VERSION 5.8 ;
BUSBITCHARS "[]" ;
DIVIDERCHAR "/" ;
UNITS
    DATABASE MICRONS 1000 ;
END UNITS

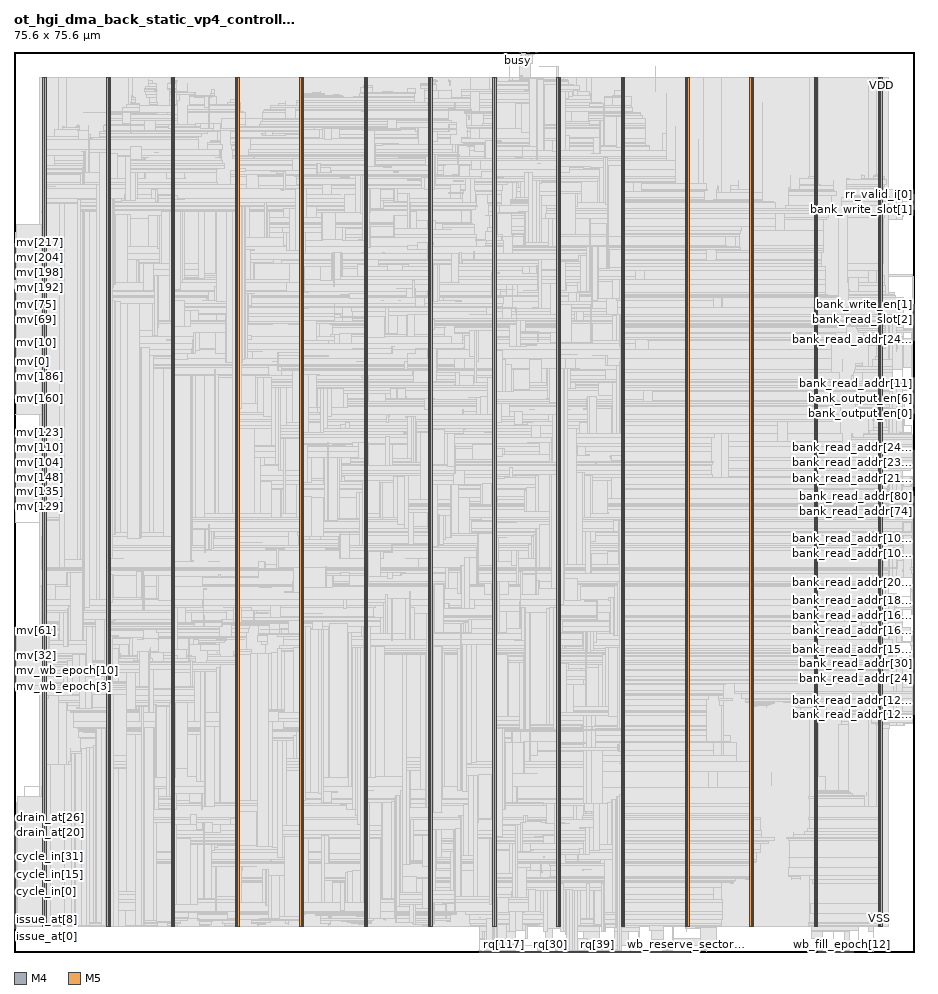
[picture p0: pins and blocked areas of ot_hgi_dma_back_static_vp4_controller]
MACRO ot_hgi_dma_back_static_vp4_controller
  FOREIGN ot_hgi_dma_back_static_vp4_controller 0 0 ;
  CLASS BLOCK ;
  SIZE 75.6 BY 75.6 ;
  PIN bank_output_en[0]
    DIRECTION OUTPUT ;
    USE SIGNAL ;
    PORT
      LAYER M4 ;
        RECT  75.516 45.264 75.6 45.288 ;
    END
  END bank_output_en[0]
  PIN bank_output_en[1]
    DIRECTION OUTPUT ;
    USE SIGNAL ;
    PORT
      LAYER M4 ;
        RECT  75.516 45.36 75.6 45.384 ;
    END
  END bank_output_en[1]
  PIN bank_output_en[2]
    DIRECTION OUTPUT ;
    USE SIGNAL ;
    PORT
      LAYER M4 ;
        RECT  75.516 45.456 75.6 45.48 ;
    END
  END bank_output_en[2]
  PIN bank_output_en[3]
    DIRECTION OUTPUT ;
    USE SIGNAL ;
    PORT
      LAYER M4 ;
        RECT  75.516 45.552 75.6 45.576 ;
    END
  END bank_output_en[3]
  PIN bank_output_en[4]
    DIRECTION OUTPUT ;
    USE SIGNAL ;
    PORT
      LAYER M4 ;
        RECT  75.516 45.648 75.6 45.672 ;
    END
  END bank_output_en[4]
  PIN bank_output_en[5]
    DIRECTION OUTPUT ;
    USE SIGNAL ;
    PORT
      LAYER M4 ;
        RECT  75.516 45.744 75.6 45.768 ;
    END
  END bank_output_en[5]
  PIN bank_output_en[6]
    DIRECTION OUTPUT ;
    USE SIGNAL ;
    PORT
      LAYER M4 ;
        RECT  75.516 45.84 75.6 45.864 ;
    END
  END bank_output_en[6]
  PIN bank_output_en[7]
    DIRECTION OUTPUT ;
    USE SIGNAL ;
    PORT
      LAYER M4 ;
        RECT  75.516 45.936 75.6 45.96 ;
    END
  END bank_output_en[7]
  PIN bank_read_addr[0]
    DIRECTION OUTPUT ;
    USE SIGNAL ;
    PORT
      LAYER M4 ;
        RECT  75.516 46.032 75.6 46.056 ;
    END
  END bank_read_addr[0]
  PIN bank_read_addr[100]
    DIRECTION OUTPUT ;
    USE SIGNAL ;
    PORT
      LAYER M4 ;
        RECT  75.516 33.36 75.6 33.384 ;
    END
  END bank_read_addr[100]
  PIN bank_read_addr[101]
    DIRECTION OUTPUT ;
    USE SIGNAL ;
    PORT
      LAYER M4 ;
        RECT  75.516 33.456 75.6 33.48 ;
    END
  END bank_read_addr[101]
  PIN bank_read_addr[102]
    DIRECTION OUTPUT ;
    USE SIGNAL ;
    PORT
      LAYER M4 ;
        RECT  75.516 33.552 75.6 33.576 ;
    END
  END bank_read_addr[102]
  PIN bank_read_addr[103]
    DIRECTION OUTPUT ;
    USE SIGNAL ;
    PORT
      LAYER M4 ;
        RECT  75.516 33.648 75.6 33.672 ;
    END
  END bank_read_addr[103]
  PIN bank_read_addr[104]
    DIRECTION OUTPUT ;
    USE SIGNAL ;
    PORT
      LAYER M4 ;
        RECT  75.516 33.744 75.6 33.768 ;
    END
  END bank_read_addr[104]
  PIN bank_read_addr[105]
    DIRECTION OUTPUT ;
    USE SIGNAL ;
    PORT
      LAYER M4 ;
        RECT  75.516 33.84 75.6 33.864 ;
    END
  END bank_read_addr[105]
  PIN bank_read_addr[106]
    DIRECTION OUTPUT ;
    USE SIGNAL ;
    PORT
      LAYER M4 ;
        RECT  75.516 33.936 75.6 33.96 ;
    END
  END bank_read_addr[106]
  PIN bank_read_addr[107]
    DIRECTION OUTPUT ;
    USE SIGNAL ;
    PORT
      LAYER M4 ;
        RECT  75.516 34.032 75.6 34.056 ;
    END
  END bank_read_addr[107]
  PIN bank_read_addr[108]
    DIRECTION OUTPUT ;
    USE SIGNAL ;
    PORT
      LAYER M4 ;
        RECT  75.516 34.128 75.6 34.152 ;
    END
  END bank_read_addr[108]
  PIN bank_read_addr[109]
    DIRECTION OUTPUT ;
    USE SIGNAL ;
    PORT
      LAYER M4 ;
        RECT  75.516 34.224 75.6 34.248 ;
    END
  END bank_read_addr[109]
  PIN bank_read_addr[10]
    DIRECTION OUTPUT ;
    USE SIGNAL ;
    PORT
      LAYER M4 ;
        RECT  75.516 46.992 75.6 47.016 ;
    END
  END bank_read_addr[10]
  PIN bank_read_addr[110]
    DIRECTION OUTPUT ;
    USE SIGNAL ;
    PORT
      LAYER M4 ;
        RECT  75.516 34.32 75.6 34.344 ;
    END
  END bank_read_addr[110]
  PIN bank_read_addr[111]
    DIRECTION OUTPUT ;
    USE SIGNAL ;
    PORT
      LAYER M4 ;
        RECT  75.516 34.416 75.6 34.44 ;
    END
  END bank_read_addr[111]
  PIN bank_read_addr[112]
    DIRECTION OUTPUT ;
    USE SIGNAL ;
    PORT
      LAYER M4 ;
        RECT  75.516 34.512 75.6 34.536 ;
    END
  END bank_read_addr[112]
  PIN bank_read_addr[113]
    DIRECTION OUTPUT ;
    USE SIGNAL ;
    PORT
      LAYER M4 ;
        RECT  75.516 34.608 75.6 34.632 ;
    END
  END bank_read_addr[113]
  PIN bank_read_addr[114]
    DIRECTION OUTPUT ;
    USE SIGNAL ;
    PORT
      LAYER M4 ;
        RECT  75.516 34.704 75.6 34.728 ;
    END
  END bank_read_addr[114]
  PIN bank_read_addr[115]
    DIRECTION OUTPUT ;
    USE SIGNAL ;
    PORT
      LAYER M4 ;
        RECT  75.516 34.8 75.6 34.824 ;
    END
  END bank_read_addr[115]
  PIN bank_read_addr[116]
    DIRECTION OUTPUT ;
    USE SIGNAL ;
    PORT
      LAYER M4 ;
        RECT  75.516 34.896 75.6 34.92 ;
    END
  END bank_read_addr[116]
  PIN bank_read_addr[117]
    DIRECTION OUTPUT ;
    USE SIGNAL ;
    PORT
      LAYER M4 ;
        RECT  75.516 34.992 75.6 35.016 ;
    END
  END bank_read_addr[117]
  PIN bank_read_addr[118]
    DIRECTION OUTPUT ;
    USE SIGNAL ;
    PORT
      LAYER M4 ;
        RECT  75.516 35.088 75.6 35.112 ;
    END
  END bank_read_addr[118]
  PIN bank_read_addr[119]
    DIRECTION OUTPUT ;
    USE SIGNAL ;
    PORT
      LAYER M4 ;
        RECT  75.516 35.184 75.6 35.208 ;
    END
  END bank_read_addr[119]
  PIN bank_read_addr[11]
    DIRECTION OUTPUT ;
    USE SIGNAL ;
    PORT
      LAYER M4 ;
        RECT  75.516 47.088 75.6 47.112 ;
    END
  END bank_read_addr[11]
  PIN bank_read_addr[120]
    DIRECTION OUTPUT ;
    USE SIGNAL ;
    PORT
      LAYER M4 ;
        RECT  75.516 19.92 75.6 19.944 ;
    END
  END bank_read_addr[120]
  PIN bank_read_addr[121]
    DIRECTION OUTPUT ;
    USE SIGNAL ;
    PORT
      LAYER M4 ;
        RECT  75.516 20.016 75.6 20.04 ;
    END
  END bank_read_addr[121]
  PIN bank_read_addr[122]
    DIRECTION OUTPUT ;
    USE SIGNAL ;
    PORT
      LAYER M4 ;
        RECT  75.516 20.112 75.6 20.136 ;
    END
  END bank_read_addr[122]
  PIN bank_read_addr[123]
    DIRECTION OUTPUT ;
    USE SIGNAL ;
    PORT
      LAYER M4 ;
        RECT  75.516 20.208 75.6 20.232 ;
    END
  END bank_read_addr[123]
  PIN bank_read_addr[124]
    DIRECTION OUTPUT ;
    USE SIGNAL ;
    PORT
      LAYER M4 ;
        RECT  75.516 20.304 75.6 20.328 ;
    END
  END bank_read_addr[124]
  PIN bank_read_addr[125]
    DIRECTION OUTPUT ;
    USE SIGNAL ;
    PORT
      LAYER M4 ;
        RECT  75.516 20.4 75.6 20.424 ;
    END
  END bank_read_addr[125]
  PIN bank_read_addr[126]
    DIRECTION OUTPUT ;
    USE SIGNAL ;
    PORT
      LAYER M4 ;
        RECT  75.516 20.496 75.6 20.52 ;
    END
  END bank_read_addr[126]
  PIN bank_read_addr[127]
    DIRECTION OUTPUT ;
    USE SIGNAL ;
    PORT
      LAYER M4 ;
        RECT  75.516 20.592 75.6 20.616 ;
    END
  END bank_read_addr[127]
  PIN bank_read_addr[128]
    DIRECTION OUTPUT ;
    USE SIGNAL ;
    PORT
      LAYER M4 ;
        RECT  75.516 20.688 75.6 20.712 ;
    END
  END bank_read_addr[128]
  PIN bank_read_addr[129]
    DIRECTION OUTPUT ;
    USE SIGNAL ;
    PORT
      LAYER M4 ;
        RECT  75.516 20.784 75.6 20.808 ;
    END
  END bank_read_addr[129]
  PIN bank_read_addr[12]
    DIRECTION OUTPUT ;
    USE SIGNAL ;
    PORT
      LAYER M4 ;
        RECT  75.516 47.184 75.6 47.208 ;
    END
  END bank_read_addr[12]
  PIN bank_read_addr[130]
    DIRECTION OUTPUT ;
    USE SIGNAL ;
    PORT
      LAYER M4 ;
        RECT  75.516 20.88 75.6 20.904 ;
    END
  END bank_read_addr[130]
  PIN bank_read_addr[131]
    DIRECTION OUTPUT ;
    USE SIGNAL ;
    PORT
      LAYER M4 ;
        RECT  75.516 20.976 75.6 21 ;
    END
  END bank_read_addr[131]
  PIN bank_read_addr[132]
    DIRECTION OUTPUT ;
    USE SIGNAL ;
    PORT
      LAYER M4 ;
        RECT  75.516 21.072 75.6 21.096 ;
    END
  END bank_read_addr[132]
  PIN bank_read_addr[133]
    DIRECTION OUTPUT ;
    USE SIGNAL ;
    PORT
      LAYER M4 ;
        RECT  75.516 21.168 75.6 21.192 ;
    END
  END bank_read_addr[133]
  PIN bank_read_addr[134]
    DIRECTION OUTPUT ;
    USE SIGNAL ;
    PORT
      LAYER M4 ;
        RECT  75.516 21.264 75.6 21.288 ;
    END
  END bank_read_addr[134]
  PIN bank_read_addr[135]
    DIRECTION OUTPUT ;
    USE SIGNAL ;
    PORT
      LAYER M4 ;
        RECT  75.516 21.36 75.6 21.384 ;
    END
  END bank_read_addr[135]
  PIN bank_read_addr[136]
    DIRECTION OUTPUT ;
    USE SIGNAL ;
    PORT
      LAYER M4 ;
        RECT  75.516 21.456 75.6 21.48 ;
    END
  END bank_read_addr[136]
  PIN bank_read_addr[137]
    DIRECTION OUTPUT ;
    USE SIGNAL ;
    PORT
      LAYER M4 ;
        RECT  75.516 21.552 75.6 21.576 ;
    END
  END bank_read_addr[137]
  PIN bank_read_addr[138]
    DIRECTION OUTPUT ;
    USE SIGNAL ;
    PORT
      LAYER M4 ;
        RECT  75.516 21.648 75.6 21.672 ;
    END
  END bank_read_addr[138]
  PIN bank_read_addr[139]
    DIRECTION OUTPUT ;
    USE SIGNAL ;
    PORT
      LAYER M4 ;
        RECT  75.516 21.744 75.6 21.768 ;
    END
  END bank_read_addr[139]
  PIN bank_read_addr[13]
    DIRECTION OUTPUT ;
    USE SIGNAL ;
    PORT
      LAYER M4 ;
        RECT  75.516 47.28 75.6 47.304 ;
    END
  END bank_read_addr[13]
  PIN bank_read_addr[140]
    DIRECTION OUTPUT ;
    USE SIGNAL ;
    PORT
      LAYER M4 ;
        RECT  75.516 21.84 75.6 21.864 ;
    END
  END bank_read_addr[140]
  PIN bank_read_addr[141]
    DIRECTION OUTPUT ;
    USE SIGNAL ;
    PORT
      LAYER M4 ;
        RECT  75.516 21.936 75.6 21.96 ;
    END
  END bank_read_addr[141]
  PIN bank_read_addr[142]
    DIRECTION OUTPUT ;
    USE SIGNAL ;
    PORT
      LAYER M4 ;
        RECT  75.516 22.032 75.6 22.056 ;
    END
  END bank_read_addr[142]
  PIN bank_read_addr[143]
    DIRECTION OUTPUT ;
    USE SIGNAL ;
    PORT
      LAYER M4 ;
        RECT  75.516 22.128 75.6 22.152 ;
    END
  END bank_read_addr[143]
  PIN bank_read_addr[144]
    DIRECTION OUTPUT ;
    USE SIGNAL ;
    PORT
      LAYER M4 ;
        RECT  75.516 22.224 75.6 22.248 ;
    END
  END bank_read_addr[144]
  PIN bank_read_addr[145]
    DIRECTION OUTPUT ;
    USE SIGNAL ;
    PORT
      LAYER M4 ;
        RECT  75.516 22.32 75.6 22.344 ;
    END
  END bank_read_addr[145]
  PIN bank_read_addr[146]
    DIRECTION OUTPUT ;
    USE SIGNAL ;
    PORT
      LAYER M4 ;
        RECT  75.516 22.416 75.6 22.44 ;
    END
  END bank_read_addr[146]
  PIN bank_read_addr[147]
    DIRECTION OUTPUT ;
    USE SIGNAL ;
    PORT
      LAYER M4 ;
        RECT  75.516 22.512 75.6 22.536 ;
    END
  END bank_read_addr[147]
  PIN bank_read_addr[148]
    DIRECTION OUTPUT ;
    USE SIGNAL ;
    PORT
      LAYER M4 ;
        RECT  75.516 22.608 75.6 22.632 ;
    END
  END bank_read_addr[148]
  PIN bank_read_addr[149]
    DIRECTION OUTPUT ;
    USE SIGNAL ;
    PORT
      LAYER M4 ;
        RECT  75.516 22.704 75.6 22.728 ;
    END
  END bank_read_addr[149]
  PIN bank_read_addr[14]
    DIRECTION OUTPUT ;
    USE SIGNAL ;
    PORT
      LAYER M4 ;
        RECT  75.516 47.376 75.6 47.4 ;
    END
  END bank_read_addr[14]
  PIN bank_read_addr[150]
    DIRECTION OUTPUT ;
    USE SIGNAL ;
    PORT
      LAYER M4 ;
        RECT  75.516 22.8 75.6 22.824 ;
    END
  END bank_read_addr[150]
  PIN bank_read_addr[151]
    DIRECTION OUTPUT ;
    USE SIGNAL ;
    PORT
      LAYER M4 ;
        RECT  75.516 22.896 75.6 22.92 ;
    END
  END bank_read_addr[151]
  PIN bank_read_addr[152]
    DIRECTION OUTPUT ;
    USE SIGNAL ;
    PORT
      LAYER M4 ;
        RECT  75.516 26.064 75.6 26.088 ;
    END
  END bank_read_addr[152]
  PIN bank_read_addr[153]
    DIRECTION OUTPUT ;
    USE SIGNAL ;
    PORT
      LAYER M4 ;
        RECT  75.516 26.16 75.6 26.184 ;
    END
  END bank_read_addr[153]
  PIN bank_read_addr[154]
    DIRECTION OUTPUT ;
    USE SIGNAL ;
    PORT
      LAYER M4 ;
        RECT  75.516 26.256 75.6 26.28 ;
    END
  END bank_read_addr[154]
  PIN bank_read_addr[155]
    DIRECTION OUTPUT ;
    USE SIGNAL ;
    PORT
      LAYER M4 ;
        RECT  75.516 26.352 75.6 26.376 ;
    END
  END bank_read_addr[155]
  PIN bank_read_addr[156]
    DIRECTION OUTPUT ;
    USE SIGNAL ;
    PORT
      LAYER M4 ;
        RECT  75.516 26.448 75.6 26.472 ;
    END
  END bank_read_addr[156]
  PIN bank_read_addr[157]
    DIRECTION OUTPUT ;
    USE SIGNAL ;
    PORT
      LAYER M4 ;
        RECT  75.516 26.544 75.6 26.568 ;
    END
  END bank_read_addr[157]
  PIN bank_read_addr[158]
    DIRECTION OUTPUT ;
    USE SIGNAL ;
    PORT
      LAYER M4 ;
        RECT  75.516 26.64 75.6 26.664 ;
    END
  END bank_read_addr[158]
  PIN bank_read_addr[159]
    DIRECTION OUTPUT ;
    USE SIGNAL ;
    PORT
      LAYER M4 ;
        RECT  75.516 26.736 75.6 26.76 ;
    END
  END bank_read_addr[159]
  PIN bank_read_addr[15]
    DIRECTION OUTPUT ;
    USE SIGNAL ;
    PORT
      LAYER M4 ;
        RECT  75.516 47.472 75.6 47.496 ;
    END
  END bank_read_addr[15]
  PIN bank_read_addr[160]
    DIRECTION OUTPUT ;
    USE SIGNAL ;
    PORT
      LAYER M4 ;
        RECT  75.516 26.832 75.6 26.856 ;
    END
  END bank_read_addr[160]
  PIN bank_read_addr[161]
    DIRECTION OUTPUT ;
    USE SIGNAL ;
    PORT
      LAYER M4 ;
        RECT  75.516 26.928 75.6 26.952 ;
    END
  END bank_read_addr[161]
  PIN bank_read_addr[162]
    DIRECTION OUTPUT ;
    USE SIGNAL ;
    PORT
      LAYER M4 ;
        RECT  75.516 27.024 75.6 27.048 ;
    END
  END bank_read_addr[162]
  PIN bank_read_addr[163]
    DIRECTION OUTPUT ;
    USE SIGNAL ;
    PORT
      LAYER M4 ;
        RECT  75.516 27.12 75.6 27.144 ;
    END
  END bank_read_addr[163]
  PIN bank_read_addr[164]
    DIRECTION OUTPUT ;
    USE SIGNAL ;
    PORT
      LAYER M4 ;
        RECT  75.516 27.216 75.6 27.24 ;
    END
  END bank_read_addr[164]
  PIN bank_read_addr[165]
    DIRECTION OUTPUT ;
    USE SIGNAL ;
    PORT
      LAYER M4 ;
        RECT  75.516 27.312 75.6 27.336 ;
    END
  END bank_read_addr[165]
  PIN bank_read_addr[166]
    DIRECTION OUTPUT ;
    USE SIGNAL ;
    PORT
      LAYER M4 ;
        RECT  75.516 27.408 75.6 27.432 ;
    END
  END bank_read_addr[166]
  PIN bank_read_addr[167]
    DIRECTION OUTPUT ;
    USE SIGNAL ;
    PORT
      LAYER M4 ;
        RECT  75.516 27.504 75.6 27.528 ;
    END
  END bank_read_addr[167]
  PIN bank_read_addr[168]
    DIRECTION OUTPUT ;
    USE SIGNAL ;
    PORT
      LAYER M4 ;
        RECT  75.516 27.6 75.6 27.624 ;
    END
  END bank_read_addr[168]
  PIN bank_read_addr[169]
    DIRECTION OUTPUT ;
    USE SIGNAL ;
    PORT
      LAYER M4 ;
        RECT  75.516 27.696 75.6 27.72 ;
    END
  END bank_read_addr[169]
  PIN bank_read_addr[16]
    DIRECTION OUTPUT ;
    USE SIGNAL ;
    PORT
      LAYER M4 ;
        RECT  75.516 47.568 75.6 47.592 ;
    END
  END bank_read_addr[16]
  PIN bank_read_addr[170]
    DIRECTION OUTPUT ;
    USE SIGNAL ;
    PORT
      LAYER M4 ;
        RECT  75.516 27.792 75.6 27.816 ;
    END
  END bank_read_addr[170]
  PIN bank_read_addr[171]
    DIRECTION OUTPUT ;
    USE SIGNAL ;
    PORT
      LAYER M4 ;
        RECT  75.516 27.888 75.6 27.912 ;
    END
  END bank_read_addr[171]
  PIN bank_read_addr[172]
    DIRECTION OUTPUT ;
    USE SIGNAL ;
    PORT
      LAYER M4 ;
        RECT  75.516 27.984 75.6 28.008 ;
    END
  END bank_read_addr[172]
  PIN bank_read_addr[173]
    DIRECTION OUTPUT ;
    USE SIGNAL ;
    PORT
      LAYER M4 ;
        RECT  75.516 28.08 75.6 28.104 ;
    END
  END bank_read_addr[173]
  PIN bank_read_addr[174]
    DIRECTION OUTPUT ;
    USE SIGNAL ;
    PORT
      LAYER M4 ;
        RECT  75.516 28.176 75.6 28.2 ;
    END
  END bank_read_addr[174]
  PIN bank_read_addr[175]
    DIRECTION OUTPUT ;
    USE SIGNAL ;
    PORT
      LAYER M4 ;
        RECT  75.516 28.272 75.6 28.296 ;
    END
  END bank_read_addr[175]
  PIN bank_read_addr[176]
    DIRECTION OUTPUT ;
    USE SIGNAL ;
    PORT
      LAYER M4 ;
        RECT  75.516 28.368 75.6 28.392 ;
    END
  END bank_read_addr[176]
  PIN bank_read_addr[177]
    DIRECTION OUTPUT ;
    USE SIGNAL ;
    PORT
      LAYER M4 ;
        RECT  75.516 28.464 75.6 28.488 ;
    END
  END bank_read_addr[177]
  PIN bank_read_addr[178]
    DIRECTION OUTPUT ;
    USE SIGNAL ;
    PORT
      LAYER M4 ;
        RECT  75.516 28.56 75.6 28.584 ;
    END
  END bank_read_addr[178]
  PIN bank_read_addr[179]
    DIRECTION OUTPUT ;
    USE SIGNAL ;
    PORT
      LAYER M4 ;
        RECT  75.516 28.656 75.6 28.68 ;
    END
  END bank_read_addr[179]
  PIN bank_read_addr[17]
    DIRECTION OUTPUT ;
    USE SIGNAL ;
    PORT
      LAYER M4 ;
        RECT  75.516 47.664 75.6 47.688 ;
    END
  END bank_read_addr[17]
  PIN bank_read_addr[180]
    DIRECTION OUTPUT ;
    USE SIGNAL ;
    PORT
      LAYER M4 ;
        RECT  75.516 28.752 75.6 28.776 ;
    END
  END bank_read_addr[180]
  PIN bank_read_addr[181]
    DIRECTION OUTPUT ;
    USE SIGNAL ;
    PORT
      LAYER M4 ;
        RECT  75.516 28.848 75.6 28.872 ;
    END
  END bank_read_addr[181]
  PIN bank_read_addr[182]
    DIRECTION OUTPUT ;
    USE SIGNAL ;
    PORT
      LAYER M4 ;
        RECT  75.516 28.944 75.6 28.968 ;
    END
  END bank_read_addr[182]
  PIN bank_read_addr[183]
    DIRECTION OUTPUT ;
    USE SIGNAL ;
    PORT
      LAYER M4 ;
        RECT  75.516 29.04 75.6 29.064 ;
    END
  END bank_read_addr[183]
  PIN bank_read_addr[184]
    DIRECTION OUTPUT ;
    USE SIGNAL ;
    PORT
      LAYER M4 ;
        RECT  75.516 29.136 75.6 29.16 ;
    END
  END bank_read_addr[184]
  PIN bank_read_addr[185]
    DIRECTION OUTPUT ;
    USE SIGNAL ;
    PORT
      LAYER M4 ;
        RECT  75.516 29.232 75.6 29.256 ;
    END
  END bank_read_addr[185]
  PIN bank_read_addr[186]
    DIRECTION OUTPUT ;
    USE SIGNAL ;
    PORT
      LAYER M4 ;
        RECT  75.516 29.328 75.6 29.352 ;
    END
  END bank_read_addr[186]
  PIN bank_read_addr[187]
    DIRECTION OUTPUT ;
    USE SIGNAL ;
    PORT
      LAYER M4 ;
        RECT  75.516 29.424 75.6 29.448 ;
    END
  END bank_read_addr[187]
  PIN bank_read_addr[188]
    DIRECTION OUTPUT ;
    USE SIGNAL ;
    PORT
      LAYER M4 ;
        RECT  75.516 29.52 75.6 29.544 ;
    END
  END bank_read_addr[188]
  PIN bank_read_addr[189]
    DIRECTION OUTPUT ;
    USE SIGNAL ;
    PORT
      LAYER M4 ;
        RECT  75.516 29.616 75.6 29.64 ;
    END
  END bank_read_addr[189]
  PIN bank_read_addr[18]
    DIRECTION OUTPUT ;
    USE SIGNAL ;
    PORT
      LAYER M4 ;
        RECT  75.516 47.76 75.6 47.784 ;
    END
  END bank_read_addr[18]
  PIN bank_read_addr[190]
    DIRECTION OUTPUT ;
    USE SIGNAL ;
    PORT
      LAYER M4 ;
        RECT  75.516 29.712 75.6 29.736 ;
    END
  END bank_read_addr[190]
  PIN bank_read_addr[191]
    DIRECTION OUTPUT ;
    USE SIGNAL ;
    PORT
      LAYER M4 ;
        RECT  75.516 29.808 75.6 29.832 ;
    END
  END bank_read_addr[191]
  PIN bank_read_addr[192]
    DIRECTION OUTPUT ;
    USE SIGNAL ;
    PORT
      LAYER M4 ;
        RECT  75.516 29.904 75.6 29.928 ;
    END
  END bank_read_addr[192]
  PIN bank_read_addr[193]
    DIRECTION OUTPUT ;
    USE SIGNAL ;
    PORT
      LAYER M4 ;
        RECT  75.516 30 75.6 30.024 ;
    END
  END bank_read_addr[193]
  PIN bank_read_addr[194]
    DIRECTION OUTPUT ;
    USE SIGNAL ;
    PORT
      LAYER M4 ;
        RECT  75.516 30.096 75.6 30.12 ;
    END
  END bank_read_addr[194]
  PIN bank_read_addr[195]
    DIRECTION OUTPUT ;
    USE SIGNAL ;
    PORT
      LAYER M4 ;
        RECT  75.516 30.192 75.6 30.216 ;
    END
  END bank_read_addr[195]
  PIN bank_read_addr[196]
    DIRECTION OUTPUT ;
    USE SIGNAL ;
    PORT
      LAYER M4 ;
        RECT  75.516 30.288 75.6 30.312 ;
    END
  END bank_read_addr[196]
  PIN bank_read_addr[197]
    DIRECTION OUTPUT ;
    USE SIGNAL ;
    PORT
      LAYER M4 ;
        RECT  75.516 30.384 75.6 30.408 ;
    END
  END bank_read_addr[197]
  PIN bank_read_addr[198]
    DIRECTION OUTPUT ;
    USE SIGNAL ;
    PORT
      LAYER M4 ;
        RECT  75.516 30.48 75.6 30.504 ;
    END
  END bank_read_addr[198]
  PIN bank_read_addr[199]
    DIRECTION OUTPUT ;
    USE SIGNAL ;
    PORT
      LAYER M4 ;
        RECT  75.516 30.576 75.6 30.6 ;
    END
  END bank_read_addr[199]
  PIN bank_read_addr[19]
    DIRECTION OUTPUT ;
    USE SIGNAL ;
    PORT
      LAYER M4 ;
        RECT  75.516 47.856 75.6 47.88 ;
    END
  END bank_read_addr[19]
  PIN bank_read_addr[1]
    DIRECTION OUTPUT ;
    USE SIGNAL ;
    PORT
      LAYER M4 ;
        RECT  75.516 46.128 75.6 46.152 ;
    END
  END bank_read_addr[1]
  PIN bank_read_addr[200]
    DIRECTION OUTPUT ;
    USE SIGNAL ;
    PORT
      LAYER M4 ;
        RECT  75.516 30.672 75.6 30.696 ;
    END
  END bank_read_addr[200]
  PIN bank_read_addr[201]
    DIRECTION OUTPUT ;
    USE SIGNAL ;
    PORT
      LAYER M4 ;
        RECT  75.516 30.768 75.6 30.792 ;
    END
  END bank_read_addr[201]
  PIN bank_read_addr[202]
    DIRECTION OUTPUT ;
    USE SIGNAL ;
    PORT
      LAYER M4 ;
        RECT  75.516 30.864 75.6 30.888 ;
    END
  END bank_read_addr[202]
  PIN bank_read_addr[203]
    DIRECTION OUTPUT ;
    USE SIGNAL ;
    PORT
      LAYER M4 ;
        RECT  75.516 30.96 75.6 30.984 ;
    END
  END bank_read_addr[203]
  PIN bank_read_addr[204]
    DIRECTION OUTPUT ;
    USE SIGNAL ;
    PORT
      LAYER M4 ;
        RECT  75.516 31.056 75.6 31.08 ;
    END
  END bank_read_addr[204]
  PIN bank_read_addr[205]
    DIRECTION OUTPUT ;
    USE SIGNAL ;
    PORT
      LAYER M4 ;
        RECT  75.516 31.152 75.6 31.176 ;
    END
  END bank_read_addr[205]
  PIN bank_read_addr[206]
    DIRECTION OUTPUT ;
    USE SIGNAL ;
    PORT
      LAYER M4 ;
        RECT  75.516 31.248 75.6 31.272 ;
    END
  END bank_read_addr[206]
  PIN bank_read_addr[207]
    DIRECTION OUTPUT ;
    USE SIGNAL ;
    PORT
      LAYER M4 ;
        RECT  75.516 31.344 75.6 31.368 ;
    END
  END bank_read_addr[207]
  PIN bank_read_addr[208]
    DIRECTION OUTPUT ;
    USE SIGNAL ;
    PORT
      LAYER M4 ;
        RECT  75.516 31.44 75.6 31.464 ;
    END
  END bank_read_addr[208]
  PIN bank_read_addr[209]
    DIRECTION OUTPUT ;
    USE SIGNAL ;
    PORT
      LAYER M4 ;
        RECT  75.516 31.536 75.6 31.56 ;
    END
  END bank_read_addr[209]
  PIN bank_read_addr[20]
    DIRECTION OUTPUT ;
    USE SIGNAL ;
    PORT
      LAYER M4 ;
        RECT  75.516 47.952 75.6 47.976 ;
    END
  END bank_read_addr[20]
  PIN bank_read_addr[210]
    DIRECTION OUTPUT ;
    USE SIGNAL ;
    PORT
      LAYER M4 ;
        RECT  75.516 31.632 75.6 31.656 ;
    END
  END bank_read_addr[210]
  PIN bank_read_addr[211]
    DIRECTION OUTPUT ;
    USE SIGNAL ;
    PORT
      LAYER M4 ;
        RECT  75.516 31.728 75.6 31.752 ;
    END
  END bank_read_addr[211]
  PIN bank_read_addr[212]
    DIRECTION OUTPUT ;
    USE SIGNAL ;
    PORT
      LAYER M4 ;
        RECT  75.516 31.824 75.6 31.848 ;
    END
  END bank_read_addr[212]
  PIN bank_read_addr[213]
    DIRECTION OUTPUT ;
    USE SIGNAL ;
    PORT
      LAYER M4 ;
        RECT  75.516 31.92 75.6 31.944 ;
    END
  END bank_read_addr[213]
  PIN bank_read_addr[214]
    DIRECTION OUTPUT ;
    USE SIGNAL ;
    PORT
      LAYER M4 ;
        RECT  75.516 32.016 75.6 32.04 ;
    END
  END bank_read_addr[214]
  PIN bank_read_addr[215]
    DIRECTION OUTPUT ;
    USE SIGNAL ;
    PORT
      LAYER M4 ;
        RECT  75.516 32.112 75.6 32.136 ;
    END
  END bank_read_addr[215]
  PIN bank_read_addr[216]
    DIRECTION OUTPUT ;
    USE SIGNAL ;
    PORT
      LAYER M4 ;
        RECT  75.516 39.12 75.6 39.144 ;
    END
  END bank_read_addr[216]
  PIN bank_read_addr[217]
    DIRECTION OUTPUT ;
    USE SIGNAL ;
    PORT
      LAYER M4 ;
        RECT  75.516 39.216 75.6 39.24 ;
    END
  END bank_read_addr[217]
  PIN bank_read_addr[218]
    DIRECTION OUTPUT ;
    USE SIGNAL ;
    PORT
      LAYER M4 ;
        RECT  75.516 39.312 75.6 39.336 ;
    END
  END bank_read_addr[218]
  PIN bank_read_addr[219]
    DIRECTION OUTPUT ;
    USE SIGNAL ;
    PORT
      LAYER M4 ;
        RECT  75.516 39.408 75.6 39.432 ;
    END
  END bank_read_addr[219]
  PIN bank_read_addr[21]
    DIRECTION OUTPUT ;
    USE SIGNAL ;
    PORT
      LAYER M4 ;
        RECT  75.516 48.048 75.6 48.072 ;
    END
  END bank_read_addr[21]
  PIN bank_read_addr[220]
    DIRECTION OUTPUT ;
    USE SIGNAL ;
    PORT
      LAYER M4 ;
        RECT  75.516 39.504 75.6 39.528 ;
    END
  END bank_read_addr[220]
  PIN bank_read_addr[221]
    DIRECTION OUTPUT ;
    USE SIGNAL ;
    PORT
      LAYER M4 ;
        RECT  75.516 39.6 75.6 39.624 ;
    END
  END bank_read_addr[221]
  PIN bank_read_addr[222]
    DIRECTION OUTPUT ;
    USE SIGNAL ;
    PORT
      LAYER M4 ;
        RECT  75.516 39.696 75.6 39.72 ;
    END
  END bank_read_addr[222]
  PIN bank_read_addr[223]
    DIRECTION OUTPUT ;
    USE SIGNAL ;
    PORT
      LAYER M4 ;
        RECT  75.516 39.792 75.6 39.816 ;
    END
  END bank_read_addr[223]
  PIN bank_read_addr[224]
    DIRECTION OUTPUT ;
    USE SIGNAL ;
    PORT
      LAYER M4 ;
        RECT  75.516 39.888 75.6 39.912 ;
    END
  END bank_read_addr[224]
  PIN bank_read_addr[225]
    DIRECTION OUTPUT ;
    USE SIGNAL ;
    PORT
      LAYER M4 ;
        RECT  75.516 39.984 75.6 40.008 ;
    END
  END bank_read_addr[225]
  PIN bank_read_addr[226]
    DIRECTION OUTPUT ;
    USE SIGNAL ;
    PORT
      LAYER M4 ;
        RECT  75.516 40.08 75.6 40.104 ;
    END
  END bank_read_addr[226]
  PIN bank_read_addr[227]
    DIRECTION OUTPUT ;
    USE SIGNAL ;
    PORT
      LAYER M4 ;
        RECT  75.516 40.176 75.6 40.2 ;
    END
  END bank_read_addr[227]
  PIN bank_read_addr[228]
    DIRECTION OUTPUT ;
    USE SIGNAL ;
    PORT
      LAYER M4 ;
        RECT  75.516 40.272 75.6 40.296 ;
    END
  END bank_read_addr[228]
  PIN bank_read_addr[229]
    DIRECTION OUTPUT ;
    USE SIGNAL ;
    PORT
      LAYER M4 ;
        RECT  75.516 40.368 75.6 40.392 ;
    END
  END bank_read_addr[229]
  PIN bank_read_addr[22]
    DIRECTION OUTPUT ;
    USE SIGNAL ;
    PORT
      LAYER M4 ;
        RECT  75.516 48.144 75.6 48.168 ;
    END
  END bank_read_addr[22]
  PIN bank_read_addr[230]
    DIRECTION OUTPUT ;
    USE SIGNAL ;
    PORT
      LAYER M4 ;
        RECT  75.516 40.464 75.6 40.488 ;
    END
  END bank_read_addr[230]
  PIN bank_read_addr[231]
    DIRECTION OUTPUT ;
    USE SIGNAL ;
    PORT
      LAYER M4 ;
        RECT  75.516 40.56 75.6 40.584 ;
    END
  END bank_read_addr[231]
  PIN bank_read_addr[232]
    DIRECTION OUTPUT ;
    USE SIGNAL ;
    PORT
      LAYER M4 ;
        RECT  75.516 40.656 75.6 40.68 ;
    END
  END bank_read_addr[232]
  PIN bank_read_addr[233]
    DIRECTION OUTPUT ;
    USE SIGNAL ;
    PORT
      LAYER M4 ;
        RECT  75.516 40.752 75.6 40.776 ;
    END
  END bank_read_addr[233]
  PIN bank_read_addr[234]
    DIRECTION OUTPUT ;
    USE SIGNAL ;
    PORT
      LAYER M4 ;
        RECT  75.516 40.848 75.6 40.872 ;
    END
  END bank_read_addr[234]
  PIN bank_read_addr[235]
    DIRECTION OUTPUT ;
    USE SIGNAL ;
    PORT
      LAYER M4 ;
        RECT  75.516 40.944 75.6 40.968 ;
    END
  END bank_read_addr[235]
  PIN bank_read_addr[236]
    DIRECTION OUTPUT ;
    USE SIGNAL ;
    PORT
      LAYER M4 ;
        RECT  75.516 41.04 75.6 41.064 ;
    END
  END bank_read_addr[236]
  PIN bank_read_addr[237]
    DIRECTION OUTPUT ;
    USE SIGNAL ;
    PORT
      LAYER M4 ;
        RECT  75.516 41.136 75.6 41.16 ;
    END
  END bank_read_addr[237]
  PIN bank_read_addr[238]
    DIRECTION OUTPUT ;
    USE SIGNAL ;
    PORT
      LAYER M4 ;
        RECT  75.516 41.232 75.6 41.256 ;
    END
  END bank_read_addr[238]
  PIN bank_read_addr[239]
    DIRECTION OUTPUT ;
    USE SIGNAL ;
    PORT
      LAYER M4 ;
        RECT  75.516 41.328 75.6 41.352 ;
    END
  END bank_read_addr[239]
  PIN bank_read_addr[23]
    DIRECTION OUTPUT ;
    USE SIGNAL ;
    PORT
      LAYER M4 ;
        RECT  75.516 48.24 75.6 48.264 ;
    END
  END bank_read_addr[23]
  PIN bank_read_addr[240]
    DIRECTION OUTPUT ;
    USE SIGNAL ;
    PORT
      LAYER M4 ;
        RECT  75.516 41.424 75.6 41.448 ;
    END
  END bank_read_addr[240]
  PIN bank_read_addr[241]
    DIRECTION OUTPUT ;
    USE SIGNAL ;
    PORT
      LAYER M4 ;
        RECT  75.516 41.52 75.6 41.544 ;
    END
  END bank_read_addr[241]
  PIN bank_read_addr[242]
    DIRECTION OUTPUT ;
    USE SIGNAL ;
    PORT
      LAYER M4 ;
        RECT  75.516 41.616 75.6 41.64 ;
    END
  END bank_read_addr[242]
  PIN bank_read_addr[243]
    DIRECTION OUTPUT ;
    USE SIGNAL ;
    PORT
      LAYER M4 ;
        RECT  75.516 41.712 75.6 41.736 ;
    END
  END bank_read_addr[243]
  PIN bank_read_addr[244]
    DIRECTION OUTPUT ;
    USE SIGNAL ;
    PORT
      LAYER M4 ;
        RECT  75.516 41.808 75.6 41.832 ;
    END
  END bank_read_addr[244]
  PIN bank_read_addr[245]
    DIRECTION OUTPUT ;
    USE SIGNAL ;
    PORT
      LAYER M4 ;
        RECT  75.516 41.904 75.6 41.928 ;
    END
  END bank_read_addr[245]
  PIN bank_read_addr[246]
    DIRECTION OUTPUT ;
    USE SIGNAL ;
    PORT
      LAYER M4 ;
        RECT  75.516 42 75.6 42.024 ;
    END
  END bank_read_addr[246]
  PIN bank_read_addr[247]
    DIRECTION OUTPUT ;
    USE SIGNAL ;
    PORT
      LAYER M4 ;
        RECT  75.516 42.096 75.6 42.12 ;
    END
  END bank_read_addr[247]
  PIN bank_read_addr[248]
    DIRECTION OUTPUT ;
    USE SIGNAL ;
    PORT
      LAYER M4 ;
        RECT  75.516 51.408 75.6 51.432 ;
    END
  END bank_read_addr[248]
  PIN bank_read_addr[249]
    DIRECTION OUTPUT ;
    USE SIGNAL ;
    PORT
      LAYER M4 ;
        RECT  75.516 51.504 75.6 51.528 ;
    END
  END bank_read_addr[249]
  PIN bank_read_addr[24]
    DIRECTION OUTPUT ;
    USE SIGNAL ;
    PORT
      LAYER M4 ;
        RECT  75.516 22.992 75.6 23.016 ;
    END
  END bank_read_addr[24]
  PIN bank_read_addr[250]
    DIRECTION OUTPUT ;
    USE SIGNAL ;
    PORT
      LAYER M4 ;
        RECT  75.516 51.6 75.6 51.624 ;
    END
  END bank_read_addr[250]
  PIN bank_read_addr[251]
    DIRECTION OUTPUT ;
    USE SIGNAL ;
    PORT
      LAYER M4 ;
        RECT  75.516 51.696 75.6 51.72 ;
    END
  END bank_read_addr[251]
  PIN bank_read_addr[252]
    DIRECTION OUTPUT ;
    USE SIGNAL ;
    PORT
      LAYER M4 ;
        RECT  75.516 51.792 75.6 51.816 ;
    END
  END bank_read_addr[252]
  PIN bank_read_addr[253]
    DIRECTION OUTPUT ;
    USE SIGNAL ;
    PORT
      LAYER M4 ;
        RECT  75.516 51.888 75.6 51.912 ;
    END
  END bank_read_addr[253]
  PIN bank_read_addr[254]
    DIRECTION OUTPUT ;
    USE SIGNAL ;
    PORT
      LAYER M4 ;
        RECT  75.516 51.984 75.6 52.008 ;
    END
  END bank_read_addr[254]
  PIN bank_read_addr[255]
    DIRECTION OUTPUT ;
    USE SIGNAL ;
    PORT
      LAYER M4 ;
        RECT  75.516 52.08 75.6 52.104 ;
    END
  END bank_read_addr[255]
  PIN bank_read_addr[25]
    DIRECTION OUTPUT ;
    USE SIGNAL ;
    PORT
      LAYER M4 ;
        RECT  75.516 23.088 75.6 23.112 ;
    END
  END bank_read_addr[25]
  PIN bank_read_addr[26]
    DIRECTION OUTPUT ;
    USE SIGNAL ;
    PORT
      LAYER M4 ;
        RECT  75.516 23.184 75.6 23.208 ;
    END
  END bank_read_addr[26]
  PIN bank_read_addr[27]
    DIRECTION OUTPUT ;
    USE SIGNAL ;
    PORT
      LAYER M4 ;
        RECT  75.516 23.28 75.6 23.304 ;
    END
  END bank_read_addr[27]
  PIN bank_read_addr[28]
    DIRECTION OUTPUT ;
    USE SIGNAL ;
    PORT
      LAYER M4 ;
        RECT  75.516 23.376 75.6 23.4 ;
    END
  END bank_read_addr[28]
  PIN bank_read_addr[29]
    DIRECTION OUTPUT ;
    USE SIGNAL ;
    PORT
      LAYER M4 ;
        RECT  75.516 23.472 75.6 23.496 ;
    END
  END bank_read_addr[29]
  PIN bank_read_addr[2]
    DIRECTION OUTPUT ;
    USE SIGNAL ;
    PORT
      LAYER M4 ;
        RECT  75.516 46.224 75.6 46.248 ;
    END
  END bank_read_addr[2]
  PIN bank_read_addr[30]
    DIRECTION OUTPUT ;
    USE SIGNAL ;
    PORT
      LAYER M4 ;
        RECT  75.516 23.568 75.6 23.592 ;
    END
  END bank_read_addr[30]
  PIN bank_read_addr[31]
    DIRECTION OUTPUT ;
    USE SIGNAL ;
    PORT
      LAYER M4 ;
        RECT  75.516 23.664 75.6 23.688 ;
    END
  END bank_read_addr[31]
  PIN bank_read_addr[32]
    DIRECTION OUTPUT ;
    USE SIGNAL ;
    PORT
      LAYER M4 ;
        RECT  75.516 23.76 75.6 23.784 ;
    END
  END bank_read_addr[32]
  PIN bank_read_addr[33]
    DIRECTION OUTPUT ;
    USE SIGNAL ;
    PORT
      LAYER M4 ;
        RECT  75.516 23.856 75.6 23.88 ;
    END
  END bank_read_addr[33]
  PIN bank_read_addr[34]
    DIRECTION OUTPUT ;
    USE SIGNAL ;
    PORT
      LAYER M4 ;
        RECT  75.516 23.952 75.6 23.976 ;
    END
  END bank_read_addr[34]
  PIN bank_read_addr[35]
    DIRECTION OUTPUT ;
    USE SIGNAL ;
    PORT
      LAYER M4 ;
        RECT  75.516 24.048 75.6 24.072 ;
    END
  END bank_read_addr[35]
  PIN bank_read_addr[36]
    DIRECTION OUTPUT ;
    USE SIGNAL ;
    PORT
      LAYER M4 ;
        RECT  75.516 24.144 75.6 24.168 ;
    END
  END bank_read_addr[36]
  PIN bank_read_addr[37]
    DIRECTION OUTPUT ;
    USE SIGNAL ;
    PORT
      LAYER M4 ;
        RECT  75.516 24.24 75.6 24.264 ;
    END
  END bank_read_addr[37]
  PIN bank_read_addr[38]
    DIRECTION OUTPUT ;
    USE SIGNAL ;
    PORT
      LAYER M4 ;
        RECT  75.516 24.336 75.6 24.36 ;
    END
  END bank_read_addr[38]
  PIN bank_read_addr[39]
    DIRECTION OUTPUT ;
    USE SIGNAL ;
    PORT
      LAYER M4 ;
        RECT  75.516 24.432 75.6 24.456 ;
    END
  END bank_read_addr[39]
  PIN bank_read_addr[3]
    DIRECTION OUTPUT ;
    USE SIGNAL ;
    PORT
      LAYER M4 ;
        RECT  75.516 46.32 75.6 46.344 ;
    END
  END bank_read_addr[3]
  PIN bank_read_addr[40]
    DIRECTION OUTPUT ;
    USE SIGNAL ;
    PORT
      LAYER M4 ;
        RECT  75.516 24.528 75.6 24.552 ;
    END
  END bank_read_addr[40]
  PIN bank_read_addr[41]
    DIRECTION OUTPUT ;
    USE SIGNAL ;
    PORT
      LAYER M4 ;
        RECT  75.516 24.624 75.6 24.648 ;
    END
  END bank_read_addr[41]
  PIN bank_read_addr[42]
    DIRECTION OUTPUT ;
    USE SIGNAL ;
    PORT
      LAYER M4 ;
        RECT  75.516 24.72 75.6 24.744 ;
    END
  END bank_read_addr[42]
  PIN bank_read_addr[43]
    DIRECTION OUTPUT ;
    USE SIGNAL ;
    PORT
      LAYER M4 ;
        RECT  75.516 24.816 75.6 24.84 ;
    END
  END bank_read_addr[43]
  PIN bank_read_addr[44]
    DIRECTION OUTPUT ;
    USE SIGNAL ;
    PORT
      LAYER M4 ;
        RECT  75.516 24.912 75.6 24.936 ;
    END
  END bank_read_addr[44]
  PIN bank_read_addr[45]
    DIRECTION OUTPUT ;
    USE SIGNAL ;
    PORT
      LAYER M4 ;
        RECT  75.516 25.008 75.6 25.032 ;
    END
  END bank_read_addr[45]
  PIN bank_read_addr[46]
    DIRECTION OUTPUT ;
    USE SIGNAL ;
    PORT
      LAYER M4 ;
        RECT  75.516 25.104 75.6 25.128 ;
    END
  END bank_read_addr[46]
  PIN bank_read_addr[47]
    DIRECTION OUTPUT ;
    USE SIGNAL ;
    PORT
      LAYER M4 ;
        RECT  75.516 25.2 75.6 25.224 ;
    END
  END bank_read_addr[47]
  PIN bank_read_addr[48]
    DIRECTION OUTPUT ;
    USE SIGNAL ;
    PORT
      LAYER M4 ;
        RECT  75.516 25.296 75.6 25.32 ;
    END
  END bank_read_addr[48]
  PIN bank_read_addr[49]
    DIRECTION OUTPUT ;
    USE SIGNAL ;
    PORT
      LAYER M4 ;
        RECT  75.516 25.392 75.6 25.416 ;
    END
  END bank_read_addr[49]
  PIN bank_read_addr[4]
    DIRECTION OUTPUT ;
    USE SIGNAL ;
    PORT
      LAYER M4 ;
        RECT  75.516 46.416 75.6 46.44 ;
    END
  END bank_read_addr[4]
  PIN bank_read_addr[50]
    DIRECTION OUTPUT ;
    USE SIGNAL ;
    PORT
      LAYER M4 ;
        RECT  75.516 25.488 75.6 25.512 ;
    END
  END bank_read_addr[50]
  PIN bank_read_addr[51]
    DIRECTION OUTPUT ;
    USE SIGNAL ;
    PORT
      LAYER M4 ;
        RECT  75.516 25.584 75.6 25.608 ;
    END
  END bank_read_addr[51]
  PIN bank_read_addr[52]
    DIRECTION OUTPUT ;
    USE SIGNAL ;
    PORT
      LAYER M4 ;
        RECT  75.516 25.68 75.6 25.704 ;
    END
  END bank_read_addr[52]
  PIN bank_read_addr[53]
    DIRECTION OUTPUT ;
    USE SIGNAL ;
    PORT
      LAYER M4 ;
        RECT  75.516 25.776 75.6 25.8 ;
    END
  END bank_read_addr[53]
  PIN bank_read_addr[54]
    DIRECTION OUTPUT ;
    USE SIGNAL ;
    PORT
      LAYER M4 ;
        RECT  75.516 25.872 75.6 25.896 ;
    END
  END bank_read_addr[54]
  PIN bank_read_addr[55]
    DIRECTION OUTPUT ;
    USE SIGNAL ;
    PORT
      LAYER M4 ;
        RECT  75.516 25.968 75.6 25.992 ;
    END
  END bank_read_addr[55]
  PIN bank_read_addr[56]
    DIRECTION OUTPUT ;
    USE SIGNAL ;
    PORT
      LAYER M4 ;
        RECT  75.516 35.28 75.6 35.304 ;
    END
  END bank_read_addr[56]
  PIN bank_read_addr[57]
    DIRECTION OUTPUT ;
    USE SIGNAL ;
    PORT
      LAYER M4 ;
        RECT  75.516 35.376 75.6 35.4 ;
    END
  END bank_read_addr[57]
  PIN bank_read_addr[58]
    DIRECTION OUTPUT ;
    USE SIGNAL ;
    PORT
      LAYER M4 ;
        RECT  75.516 35.472 75.6 35.496 ;
    END
  END bank_read_addr[58]
  PIN bank_read_addr[59]
    DIRECTION OUTPUT ;
    USE SIGNAL ;
    PORT
      LAYER M4 ;
        RECT  75.516 35.568 75.6 35.592 ;
    END
  END bank_read_addr[59]
  PIN bank_read_addr[5]
    DIRECTION OUTPUT ;
    USE SIGNAL ;
    PORT
      LAYER M4 ;
        RECT  75.516 46.512 75.6 46.536 ;
    END
  END bank_read_addr[5]
  PIN bank_read_addr[60]
    DIRECTION OUTPUT ;
    USE SIGNAL ;
    PORT
      LAYER M4 ;
        RECT  75.516 35.664 75.6 35.688 ;
    END
  END bank_read_addr[60]
  PIN bank_read_addr[61]
    DIRECTION OUTPUT ;
    USE SIGNAL ;
    PORT
      LAYER M4 ;
        RECT  75.516 35.76 75.6 35.784 ;
    END
  END bank_read_addr[61]
  PIN bank_read_addr[62]
    DIRECTION OUTPUT ;
    USE SIGNAL ;
    PORT
      LAYER M4 ;
        RECT  75.516 35.856 75.6 35.88 ;
    END
  END bank_read_addr[62]
  PIN bank_read_addr[63]
    DIRECTION OUTPUT ;
    USE SIGNAL ;
    PORT
      LAYER M4 ;
        RECT  75.516 35.952 75.6 35.976 ;
    END
  END bank_read_addr[63]
  PIN bank_read_addr[64]
    DIRECTION OUTPUT ;
    USE SIGNAL ;
    PORT
      LAYER M4 ;
        RECT  75.516 36.048 75.6 36.072 ;
    END
  END bank_read_addr[64]
  PIN bank_read_addr[65]
    DIRECTION OUTPUT ;
    USE SIGNAL ;
    PORT
      LAYER M4 ;
        RECT  75.516 36.144 75.6 36.168 ;
    END
  END bank_read_addr[65]
  PIN bank_read_addr[66]
    DIRECTION OUTPUT ;
    USE SIGNAL ;
    PORT
      LAYER M4 ;
        RECT  75.516 36.24 75.6 36.264 ;
    END
  END bank_read_addr[66]
  PIN bank_read_addr[67]
    DIRECTION OUTPUT ;
    USE SIGNAL ;
    PORT
      LAYER M4 ;
        RECT  75.516 36.336 75.6 36.36 ;
    END
  END bank_read_addr[67]
  PIN bank_read_addr[68]
    DIRECTION OUTPUT ;
    USE SIGNAL ;
    PORT
      LAYER M4 ;
        RECT  75.516 36.432 75.6 36.456 ;
    END
  END bank_read_addr[68]
  PIN bank_read_addr[69]
    DIRECTION OUTPUT ;
    USE SIGNAL ;
    PORT
      LAYER M4 ;
        RECT  75.516 36.528 75.6 36.552 ;
    END
  END bank_read_addr[69]
  PIN bank_read_addr[6]
    DIRECTION OUTPUT ;
    USE SIGNAL ;
    PORT
      LAYER M4 ;
        RECT  75.516 46.608 75.6 46.632 ;
    END
  END bank_read_addr[6]
  PIN bank_read_addr[70]
    DIRECTION OUTPUT ;
    USE SIGNAL ;
    PORT
      LAYER M4 ;
        RECT  75.516 36.624 75.6 36.648 ;
    END
  END bank_read_addr[70]
  PIN bank_read_addr[71]
    DIRECTION OUTPUT ;
    USE SIGNAL ;
    PORT
      LAYER M4 ;
        RECT  75.516 36.72 75.6 36.744 ;
    END
  END bank_read_addr[71]
  PIN bank_read_addr[72]
    DIRECTION OUTPUT ;
    USE SIGNAL ;
    PORT
      LAYER M4 ;
        RECT  75.516 36.816 75.6 36.84 ;
    END
  END bank_read_addr[72]
  PIN bank_read_addr[73]
    DIRECTION OUTPUT ;
    USE SIGNAL ;
    PORT
      LAYER M4 ;
        RECT  75.516 36.912 75.6 36.936 ;
    END
  END bank_read_addr[73]
  PIN bank_read_addr[74]
    DIRECTION OUTPUT ;
    USE SIGNAL ;
    PORT
      LAYER M4 ;
        RECT  75.516 37.008 75.6 37.032 ;
    END
  END bank_read_addr[74]
  PIN bank_read_addr[75]
    DIRECTION OUTPUT ;
    USE SIGNAL ;
    PORT
      LAYER M4 ;
        RECT  75.516 37.104 75.6 37.128 ;
    END
  END bank_read_addr[75]
  PIN bank_read_addr[76]
    DIRECTION OUTPUT ;
    USE SIGNAL ;
    PORT
      LAYER M4 ;
        RECT  75.516 37.2 75.6 37.224 ;
    END
  END bank_read_addr[76]
  PIN bank_read_addr[77]
    DIRECTION OUTPUT ;
    USE SIGNAL ;
    PORT
      LAYER M4 ;
        RECT  75.516 37.296 75.6 37.32 ;
    END
  END bank_read_addr[77]
  PIN bank_read_addr[78]
    DIRECTION OUTPUT ;
    USE SIGNAL ;
    PORT
      LAYER M4 ;
        RECT  75.516 37.392 75.6 37.416 ;
    END
  END bank_read_addr[78]
  PIN bank_read_addr[79]
    DIRECTION OUTPUT ;
    USE SIGNAL ;
    PORT
      LAYER M4 ;
        RECT  75.516 37.488 75.6 37.512 ;
    END
  END bank_read_addr[79]
  PIN bank_read_addr[7]
    DIRECTION OUTPUT ;
    USE SIGNAL ;
    PORT
      LAYER M4 ;
        RECT  75.516 46.704 75.6 46.728 ;
    END
  END bank_read_addr[7]
  PIN bank_read_addr[80]
    DIRECTION OUTPUT ;
    USE SIGNAL ;
    PORT
      LAYER M4 ;
        RECT  75.516 37.584 75.6 37.608 ;
    END
  END bank_read_addr[80]
  PIN bank_read_addr[81]
    DIRECTION OUTPUT ;
    USE SIGNAL ;
    PORT
      LAYER M4 ;
        RECT  75.516 37.68 75.6 37.704 ;
    END
  END bank_read_addr[81]
  PIN bank_read_addr[82]
    DIRECTION OUTPUT ;
    USE SIGNAL ;
    PORT
      LAYER M4 ;
        RECT  75.516 37.776 75.6 37.8 ;
    END
  END bank_read_addr[82]
  PIN bank_read_addr[83]
    DIRECTION OUTPUT ;
    USE SIGNAL ;
    PORT
      LAYER M4 ;
        RECT  75.516 37.872 75.6 37.896 ;
    END
  END bank_read_addr[83]
  PIN bank_read_addr[84]
    DIRECTION OUTPUT ;
    USE SIGNAL ;
    PORT
      LAYER M4 ;
        RECT  75.516 37.968 75.6 37.992 ;
    END
  END bank_read_addr[84]
  PIN bank_read_addr[85]
    DIRECTION OUTPUT ;
    USE SIGNAL ;
    PORT
      LAYER M4 ;
        RECT  75.516 38.064 75.6 38.088 ;
    END
  END bank_read_addr[85]
  PIN bank_read_addr[86]
    DIRECTION OUTPUT ;
    USE SIGNAL ;
    PORT
      LAYER M4 ;
        RECT  75.516 38.16 75.6 38.184 ;
    END
  END bank_read_addr[86]
  PIN bank_read_addr[87]
    DIRECTION OUTPUT ;
    USE SIGNAL ;
    PORT
      LAYER M4 ;
        RECT  75.516 38.256 75.6 38.28 ;
    END
  END bank_read_addr[87]
  PIN bank_read_addr[88]
    DIRECTION OUTPUT ;
    USE SIGNAL ;
    PORT
      LAYER M4 ;
        RECT  75.516 32.208 75.6 32.232 ;
    END
  END bank_read_addr[88]
  PIN bank_read_addr[89]
    DIRECTION OUTPUT ;
    USE SIGNAL ;
    PORT
      LAYER M4 ;
        RECT  75.516 32.304 75.6 32.328 ;
    END
  END bank_read_addr[89]
  PIN bank_read_addr[8]
    DIRECTION OUTPUT ;
    USE SIGNAL ;
    PORT
      LAYER M4 ;
        RECT  75.516 46.8 75.6 46.824 ;
    END
  END bank_read_addr[8]
  PIN bank_read_addr[90]
    DIRECTION OUTPUT ;
    USE SIGNAL ;
    PORT
      LAYER M4 ;
        RECT  75.516 32.4 75.6 32.424 ;
    END
  END bank_read_addr[90]
  PIN bank_read_addr[91]
    DIRECTION OUTPUT ;
    USE SIGNAL ;
    PORT
      LAYER M4 ;
        RECT  75.516 32.496 75.6 32.52 ;
    END
  END bank_read_addr[91]
  PIN bank_read_addr[92]
    DIRECTION OUTPUT ;
    USE SIGNAL ;
    PORT
      LAYER M4 ;
        RECT  75.516 32.592 75.6 32.616 ;
    END
  END bank_read_addr[92]
  PIN bank_read_addr[93]
    DIRECTION OUTPUT ;
    USE SIGNAL ;
    PORT
      LAYER M4 ;
        RECT  75.516 32.688 75.6 32.712 ;
    END
  END bank_read_addr[93]
  PIN bank_read_addr[94]
    DIRECTION OUTPUT ;
    USE SIGNAL ;
    PORT
      LAYER M4 ;
        RECT  75.516 32.784 75.6 32.808 ;
    END
  END bank_read_addr[94]
  PIN bank_read_addr[95]
    DIRECTION OUTPUT ;
    USE SIGNAL ;
    PORT
      LAYER M4 ;
        RECT  75.516 32.88 75.6 32.904 ;
    END
  END bank_read_addr[95]
  PIN bank_read_addr[96]
    DIRECTION OUTPUT ;
    USE SIGNAL ;
    PORT
      LAYER M4 ;
        RECT  75.516 32.976 75.6 33 ;
    END
  END bank_read_addr[96]
  PIN bank_read_addr[97]
    DIRECTION OUTPUT ;
    USE SIGNAL ;
    PORT
      LAYER M4 ;
        RECT  75.516 33.072 75.6 33.096 ;
    END
  END bank_read_addr[97]
  PIN bank_read_addr[98]
    DIRECTION OUTPUT ;
    USE SIGNAL ;
    PORT
      LAYER M4 ;
        RECT  75.516 33.168 75.6 33.192 ;
    END
  END bank_read_addr[98]
  PIN bank_read_addr[99]
    DIRECTION OUTPUT ;
    USE SIGNAL ;
    PORT
      LAYER M4 ;
        RECT  75.516 33.264 75.6 33.288 ;
    END
  END bank_read_addr[99]
  PIN bank_read_addr[9]
    DIRECTION OUTPUT ;
    USE SIGNAL ;
    PORT
      LAYER M4 ;
        RECT  75.516 46.896 75.6 46.92 ;
    END
  END bank_read_addr[9]
  PIN bank_read_en[0]
    DIRECTION OUTPUT ;
    USE SIGNAL ;
    PORT
      LAYER M4 ;
        RECT  75.516 52.176 75.6 52.2 ;
    END
  END bank_read_en[0]
  PIN bank_read_en[1]
    DIRECTION OUTPUT ;
    USE SIGNAL ;
    PORT
      LAYER M4 ;
        RECT  75.516 52.272 75.6 52.296 ;
    END
  END bank_read_en[1]
  PIN bank_read_en[2]
    DIRECTION OUTPUT ;
    USE SIGNAL ;
    PORT
      LAYER M4 ;
        RECT  75.516 52.368 75.6 52.392 ;
    END
  END bank_read_en[2]
  PIN bank_read_en[3]
    DIRECTION OUTPUT ;
    USE SIGNAL ;
    PORT
      LAYER M4 ;
        RECT  75.516 52.464 75.6 52.488 ;
    END
  END bank_read_en[3]
  PIN bank_read_en[4]
    DIRECTION OUTPUT ;
    USE SIGNAL ;
    PORT
      LAYER M4 ;
        RECT  75.516 52.56 75.6 52.584 ;
    END
  END bank_read_en[4]
  PIN bank_read_en[5]
    DIRECTION OUTPUT ;
    USE SIGNAL ;
    PORT
      LAYER M4 ;
        RECT  75.516 52.656 75.6 52.68 ;
    END
  END bank_read_en[5]
  PIN bank_read_en[6]
    DIRECTION OUTPUT ;
    USE SIGNAL ;
    PORT
      LAYER M4 ;
        RECT  75.516 52.752 75.6 52.776 ;
    END
  END bank_read_en[6]
  PIN bank_read_en[7]
    DIRECTION OUTPUT ;
    USE SIGNAL ;
    PORT
      LAYER M4 ;
        RECT  75.516 52.848 75.6 52.872 ;
    END
  END bank_read_en[7]
  PIN bank_read_slot[0]
    DIRECTION OUTPUT ;
    USE SIGNAL ;
    PORT
      LAYER M4 ;
        RECT  75.516 52.944 75.6 52.968 ;
    END
  END bank_read_slot[0]
  PIN bank_read_slot[1]
    DIRECTION OUTPUT ;
    USE SIGNAL ;
    PORT
      LAYER M4 ;
        RECT  75.516 53.04 75.6 53.064 ;
    END
  END bank_read_slot[1]
  PIN bank_read_slot[2]
    DIRECTION OUTPUT ;
    USE SIGNAL ;
    PORT
      LAYER M4 ;
        RECT  75.516 53.136 75.6 53.16 ;
    END
  END bank_read_slot[2]
  PIN bank_read_slot[3]
    DIRECTION OUTPUT ;
    USE SIGNAL ;
    PORT
      LAYER M4 ;
        RECT  75.516 53.232 75.6 53.256 ;
    END
  END bank_read_slot[3]
  PIN bank_read_slot[4]
    DIRECTION OUTPUT ;
    USE SIGNAL ;
    PORT
      LAYER M4 ;
        RECT  75.516 53.328 75.6 53.352 ;
    END
  END bank_read_slot[4]
  PIN bank_read_slot[5]
    DIRECTION OUTPUT ;
    USE SIGNAL ;
    PORT
      LAYER M4 ;
        RECT  75.516 53.424 75.6 53.448 ;
    END
  END bank_read_slot[5]
  PIN bank_read_slot[6]
    DIRECTION OUTPUT ;
    USE SIGNAL ;
    PORT
      LAYER M4 ;
        RECT  75.516 53.52 75.6 53.544 ;
    END
  END bank_read_slot[6]
  PIN bank_write_en[0]
    DIRECTION OUTPUT ;
    USE SIGNAL ;
    PORT
      LAYER M4 ;
        RECT  75.516 53.616 75.6 53.64 ;
    END
  END bank_write_en[0]
  PIN bank_write_en[1]
    DIRECTION OUTPUT ;
    USE SIGNAL ;
    PORT
      LAYER M4 ;
        RECT  75.516 53.712 75.6 53.736 ;
    END
  END bank_write_en[1]
  PIN bank_write_en[2]
    DIRECTION OUTPUT ;
    USE SIGNAL ;
    PORT
      LAYER M4 ;
        RECT  75.516 53.808 75.6 53.832 ;
    END
  END bank_write_en[2]
  PIN bank_write_en[3]
    DIRECTION OUTPUT ;
    USE SIGNAL ;
    PORT
      LAYER M4 ;
        RECT  75.516 53.904 75.6 53.928 ;
    END
  END bank_write_en[3]
  PIN bank_write_en[4]
    DIRECTION OUTPUT ;
    USE SIGNAL ;
    PORT
      LAYER M4 ;
        RECT  75.516 54 75.6 54.024 ;
    END
  END bank_write_en[4]
  PIN bank_write_en[5]
    DIRECTION OUTPUT ;
    USE SIGNAL ;
    PORT
      LAYER M4 ;
        RECT  75.516 54.096 75.6 54.12 ;
    END
  END bank_write_en[5]
  PIN bank_write_en[6]
    DIRECTION OUTPUT ;
    USE SIGNAL ;
    PORT
      LAYER M4 ;
        RECT  75.516 54.192 75.6 54.216 ;
    END
  END bank_write_en[6]
  PIN bank_write_en[7]
    DIRECTION OUTPUT ;
    USE SIGNAL ;
    PORT
      LAYER M4 ;
        RECT  75.516 54.288 75.6 54.312 ;
    END
  END bank_write_en[7]
  PIN bank_write_slot[0]
    DIRECTION OUTPUT ;
    USE SIGNAL ;
    PORT
      LAYER M4 ;
        RECT  75.516 54.384 75.6 54.408 ;
    END
  END bank_write_slot[0]
  PIN bank_write_slot[1]
    DIRECTION OUTPUT ;
    USE SIGNAL ;
    PORT
      LAYER M4 ;
        RECT  75.516 62.352 75.6 62.376 ;
    END
  END bank_write_slot[1]
  PIN bank_write_slot[2]
    DIRECTION OUTPUT ;
    USE SIGNAL ;
    PORT
      LAYER M4 ;
        RECT  75.516 62.448 75.6 62.472 ;
    END
  END bank_write_slot[2]
  PIN bank_write_slot[3]
    DIRECTION OUTPUT ;
    USE SIGNAL ;
    PORT
      LAYER M4 ;
        RECT  75.516 62.544 75.6 62.568 ;
    END
  END bank_write_slot[3]
  PIN bank_write_slot[4]
    DIRECTION OUTPUT ;
    USE SIGNAL ;
    PORT
      LAYER M4 ;
        RECT  75.516 62.64 75.6 62.664 ;
    END
  END bank_write_slot[4]
  PIN bank_write_slot[5]
    DIRECTION OUTPUT ;
    USE SIGNAL ;
    PORT
      LAYER M4 ;
        RECT  75.516 62.736 75.6 62.76 ;
    END
  END bank_write_slot[5]
  PIN bank_write_slot[6]
    DIRECTION OUTPUT ;
    USE SIGNAL ;
    PORT
      LAYER M4 ;
        RECT  75.516 62.832 75.6 62.856 ;
    END
  END bank_write_slot[6]
  PIN busy
    DIRECTION OUTPUT ;
    USE SIGNAL ;
    PORT
      LAYER M5 ;
        RECT  42.288 75.516 42.312 75.6 ;
    END
  END busy
  PIN clk
    DIRECTION INPUT ;
    USE SIGNAL ;
    PORT
      LAYER M5 ;
        RECT  42.384 75.516 42.408 75.6 ;
    END
  END clk
  PIN cycle_in[0]
    DIRECTION INPUT ;
    USE SIGNAL ;
    PORT
      LAYER M4 ;
        RECT  0 5.04 0.084 5.064 ;
    END
  END cycle_in[0]
  PIN cycle_in[10]
    DIRECTION INPUT ;
    USE SIGNAL ;
    PORT
      LAYER M4 ;
        RECT  0 6 0.084 6.024 ;
    END
  END cycle_in[10]
  PIN cycle_in[11]
    DIRECTION INPUT ;
    USE SIGNAL ;
    PORT
      LAYER M4 ;
        RECT  0 6.096 0.084 6.12 ;
    END
  END cycle_in[11]
  PIN cycle_in[12]
    DIRECTION INPUT ;
    USE SIGNAL ;
    PORT
      LAYER M4 ;
        RECT  0 6.192 0.084 6.216 ;
    END
  END cycle_in[12]
  PIN cycle_in[13]
    DIRECTION INPUT ;
    USE SIGNAL ;
    PORT
      LAYER M4 ;
        RECT  0 6.288 0.084 6.312 ;
    END
  END cycle_in[13]
  PIN cycle_in[14]
    DIRECTION INPUT ;
    USE SIGNAL ;
    PORT
      LAYER M4 ;
        RECT  0 6.384 0.084 6.408 ;
    END
  END cycle_in[14]
  PIN cycle_in[15]
    DIRECTION INPUT ;
    USE SIGNAL ;
    PORT
      LAYER M4 ;
        RECT  0 6.48 0.084 6.504 ;
    END
  END cycle_in[15]
  PIN cycle_in[16]
    DIRECTION INPUT ;
    USE SIGNAL ;
    PORT
      LAYER M4 ;
        RECT  0 6.576 0.084 6.6 ;
    END
  END cycle_in[16]
  PIN cycle_in[17]
    DIRECTION INPUT ;
    USE SIGNAL ;
    PORT
      LAYER M4 ;
        RECT  0 6.672 0.084 6.696 ;
    END
  END cycle_in[17]
  PIN cycle_in[18]
    DIRECTION INPUT ;
    USE SIGNAL ;
    PORT
      LAYER M4 ;
        RECT  0 6.768 0.084 6.792 ;
    END
  END cycle_in[18]
  PIN cycle_in[19]
    DIRECTION INPUT ;
    USE SIGNAL ;
    PORT
      LAYER M4 ;
        RECT  0 6.864 0.084 6.888 ;
    END
  END cycle_in[19]
  PIN cycle_in[1]
    DIRECTION INPUT ;
    USE SIGNAL ;
    PORT
      LAYER M4 ;
        RECT  0 5.136 0.084 5.16 ;
    END
  END cycle_in[1]
  PIN cycle_in[20]
    DIRECTION INPUT ;
    USE SIGNAL ;
    PORT
      LAYER M4 ;
        RECT  0 6.96 0.084 6.984 ;
    END
  END cycle_in[20]
  PIN cycle_in[21]
    DIRECTION INPUT ;
    USE SIGNAL ;
    PORT
      LAYER M4 ;
        RECT  0 7.056 0.084 7.08 ;
    END
  END cycle_in[21]
  PIN cycle_in[22]
    DIRECTION INPUT ;
    USE SIGNAL ;
    PORT
      LAYER M4 ;
        RECT  0 7.152 0.084 7.176 ;
    END
  END cycle_in[22]
  PIN cycle_in[23]
    DIRECTION INPUT ;
    USE SIGNAL ;
    PORT
      LAYER M4 ;
        RECT  0 7.248 0.084 7.272 ;
    END
  END cycle_in[23]
  PIN cycle_in[24]
    DIRECTION INPUT ;
    USE SIGNAL ;
    PORT
      LAYER M4 ;
        RECT  0 7.344 0.084 7.368 ;
    END
  END cycle_in[24]
  PIN cycle_in[25]
    DIRECTION INPUT ;
    USE SIGNAL ;
    PORT
      LAYER M4 ;
        RECT  0 7.44 0.084 7.464 ;
    END
  END cycle_in[25]
  PIN cycle_in[26]
    DIRECTION INPUT ;
    USE SIGNAL ;
    PORT
      LAYER M4 ;
        RECT  0 7.536 0.084 7.56 ;
    END
  END cycle_in[26]
  PIN cycle_in[27]
    DIRECTION INPUT ;
    USE SIGNAL ;
    PORT
      LAYER M4 ;
        RECT  0 7.632 0.084 7.656 ;
    END
  END cycle_in[27]
  PIN cycle_in[28]
    DIRECTION INPUT ;
    USE SIGNAL ;
    PORT
      LAYER M4 ;
        RECT  0 7.728 0.084 7.752 ;
    END
  END cycle_in[28]
  PIN cycle_in[29]
    DIRECTION INPUT ;
    USE SIGNAL ;
    PORT
      LAYER M4 ;
        RECT  0 7.824 0.084 7.848 ;
    END
  END cycle_in[29]
  PIN cycle_in[2]
    DIRECTION INPUT ;
    USE SIGNAL ;
    PORT
      LAYER M4 ;
        RECT  0 5.232 0.084 5.256 ;
    END
  END cycle_in[2]
  PIN cycle_in[30]
    DIRECTION INPUT ;
    USE SIGNAL ;
    PORT
      LAYER M4 ;
        RECT  0 7.92 0.084 7.944 ;
    END
  END cycle_in[30]
  PIN cycle_in[31]
    DIRECTION INPUT ;
    USE SIGNAL ;
    PORT
      LAYER M4 ;
        RECT  0 8.016 0.084 8.04 ;
    END
  END cycle_in[31]
  PIN cycle_in[3]
    DIRECTION INPUT ;
    USE SIGNAL ;
    PORT
      LAYER M4 ;
        RECT  0 5.328 0.084 5.352 ;
    END
  END cycle_in[3]
  PIN cycle_in[4]
    DIRECTION INPUT ;
    USE SIGNAL ;
    PORT
      LAYER M4 ;
        RECT  0 5.424 0.084 5.448 ;
    END
  END cycle_in[4]
  PIN cycle_in[5]
    DIRECTION INPUT ;
    USE SIGNAL ;
    PORT
      LAYER M4 ;
        RECT  0 5.52 0.084 5.544 ;
    END
  END cycle_in[5]
  PIN cycle_in[6]
    DIRECTION INPUT ;
    USE SIGNAL ;
    PORT
      LAYER M4 ;
        RECT  0 5.616 0.084 5.64 ;
    END
  END cycle_in[6]
  PIN cycle_in[7]
    DIRECTION INPUT ;
    USE SIGNAL ;
    PORT
      LAYER M4 ;
        RECT  0 5.712 0.084 5.736 ;
    END
  END cycle_in[7]
  PIN cycle_in[8]
    DIRECTION INPUT ;
    USE SIGNAL ;
    PORT
      LAYER M4 ;
        RECT  0 5.808 0.084 5.832 ;
    END
  END cycle_in[8]
  PIN cycle_in[9]
    DIRECTION INPUT ;
    USE SIGNAL ;
    PORT
      LAYER M4 ;
        RECT  0 5.904 0.084 5.928 ;
    END
  END cycle_in[9]
  PIN drain_at[0]
    DIRECTION INPUT ;
    USE SIGNAL ;
    PORT
      LAYER M4 ;
        RECT  0 8.112 0.084 8.136 ;
    END
  END drain_at[0]
  PIN drain_at[10]
    DIRECTION INPUT ;
    USE SIGNAL ;
    PORT
      LAYER M4 ;
        RECT  0 9.072 0.084 9.096 ;
    END
  END drain_at[10]
  PIN drain_at[11]
    DIRECTION INPUT ;
    USE SIGNAL ;
    PORT
      LAYER M4 ;
        RECT  0 9.168 0.084 9.192 ;
    END
  END drain_at[11]
  PIN drain_at[12]
    DIRECTION INPUT ;
    USE SIGNAL ;
    PORT
      LAYER M4 ;
        RECT  0 9.264 0.084 9.288 ;
    END
  END drain_at[12]
  PIN drain_at[13]
    DIRECTION INPUT ;
    USE SIGNAL ;
    PORT
      LAYER M4 ;
        RECT  0 9.36 0.084 9.384 ;
    END
  END drain_at[13]
  PIN drain_at[14]
    DIRECTION INPUT ;
    USE SIGNAL ;
    PORT
      LAYER M4 ;
        RECT  0 9.456 0.084 9.48 ;
    END
  END drain_at[14]
  PIN drain_at[15]
    DIRECTION INPUT ;
    USE SIGNAL ;
    PORT
      LAYER M4 ;
        RECT  0 9.552 0.084 9.576 ;
    END
  END drain_at[15]
  PIN drain_at[16]
    DIRECTION INPUT ;
    USE SIGNAL ;
    PORT
      LAYER M4 ;
        RECT  0 9.648 0.084 9.672 ;
    END
  END drain_at[16]
  PIN drain_at[17]
    DIRECTION INPUT ;
    USE SIGNAL ;
    PORT
      LAYER M4 ;
        RECT  0 9.744 0.084 9.768 ;
    END
  END drain_at[17]
  PIN drain_at[18]
    DIRECTION INPUT ;
    USE SIGNAL ;
    PORT
      LAYER M4 ;
        RECT  0 9.84 0.084 9.864 ;
    END
  END drain_at[18]
  PIN drain_at[19]
    DIRECTION INPUT ;
    USE SIGNAL ;
    PORT
      LAYER M4 ;
        RECT  0 9.936 0.084 9.96 ;
    END
  END drain_at[19]
  PIN drain_at[1]
    DIRECTION INPUT ;
    USE SIGNAL ;
    PORT
      LAYER M4 ;
        RECT  0 8.208 0.084 8.232 ;
    END
  END drain_at[1]
  PIN drain_at[20]
    DIRECTION INPUT ;
    USE SIGNAL ;
    PORT
      LAYER M4 ;
        RECT  0 10.032 0.084 10.056 ;
    END
  END drain_at[20]
  PIN drain_at[21]
    DIRECTION INPUT ;
    USE SIGNAL ;
    PORT
      LAYER M4 ;
        RECT  0 10.128 0.084 10.152 ;
    END
  END drain_at[21]
  PIN drain_at[22]
    DIRECTION INPUT ;
    USE SIGNAL ;
    PORT
      LAYER M4 ;
        RECT  0 10.224 0.084 10.248 ;
    END
  END drain_at[22]
  PIN drain_at[23]
    DIRECTION INPUT ;
    USE SIGNAL ;
    PORT
      LAYER M4 ;
        RECT  0 10.32 0.084 10.344 ;
    END
  END drain_at[23]
  PIN drain_at[24]
    DIRECTION INPUT ;
    USE SIGNAL ;
    PORT
      LAYER M4 ;
        RECT  0 10.416 0.084 10.44 ;
    END
  END drain_at[24]
  PIN drain_at[25]
    DIRECTION INPUT ;
    USE SIGNAL ;
    PORT
      LAYER M4 ;
        RECT  0 10.512 0.084 10.536 ;
    END
  END drain_at[25]
  PIN drain_at[26]
    DIRECTION INPUT ;
    USE SIGNAL ;
    PORT
      LAYER M4 ;
        RECT  0 10.608 0.084 10.632 ;
    END
  END drain_at[26]
  PIN drain_at[27]
    DIRECTION INPUT ;
    USE SIGNAL ;
    PORT
      LAYER M4 ;
        RECT  0 10.704 0.084 10.728 ;
    END
  END drain_at[27]
  PIN drain_at[28]
    DIRECTION INPUT ;
    USE SIGNAL ;
    PORT
      LAYER M4 ;
        RECT  0 10.8 0.084 10.824 ;
    END
  END drain_at[28]
  PIN drain_at[29]
    DIRECTION INPUT ;
    USE SIGNAL ;
    PORT
      LAYER M4 ;
        RECT  0 10.896 0.084 10.92 ;
    END
  END drain_at[29]
  PIN drain_at[2]
    DIRECTION INPUT ;
    USE SIGNAL ;
    PORT
      LAYER M4 ;
        RECT  0 8.304 0.084 8.328 ;
    END
  END drain_at[2]
  PIN drain_at[30]
    DIRECTION INPUT ;
    USE SIGNAL ;
    PORT
      LAYER M4 ;
        RECT  0 10.992 0.084 11.016 ;
    END
  END drain_at[30]
  PIN drain_at[31]
    DIRECTION INPUT ;
    USE SIGNAL ;
    PORT
      LAYER M4 ;
        RECT  0 11.088 0.084 11.112 ;
    END
  END drain_at[31]
  PIN drain_at[3]
    DIRECTION INPUT ;
    USE SIGNAL ;
    PORT
      LAYER M4 ;
        RECT  0 8.4 0.084 8.424 ;
    END
  END drain_at[3]
  PIN drain_at[4]
    DIRECTION INPUT ;
    USE SIGNAL ;
    PORT
      LAYER M4 ;
        RECT  0 8.496 0.084 8.52 ;
    END
  END drain_at[4]
  PIN drain_at[5]
    DIRECTION INPUT ;
    USE SIGNAL ;
    PORT
      LAYER M4 ;
        RECT  0 8.592 0.084 8.616 ;
    END
  END drain_at[5]
  PIN drain_at[6]
    DIRECTION INPUT ;
    USE SIGNAL ;
    PORT
      LAYER M4 ;
        RECT  0 8.688 0.084 8.712 ;
    END
  END drain_at[6]
  PIN drain_at[7]
    DIRECTION INPUT ;
    USE SIGNAL ;
    PORT
      LAYER M4 ;
        RECT  0 8.784 0.084 8.808 ;
    END
  END drain_at[7]
  PIN drain_at[8]
    DIRECTION INPUT ;
    USE SIGNAL ;
    PORT
      LAYER M4 ;
        RECT  0 8.88 0.084 8.904 ;
    END
  END drain_at[8]
  PIN drain_at[9]
    DIRECTION INPUT ;
    USE SIGNAL ;
    PORT
      LAYER M4 ;
        RECT  0 8.976 0.084 9 ;
    END
  END drain_at[9]
  PIN issue_at[0]
    DIRECTION INPUT ;
    USE SIGNAL ;
    PORT
      LAYER M4 ;
        RECT  0 1.968 0.084 1.992 ;
    END
  END issue_at[0]
  PIN issue_at[10]
    DIRECTION INPUT ;
    USE SIGNAL ;
    PORT
      LAYER M4 ;
        RECT  0 2.928 0.084 2.952 ;
    END
  END issue_at[10]
  PIN issue_at[11]
    DIRECTION INPUT ;
    USE SIGNAL ;
    PORT
      LAYER M4 ;
        RECT  0 3.024 0.084 3.048 ;
    END
  END issue_at[11]
  PIN issue_at[12]
    DIRECTION INPUT ;
    USE SIGNAL ;
    PORT
      LAYER M4 ;
        RECT  0 3.12 0.084 3.144 ;
    END
  END issue_at[12]
  PIN issue_at[13]
    DIRECTION INPUT ;
    USE SIGNAL ;
    PORT
      LAYER M4 ;
        RECT  0 3.216 0.084 3.24 ;
    END
  END issue_at[13]
  PIN issue_at[14]
    DIRECTION INPUT ;
    USE SIGNAL ;
    PORT
      LAYER M4 ;
        RECT  0 3.312 0.084 3.336 ;
    END
  END issue_at[14]
  PIN issue_at[15]
    DIRECTION INPUT ;
    USE SIGNAL ;
    PORT
      LAYER M4 ;
        RECT  0 3.408 0.084 3.432 ;
    END
  END issue_at[15]
  PIN issue_at[16]
    DIRECTION INPUT ;
    USE SIGNAL ;
    PORT
      LAYER M4 ;
        RECT  0 3.504 0.084 3.528 ;
    END
  END issue_at[16]
  PIN issue_at[17]
    DIRECTION INPUT ;
    USE SIGNAL ;
    PORT
      LAYER M4 ;
        RECT  0 3.6 0.084 3.624 ;
    END
  END issue_at[17]
  PIN issue_at[18]
    DIRECTION INPUT ;
    USE SIGNAL ;
    PORT
      LAYER M4 ;
        RECT  0 3.696 0.084 3.72 ;
    END
  END issue_at[18]
  PIN issue_at[19]
    DIRECTION INPUT ;
    USE SIGNAL ;
    PORT
      LAYER M4 ;
        RECT  0 3.792 0.084 3.816 ;
    END
  END issue_at[19]
  PIN issue_at[1]
    DIRECTION INPUT ;
    USE SIGNAL ;
    PORT
      LAYER M4 ;
        RECT  0 2.064 0.084 2.088 ;
    END
  END issue_at[1]
  PIN issue_at[20]
    DIRECTION INPUT ;
    USE SIGNAL ;
    PORT
      LAYER M4 ;
        RECT  0 3.888 0.084 3.912 ;
    END
  END issue_at[20]
  PIN issue_at[21]
    DIRECTION INPUT ;
    USE SIGNAL ;
    PORT
      LAYER M4 ;
        RECT  0 3.984 0.084 4.008 ;
    END
  END issue_at[21]
  PIN issue_at[22]
    DIRECTION INPUT ;
    USE SIGNAL ;
    PORT
      LAYER M4 ;
        RECT  0 4.08 0.084 4.104 ;
    END
  END issue_at[22]
  PIN issue_at[23]
    DIRECTION INPUT ;
    USE SIGNAL ;
    PORT
      LAYER M4 ;
        RECT  0 4.176 0.084 4.2 ;
    END
  END issue_at[23]
  PIN issue_at[24]
    DIRECTION INPUT ;
    USE SIGNAL ;
    PORT
      LAYER M4 ;
        RECT  0 4.272 0.084 4.296 ;
    END
  END issue_at[24]
  PIN issue_at[25]
    DIRECTION INPUT ;
    USE SIGNAL ;
    PORT
      LAYER M4 ;
        RECT  0 4.368 0.084 4.392 ;
    END
  END issue_at[25]
  PIN issue_at[26]
    DIRECTION INPUT ;
    USE SIGNAL ;
    PORT
      LAYER M4 ;
        RECT  0 4.464 0.084 4.488 ;
    END
  END issue_at[26]
  PIN issue_at[27]
    DIRECTION INPUT ;
    USE SIGNAL ;
    PORT
      LAYER M4 ;
        RECT  0 4.56 0.084 4.584 ;
    END
  END issue_at[27]
  PIN issue_at[28]
    DIRECTION INPUT ;
    USE SIGNAL ;
    PORT
      LAYER M4 ;
        RECT  0 4.656 0.084 4.68 ;
    END
  END issue_at[28]
  PIN issue_at[29]
    DIRECTION INPUT ;
    USE SIGNAL ;
    PORT
      LAYER M4 ;
        RECT  0 4.752 0.084 4.776 ;
    END
  END issue_at[29]
  PIN issue_at[2]
    DIRECTION INPUT ;
    USE SIGNAL ;
    PORT
      LAYER M4 ;
        RECT  0 2.16 0.084 2.184 ;
    END
  END issue_at[2]
  PIN issue_at[30]
    DIRECTION INPUT ;
    USE SIGNAL ;
    PORT
      LAYER M4 ;
        RECT  0 4.848 0.084 4.872 ;
    END
  END issue_at[30]
  PIN issue_at[31]
    DIRECTION INPUT ;
    USE SIGNAL ;
    PORT
      LAYER M4 ;
        RECT  0 4.944 0.084 4.968 ;
    END
  END issue_at[31]
  PIN issue_at[3]
    DIRECTION INPUT ;
    USE SIGNAL ;
    PORT
      LAYER M4 ;
        RECT  0 2.256 0.084 2.28 ;
    END
  END issue_at[3]
  PIN issue_at[4]
    DIRECTION INPUT ;
    USE SIGNAL ;
    PORT
      LAYER M4 ;
        RECT  0 2.352 0.084 2.376 ;
    END
  END issue_at[4]
  PIN issue_at[5]
    DIRECTION INPUT ;
    USE SIGNAL ;
    PORT
      LAYER M4 ;
        RECT  0 2.448 0.084 2.472 ;
    END
  END issue_at[5]
  PIN issue_at[6]
    DIRECTION INPUT ;
    USE SIGNAL ;
    PORT
      LAYER M4 ;
        RECT  0 2.544 0.084 2.568 ;
    END
  END issue_at[6]
  PIN issue_at[7]
    DIRECTION INPUT ;
    USE SIGNAL ;
    PORT
      LAYER M4 ;
        RECT  0 2.64 0.084 2.664 ;
    END
  END issue_at[7]
  PIN issue_at[8]
    DIRECTION INPUT ;
    USE SIGNAL ;
    PORT
      LAYER M4 ;
        RECT  0 2.736 0.084 2.76 ;
    END
  END issue_at[8]
  PIN issue_at[9]
    DIRECTION INPUT ;
    USE SIGNAL ;
    PORT
      LAYER M4 ;
        RECT  0 2.832 0.084 2.856 ;
    END
  END issue_at[9]
  PIN mv[0]
    DIRECTION INPUT ;
    USE SIGNAL ;
    PORT
      LAYER M4 ;
        RECT  0 49.584 0.084 49.608 ;
    END
  END mv[0]
  PIN mv[100]
    DIRECTION INPUT ;
    USE SIGNAL ;
    PORT
      LAYER M4 ;
        RECT  0 40.752 0.084 40.776 ;
    END
  END mv[100]
  PIN mv[101]
    DIRECTION INPUT ;
    USE SIGNAL ;
    PORT
      LAYER M4 ;
        RECT  0 40.848 0.084 40.872 ;
    END
  END mv[101]
  PIN mv[102]
    DIRECTION INPUT ;
    USE SIGNAL ;
    PORT
      LAYER M4 ;
        RECT  0 40.944 0.084 40.968 ;
    END
  END mv[102]
  PIN mv[103]
    DIRECTION INPUT ;
    USE SIGNAL ;
    PORT
      LAYER M4 ;
        RECT  0 41.04 0.084 41.064 ;
    END
  END mv[103]
  PIN mv[104]
    DIRECTION INPUT ;
    USE SIGNAL ;
    PORT
      LAYER M4 ;
        RECT  0 41.136 0.084 41.16 ;
    END
  END mv[104]
  PIN mv[105]
    DIRECTION INPUT ;
    USE SIGNAL ;
    PORT
      LAYER M4 ;
        RECT  0 41.232 0.084 41.256 ;
    END
  END mv[105]
  PIN mv[106]
    DIRECTION INPUT ;
    USE SIGNAL ;
    PORT
      LAYER M4 ;
        RECT  0 41.328 0.084 41.352 ;
    END
  END mv[106]
  PIN mv[107]
    DIRECTION INPUT ;
    USE SIGNAL ;
    PORT
      LAYER M4 ;
        RECT  0 41.424 0.084 41.448 ;
    END
  END mv[107]
  PIN mv[108]
    DIRECTION INPUT ;
    USE SIGNAL ;
    PORT
      LAYER M4 ;
        RECT  0 41.52 0.084 41.544 ;
    END
  END mv[108]
  PIN mv[109]
    DIRECTION INPUT ;
    USE SIGNAL ;
    PORT
      LAYER M4 ;
        RECT  0 41.616 0.084 41.64 ;
    END
  END mv[109]
  PIN mv[10]
    DIRECTION INPUT ;
    USE SIGNAL ;
    PORT
      LAYER M4 ;
        RECT  0 50.544 0.084 50.568 ;
    END
  END mv[10]
  PIN mv[110]
    DIRECTION INPUT ;
    USE SIGNAL ;
    PORT
      LAYER M4 ;
        RECT  0 41.712 0.084 41.736 ;
    END
  END mv[110]
  PIN mv[111]
    DIRECTION INPUT ;
    USE SIGNAL ;
    PORT
      LAYER M4 ;
        RECT  0 41.808 0.084 41.832 ;
    END
  END mv[111]
  PIN mv[112]
    DIRECTION INPUT ;
    USE SIGNAL ;
    PORT
      LAYER M4 ;
        RECT  0 41.904 0.084 41.928 ;
    END
  END mv[112]
  PIN mv[113]
    DIRECTION INPUT ;
    USE SIGNAL ;
    PORT
      LAYER M4 ;
        RECT  0 42 0.084 42.024 ;
    END
  END mv[113]
  PIN mv[114]
    DIRECTION INPUT ;
    USE SIGNAL ;
    PORT
      LAYER M4 ;
        RECT  0 42.096 0.084 42.12 ;
    END
  END mv[114]
  PIN mv[115]
    DIRECTION INPUT ;
    USE SIGNAL ;
    PORT
      LAYER M4 ;
        RECT  0 42.192 0.084 42.216 ;
    END
  END mv[115]
  PIN mv[116]
    DIRECTION INPUT ;
    USE SIGNAL ;
    PORT
      LAYER M4 ;
        RECT  0 42.288 0.084 42.312 ;
    END
  END mv[116]
  PIN mv[117]
    DIRECTION INPUT ;
    USE SIGNAL ;
    PORT
      LAYER M4 ;
        RECT  0 42.384 0.084 42.408 ;
    END
  END mv[117]
  PIN mv[118]
    DIRECTION INPUT ;
    USE SIGNAL ;
    PORT
      LAYER M4 ;
        RECT  0 42.48 0.084 42.504 ;
    END
  END mv[118]
  PIN mv[119]
    DIRECTION INPUT ;
    USE SIGNAL ;
    PORT
      LAYER M4 ;
        RECT  0 42.576 0.084 42.6 ;
    END
  END mv[119]
  PIN mv[11]
    DIRECTION INPUT ;
    USE SIGNAL ;
    PORT
      LAYER M4 ;
        RECT  0 50.64 0.084 50.664 ;
    END
  END mv[11]
  PIN mv[120]
    DIRECTION INPUT ;
    USE SIGNAL ;
    PORT
      LAYER M4 ;
        RECT  0 42.672 0.084 42.696 ;
    END
  END mv[120]
  PIN mv[121]
    DIRECTION INPUT ;
    USE SIGNAL ;
    PORT
      LAYER M4 ;
        RECT  0 42.768 0.084 42.792 ;
    END
  END mv[121]
  PIN mv[122]
    DIRECTION INPUT ;
    USE SIGNAL ;
    PORT
      LAYER M4 ;
        RECT  0 42.864 0.084 42.888 ;
    END
  END mv[122]
  PIN mv[123]
    DIRECTION INPUT ;
    USE SIGNAL ;
    PORT
      LAYER M4 ;
        RECT  0 42.96 0.084 42.984 ;
    END
  END mv[123]
  PIN mv[124]
    DIRECTION INPUT ;
    USE SIGNAL ;
    PORT
      LAYER M4 ;
        RECT  0 43.056 0.084 43.08 ;
    END
  END mv[124]
  PIN mv[125]
    DIRECTION INPUT ;
    USE SIGNAL ;
    PORT
      LAYER M4 ;
        RECT  0 43.152 0.084 43.176 ;
    END
  END mv[125]
  PIN mv[126]
    DIRECTION INPUT ;
    USE SIGNAL ;
    PORT
      LAYER M4 ;
        RECT  0 43.248 0.084 43.272 ;
    END
  END mv[126]
  PIN mv[127]
    DIRECTION INPUT ;
    USE SIGNAL ;
    PORT
      LAYER M4 ;
        RECT  0 43.344 0.084 43.368 ;
    END
  END mv[127]
  PIN mv[128]
    DIRECTION INPUT ;
    USE SIGNAL ;
    PORT
      LAYER M4 ;
        RECT  0 37.296 0.084 37.32 ;
    END
  END mv[128]
  PIN mv[129]
    DIRECTION INPUT ;
    USE SIGNAL ;
    PORT
      LAYER M4 ;
        RECT  0 37.392 0.084 37.416 ;
    END
  END mv[129]
  PIN mv[12]
    DIRECTION INPUT ;
    USE SIGNAL ;
    PORT
      LAYER M4 ;
        RECT  0 50.736 0.084 50.76 ;
    END
  END mv[12]
  PIN mv[130]
    DIRECTION INPUT ;
    USE SIGNAL ;
    PORT
      LAYER M4 ;
        RECT  0 37.488 0.084 37.512 ;
    END
  END mv[130]
  PIN mv[131]
    DIRECTION INPUT ;
    USE SIGNAL ;
    PORT
      LAYER M4 ;
        RECT  0 37.584 0.084 37.608 ;
    END
  END mv[131]
  PIN mv[132]
    DIRECTION INPUT ;
    USE SIGNAL ;
    PORT
      LAYER M4 ;
        RECT  0 37.68 0.084 37.704 ;
    END
  END mv[132]
  PIN mv[133]
    DIRECTION INPUT ;
    USE SIGNAL ;
    PORT
      LAYER M4 ;
        RECT  0 37.776 0.084 37.8 ;
    END
  END mv[133]
  PIN mv[134]
    DIRECTION INPUT ;
    USE SIGNAL ;
    PORT
      LAYER M4 ;
        RECT  0 37.872 0.084 37.896 ;
    END
  END mv[134]
  PIN mv[135]
    DIRECTION INPUT ;
    USE SIGNAL ;
    PORT
      LAYER M4 ;
        RECT  0 37.968 0.084 37.992 ;
    END
  END mv[135]
  PIN mv[136]
    DIRECTION INPUT ;
    USE SIGNAL ;
    PORT
      LAYER M4 ;
        RECT  0 38.064 0.084 38.088 ;
    END
  END mv[136]
  PIN mv[137]
    DIRECTION INPUT ;
    USE SIGNAL ;
    PORT
      LAYER M4 ;
        RECT  0 38.16 0.084 38.184 ;
    END
  END mv[137]
  PIN mv[138]
    DIRECTION INPUT ;
    USE SIGNAL ;
    PORT
      LAYER M4 ;
        RECT  0 38.256 0.084 38.28 ;
    END
  END mv[138]
  PIN mv[139]
    DIRECTION INPUT ;
    USE SIGNAL ;
    PORT
      LAYER M4 ;
        RECT  0 38.352 0.084 38.376 ;
    END
  END mv[139]
  PIN mv[13]
    DIRECTION INPUT ;
    USE SIGNAL ;
    PORT
      LAYER M4 ;
        RECT  0 50.832 0.084 50.856 ;
    END
  END mv[13]
  PIN mv[140]
    DIRECTION INPUT ;
    USE SIGNAL ;
    PORT
      LAYER M4 ;
        RECT  0 38.448 0.084 38.472 ;
    END
  END mv[140]
  PIN mv[141]
    DIRECTION INPUT ;
    USE SIGNAL ;
    PORT
      LAYER M4 ;
        RECT  0 38.544 0.084 38.568 ;
    END
  END mv[141]
  PIN mv[142]
    DIRECTION INPUT ;
    USE SIGNAL ;
    PORT
      LAYER M4 ;
        RECT  0 38.64 0.084 38.664 ;
    END
  END mv[142]
  PIN mv[143]
    DIRECTION INPUT ;
    USE SIGNAL ;
    PORT
      LAYER M4 ;
        RECT  0 38.736 0.084 38.76 ;
    END
  END mv[143]
  PIN mv[144]
    DIRECTION INPUT ;
    USE SIGNAL ;
    PORT
      LAYER M4 ;
        RECT  0 38.832 0.084 38.856 ;
    END
  END mv[144]
  PIN mv[145]
    DIRECTION INPUT ;
    USE SIGNAL ;
    PORT
      LAYER M4 ;
        RECT  0 38.928 0.084 38.952 ;
    END
  END mv[145]
  PIN mv[146]
    DIRECTION INPUT ;
    USE SIGNAL ;
    PORT
      LAYER M4 ;
        RECT  0 39.024 0.084 39.048 ;
    END
  END mv[146]
  PIN mv[147]
    DIRECTION INPUT ;
    USE SIGNAL ;
    PORT
      LAYER M4 ;
        RECT  0 39.12 0.084 39.144 ;
    END
  END mv[147]
  PIN mv[148]
    DIRECTION INPUT ;
    USE SIGNAL ;
    PORT
      LAYER M4 ;
        RECT  0 39.216 0.084 39.24 ;
    END
  END mv[148]
  PIN mv[149]
    DIRECTION INPUT ;
    USE SIGNAL ;
    PORT
      LAYER M4 ;
        RECT  0 39.312 0.084 39.336 ;
    END
  END mv[149]
  PIN mv[14]
    DIRECTION INPUT ;
    USE SIGNAL ;
    PORT
      LAYER M4 ;
        RECT  0 50.928 0.084 50.952 ;
    END
  END mv[14]
  PIN mv[150]
    DIRECTION INPUT ;
    USE SIGNAL ;
    PORT
      LAYER M4 ;
        RECT  0 39.408 0.084 39.432 ;
    END
  END mv[150]
  PIN mv[151]
    DIRECTION INPUT ;
    USE SIGNAL ;
    PORT
      LAYER M4 ;
        RECT  0 39.504 0.084 39.528 ;
    END
  END mv[151]
  PIN mv[152]
    DIRECTION INPUT ;
    USE SIGNAL ;
    PORT
      LAYER M4 ;
        RECT  0 39.6 0.084 39.624 ;
    END
  END mv[152]
  PIN mv[153]
    DIRECTION INPUT ;
    USE SIGNAL ;
    PORT
      LAYER M4 ;
        RECT  0 39.696 0.084 39.72 ;
    END
  END mv[153]
  PIN mv[154]
    DIRECTION INPUT ;
    USE SIGNAL ;
    PORT
      LAYER M4 ;
        RECT  0 39.792 0.084 39.816 ;
    END
  END mv[154]
  PIN mv[155]
    DIRECTION INPUT ;
    USE SIGNAL ;
    PORT
      LAYER M4 ;
        RECT  0 39.888 0.084 39.912 ;
    END
  END mv[155]
  PIN mv[156]
    DIRECTION INPUT ;
    USE SIGNAL ;
    PORT
      LAYER M4 ;
        RECT  0 39.984 0.084 40.008 ;
    END
  END mv[156]
  PIN mv[157]
    DIRECTION INPUT ;
    USE SIGNAL ;
    PORT
      LAYER M4 ;
        RECT  0 40.08 0.084 40.104 ;
    END
  END mv[157]
  PIN mv[158]
    DIRECTION INPUT ;
    USE SIGNAL ;
    PORT
      LAYER M4 ;
        RECT  0 40.176 0.084 40.2 ;
    END
  END mv[158]
  PIN mv[159]
    DIRECTION INPUT ;
    USE SIGNAL ;
    PORT
      LAYER M4 ;
        RECT  0 40.272 0.084 40.296 ;
    END
  END mv[159]
  PIN mv[15]
    DIRECTION INPUT ;
    USE SIGNAL ;
    PORT
      LAYER M4 ;
        RECT  0 51.024 0.084 51.048 ;
    END
  END mv[15]
  PIN mv[160]
    DIRECTION INPUT ;
    USE SIGNAL ;
    PORT
      LAYER M4 ;
        RECT  0 46.512 0.084 46.536 ;
    END
  END mv[160]
  PIN mv[161]
    DIRECTION INPUT ;
    USE SIGNAL ;
    PORT
      LAYER M4 ;
        RECT  0 46.608 0.084 46.632 ;
    END
  END mv[161]
  PIN mv[162]
    DIRECTION INPUT ;
    USE SIGNAL ;
    PORT
      LAYER M4 ;
        RECT  0 46.704 0.084 46.728 ;
    END
  END mv[162]
  PIN mv[163]
    DIRECTION INPUT ;
    USE SIGNAL ;
    PORT
      LAYER M4 ;
        RECT  0 46.8 0.084 46.824 ;
    END
  END mv[163]
  PIN mv[164]
    DIRECTION INPUT ;
    USE SIGNAL ;
    PORT
      LAYER M4 ;
        RECT  0 46.896 0.084 46.92 ;
    END
  END mv[164]
  PIN mv[165]
    DIRECTION INPUT ;
    USE SIGNAL ;
    PORT
      LAYER M4 ;
        RECT  0 46.992 0.084 47.016 ;
    END
  END mv[165]
  PIN mv[166]
    DIRECTION INPUT ;
    USE SIGNAL ;
    PORT
      LAYER M4 ;
        RECT  0 47.088 0.084 47.112 ;
    END
  END mv[166]
  PIN mv[167]
    DIRECTION INPUT ;
    USE SIGNAL ;
    PORT
      LAYER M4 ;
        RECT  0 47.184 0.084 47.208 ;
    END
  END mv[167]
  PIN mv[168]
    DIRECTION INPUT ;
    USE SIGNAL ;
    PORT
      LAYER M4 ;
        RECT  0 47.28 0.084 47.304 ;
    END
  END mv[168]
  PIN mv[169]
    DIRECTION INPUT ;
    USE SIGNAL ;
    PORT
      LAYER M4 ;
        RECT  0 47.376 0.084 47.4 ;
    END
  END mv[169]
  PIN mv[16]
    DIRECTION INPUT ;
    USE SIGNAL ;
    PORT
      LAYER M4 ;
        RECT  0 51.12 0.084 51.144 ;
    END
  END mv[16]
  PIN mv[170]
    DIRECTION INPUT ;
    USE SIGNAL ;
    PORT
      LAYER M4 ;
        RECT  0 47.472 0.084 47.496 ;
    END
  END mv[170]
  PIN mv[171]
    DIRECTION INPUT ;
    USE SIGNAL ;
    PORT
      LAYER M4 ;
        RECT  0 47.568 0.084 47.592 ;
    END
  END mv[171]
  PIN mv[172]
    DIRECTION INPUT ;
    USE SIGNAL ;
    PORT
      LAYER M4 ;
        RECT  0 47.664 0.084 47.688 ;
    END
  END mv[172]
  PIN mv[173]
    DIRECTION INPUT ;
    USE SIGNAL ;
    PORT
      LAYER M4 ;
        RECT  0 47.76 0.084 47.784 ;
    END
  END mv[173]
  PIN mv[174]
    DIRECTION INPUT ;
    USE SIGNAL ;
    PORT
      LAYER M4 ;
        RECT  0 47.856 0.084 47.88 ;
    END
  END mv[174]
  PIN mv[175]
    DIRECTION INPUT ;
    USE SIGNAL ;
    PORT
      LAYER M4 ;
        RECT  0 47.952 0.084 47.976 ;
    END
  END mv[175]
  PIN mv[176]
    DIRECTION INPUT ;
    USE SIGNAL ;
    PORT
      LAYER M4 ;
        RECT  0 48.048 0.084 48.072 ;
    END
  END mv[176]
  PIN mv[177]
    DIRECTION INPUT ;
    USE SIGNAL ;
    PORT
      LAYER M4 ;
        RECT  0 48.144 0.084 48.168 ;
    END
  END mv[177]
  PIN mv[178]
    DIRECTION INPUT ;
    USE SIGNAL ;
    PORT
      LAYER M4 ;
        RECT  0 48.24 0.084 48.264 ;
    END
  END mv[178]
  PIN mv[179]
    DIRECTION INPUT ;
    USE SIGNAL ;
    PORT
      LAYER M4 ;
        RECT  0 48.336 0.084 48.36 ;
    END
  END mv[179]
  PIN mv[17]
    DIRECTION INPUT ;
    USE SIGNAL ;
    PORT
      LAYER M4 ;
        RECT  0 51.216 0.084 51.24 ;
    END
  END mv[17]
  PIN mv[180]
    DIRECTION INPUT ;
    USE SIGNAL ;
    PORT
      LAYER M4 ;
        RECT  0 48.432 0.084 48.456 ;
    END
  END mv[180]
  PIN mv[181]
    DIRECTION INPUT ;
    USE SIGNAL ;
    PORT
      LAYER M4 ;
        RECT  0 48.528 0.084 48.552 ;
    END
  END mv[181]
  PIN mv[182]
    DIRECTION INPUT ;
    USE SIGNAL ;
    PORT
      LAYER M4 ;
        RECT  0 48.624 0.084 48.648 ;
    END
  END mv[182]
  PIN mv[183]
    DIRECTION INPUT ;
    USE SIGNAL ;
    PORT
      LAYER M4 ;
        RECT  0 48.72 0.084 48.744 ;
    END
  END mv[183]
  PIN mv[184]
    DIRECTION INPUT ;
    USE SIGNAL ;
    PORT
      LAYER M4 ;
        RECT  0 48.816 0.084 48.84 ;
    END
  END mv[184]
  PIN mv[185]
    DIRECTION INPUT ;
    USE SIGNAL ;
    PORT
      LAYER M4 ;
        RECT  0 48.912 0.084 48.936 ;
    END
  END mv[185]
  PIN mv[186]
    DIRECTION INPUT ;
    USE SIGNAL ;
    PORT
      LAYER M4 ;
        RECT  0 49.008 0.084 49.032 ;
    END
  END mv[186]
  PIN mv[187]
    DIRECTION INPUT ;
    USE SIGNAL ;
    PORT
      LAYER M4 ;
        RECT  0 49.104 0.084 49.128 ;
    END
  END mv[187]
  PIN mv[188]
    DIRECTION INPUT ;
    USE SIGNAL ;
    PORT
      LAYER M4 ;
        RECT  0 49.2 0.084 49.224 ;
    END
  END mv[188]
  PIN mv[189]
    DIRECTION INPUT ;
    USE SIGNAL ;
    PORT
      LAYER M4 ;
        RECT  0 49.296 0.084 49.32 ;
    END
  END mv[189]
  PIN mv[18]
    DIRECTION INPUT ;
    USE SIGNAL ;
    PORT
      LAYER M4 ;
        RECT  0 51.312 0.084 51.336 ;
    END
  END mv[18]
  PIN mv[190]
    DIRECTION INPUT ;
    USE SIGNAL ;
    PORT
      LAYER M4 ;
        RECT  0 49.392 0.084 49.416 ;
    END
  END mv[190]
  PIN mv[191]
    DIRECTION INPUT ;
    USE SIGNAL ;
    PORT
      LAYER M4 ;
        RECT  0 49.488 0.084 49.512 ;
    END
  END mv[191]
  PIN mv[192]
    DIRECTION INPUT ;
    USE SIGNAL ;
    PORT
      LAYER M4 ;
        RECT  0 56.496 0.084 56.52 ;
    END
  END mv[192]
  PIN mv[193]
    DIRECTION INPUT ;
    USE SIGNAL ;
    PORT
      LAYER M4 ;
        RECT  0 56.592 0.084 56.616 ;
    END
  END mv[193]
  PIN mv[194]
    DIRECTION INPUT ;
    USE SIGNAL ;
    PORT
      LAYER M4 ;
        RECT  0 56.688 0.084 56.712 ;
    END
  END mv[194]
  PIN mv[195]
    DIRECTION INPUT ;
    USE SIGNAL ;
    PORT
      LAYER M4 ;
        RECT  0 56.784 0.084 56.808 ;
    END
  END mv[195]
  PIN mv[196]
    DIRECTION INPUT ;
    USE SIGNAL ;
    PORT
      LAYER M4 ;
        RECT  0 56.88 0.084 56.904 ;
    END
  END mv[196]
  PIN mv[197]
    DIRECTION INPUT ;
    USE SIGNAL ;
    PORT
      LAYER M4 ;
        RECT  0 56.976 0.084 57 ;
    END
  END mv[197]
  PIN mv[198]
    DIRECTION INPUT ;
    USE SIGNAL ;
    PORT
      LAYER M4 ;
        RECT  0 57.072 0.084 57.096 ;
    END
  END mv[198]
  PIN mv[199]
    DIRECTION INPUT ;
    USE SIGNAL ;
    PORT
      LAYER M4 ;
        RECT  0 57.168 0.084 57.192 ;
    END
  END mv[199]
  PIN mv[19]
    DIRECTION INPUT ;
    USE SIGNAL ;
    PORT
      LAYER M4 ;
        RECT  0 51.408 0.084 51.432 ;
    END
  END mv[19]
  PIN mv[1]
    DIRECTION INPUT ;
    USE SIGNAL ;
    PORT
      LAYER M4 ;
        RECT  0 49.68 0.084 49.704 ;
    END
  END mv[1]
  PIN mv[200]
    DIRECTION INPUT ;
    USE SIGNAL ;
    PORT
      LAYER M4 ;
        RECT  0 57.264 0.084 57.288 ;
    END
  END mv[200]
  PIN mv[201]
    DIRECTION INPUT ;
    USE SIGNAL ;
    PORT
      LAYER M4 ;
        RECT  0 57.36 0.084 57.384 ;
    END
  END mv[201]
  PIN mv[202]
    DIRECTION INPUT ;
    USE SIGNAL ;
    PORT
      LAYER M4 ;
        RECT  0 57.456 0.084 57.48 ;
    END
  END mv[202]
  PIN mv[203]
    DIRECTION INPUT ;
    USE SIGNAL ;
    PORT
      LAYER M4 ;
        RECT  0 57.552 0.084 57.576 ;
    END
  END mv[203]
  PIN mv[204]
    DIRECTION INPUT ;
    USE SIGNAL ;
    PORT
      LAYER M4 ;
        RECT  0 57.648 0.084 57.672 ;
    END
  END mv[204]
  PIN mv[205]
    DIRECTION INPUT ;
    USE SIGNAL ;
    PORT
      LAYER M4 ;
        RECT  0 57.744 0.084 57.768 ;
    END
  END mv[205]
  PIN mv[206]
    DIRECTION INPUT ;
    USE SIGNAL ;
    PORT
      LAYER M4 ;
        RECT  0 57.84 0.084 57.864 ;
    END
  END mv[206]
  PIN mv[207]
    DIRECTION INPUT ;
    USE SIGNAL ;
    PORT
      LAYER M4 ;
        RECT  0 57.936 0.084 57.96 ;
    END
  END mv[207]
  PIN mv[208]
    DIRECTION INPUT ;
    USE SIGNAL ;
    PORT
      LAYER M4 ;
        RECT  0 58.032 0.084 58.056 ;
    END
  END mv[208]
  PIN mv[209]
    DIRECTION INPUT ;
    USE SIGNAL ;
    PORT
      LAYER M4 ;
        RECT  0 58.128 0.084 58.152 ;
    END
  END mv[209]
  PIN mv[20]
    DIRECTION INPUT ;
    USE SIGNAL ;
    PORT
      LAYER M4 ;
        RECT  0 51.504 0.084 51.528 ;
    END
  END mv[20]
  PIN mv[210]
    DIRECTION INPUT ;
    USE SIGNAL ;
    PORT
      LAYER M4 ;
        RECT  0 58.224 0.084 58.248 ;
    END
  END mv[210]
  PIN mv[211]
    DIRECTION INPUT ;
    USE SIGNAL ;
    PORT
      LAYER M4 ;
        RECT  0 58.32 0.084 58.344 ;
    END
  END mv[211]
  PIN mv[212]
    DIRECTION INPUT ;
    USE SIGNAL ;
    PORT
      LAYER M4 ;
        RECT  0 58.416 0.084 58.44 ;
    END
  END mv[212]
  PIN mv[213]
    DIRECTION INPUT ;
    USE SIGNAL ;
    PORT
      LAYER M4 ;
        RECT  0 58.512 0.084 58.536 ;
    END
  END mv[213]
  PIN mv[214]
    DIRECTION INPUT ;
    USE SIGNAL ;
    PORT
      LAYER M4 ;
        RECT  0 58.608 0.084 58.632 ;
    END
  END mv[214]
  PIN mv[215]
    DIRECTION INPUT ;
    USE SIGNAL ;
    PORT
      LAYER M4 ;
        RECT  0 58.704 0.084 58.728 ;
    END
  END mv[215]
  PIN mv[216]
    DIRECTION INPUT ;
    USE SIGNAL ;
    PORT
      LAYER M4 ;
        RECT  0 58.8 0.084 58.824 ;
    END
  END mv[216]
  PIN mv[217]
    DIRECTION INPUT ;
    USE SIGNAL ;
    PORT
      LAYER M4 ;
        RECT  0 58.896 0.084 58.92 ;
    END
  END mv[217]
  PIN mv[218]
    DIRECTION INPUT ;
    USE SIGNAL ;
    PORT
      LAYER M4 ;
        RECT  0 58.992 0.084 59.016 ;
    END
  END mv[218]
  PIN mv[219]
    DIRECTION INPUT ;
    USE SIGNAL ;
    PORT
      LAYER M4 ;
        RECT  0 59.088 0.084 59.112 ;
    END
  END mv[219]
  PIN mv[21]
    DIRECTION INPUT ;
    USE SIGNAL ;
    PORT
      LAYER M4 ;
        RECT  0 51.6 0.084 51.624 ;
    END
  END mv[21]
  PIN mv[220]
    DIRECTION INPUT ;
    USE SIGNAL ;
    PORT
      LAYER M4 ;
        RECT  0 59.184 0.084 59.208 ;
    END
  END mv[220]
  PIN mv[221]
    DIRECTION INPUT ;
    USE SIGNAL ;
    PORT
      LAYER M4 ;
        RECT  0 59.28 0.084 59.304 ;
    END
  END mv[221]
  PIN mv[222]
    DIRECTION INPUT ;
    USE SIGNAL ;
    PORT
      LAYER M4 ;
        RECT  0 59.376 0.084 59.4 ;
    END
  END mv[222]
  PIN mv[223]
    DIRECTION INPUT ;
    USE SIGNAL ;
    PORT
      LAYER M4 ;
        RECT  0 59.472 0.084 59.496 ;
    END
  END mv[223]
  PIN mv[224]
    DIRECTION INPUT ;
    USE SIGNAL ;
    PORT
      LAYER M4 ;
        RECT  0 22.224 0.084 22.248 ;
    END
  END mv[224]
  PIN mv[225]
    DIRECTION INPUT ;
    USE SIGNAL ;
    PORT
      LAYER M4 ;
        RECT  0 22.32 0.084 22.344 ;
    END
  END mv[225]
  PIN mv[226]
    DIRECTION INPUT ;
    USE SIGNAL ;
    PORT
      LAYER M4 ;
        RECT  0 22.416 0.084 22.44 ;
    END
  END mv[226]
  PIN mv[22]
    DIRECTION INPUT ;
    USE SIGNAL ;
    PORT
      LAYER M4 ;
        RECT  0 51.696 0.084 51.72 ;
    END
  END mv[22]
  PIN mv[23]
    DIRECTION INPUT ;
    USE SIGNAL ;
    PORT
      LAYER M4 ;
        RECT  0 51.792 0.084 51.816 ;
    END
  END mv[23]
  PIN mv[24]
    DIRECTION INPUT ;
    USE SIGNAL ;
    PORT
      LAYER M4 ;
        RECT  0 51.888 0.084 51.912 ;
    END
  END mv[24]
  PIN mv[25]
    DIRECTION INPUT ;
    USE SIGNAL ;
    PORT
      LAYER M4 ;
        RECT  0 51.984 0.084 52.008 ;
    END
  END mv[25]
  PIN mv[26]
    DIRECTION INPUT ;
    USE SIGNAL ;
    PORT
      LAYER M4 ;
        RECT  0 52.08 0.084 52.104 ;
    END
  END mv[26]
  PIN mv[27]
    DIRECTION INPUT ;
    USE SIGNAL ;
    PORT
      LAYER M4 ;
        RECT  0 52.176 0.084 52.2 ;
    END
  END mv[27]
  PIN mv[28]
    DIRECTION INPUT ;
    USE SIGNAL ;
    PORT
      LAYER M4 ;
        RECT  0 52.272 0.084 52.296 ;
    END
  END mv[28]
  PIN mv[29]
    DIRECTION INPUT ;
    USE SIGNAL ;
    PORT
      LAYER M4 ;
        RECT  0 52.368 0.084 52.392 ;
    END
  END mv[29]
  PIN mv[2]
    DIRECTION INPUT ;
    USE SIGNAL ;
    PORT
      LAYER M4 ;
        RECT  0 49.776 0.084 49.8 ;
    END
  END mv[2]
  PIN mv[30]
    DIRECTION INPUT ;
    USE SIGNAL ;
    PORT
      LAYER M4 ;
        RECT  0 52.464 0.084 52.488 ;
    END
  END mv[30]
  PIN mv[31]
    DIRECTION INPUT ;
    USE SIGNAL ;
    PORT
      LAYER M4 ;
        RECT  0 52.56 0.084 52.584 ;
    END
  END mv[31]
  PIN mv[32]
    DIRECTION INPUT ;
    USE SIGNAL ;
    PORT
      LAYER M4 ;
        RECT  0 24.24 0.084 24.264 ;
    END
  END mv[32]
  PIN mv[33]
    DIRECTION INPUT ;
    USE SIGNAL ;
    PORT
      LAYER M4 ;
        RECT  0 24.336 0.084 24.36 ;
    END
  END mv[33]
  PIN mv[34]
    DIRECTION INPUT ;
    USE SIGNAL ;
    PORT
      LAYER M4 ;
        RECT  0 24.432 0.084 24.456 ;
    END
  END mv[34]
  PIN mv[35]
    DIRECTION INPUT ;
    USE SIGNAL ;
    PORT
      LAYER M4 ;
        RECT  0 24.528 0.084 24.552 ;
    END
  END mv[35]
  PIN mv[36]
    DIRECTION INPUT ;
    USE SIGNAL ;
    PORT
      LAYER M4 ;
        RECT  0 24.624 0.084 24.648 ;
    END
  END mv[36]
  PIN mv[37]
    DIRECTION INPUT ;
    USE SIGNAL ;
    PORT
      LAYER M4 ;
        RECT  0 24.72 0.084 24.744 ;
    END
  END mv[37]
  PIN mv[38]
    DIRECTION INPUT ;
    USE SIGNAL ;
    PORT
      LAYER M4 ;
        RECT  0 24.816 0.084 24.84 ;
    END
  END mv[38]
  PIN mv[39]
    DIRECTION INPUT ;
    USE SIGNAL ;
    PORT
      LAYER M4 ;
        RECT  0 24.912 0.084 24.936 ;
    END
  END mv[39]
  PIN mv[3]
    DIRECTION INPUT ;
    USE SIGNAL ;
    PORT
      LAYER M4 ;
        RECT  0 49.872 0.084 49.896 ;
    END
  END mv[3]
  PIN mv[40]
    DIRECTION INPUT ;
    USE SIGNAL ;
    PORT
      LAYER M4 ;
        RECT  0 25.008 0.084 25.032 ;
    END
  END mv[40]
  PIN mv[41]
    DIRECTION INPUT ;
    USE SIGNAL ;
    PORT
      LAYER M4 ;
        RECT  0 25.104 0.084 25.128 ;
    END
  END mv[41]
  PIN mv[42]
    DIRECTION INPUT ;
    USE SIGNAL ;
    PORT
      LAYER M4 ;
        RECT  0 25.2 0.084 25.224 ;
    END
  END mv[42]
  PIN mv[43]
    DIRECTION INPUT ;
    USE SIGNAL ;
    PORT
      LAYER M4 ;
        RECT  0 25.296 0.084 25.32 ;
    END
  END mv[43]
  PIN mv[44]
    DIRECTION INPUT ;
    USE SIGNAL ;
    PORT
      LAYER M4 ;
        RECT  0 25.392 0.084 25.416 ;
    END
  END mv[44]
  PIN mv[45]
    DIRECTION INPUT ;
    USE SIGNAL ;
    PORT
      LAYER M4 ;
        RECT  0 25.488 0.084 25.512 ;
    END
  END mv[45]
  PIN mv[46]
    DIRECTION INPUT ;
    USE SIGNAL ;
    PORT
      LAYER M4 ;
        RECT  0 25.584 0.084 25.608 ;
    END
  END mv[46]
  PIN mv[47]
    DIRECTION INPUT ;
    USE SIGNAL ;
    PORT
      LAYER M4 ;
        RECT  0 25.68 0.084 25.704 ;
    END
  END mv[47]
  PIN mv[48]
    DIRECTION INPUT ;
    USE SIGNAL ;
    PORT
      LAYER M4 ;
        RECT  0 25.776 0.084 25.8 ;
    END
  END mv[48]
  PIN mv[49]
    DIRECTION INPUT ;
    USE SIGNAL ;
    PORT
      LAYER M4 ;
        RECT  0 25.872 0.084 25.896 ;
    END
  END mv[49]
  PIN mv[4]
    DIRECTION INPUT ;
    USE SIGNAL ;
    PORT
      LAYER M4 ;
        RECT  0 49.968 0.084 49.992 ;
    END
  END mv[4]
  PIN mv[50]
    DIRECTION INPUT ;
    USE SIGNAL ;
    PORT
      LAYER M4 ;
        RECT  0 25.968 0.084 25.992 ;
    END
  END mv[50]
  PIN mv[51]
    DIRECTION INPUT ;
    USE SIGNAL ;
    PORT
      LAYER M4 ;
        RECT  0 26.064 0.084 26.088 ;
    END
  END mv[51]
  PIN mv[52]
    DIRECTION INPUT ;
    USE SIGNAL ;
    PORT
      LAYER M4 ;
        RECT  0 26.16 0.084 26.184 ;
    END
  END mv[52]
  PIN mv[53]
    DIRECTION INPUT ;
    USE SIGNAL ;
    PORT
      LAYER M4 ;
        RECT  0 26.256 0.084 26.28 ;
    END
  END mv[53]
  PIN mv[54]
    DIRECTION INPUT ;
    USE SIGNAL ;
    PORT
      LAYER M4 ;
        RECT  0 26.352 0.084 26.376 ;
    END
  END mv[54]
  PIN mv[55]
    DIRECTION INPUT ;
    USE SIGNAL ;
    PORT
      LAYER M4 ;
        RECT  0 26.448 0.084 26.472 ;
    END
  END mv[55]
  PIN mv[56]
    DIRECTION INPUT ;
    USE SIGNAL ;
    PORT
      LAYER M4 ;
        RECT  0 26.544 0.084 26.568 ;
    END
  END mv[56]
  PIN mv[57]
    DIRECTION INPUT ;
    USE SIGNAL ;
    PORT
      LAYER M4 ;
        RECT  0 26.64 0.084 26.664 ;
    END
  END mv[57]
  PIN mv[58]
    DIRECTION INPUT ;
    USE SIGNAL ;
    PORT
      LAYER M4 ;
        RECT  0 26.736 0.084 26.76 ;
    END
  END mv[58]
  PIN mv[59]
    DIRECTION INPUT ;
    USE SIGNAL ;
    PORT
      LAYER M4 ;
        RECT  0 26.832 0.084 26.856 ;
    END
  END mv[59]
  PIN mv[5]
    DIRECTION INPUT ;
    USE SIGNAL ;
    PORT
      LAYER M4 ;
        RECT  0 50.064 0.084 50.088 ;
    END
  END mv[5]
  PIN mv[60]
    DIRECTION INPUT ;
    USE SIGNAL ;
    PORT
      LAYER M4 ;
        RECT  0 26.928 0.084 26.952 ;
    END
  END mv[60]
  PIN mv[61]
    DIRECTION INPUT ;
    USE SIGNAL ;
    PORT
      LAYER M4 ;
        RECT  0 27.024 0.084 27.048 ;
    END
  END mv[61]
  PIN mv[62]
    DIRECTION INPUT ;
    USE SIGNAL ;
    PORT
      LAYER M4 ;
        RECT  0 27.12 0.084 27.144 ;
    END
  END mv[62]
  PIN mv[63]
    DIRECTION INPUT ;
    USE SIGNAL ;
    PORT
      LAYER M4 ;
        RECT  0 27.216 0.084 27.24 ;
    END
  END mv[63]
  PIN mv[64]
    DIRECTION INPUT ;
    USE SIGNAL ;
    PORT
      LAYER M4 ;
        RECT  0 52.656 0.084 52.68 ;
    END
  END mv[64]
  PIN mv[65]
    DIRECTION INPUT ;
    USE SIGNAL ;
    PORT
      LAYER M4 ;
        RECT  0 52.752 0.084 52.776 ;
    END
  END mv[65]
  PIN mv[66]
    DIRECTION INPUT ;
    USE SIGNAL ;
    PORT
      LAYER M4 ;
        RECT  0 52.848 0.084 52.872 ;
    END
  END mv[66]
  PIN mv[67]
    DIRECTION INPUT ;
    USE SIGNAL ;
    PORT
      LAYER M4 ;
        RECT  0 52.944 0.084 52.968 ;
    END
  END mv[67]
  PIN mv[68]
    DIRECTION INPUT ;
    USE SIGNAL ;
    PORT
      LAYER M4 ;
        RECT  0 53.04 0.084 53.064 ;
    END
  END mv[68]
  PIN mv[69]
    DIRECTION INPUT ;
    USE SIGNAL ;
    PORT
      LAYER M4 ;
        RECT  0 53.136 0.084 53.16 ;
    END
  END mv[69]
  PIN mv[6]
    DIRECTION INPUT ;
    USE SIGNAL ;
    PORT
      LAYER M4 ;
        RECT  0 50.16 0.084 50.184 ;
    END
  END mv[6]
  PIN mv[70]
    DIRECTION INPUT ;
    USE SIGNAL ;
    PORT
      LAYER M4 ;
        RECT  0 53.232 0.084 53.256 ;
    END
  END mv[70]
  PIN mv[71]
    DIRECTION INPUT ;
    USE SIGNAL ;
    PORT
      LAYER M4 ;
        RECT  0 53.328 0.084 53.352 ;
    END
  END mv[71]
  PIN mv[72]
    DIRECTION INPUT ;
    USE SIGNAL ;
    PORT
      LAYER M4 ;
        RECT  0 53.424 0.084 53.448 ;
    END
  END mv[72]
  PIN mv[73]
    DIRECTION INPUT ;
    USE SIGNAL ;
    PORT
      LAYER M4 ;
        RECT  0 53.52 0.084 53.544 ;
    END
  END mv[73]
  PIN mv[74]
    DIRECTION INPUT ;
    USE SIGNAL ;
    PORT
      LAYER M4 ;
        RECT  0 53.616 0.084 53.64 ;
    END
  END mv[74]
  PIN mv[75]
    DIRECTION INPUT ;
    USE SIGNAL ;
    PORT
      LAYER M4 ;
        RECT  0 53.712 0.084 53.736 ;
    END
  END mv[75]
  PIN mv[76]
    DIRECTION INPUT ;
    USE SIGNAL ;
    PORT
      LAYER M4 ;
        RECT  0 53.808 0.084 53.832 ;
    END
  END mv[76]
  PIN mv[77]
    DIRECTION INPUT ;
    USE SIGNAL ;
    PORT
      LAYER M4 ;
        RECT  0 53.904 0.084 53.928 ;
    END
  END mv[77]
  PIN mv[78]
    DIRECTION INPUT ;
    USE SIGNAL ;
    PORT
      LAYER M4 ;
        RECT  0 54 0.084 54.024 ;
    END
  END mv[78]
  PIN mv[79]
    DIRECTION INPUT ;
    USE SIGNAL ;
    PORT
      LAYER M4 ;
        RECT  0 54.096 0.084 54.12 ;
    END
  END mv[79]
  PIN mv[7]
    DIRECTION INPUT ;
    USE SIGNAL ;
    PORT
      LAYER M4 ;
        RECT  0 50.256 0.084 50.28 ;
    END
  END mv[7]
  PIN mv[80]
    DIRECTION INPUT ;
    USE SIGNAL ;
    PORT
      LAYER M4 ;
        RECT  0 54.192 0.084 54.216 ;
    END
  END mv[80]
  PIN mv[81]
    DIRECTION INPUT ;
    USE SIGNAL ;
    PORT
      LAYER M4 ;
        RECT  0 54.288 0.084 54.312 ;
    END
  END mv[81]
  PIN mv[82]
    DIRECTION INPUT ;
    USE SIGNAL ;
    PORT
      LAYER M4 ;
        RECT  0 54.384 0.084 54.408 ;
    END
  END mv[82]
  PIN mv[83]
    DIRECTION INPUT ;
    USE SIGNAL ;
    PORT
      LAYER M4 ;
        RECT  0 54.48 0.084 54.504 ;
    END
  END mv[83]
  PIN mv[84]
    DIRECTION INPUT ;
    USE SIGNAL ;
    PORT
      LAYER M4 ;
        RECT  0 54.576 0.084 54.6 ;
    END
  END mv[84]
  PIN mv[85]
    DIRECTION INPUT ;
    USE SIGNAL ;
    PORT
      LAYER M4 ;
        RECT  0 54.672 0.084 54.696 ;
    END
  END mv[85]
  PIN mv[86]
    DIRECTION INPUT ;
    USE SIGNAL ;
    PORT
      LAYER M4 ;
        RECT  0 54.768 0.084 54.792 ;
    END
  END mv[86]
  PIN mv[87]
    DIRECTION INPUT ;
    USE SIGNAL ;
    PORT
      LAYER M4 ;
        RECT  0 54.864 0.084 54.888 ;
    END
  END mv[87]
  PIN mv[88]
    DIRECTION INPUT ;
    USE SIGNAL ;
    PORT
      LAYER M4 ;
        RECT  0 54.96 0.084 54.984 ;
    END
  END mv[88]
  PIN mv[89]
    DIRECTION INPUT ;
    USE SIGNAL ;
    PORT
      LAYER M4 ;
        RECT  0 55.056 0.084 55.08 ;
    END
  END mv[89]
  PIN mv[8]
    DIRECTION INPUT ;
    USE SIGNAL ;
    PORT
      LAYER M4 ;
        RECT  0 50.352 0.084 50.376 ;
    END
  END mv[8]
  PIN mv[90]
    DIRECTION INPUT ;
    USE SIGNAL ;
    PORT
      LAYER M4 ;
        RECT  0 55.152 0.084 55.176 ;
    END
  END mv[90]
  PIN mv[91]
    DIRECTION INPUT ;
    USE SIGNAL ;
    PORT
      LAYER M4 ;
        RECT  0 55.248 0.084 55.272 ;
    END
  END mv[91]
  PIN mv[92]
    DIRECTION INPUT ;
    USE SIGNAL ;
    PORT
      LAYER M4 ;
        RECT  0 55.344 0.084 55.368 ;
    END
  END mv[92]
  PIN mv[93]
    DIRECTION INPUT ;
    USE SIGNAL ;
    PORT
      LAYER M4 ;
        RECT  0 55.44 0.084 55.464 ;
    END
  END mv[93]
  PIN mv[94]
    DIRECTION INPUT ;
    USE SIGNAL ;
    PORT
      LAYER M4 ;
        RECT  0 55.536 0.084 55.56 ;
    END
  END mv[94]
  PIN mv[95]
    DIRECTION INPUT ;
    USE SIGNAL ;
    PORT
      LAYER M4 ;
        RECT  0 55.632 0.084 55.656 ;
    END
  END mv[95]
  PIN mv[96]
    DIRECTION INPUT ;
    USE SIGNAL ;
    PORT
      LAYER M4 ;
        RECT  0 40.368 0.084 40.392 ;
    END
  END mv[96]
  PIN mv[97]
    DIRECTION INPUT ;
    USE SIGNAL ;
    PORT
      LAYER M4 ;
        RECT  0 40.464 0.084 40.488 ;
    END
  END mv[97]
  PIN mv[98]
    DIRECTION INPUT ;
    USE SIGNAL ;
    PORT
      LAYER M4 ;
        RECT  0 40.56 0.084 40.584 ;
    END
  END mv[98]
  PIN mv[99]
    DIRECTION INPUT ;
    USE SIGNAL ;
    PORT
      LAYER M4 ;
        RECT  0 40.656 0.084 40.68 ;
    END
  END mv[99]
  PIN mv[9]
    DIRECTION INPUT ;
    USE SIGNAL ;
    PORT
      LAYER M4 ;
        RECT  0 50.448 0.084 50.472 ;
    END
  END mv[9]
  PIN mv_done
    DIRECTION OUTPUT ;
    USE SIGNAL ;
    PORT
      LAYER M5 ;
        RECT  42.48 75.516 42.504 75.6 ;
    END
  END mv_done
  PIN mv_fault
    DIRECTION OUTPUT ;
    USE SIGNAL ;
    PORT
      LAYER M5 ;
        RECT  42.576 75.516 42.6 75.6 ;
    END
  END mv_fault
  PIN mv_src
    DIRECTION OUTPUT ;
    USE SIGNAL ;
    PORT
      LAYER M5 ;
        RECT  42.672 75.516 42.696 75.6 ;
    END
  END mv_src
  PIN mv_v
    DIRECTION INPUT ;
    USE SIGNAL ;
    PORT
      LAYER M4 ;
        RECT  0 22.512 0.084 22.536 ;
    END
  END mv_v
  PIN mv_wb_bank
    DIRECTION INPUT ;
    USE SIGNAL ;
    PORT
      LAYER M4 ;
        RECT  0 22.608 0.084 22.632 ;
    END
  END mv_wb_bank
  PIN mv_wb_epoch[0]
    DIRECTION INPUT ;
    USE SIGNAL ;
    PORT
      LAYER M4 ;
        RECT  0 22.704 0.084 22.728 ;
    END
  END mv_wb_epoch[0]
  PIN mv_wb_epoch[10]
    DIRECTION INPUT ;
    USE SIGNAL ;
    PORT
      LAYER M4 ;
        RECT  0 23.664 0.084 23.688 ;
    END
  END mv_wb_epoch[10]
  PIN mv_wb_epoch[11]
    DIRECTION INPUT ;
    USE SIGNAL ;
    PORT
      LAYER M4 ;
        RECT  0 23.76 0.084 23.784 ;
    END
  END mv_wb_epoch[11]
  PIN mv_wb_epoch[12]
    DIRECTION INPUT ;
    USE SIGNAL ;
    PORT
      LAYER M4 ;
        RECT  0 23.856 0.084 23.88 ;
    END
  END mv_wb_epoch[12]
  PIN mv_wb_epoch[13]
    DIRECTION INPUT ;
    USE SIGNAL ;
    PORT
      LAYER M4 ;
        RECT  0 23.952 0.084 23.976 ;
    END
  END mv_wb_epoch[13]
  PIN mv_wb_epoch[14]
    DIRECTION INPUT ;
    USE SIGNAL ;
    PORT
      LAYER M4 ;
        RECT  0 24.048 0.084 24.072 ;
    END
  END mv_wb_epoch[14]
  PIN mv_wb_epoch[15]
    DIRECTION INPUT ;
    USE SIGNAL ;
    PORT
      LAYER M4 ;
        RECT  0 24.144 0.084 24.168 ;
    END
  END mv_wb_epoch[15]
  PIN mv_wb_epoch[1]
    DIRECTION INPUT ;
    USE SIGNAL ;
    PORT
      LAYER M4 ;
        RECT  0 22.8 0.084 22.824 ;
    END
  END mv_wb_epoch[1]
  PIN mv_wb_epoch[2]
    DIRECTION INPUT ;
    USE SIGNAL ;
    PORT
      LAYER M4 ;
        RECT  0 22.896 0.084 22.92 ;
    END
  END mv_wb_epoch[2]
  PIN mv_wb_epoch[3]
    DIRECTION INPUT ;
    USE SIGNAL ;
    PORT
      LAYER M4 ;
        RECT  0 22.992 0.084 23.016 ;
    END
  END mv_wb_epoch[3]
  PIN mv_wb_epoch[4]
    DIRECTION INPUT ;
    USE SIGNAL ;
    PORT
      LAYER M4 ;
        RECT  0 23.088 0.084 23.112 ;
    END
  END mv_wb_epoch[4]
  PIN mv_wb_epoch[5]
    DIRECTION INPUT ;
    USE SIGNAL ;
    PORT
      LAYER M4 ;
        RECT  0 23.184 0.084 23.208 ;
    END
  END mv_wb_epoch[5]
  PIN mv_wb_epoch[6]
    DIRECTION INPUT ;
    USE SIGNAL ;
    PORT
      LAYER M4 ;
        RECT  0 23.28 0.084 23.304 ;
    END
  END mv_wb_epoch[6]
  PIN mv_wb_epoch[7]
    DIRECTION INPUT ;
    USE SIGNAL ;
    PORT
      LAYER M4 ;
        RECT  0 23.376 0.084 23.4 ;
    END
  END mv_wb_epoch[7]
  PIN mv_wb_epoch[8]
    DIRECTION INPUT ;
    USE SIGNAL ;
    PORT
      LAYER M4 ;
        RECT  0 23.472 0.084 23.496 ;
    END
  END mv_wb_epoch[8]
  PIN mv_wb_epoch[9]
    DIRECTION INPUT ;
    USE SIGNAL ;
    PORT
      LAYER M4 ;
        RECT  0 23.568 0.084 23.592 ;
    END
  END mv_wb_epoch[9]
  PIN quiet
    DIRECTION OUTPUT ;
    USE SIGNAL ;
    PORT
      LAYER M5 ;
        RECT  42.768 75.516 42.792 75.6 ;
    END
  END quiet
  PIN rq[0]
    DIRECTION OUTPUT ;
    USE SIGNAL ;
    PORT
      LAYER M5 ;
        RECT  42.192 0 42.216 0.084 ;
    END
  END rq[0]
  PIN rq[100]
    DIRECTION OUTPUT ;
    USE SIGNAL ;
    PORT
      LAYER M5 ;
        RECT  39.504 0 39.528 0.084 ;
    END
  END rq[100]
  PIN rq[101]
    DIRECTION OUTPUT ;
    USE SIGNAL ;
    PORT
      LAYER M5 ;
        RECT  39.6 0 39.624 0.084 ;
    END
  END rq[101]
  PIN rq[102]
    DIRECTION OUTPUT ;
    USE SIGNAL ;
    PORT
      LAYER M5 ;
        RECT  39.696 0 39.72 0.084 ;
    END
  END rq[102]
  PIN rq[103]
    DIRECTION OUTPUT ;
    USE SIGNAL ;
    PORT
      LAYER M5 ;
        RECT  39.792 0 39.816 0.084 ;
    END
  END rq[103]
  PIN rq[104]
    DIRECTION OUTPUT ;
    USE SIGNAL ;
    PORT
      LAYER M5 ;
        RECT  39.888 0 39.912 0.084 ;
    END
  END rq[104]
  PIN rq[105]
    DIRECTION OUTPUT ;
    USE SIGNAL ;
    PORT
      LAYER M5 ;
        RECT  39.984 0 40.008 0.084 ;
    END
  END rq[105]
  PIN rq[106]
    DIRECTION OUTPUT ;
    USE SIGNAL ;
    PORT
      LAYER M5 ;
        RECT  40.08 0 40.104 0.084 ;
    END
  END rq[106]
  PIN rq[107]
    DIRECTION OUTPUT ;
    USE SIGNAL ;
    PORT
      LAYER M5 ;
        RECT  40.176 0 40.2 0.084 ;
    END
  END rq[107]
  PIN rq[108]
    DIRECTION OUTPUT ;
    USE SIGNAL ;
    PORT
      LAYER M5 ;
        RECT  40.272 0 40.296 0.084 ;
    END
  END rq[108]
  PIN rq[109]
    DIRECTION OUTPUT ;
    USE SIGNAL ;
    PORT
      LAYER M5 ;
        RECT  40.368 0 40.392 0.084 ;
    END
  END rq[109]
  PIN rq[10]
    DIRECTION OUTPUT ;
    USE SIGNAL ;
    PORT
      LAYER M5 ;
        RECT  43.152 0 43.176 0.084 ;
    END
  END rq[10]
  PIN rq[110]
    DIRECTION OUTPUT ;
    USE SIGNAL ;
    PORT
      LAYER M5 ;
        RECT  40.464 0 40.488 0.084 ;
    END
  END rq[110]
  PIN rq[111]
    DIRECTION OUTPUT ;
    USE SIGNAL ;
    PORT
      LAYER M5 ;
        RECT  40.56 0 40.584 0.084 ;
    END
  END rq[111]
  PIN rq[112]
    DIRECTION OUTPUT ;
    USE SIGNAL ;
    PORT
      LAYER M5 ;
        RECT  40.656 0 40.68 0.084 ;
    END
  END rq[112]
  PIN rq[113]
    DIRECTION OUTPUT ;
    USE SIGNAL ;
    PORT
      LAYER M5 ;
        RECT  40.752 0 40.776 0.084 ;
    END
  END rq[113]
  PIN rq[114]
    DIRECTION OUTPUT ;
    USE SIGNAL ;
    PORT
      LAYER M5 ;
        RECT  40.848 0 40.872 0.084 ;
    END
  END rq[114]
  PIN rq[115]
    DIRECTION OUTPUT ;
    USE SIGNAL ;
    PORT
      LAYER M5 ;
        RECT  40.944 0 40.968 0.084 ;
    END
  END rq[115]
  PIN rq[116]
    DIRECTION OUTPUT ;
    USE SIGNAL ;
    PORT
      LAYER M5 ;
        RECT  41.04 0 41.064 0.084 ;
    END
  END rq[116]
  PIN rq[117]
    DIRECTION OUTPUT ;
    USE SIGNAL ;
    PORT
      LAYER M5 ;
        RECT  41.136 0 41.16 0.084 ;
    END
  END rq[117]
  PIN rq[118]
    DIRECTION OUTPUT ;
    USE SIGNAL ;
    PORT
      LAYER M5 ;
        RECT  41.232 0 41.256 0.084 ;
    END
  END rq[118]
  PIN rq[119]
    DIRECTION OUTPUT ;
    USE SIGNAL ;
    PORT
      LAYER M5 ;
        RECT  41.328 0 41.352 0.084 ;
    END
  END rq[119]
  PIN rq[11]
    DIRECTION OUTPUT ;
    USE SIGNAL ;
    PORT
      LAYER M5 ;
        RECT  43.248 0 43.272 0.084 ;
    END
  END rq[11]
  PIN rq[120]
    DIRECTION OUTPUT ;
    USE SIGNAL ;
    PORT
      LAYER M5 ;
        RECT  41.424 0 41.448 0.084 ;
    END
  END rq[120]
  PIN rq[121]
    DIRECTION OUTPUT ;
    USE SIGNAL ;
    PORT
      LAYER M5 ;
        RECT  41.52 0 41.544 0.084 ;
    END
  END rq[121]
  PIN rq[122]
    DIRECTION OUTPUT ;
    USE SIGNAL ;
    PORT
      LAYER M5 ;
        RECT  41.616 0 41.64 0.084 ;
    END
  END rq[122]
  PIN rq[123]
    DIRECTION OUTPUT ;
    USE SIGNAL ;
    PORT
      LAYER M5 ;
        RECT  41.712 0 41.736 0.084 ;
    END
  END rq[123]
  PIN rq[124]
    DIRECTION OUTPUT ;
    USE SIGNAL ;
    PORT
      LAYER M5 ;
        RECT  41.808 0 41.832 0.084 ;
    END
  END rq[124]
  PIN rq[125]
    DIRECTION OUTPUT ;
    USE SIGNAL ;
    PORT
      LAYER M5 ;
        RECT  41.904 0 41.928 0.084 ;
    END
  END rq[125]
  PIN rq[126]
    DIRECTION OUTPUT ;
    USE SIGNAL ;
    PORT
      LAYER M5 ;
        RECT  42 0 42.024 0.084 ;
    END
  END rq[126]
  PIN rq[127]
    DIRECTION OUTPUT ;
    USE SIGNAL ;
    PORT
      LAYER M5 ;
        RECT  42.096 0 42.12 0.084 ;
    END
  END rq[127]
  PIN rq[128]
    DIRECTION OUTPUT ;
    USE SIGNAL ;
    PORT
      LAYER M5 ;
        RECT  67.536 0 67.56 0.084 ;
    END
  END rq[128]
  PIN rq[129]
    DIRECTION OUTPUT ;
    USE SIGNAL ;
    PORT
      LAYER M5 ;
        RECT  67.632 0 67.656 0.084 ;
    END
  END rq[129]
  PIN rq[12]
    DIRECTION OUTPUT ;
    USE SIGNAL ;
    PORT
      LAYER M5 ;
        RECT  43.344 0 43.368 0.084 ;
    END
  END rq[12]
  PIN rq[130]
    DIRECTION OUTPUT ;
    USE SIGNAL ;
    PORT
      LAYER M5 ;
        RECT  67.728 0 67.752 0.084 ;
    END
  END rq[130]
  PIN rq[131]
    DIRECTION OUTPUT ;
    USE SIGNAL ;
    PORT
      LAYER M5 ;
        RECT  67.824 0 67.848 0.084 ;
    END
  END rq[131]
  PIN rq[132]
    DIRECTION OUTPUT ;
    USE SIGNAL ;
    PORT
      LAYER M5 ;
        RECT  67.92 0 67.944 0.084 ;
    END
  END rq[132]
  PIN rq[133]
    DIRECTION OUTPUT ;
    USE SIGNAL ;
    PORT
      LAYER M5 ;
        RECT  68.016 0 68.04 0.084 ;
    END
  END rq[133]
  PIN rq[134]
    DIRECTION OUTPUT ;
    USE SIGNAL ;
    PORT
      LAYER M5 ;
        RECT  68.112 0 68.136 0.084 ;
    END
  END rq[134]
  PIN rq[135]
    DIRECTION OUTPUT ;
    USE SIGNAL ;
    PORT
      LAYER M5 ;
        RECT  68.208 0 68.232 0.084 ;
    END
  END rq[135]
  PIN rq[13]
    DIRECTION OUTPUT ;
    USE SIGNAL ;
    PORT
      LAYER M5 ;
        RECT  43.44 0 43.464 0.084 ;
    END
  END rq[13]
  PIN rq[14]
    DIRECTION OUTPUT ;
    USE SIGNAL ;
    PORT
      LAYER M5 ;
        RECT  43.536 0 43.56 0.084 ;
    END
  END rq[14]
  PIN rq[15]
    DIRECTION OUTPUT ;
    USE SIGNAL ;
    PORT
      LAYER M5 ;
        RECT  43.632 0 43.656 0.084 ;
    END
  END rq[15]
  PIN rq[16]
    DIRECTION OUTPUT ;
    USE SIGNAL ;
    PORT
      LAYER M5 ;
        RECT  43.728 0 43.752 0.084 ;
    END
  END rq[16]
  PIN rq[17]
    DIRECTION OUTPUT ;
    USE SIGNAL ;
    PORT
      LAYER M5 ;
        RECT  43.824 0 43.848 0.084 ;
    END
  END rq[17]
  PIN rq[18]
    DIRECTION OUTPUT ;
    USE SIGNAL ;
    PORT
      LAYER M5 ;
        RECT  43.92 0 43.944 0.084 ;
    END
  END rq[18]
  PIN rq[19]
    DIRECTION OUTPUT ;
    USE SIGNAL ;
    PORT
      LAYER M5 ;
        RECT  44.016 0 44.04 0.084 ;
    END
  END rq[19]
  PIN rq[1]
    DIRECTION OUTPUT ;
    USE SIGNAL ;
    PORT
      LAYER M5 ;
        RECT  42.288 0 42.312 0.084 ;
    END
  END rq[1]
  PIN rq[20]
    DIRECTION OUTPUT ;
    USE SIGNAL ;
    PORT
      LAYER M5 ;
        RECT  44.112 0 44.136 0.084 ;
    END
  END rq[20]
  PIN rq[21]
    DIRECTION OUTPUT ;
    USE SIGNAL ;
    PORT
      LAYER M5 ;
        RECT  44.208 0 44.232 0.084 ;
    END
  END rq[21]
  PIN rq[22]
    DIRECTION OUTPUT ;
    USE SIGNAL ;
    PORT
      LAYER M5 ;
        RECT  44.304 0 44.328 0.084 ;
    END
  END rq[22]
  PIN rq[23]
    DIRECTION OUTPUT ;
    USE SIGNAL ;
    PORT
      LAYER M5 ;
        RECT  44.4 0 44.424 0.084 ;
    END
  END rq[23]
  PIN rq[24]
    DIRECTION OUTPUT ;
    USE SIGNAL ;
    PORT
      LAYER M5 ;
        RECT  44.496 0 44.52 0.084 ;
    END
  END rq[24]
  PIN rq[25]
    DIRECTION OUTPUT ;
    USE SIGNAL ;
    PORT
      LAYER M5 ;
        RECT  44.592 0 44.616 0.084 ;
    END
  END rq[25]
  PIN rq[26]
    DIRECTION OUTPUT ;
    USE SIGNAL ;
    PORT
      LAYER M5 ;
        RECT  44.688 0 44.712 0.084 ;
    END
  END rq[26]
  PIN rq[27]
    DIRECTION OUTPUT ;
    USE SIGNAL ;
    PORT
      LAYER M5 ;
        RECT  44.784 0 44.808 0.084 ;
    END
  END rq[27]
  PIN rq[28]
    DIRECTION OUTPUT ;
    USE SIGNAL ;
    PORT
      LAYER M5 ;
        RECT  44.88 0 44.904 0.084 ;
    END
  END rq[28]
  PIN rq[29]
    DIRECTION OUTPUT ;
    USE SIGNAL ;
    PORT
      LAYER M5 ;
        RECT  44.976 0 45 0.084 ;
    END
  END rq[29]
  PIN rq[2]
    DIRECTION OUTPUT ;
    USE SIGNAL ;
    PORT
      LAYER M5 ;
        RECT  42.384 0 42.408 0.084 ;
    END
  END rq[2]
  PIN rq[30]
    DIRECTION OUTPUT ;
    USE SIGNAL ;
    PORT
      LAYER M5 ;
        RECT  45.072 0 45.096 0.084 ;
    END
  END rq[30]
  PIN rq[31]
    DIRECTION OUTPUT ;
    USE SIGNAL ;
    PORT
      LAYER M5 ;
        RECT  45.168 0 45.192 0.084 ;
    END
  END rq[31]
  PIN rq[32]
    DIRECTION OUTPUT ;
    USE SIGNAL ;
    PORT
      LAYER M5 ;
        RECT  48.336 0 48.36 0.084 ;
    END
  END rq[32]
  PIN rq[33]
    DIRECTION OUTPUT ;
    USE SIGNAL ;
    PORT
      LAYER M5 ;
        RECT  48.432 0 48.456 0.084 ;
    END
  END rq[33]
  PIN rq[34]
    DIRECTION OUTPUT ;
    USE SIGNAL ;
    PORT
      LAYER M5 ;
        RECT  48.528 0 48.552 0.084 ;
    END
  END rq[34]
  PIN rq[35]
    DIRECTION OUTPUT ;
    USE SIGNAL ;
    PORT
      LAYER M5 ;
        RECT  48.624 0 48.648 0.084 ;
    END
  END rq[35]
  PIN rq[36]
    DIRECTION OUTPUT ;
    USE SIGNAL ;
    PORT
      LAYER M5 ;
        RECT  48.72 0 48.744 0.084 ;
    END
  END rq[36]
  PIN rq[37]
    DIRECTION OUTPUT ;
    USE SIGNAL ;
    PORT
      LAYER M5 ;
        RECT  48.816 0 48.84 0.084 ;
    END
  END rq[37]
  PIN rq[38]
    DIRECTION OUTPUT ;
    USE SIGNAL ;
    PORT
      LAYER M5 ;
        RECT  48.912 0 48.936 0.084 ;
    END
  END rq[38]
  PIN rq[39]
    DIRECTION OUTPUT ;
    USE SIGNAL ;
    PORT
      LAYER M5 ;
        RECT  49.008 0 49.032 0.084 ;
    END
  END rq[39]
  PIN rq[3]
    DIRECTION OUTPUT ;
    USE SIGNAL ;
    PORT
      LAYER M5 ;
        RECT  42.48 0 42.504 0.084 ;
    END
  END rq[3]
  PIN rq[40]
    DIRECTION OUTPUT ;
    USE SIGNAL ;
    PORT
      LAYER M5 ;
        RECT  49.104 0 49.128 0.084 ;
    END
  END rq[40]
  PIN rq[41]
    DIRECTION OUTPUT ;
    USE SIGNAL ;
    PORT
      LAYER M5 ;
        RECT  49.2 0 49.224 0.084 ;
    END
  END rq[41]
  PIN rq[42]
    DIRECTION OUTPUT ;
    USE SIGNAL ;
    PORT
      LAYER M5 ;
        RECT  49.296 0 49.32 0.084 ;
    END
  END rq[42]
  PIN rq[43]
    DIRECTION OUTPUT ;
    USE SIGNAL ;
    PORT
      LAYER M5 ;
        RECT  49.392 0 49.416 0.084 ;
    END
  END rq[43]
  PIN rq[44]
    DIRECTION OUTPUT ;
    USE SIGNAL ;
    PORT
      LAYER M5 ;
        RECT  49.488 0 49.512 0.084 ;
    END
  END rq[44]
  PIN rq[45]
    DIRECTION OUTPUT ;
    USE SIGNAL ;
    PORT
      LAYER M5 ;
        RECT  49.584 0 49.608 0.084 ;
    END
  END rq[45]
  PIN rq[46]
    DIRECTION OUTPUT ;
    USE SIGNAL ;
    PORT
      LAYER M5 ;
        RECT  49.68 0 49.704 0.084 ;
    END
  END rq[46]
  PIN rq[47]
    DIRECTION OUTPUT ;
    USE SIGNAL ;
    PORT
      LAYER M5 ;
        RECT  49.776 0 49.8 0.084 ;
    END
  END rq[47]
  PIN rq[48]
    DIRECTION OUTPUT ;
    USE SIGNAL ;
    PORT
      LAYER M5 ;
        RECT  49.872 0 49.896 0.084 ;
    END
  END rq[48]
  PIN rq[49]
    DIRECTION OUTPUT ;
    USE SIGNAL ;
    PORT
      LAYER M5 ;
        RECT  49.968 0 49.992 0.084 ;
    END
  END rq[49]
  PIN rq[4]
    DIRECTION OUTPUT ;
    USE SIGNAL ;
    PORT
      LAYER M5 ;
        RECT  42.576 0 42.6 0.084 ;
    END
  END rq[4]
  PIN rq[50]
    DIRECTION OUTPUT ;
    USE SIGNAL ;
    PORT
      LAYER M5 ;
        RECT  50.064 0 50.088 0.084 ;
    END
  END rq[50]
  PIN rq[51]
    DIRECTION OUTPUT ;
    USE SIGNAL ;
    PORT
      LAYER M5 ;
        RECT  50.16 0 50.184 0.084 ;
    END
  END rq[51]
  PIN rq[52]
    DIRECTION OUTPUT ;
    USE SIGNAL ;
    PORT
      LAYER M5 ;
        RECT  50.256 0 50.28 0.084 ;
    END
  END rq[52]
  PIN rq[53]
    DIRECTION OUTPUT ;
    USE SIGNAL ;
    PORT
      LAYER M5 ;
        RECT  50.352 0 50.376 0.084 ;
    END
  END rq[53]
  PIN rq[54]
    DIRECTION OUTPUT ;
    USE SIGNAL ;
    PORT
      LAYER M5 ;
        RECT  50.448 0 50.472 0.084 ;
    END
  END rq[54]
  PIN rq[55]
    DIRECTION OUTPUT ;
    USE SIGNAL ;
    PORT
      LAYER M5 ;
        RECT  50.544 0 50.568 0.084 ;
    END
  END rq[55]
  PIN rq[56]
    DIRECTION OUTPUT ;
    USE SIGNAL ;
    PORT
      LAYER M5 ;
        RECT  50.64 0 50.664 0.084 ;
    END
  END rq[56]
  PIN rq[57]
    DIRECTION OUTPUT ;
    USE SIGNAL ;
    PORT
      LAYER M5 ;
        RECT  50.736 0 50.76 0.084 ;
    END
  END rq[57]
  PIN rq[58]
    DIRECTION OUTPUT ;
    USE SIGNAL ;
    PORT
      LAYER M5 ;
        RECT  50.832 0 50.856 0.084 ;
    END
  END rq[58]
  PIN rq[59]
    DIRECTION OUTPUT ;
    USE SIGNAL ;
    PORT
      LAYER M5 ;
        RECT  50.928 0 50.952 0.084 ;
    END
  END rq[59]
  PIN rq[5]
    DIRECTION OUTPUT ;
    USE SIGNAL ;
    PORT
      LAYER M5 ;
        RECT  42.672 0 42.696 0.084 ;
    END
  END rq[5]
  PIN rq[60]
    DIRECTION OUTPUT ;
    USE SIGNAL ;
    PORT
      LAYER M5 ;
        RECT  51.024 0 51.048 0.084 ;
    END
  END rq[60]
  PIN rq[61]
    DIRECTION OUTPUT ;
    USE SIGNAL ;
    PORT
      LAYER M5 ;
        RECT  51.12 0 51.144 0.084 ;
    END
  END rq[61]
  PIN rq[62]
    DIRECTION OUTPUT ;
    USE SIGNAL ;
    PORT
      LAYER M5 ;
        RECT  51.216 0 51.24 0.084 ;
    END
  END rq[62]
  PIN rq[63]
    DIRECTION OUTPUT ;
    USE SIGNAL ;
    PORT
      LAYER M5 ;
        RECT  51.312 0 51.336 0.084 ;
    END
  END rq[63]
  PIN rq[64]
    DIRECTION OUTPUT ;
    USE SIGNAL ;
    PORT
      LAYER M5 ;
        RECT  45.264 0 45.288 0.084 ;
    END
  END rq[64]
  PIN rq[65]
    DIRECTION OUTPUT ;
    USE SIGNAL ;
    PORT
      LAYER M5 ;
        RECT  45.36 0 45.384 0.084 ;
    END
  END rq[65]
  PIN rq[66]
    DIRECTION OUTPUT ;
    USE SIGNAL ;
    PORT
      LAYER M5 ;
        RECT  45.456 0 45.48 0.084 ;
    END
  END rq[66]
  PIN rq[67]
    DIRECTION OUTPUT ;
    USE SIGNAL ;
    PORT
      LAYER M5 ;
        RECT  45.552 0 45.576 0.084 ;
    END
  END rq[67]
  PIN rq[68]
    DIRECTION OUTPUT ;
    USE SIGNAL ;
    PORT
      LAYER M5 ;
        RECT  45.648 0 45.672 0.084 ;
    END
  END rq[68]
  PIN rq[69]
    DIRECTION OUTPUT ;
    USE SIGNAL ;
    PORT
      LAYER M5 ;
        RECT  45.744 0 45.768 0.084 ;
    END
  END rq[69]
  PIN rq[6]
    DIRECTION OUTPUT ;
    USE SIGNAL ;
    PORT
      LAYER M5 ;
        RECT  42.768 0 42.792 0.084 ;
    END
  END rq[6]
  PIN rq[70]
    DIRECTION OUTPUT ;
    USE SIGNAL ;
    PORT
      LAYER M5 ;
        RECT  45.84 0 45.864 0.084 ;
    END
  END rq[70]
  PIN rq[71]
    DIRECTION OUTPUT ;
    USE SIGNAL ;
    PORT
      LAYER M5 ;
        RECT  45.936 0 45.96 0.084 ;
    END
  END rq[71]
  PIN rq[72]
    DIRECTION OUTPUT ;
    USE SIGNAL ;
    PORT
      LAYER M5 ;
        RECT  46.032 0 46.056 0.084 ;
    END
  END rq[72]
  PIN rq[73]
    DIRECTION OUTPUT ;
    USE SIGNAL ;
    PORT
      LAYER M5 ;
        RECT  46.128 0 46.152 0.084 ;
    END
  END rq[73]
  PIN rq[74]
    DIRECTION OUTPUT ;
    USE SIGNAL ;
    PORT
      LAYER M5 ;
        RECT  46.224 0 46.248 0.084 ;
    END
  END rq[74]
  PIN rq[75]
    DIRECTION OUTPUT ;
    USE SIGNAL ;
    PORT
      LAYER M5 ;
        RECT  46.32 0 46.344 0.084 ;
    END
  END rq[75]
  PIN rq[76]
    DIRECTION OUTPUT ;
    USE SIGNAL ;
    PORT
      LAYER M5 ;
        RECT  46.416 0 46.44 0.084 ;
    END
  END rq[76]
  PIN rq[77]
    DIRECTION OUTPUT ;
    USE SIGNAL ;
    PORT
      LAYER M5 ;
        RECT  46.512 0 46.536 0.084 ;
    END
  END rq[77]
  PIN rq[78]
    DIRECTION OUTPUT ;
    USE SIGNAL ;
    PORT
      LAYER M5 ;
        RECT  46.608 0 46.632 0.084 ;
    END
  END rq[78]
  PIN rq[79]
    DIRECTION OUTPUT ;
    USE SIGNAL ;
    PORT
      LAYER M5 ;
        RECT  46.704 0 46.728 0.084 ;
    END
  END rq[79]
  PIN rq[7]
    DIRECTION OUTPUT ;
    USE SIGNAL ;
    PORT
      LAYER M5 ;
        RECT  42.864 0 42.888 0.084 ;
    END
  END rq[7]
  PIN rq[80]
    DIRECTION OUTPUT ;
    USE SIGNAL ;
    PORT
      LAYER M5 ;
        RECT  46.8 0 46.824 0.084 ;
    END
  END rq[80]
  PIN rq[81]
    DIRECTION OUTPUT ;
    USE SIGNAL ;
    PORT
      LAYER M5 ;
        RECT  46.896 0 46.92 0.084 ;
    END
  END rq[81]
  PIN rq[82]
    DIRECTION OUTPUT ;
    USE SIGNAL ;
    PORT
      LAYER M5 ;
        RECT  46.992 0 47.016 0.084 ;
    END
  END rq[82]
  PIN rq[83]
    DIRECTION OUTPUT ;
    USE SIGNAL ;
    PORT
      LAYER M5 ;
        RECT  47.088 0 47.112 0.084 ;
    END
  END rq[83]
  PIN rq[84]
    DIRECTION OUTPUT ;
    USE SIGNAL ;
    PORT
      LAYER M5 ;
        RECT  47.184 0 47.208 0.084 ;
    END
  END rq[84]
  PIN rq[85]
    DIRECTION OUTPUT ;
    USE SIGNAL ;
    PORT
      LAYER M5 ;
        RECT  47.28 0 47.304 0.084 ;
    END
  END rq[85]
  PIN rq[86]
    DIRECTION OUTPUT ;
    USE SIGNAL ;
    PORT
      LAYER M5 ;
        RECT  47.376 0 47.4 0.084 ;
    END
  END rq[86]
  PIN rq[87]
    DIRECTION OUTPUT ;
    USE SIGNAL ;
    PORT
      LAYER M5 ;
        RECT  47.472 0 47.496 0.084 ;
    END
  END rq[87]
  PIN rq[88]
    DIRECTION OUTPUT ;
    USE SIGNAL ;
    PORT
      LAYER M5 ;
        RECT  47.568 0 47.592 0.084 ;
    END
  END rq[88]
  PIN rq[89]
    DIRECTION OUTPUT ;
    USE SIGNAL ;
    PORT
      LAYER M5 ;
        RECT  47.664 0 47.688 0.084 ;
    END
  END rq[89]
  PIN rq[8]
    DIRECTION OUTPUT ;
    USE SIGNAL ;
    PORT
      LAYER M5 ;
        RECT  42.96 0 42.984 0.084 ;
    END
  END rq[8]
  PIN rq[90]
    DIRECTION OUTPUT ;
    USE SIGNAL ;
    PORT
      LAYER M5 ;
        RECT  47.76 0 47.784 0.084 ;
    END
  END rq[90]
  PIN rq[91]
    DIRECTION OUTPUT ;
    USE SIGNAL ;
    PORT
      LAYER M5 ;
        RECT  47.856 0 47.88 0.084 ;
    END
  END rq[91]
  PIN rq[92]
    DIRECTION OUTPUT ;
    USE SIGNAL ;
    PORT
      LAYER M5 ;
        RECT  47.952 0 47.976 0.084 ;
    END
  END rq[92]
  PIN rq[93]
    DIRECTION OUTPUT ;
    USE SIGNAL ;
    PORT
      LAYER M5 ;
        RECT  48.048 0 48.072 0.084 ;
    END
  END rq[93]
  PIN rq[94]
    DIRECTION OUTPUT ;
    USE SIGNAL ;
    PORT
      LAYER M5 ;
        RECT  48.144 0 48.168 0.084 ;
    END
  END rq[94]
  PIN rq[95]
    DIRECTION OUTPUT ;
    USE SIGNAL ;
    PORT
      LAYER M5 ;
        RECT  48.24 0 48.264 0.084 ;
    END
  END rq[95]
  PIN rq[96]
    DIRECTION OUTPUT ;
    USE SIGNAL ;
    PORT
      LAYER M5 ;
        RECT  39.12 0 39.144 0.084 ;
    END
  END rq[96]
  PIN rq[97]
    DIRECTION OUTPUT ;
    USE SIGNAL ;
    PORT
      LAYER M5 ;
        RECT  39.216 0 39.24 0.084 ;
    END
  END rq[97]
  PIN rq[98]
    DIRECTION OUTPUT ;
    USE SIGNAL ;
    PORT
      LAYER M5 ;
        RECT  39.312 0 39.336 0.084 ;
    END
  END rq[98]
  PIN rq[99]
    DIRECTION OUTPUT ;
    USE SIGNAL ;
    PORT
      LAYER M5 ;
        RECT  39.408 0 39.432 0.084 ;
    END
  END rq[99]
  PIN rq[9]
    DIRECTION OUTPUT ;
    USE SIGNAL ;
    PORT
      LAYER M5 ;
        RECT  43.056 0 43.08 0.084 ;
    END
  END rq[9]
  PIN rr_valid_i[0]
    DIRECTION INPUT ;
    USE SIGNAL ;
    PORT
      LAYER M4 ;
        RECT  75.516 62.928 75.6 62.952 ;
    END
  END rr_valid_i[0]
  PIN rr_valid_i[1]
    DIRECTION INPUT ;
    USE SIGNAL ;
    PORT
      LAYER M4 ;
        RECT  75.516 63.024 75.6 63.048 ;
    END
  END rr_valid_i[1]
  PIN rr_valid_i[2]
    DIRECTION INPUT ;
    USE SIGNAL ;
    PORT
      LAYER M4 ;
        RECT  75.516 63.12 75.6 63.144 ;
    END
  END rr_valid_i[2]
  PIN rr_valid_i[3]
    DIRECTION INPUT ;
    USE SIGNAL ;
    PORT
      LAYER M4 ;
        RECT  75.516 63.216 75.6 63.24 ;
    END
  END rr_valid_i[3]
  PIN rr_valid_i[4]
    DIRECTION INPUT ;
    USE SIGNAL ;
    PORT
      LAYER M4 ;
        RECT  75.516 63.312 75.6 63.336 ;
    END
  END rr_valid_i[4]
  PIN rr_valid_i[5]
    DIRECTION INPUT ;
    USE SIGNAL ;
    PORT
      LAYER M4 ;
        RECT  75.516 63.408 75.6 63.432 ;
    END
  END rr_valid_i[5]
  PIN rr_valid_i[6]
    DIRECTION INPUT ;
    USE SIGNAL ;
    PORT
      LAYER M4 ;
        RECT  75.516 63.504 75.6 63.528 ;
    END
  END rr_valid_i[6]
  PIN rr_valid_i[7]
    DIRECTION INPUT ;
    USE SIGNAL ;
    PORT
      LAYER M4 ;
        RECT  75.516 63.6 75.6 63.624 ;
    END
  END rr_valid_i[7]
  PIN rst_n
    DIRECTION INPUT ;
    USE SIGNAL ;
    PORT
      LAYER M5 ;
        RECT  42.864 75.516 42.888 75.6 ;
    END
  END rst_n
  PIN wa[0]
    DIRECTION INPUT ;
    USE SIGNAL ;
    PORT
      LAYER M5 ;
        RECT  42.96 75.516 42.984 75.6 ;
    END
  END wa[0]
  PIN wa[10]
    DIRECTION INPUT ;
    USE SIGNAL ;
    PORT
      LAYER M5 ;
        RECT  43.92 75.516 43.944 75.6 ;
    END
  END wa[10]
  PIN wa[11]
    DIRECTION INPUT ;
    USE SIGNAL ;
    PORT
      LAYER M5 ;
        RECT  44.016 75.516 44.04 75.6 ;
    END
  END wa[11]
  PIN wa[1]
    DIRECTION INPUT ;
    USE SIGNAL ;
    PORT
      LAYER M5 ;
        RECT  43.056 75.516 43.08 75.6 ;
    END
  END wa[1]
  PIN wa[2]
    DIRECTION INPUT ;
    USE SIGNAL ;
    PORT
      LAYER M5 ;
        RECT  43.152 75.516 43.176 75.6 ;
    END
  END wa[2]
  PIN wa[3]
    DIRECTION INPUT ;
    USE SIGNAL ;
    PORT
      LAYER M5 ;
        RECT  43.248 75.516 43.272 75.6 ;
    END
  END wa[3]
  PIN wa[4]
    DIRECTION INPUT ;
    USE SIGNAL ;
    PORT
      LAYER M5 ;
        RECT  43.344 75.516 43.368 75.6 ;
    END
  END wa[4]
  PIN wa[5]
    DIRECTION INPUT ;
    USE SIGNAL ;
    PORT
      LAYER M5 ;
        RECT  43.44 75.516 43.464 75.6 ;
    END
  END wa[5]
  PIN wa[6]
    DIRECTION INPUT ;
    USE SIGNAL ;
    PORT
      LAYER M5 ;
        RECT  43.536 75.516 43.56 75.6 ;
    END
  END wa[6]
  PIN wa[7]
    DIRECTION INPUT ;
    USE SIGNAL ;
    PORT
      LAYER M5 ;
        RECT  43.632 75.516 43.656 75.6 ;
    END
  END wa[7]
  PIN wa[8]
    DIRECTION INPUT ;
    USE SIGNAL ;
    PORT
      LAYER M5 ;
        RECT  43.728 75.516 43.752 75.6 ;
    END
  END wa[8]
  PIN wa[9]
    DIRECTION INPUT ;
    USE SIGNAL ;
    PORT
      LAYER M5 ;
        RECT  43.824 75.516 43.848 75.6 ;
    END
  END wa[9]
  PIN wb_fill_bank
    DIRECTION OUTPUT ;
    USE SIGNAL ;
    PORT
      LAYER M5 ;
        RECT  68.304 0 68.328 0.084 ;
    END
  END wb_fill_bank
  PIN wb_fill_epoch[0]
    DIRECTION OUTPUT ;
    USE SIGNAL ;
    PORT
      LAYER M5 ;
        RECT  68.4 0 68.424 0.084 ;
    END
  END wb_fill_epoch[0]
  PIN wb_fill_epoch[10]
    DIRECTION OUTPUT ;
    USE SIGNAL ;
    PORT
      LAYER M5 ;
        RECT  69.36 0 69.384 0.084 ;
    END
  END wb_fill_epoch[10]
  PIN wb_fill_epoch[11]
    DIRECTION OUTPUT ;
    USE SIGNAL ;
    PORT
      LAYER M5 ;
        RECT  69.456 0 69.48 0.084 ;
    END
  END wb_fill_epoch[11]
  PIN wb_fill_epoch[12]
    DIRECTION OUTPUT ;
    USE SIGNAL ;
    PORT
      LAYER M5 ;
        RECT  69.552 0 69.576 0.084 ;
    END
  END wb_fill_epoch[12]
  PIN wb_fill_epoch[13]
    DIRECTION OUTPUT ;
    USE SIGNAL ;
    PORT
      LAYER M5 ;
        RECT  69.648 0 69.672 0.084 ;
    END
  END wb_fill_epoch[13]
  PIN wb_fill_epoch[14]
    DIRECTION OUTPUT ;
    USE SIGNAL ;
    PORT
      LAYER M5 ;
        RECT  69.744 0 69.768 0.084 ;
    END
  END wb_fill_epoch[14]
  PIN wb_fill_epoch[15]
    DIRECTION OUTPUT ;
    USE SIGNAL ;
    PORT
      LAYER M5 ;
        RECT  69.84 0 69.864 0.084 ;
    END
  END wb_fill_epoch[15]
  PIN wb_fill_epoch[1]
    DIRECTION OUTPUT ;
    USE SIGNAL ;
    PORT
      LAYER M5 ;
        RECT  68.496 0 68.52 0.084 ;
    END
  END wb_fill_epoch[1]
  PIN wb_fill_epoch[2]
    DIRECTION OUTPUT ;
    USE SIGNAL ;
    PORT
      LAYER M5 ;
        RECT  68.592 0 68.616 0.084 ;
    END
  END wb_fill_epoch[2]
  PIN wb_fill_epoch[3]
    DIRECTION OUTPUT ;
    USE SIGNAL ;
    PORT
      LAYER M5 ;
        RECT  68.688 0 68.712 0.084 ;
    END
  END wb_fill_epoch[3]
  PIN wb_fill_epoch[4]
    DIRECTION OUTPUT ;
    USE SIGNAL ;
    PORT
      LAYER M5 ;
        RECT  68.784 0 68.808 0.084 ;
    END
  END wb_fill_epoch[4]
  PIN wb_fill_epoch[5]
    DIRECTION OUTPUT ;
    USE SIGNAL ;
    PORT
      LAYER M5 ;
        RECT  68.88 0 68.904 0.084 ;
    END
  END wb_fill_epoch[5]
  PIN wb_fill_epoch[6]
    DIRECTION OUTPUT ;
    USE SIGNAL ;
    PORT
      LAYER M5 ;
        RECT  68.976 0 69 0.084 ;
    END
  END wb_fill_epoch[6]
  PIN wb_fill_epoch[7]
    DIRECTION OUTPUT ;
    USE SIGNAL ;
    PORT
      LAYER M5 ;
        RECT  69.072 0 69.096 0.084 ;
    END
  END wb_fill_epoch[7]
  PIN wb_fill_epoch[8]
    DIRECTION OUTPUT ;
    USE SIGNAL ;
    PORT
      LAYER M5 ;
        RECT  69.168 0 69.192 0.084 ;
    END
  END wb_fill_epoch[8]
  PIN wb_fill_epoch[9]
    DIRECTION OUTPUT ;
    USE SIGNAL ;
    PORT
      LAYER M5 ;
        RECT  69.264 0 69.288 0.084 ;
    END
  END wb_fill_epoch[9]
  PIN wb_fill_start
    DIRECTION OUTPUT ;
    USE SIGNAL ;
    PORT
      LAYER M5 ;
        RECT  69.936 0 69.96 0.084 ;
    END
  END wb_fill_start
  PIN wb_ready
    DIRECTION INPUT ;
    USE SIGNAL ;
    PORT
      LAYER M5 ;
        RECT  44.112 75.516 44.136 75.6 ;
    END
  END wb_ready
  PIN wb_reserve_bank
    DIRECTION OUTPUT ;
    USE SIGNAL ;
    PORT
      LAYER M5 ;
        RECT  70.032 0 70.056 0.084 ;
    END
  END wb_reserve_bank
  PIN wb_reserve_base[0]
    DIRECTION OUTPUT ;
    USE SIGNAL ;
    PORT
      LAYER M5 ;
        RECT  70.128 0 70.152 0.084 ;
    END
  END wb_reserve_base[0]
  PIN wb_reserve_base[10]
    DIRECTION OUTPUT ;
    USE SIGNAL ;
    PORT
      LAYER M5 ;
        RECT  51.888 0 51.912 0.084 ;
    END
  END wb_reserve_base[10]
  PIN wb_reserve_base[11]
    DIRECTION OUTPUT ;
    USE SIGNAL ;
    PORT
      LAYER M5 ;
        RECT  51.984 0 52.008 0.084 ;
    END
  END wb_reserve_base[11]
  PIN wb_reserve_base[12]
    DIRECTION OUTPUT ;
    USE SIGNAL ;
    PORT
      LAYER M5 ;
        RECT  52.08 0 52.104 0.084 ;
    END
  END wb_reserve_base[12]
  PIN wb_reserve_base[13]
    DIRECTION OUTPUT ;
    USE SIGNAL ;
    PORT
      LAYER M5 ;
        RECT  52.176 0 52.2 0.084 ;
    END
  END wb_reserve_base[13]
  PIN wb_reserve_base[14]
    DIRECTION OUTPUT ;
    USE SIGNAL ;
    PORT
      LAYER M5 ;
        RECT  52.272 0 52.296 0.084 ;
    END
  END wb_reserve_base[14]
  PIN wb_reserve_base[15]
    DIRECTION OUTPUT ;
    USE SIGNAL ;
    PORT
      LAYER M5 ;
        RECT  52.368 0 52.392 0.084 ;
    END
  END wb_reserve_base[15]
  PIN wb_reserve_base[16]
    DIRECTION OUTPUT ;
    USE SIGNAL ;
    PORT
      LAYER M5 ;
        RECT  52.464 0 52.488 0.084 ;
    END
  END wb_reserve_base[16]
  PIN wb_reserve_base[17]
    DIRECTION OUTPUT ;
    USE SIGNAL ;
    PORT
      LAYER M5 ;
        RECT  52.56 0 52.584 0.084 ;
    END
  END wb_reserve_base[17]
  PIN wb_reserve_base[18]
    DIRECTION OUTPUT ;
    USE SIGNAL ;
    PORT
      LAYER M5 ;
        RECT  52.656 0 52.68 0.084 ;
    END
  END wb_reserve_base[18]
  PIN wb_reserve_base[19]
    DIRECTION OUTPUT ;
    USE SIGNAL ;
    PORT
      LAYER M5 ;
        RECT  52.752 0 52.776 0.084 ;
    END
  END wb_reserve_base[19]
  PIN wb_reserve_base[1]
    DIRECTION OUTPUT ;
    USE SIGNAL ;
    PORT
      LAYER M5 ;
        RECT  70.224 0 70.248 0.084 ;
    END
  END wb_reserve_base[1]
  PIN wb_reserve_base[20]
    DIRECTION OUTPUT ;
    USE SIGNAL ;
    PORT
      LAYER M5 ;
        RECT  52.848 0 52.872 0.084 ;
    END
  END wb_reserve_base[20]
  PIN wb_reserve_base[21]
    DIRECTION OUTPUT ;
    USE SIGNAL ;
    PORT
      LAYER M5 ;
        RECT  52.944 0 52.968 0.084 ;
    END
  END wb_reserve_base[21]
  PIN wb_reserve_base[22]
    DIRECTION OUTPUT ;
    USE SIGNAL ;
    PORT
      LAYER M5 ;
        RECT  53.04 0 53.064 0.084 ;
    END
  END wb_reserve_base[22]
  PIN wb_reserve_base[23]
    DIRECTION OUTPUT ;
    USE SIGNAL ;
    PORT
      LAYER M5 ;
        RECT  53.136 0 53.16 0.084 ;
    END
  END wb_reserve_base[23]
  PIN wb_reserve_base[24]
    DIRECTION OUTPUT ;
    USE SIGNAL ;
    PORT
      LAYER M5 ;
        RECT  53.232 0 53.256 0.084 ;
    END
  END wb_reserve_base[24]
  PIN wb_reserve_base[25]
    DIRECTION OUTPUT ;
    USE SIGNAL ;
    PORT
      LAYER M5 ;
        RECT  53.328 0 53.352 0.084 ;
    END
  END wb_reserve_base[25]
  PIN wb_reserve_base[26]
    DIRECTION OUTPUT ;
    USE SIGNAL ;
    PORT
      LAYER M5 ;
        RECT  53.424 0 53.448 0.084 ;
    END
  END wb_reserve_base[26]
  PIN wb_reserve_base[27]
    DIRECTION OUTPUT ;
    USE SIGNAL ;
    PORT
      LAYER M5 ;
        RECT  53.52 0 53.544 0.084 ;
    END
  END wb_reserve_base[27]
  PIN wb_reserve_base[28]
    DIRECTION OUTPUT ;
    USE SIGNAL ;
    PORT
      LAYER M5 ;
        RECT  53.616 0 53.64 0.084 ;
    END
  END wb_reserve_base[28]
  PIN wb_reserve_base[29]
    DIRECTION OUTPUT ;
    USE SIGNAL ;
    PORT
      LAYER M5 ;
        RECT  53.712 0 53.736 0.084 ;
    END
  END wb_reserve_base[29]
  PIN wb_reserve_base[2]
    DIRECTION OUTPUT ;
    USE SIGNAL ;
    PORT
      LAYER M5 ;
        RECT  70.32 0 70.344 0.084 ;
    END
  END wb_reserve_base[2]
  PIN wb_reserve_base[30]
    DIRECTION OUTPUT ;
    USE SIGNAL ;
    PORT
      LAYER M5 ;
        RECT  53.808 0 53.832 0.084 ;
    END
  END wb_reserve_base[30]
  PIN wb_reserve_base[31]
    DIRECTION OUTPUT ;
    USE SIGNAL ;
    PORT
      LAYER M5 ;
        RECT  53.904 0 53.928 0.084 ;
    END
  END wb_reserve_base[31]
  PIN wb_reserve_base[3]
    DIRECTION OUTPUT ;
    USE SIGNAL ;
    PORT
      LAYER M5 ;
        RECT  70.416 0 70.44 0.084 ;
    END
  END wb_reserve_base[3]
  PIN wb_reserve_base[4]
    DIRECTION OUTPUT ;
    USE SIGNAL ;
    PORT
      LAYER M5 ;
        RECT  70.512 0 70.536 0.084 ;
    END
  END wb_reserve_base[4]
  PIN wb_reserve_base[5]
    DIRECTION OUTPUT ;
    USE SIGNAL ;
    PORT
      LAYER M5 ;
        RECT  51.408 0 51.432 0.084 ;
    END
  END wb_reserve_base[5]
  PIN wb_reserve_base[6]
    DIRECTION OUTPUT ;
    USE SIGNAL ;
    PORT
      LAYER M5 ;
        RECT  51.504 0 51.528 0.084 ;
    END
  END wb_reserve_base[6]
  PIN wb_reserve_base[7]
    DIRECTION OUTPUT ;
    USE SIGNAL ;
    PORT
      LAYER M5 ;
        RECT  51.6 0 51.624 0.084 ;
    END
  END wb_reserve_base[7]
  PIN wb_reserve_base[8]
    DIRECTION OUTPUT ;
    USE SIGNAL ;
    PORT
      LAYER M5 ;
        RECT  51.696 0 51.72 0.084 ;
    END
  END wb_reserve_base[8]
  PIN wb_reserve_base[9]
    DIRECTION OUTPUT ;
    USE SIGNAL ;
    PORT
      LAYER M5 ;
        RECT  51.792 0 51.816 0.084 ;
    END
  END wb_reserve_base[9]
  PIN wb_reserve_epoch[0]
    DIRECTION OUTPUT ;
    USE SIGNAL ;
    PORT
      LAYER M5 ;
        RECT  54 0 54.024 0.084 ;
    END
  END wb_reserve_epoch[0]
  PIN wb_reserve_epoch[10]
    DIRECTION OUTPUT ;
    USE SIGNAL ;
    PORT
      LAYER M5 ;
        RECT  54.96 0 54.984 0.084 ;
    END
  END wb_reserve_epoch[10]
  PIN wb_reserve_epoch[11]
    DIRECTION OUTPUT ;
    USE SIGNAL ;
    PORT
      LAYER M5 ;
        RECT  55.056 0 55.08 0.084 ;
    END
  END wb_reserve_epoch[11]
  PIN wb_reserve_epoch[12]
    DIRECTION OUTPUT ;
    USE SIGNAL ;
    PORT
      LAYER M5 ;
        RECT  55.152 0 55.176 0.084 ;
    END
  END wb_reserve_epoch[12]
  PIN wb_reserve_epoch[13]
    DIRECTION OUTPUT ;
    USE SIGNAL ;
    PORT
      LAYER M5 ;
        RECT  55.248 0 55.272 0.084 ;
    END
  END wb_reserve_epoch[13]
  PIN wb_reserve_epoch[14]
    DIRECTION OUTPUT ;
    USE SIGNAL ;
    PORT
      LAYER M5 ;
        RECT  55.344 0 55.368 0.084 ;
    END
  END wb_reserve_epoch[14]
  PIN wb_reserve_epoch[15]
    DIRECTION OUTPUT ;
    USE SIGNAL ;
    PORT
      LAYER M5 ;
        RECT  55.44 0 55.464 0.084 ;
    END
  END wb_reserve_epoch[15]
  PIN wb_reserve_epoch[1]
    DIRECTION OUTPUT ;
    USE SIGNAL ;
    PORT
      LAYER M5 ;
        RECT  54.096 0 54.12 0.084 ;
    END
  END wb_reserve_epoch[1]
  PIN wb_reserve_epoch[2]
    DIRECTION OUTPUT ;
    USE SIGNAL ;
    PORT
      LAYER M5 ;
        RECT  54.192 0 54.216 0.084 ;
    END
  END wb_reserve_epoch[2]
  PIN wb_reserve_epoch[3]
    DIRECTION OUTPUT ;
    USE SIGNAL ;
    PORT
      LAYER M5 ;
        RECT  54.288 0 54.312 0.084 ;
    END
  END wb_reserve_epoch[3]
  PIN wb_reserve_epoch[4]
    DIRECTION OUTPUT ;
    USE SIGNAL ;
    PORT
      LAYER M5 ;
        RECT  54.384 0 54.408 0.084 ;
    END
  END wb_reserve_epoch[4]
  PIN wb_reserve_epoch[5]
    DIRECTION OUTPUT ;
    USE SIGNAL ;
    PORT
      LAYER M5 ;
        RECT  54.48 0 54.504 0.084 ;
    END
  END wb_reserve_epoch[5]
  PIN wb_reserve_epoch[6]
    DIRECTION OUTPUT ;
    USE SIGNAL ;
    PORT
      LAYER M5 ;
        RECT  54.576 0 54.6 0.084 ;
    END
  END wb_reserve_epoch[6]
  PIN wb_reserve_epoch[7]
    DIRECTION OUTPUT ;
    USE SIGNAL ;
    PORT
      LAYER M5 ;
        RECT  54.672 0 54.696 0.084 ;
    END
  END wb_reserve_epoch[7]
  PIN wb_reserve_epoch[8]
    DIRECTION OUTPUT ;
    USE SIGNAL ;
    PORT
      LAYER M5 ;
        RECT  54.768 0 54.792 0.084 ;
    END
  END wb_reserve_epoch[8]
  PIN wb_reserve_epoch[9]
    DIRECTION OUTPUT ;
    USE SIGNAL ;
    PORT
      LAYER M5 ;
        RECT  54.864 0 54.888 0.084 ;
    END
  END wb_reserve_epoch[9]
  PIN wb_reserve_sectors[0]
    DIRECTION OUTPUT ;
    USE SIGNAL ;
    PORT
      LAYER M5 ;
        RECT  55.536 0 55.56 0.084 ;
    END
  END wb_reserve_sectors[0]
  PIN wb_reserve_sectors[10]
    DIRECTION OUTPUT ;
    USE SIGNAL ;
    PORT
      LAYER M5 ;
        RECT  56.496 0 56.52 0.084 ;
    END
  END wb_reserve_sectors[10]
  PIN wb_reserve_sectors[11]
    DIRECTION OUTPUT ;
    USE SIGNAL ;
    PORT
      LAYER M5 ;
        RECT  56.592 0 56.616 0.084 ;
    END
  END wb_reserve_sectors[11]
  PIN wb_reserve_sectors[1]
    DIRECTION OUTPUT ;
    USE SIGNAL ;
    PORT
      LAYER M5 ;
        RECT  55.632 0 55.656 0.084 ;
    END
  END wb_reserve_sectors[1]
  PIN wb_reserve_sectors[2]
    DIRECTION OUTPUT ;
    USE SIGNAL ;
    PORT
      LAYER M5 ;
        RECT  55.728 0 55.752 0.084 ;
    END
  END wb_reserve_sectors[2]
  PIN wb_reserve_sectors[3]
    DIRECTION OUTPUT ;
    USE SIGNAL ;
    PORT
      LAYER M5 ;
        RECT  55.824 0 55.848 0.084 ;
    END
  END wb_reserve_sectors[3]
  PIN wb_reserve_sectors[4]
    DIRECTION OUTPUT ;
    USE SIGNAL ;
    PORT
      LAYER M5 ;
        RECT  55.92 0 55.944 0.084 ;
    END
  END wb_reserve_sectors[4]
  PIN wb_reserve_sectors[5]
    DIRECTION OUTPUT ;
    USE SIGNAL ;
    PORT
      LAYER M5 ;
        RECT  56.016 0 56.04 0.084 ;
    END
  END wb_reserve_sectors[5]
  PIN wb_reserve_sectors[6]
    DIRECTION OUTPUT ;
    USE SIGNAL ;
    PORT
      LAYER M5 ;
        RECT  56.112 0 56.136 0.084 ;
    END
  END wb_reserve_sectors[6]
  PIN wb_reserve_sectors[7]
    DIRECTION OUTPUT ;
    USE SIGNAL ;
    PORT
      LAYER M5 ;
        RECT  56.208 0 56.232 0.084 ;
    END
  END wb_reserve_sectors[7]
  PIN wb_reserve_sectors[8]
    DIRECTION OUTPUT ;
    USE SIGNAL ;
    PORT
      LAYER M5 ;
        RECT  56.304 0 56.328 0.084 ;
    END
  END wb_reserve_sectors[8]
  PIN wb_reserve_sectors[9]
    DIRECTION OUTPUT ;
    USE SIGNAL ;
    PORT
      LAYER M5 ;
        RECT  56.4 0 56.424 0.084 ;
    END
  END wb_reserve_sectors[9]
  PIN wb_reserve_v
    DIRECTION OUTPUT ;
    USE SIGNAL ;
    PORT
      LAYER M5 ;
        RECT  56.688 0 56.712 0.084 ;
    END
  END wb_reserve_v
  PIN VDD
    DIRECTION INOUT ;
    USE POWER ;
    PORT
      LAYER M5 ;
        RECT  72.792 2.151 72.912 73.449 ;
        RECT  67.392 2.151 67.512 73.449 ;
        RECT  61.992 2.151 62.112 73.449 ;
        RECT  56.592 2.151 56.712 73.449 ;
        RECT  51.192 2.151 51.312 73.449 ;
        RECT  45.792 2.151 45.912 73.449 ;
        RECT  40.392 2.151 40.512 73.449 ;
        RECT  34.992 2.151 35.112 73.449 ;
        RECT  29.592 2.151 29.712 73.449 ;
        RECT  24.192 2.151 24.312 73.449 ;
        RECT  18.792 2.151 18.912 73.449 ;
        RECT  13.392 2.151 13.512 73.449 ;
        RECT  7.992 2.151 8.112 73.449 ;
        RECT  2.592 2.151 2.712 73.449 ;
    END
  END VDD
  PIN VSS
    DIRECTION INOUT ;
    USE GROUND ;
    PORT
      LAYER M5 ;
        RECT  72.6 2.137 72.72 73.463 ;
        RECT  67.2 2.137 67.32 73.463 ;
        RECT  61.8 2.137 61.92 73.463 ;
        RECT  56.4 2.137 56.52 73.463 ;
        RECT  51 2.137 51.12 73.463 ;
        RECT  45.6 2.137 45.72 73.463 ;
        RECT  40.2 2.137 40.32 73.463 ;
        RECT  34.8 2.137 34.92 73.463 ;
        RECT  29.4 2.137 29.52 73.463 ;
        RECT  24 2.137 24.12 73.463 ;
        RECT  18.6 2.137 18.72 73.463 ;
        RECT  13.2 2.137 13.32 73.463 ;
        RECT  7.8 2.137 7.92 73.463 ;
        RECT  2.4 2.137 2.52 73.463 ;
    END
  END VSS
  # OT_OBS_CLOSED layer=M5 d_um=1.536 added=451
  OBS
    LAYER LVTN ;
     RECT  29.754 3.105 30.132 3.24 ;
     RECT  29.43 3.645 30.024 3.78 ;
     RECT  29.484 3.78 29.808 3.915 ;
     RECT  30.78 3.78 31.104 3.915 ;
     RECT  30.834 4.725 31.158 4.86 ;
     RECT  6.534 5.94 6.966 6.075 ;
     RECT  15.714 5.94 16.038 6.075 ;
     RECT  9.018 6.345 9.45 6.48 ;
     RECT  16.308 6.345 16.632 6.48 ;
     RECT  19.926 6.345 20.52 6.48 ;
     RECT  26.46 6.48 27.108 6.615 ;
     RECT  27.324 6.48 27.648 6.615 ;
     RECT  30.672 6.48 30.996 6.615 ;
     RECT  21.87 6.885 22.194 7.02 ;
     RECT  14.796 7.02 15.12 7.155 ;
     RECT  14.796 7.56 15.336 7.695 ;
     RECT  69.012 7.56 70.416 7.695 ;
     RECT  25.272 8.1 25.866 8.235 ;
     RECT  69.174 8.1 70.578 8.235 ;
     RECT  22.14 8.505 22.572 8.64 ;
     RECT  30.672 8.505 30.996 8.64 ;
     RECT  69.282 8.505 70.686 8.64 ;
     RECT  22.086 9.045 22.95 9.18 ;
     RECT  68.148 9.045 68.472 9.18 ;
     RECT  22.302 9.18 22.68 9.315 ;
     RECT  69.282 9.18 70.686 9.315 ;
     RECT  21.924 9.585 22.302 9.72 ;
     RECT  69.606 9.585 71.01 9.72 ;
     RECT  68.418 9.72 71.226 9.855 ;
     RECT  68.85 10.125 70.254 10.26 ;
     RECT  20.088 10.26 20.898 10.395 ;
     RECT  30.456 10.26 30.78 10.395 ;
     RECT  69.984 10.26 71.388 10.395 ;
     RECT  68.58 10.665 69.984 10.8 ;
     RECT  70.038 10.665 71.442 10.8 ;
     RECT  70.146 10.8 71.55 10.935 ;
     RECT  58.32 11.205 58.752 11.34 ;
     RECT  60.426 11.205 60.804 11.34 ;
     RECT  70.254 11.205 71.658 11.34 ;
     RECT  70.308 11.34 71.712 11.475 ;
     RECT  70.092 11.745 71.496 11.88 ;
     RECT  70.524 12.285 71.928 12.42 ;
     RECT  15.012 12.825 15.336 12.96 ;
     RECT  19.818 13.905 20.25 14.04 ;
     RECT  20.304 14.04 20.628 14.175 ;
     RECT  21.06 14.04 21.654 14.175 ;
     RECT  19.386 14.445 19.98 14.58 ;
     RECT  19.656 14.58 20.034 14.715 ;
     RECT  31.212 15.12 31.644 15.255 ;
     RECT  31.266 15.525 31.59 15.66 ;
     RECT  30.294 16.2 30.726 16.335 ;
     RECT  31.59 16.74 31.968 16.875 ;
     RECT  50.814 17.685 51.192 17.82 ;
     RECT  42.984 18.9 43.362 19.035 ;
     RECT  44.766 18.9 45.468 19.035 ;
     RECT  45.144 19.305 45.468 19.44 ;
     RECT  43.038 19.305 43.362 19.575 ;
     RECT  43.956 19.44 44.388 19.575 ;
     RECT  45.198 19.44 45.63 19.575 ;
     RECT  42.228 19.98 42.606 20.115 ;
     RECT  45.036 19.98 45.738 20.115 ;
     RECT  42.282 20.385 42.606 20.52 ;
     RECT  45.468 20.385 45.9 20.52 ;
     RECT  42.876 20.52 43.2 20.655 ;
     RECT  43.632 20.52 44.064 20.655 ;
     RECT  45.036 20.52 45.36 20.655 ;
     RECT  43.632 20.925 44.28 21.06 ;
     RECT  43.848 21.06 44.82 21.195 ;
     RECT  44.658 21.6 45.09 21.735 ;
     RECT  44.712 23.085 45.144 23.22 ;
     RECT  44.496 23.22 44.82 23.355 ;
     RECT  45.252 23.22 45.576 23.355 ;
     RECT  45.252 23.625 45.63 23.76 ;
     RECT  51.084 28.62 51.408 28.755 ;
     RECT  53.73 29.16 54.108 29.295 ;
     RECT  54.702 29.16 55.134 29.295 ;
     RECT  55.674 29.16 56.052 29.295 ;
     RECT  53.892 29.565 54.324 29.7 ;
     RECT  53.838 29.7 54.27 29.835 ;
     RECT  54.702 29.7 55.134 29.835 ;
     RECT  54.324 30.24 54.648 30.375 ;
     RECT  53.676 30.645 54.216 30.78 ;
     RECT  55.728 30.645 56.808 30.78 ;
     RECT  56.376 31.185 56.754 31.32 ;
     RECT  8.532 32.265 9.126 32.4 ;
     RECT  8.586 32.4 9.18 32.535 ;
     RECT  7.83 32.805 8.154 32.94 ;
     RECT  8.208 32.805 8.802 32.94 ;
     RECT  9.504 32.94 10.098 33.075 ;
     RECT  9.45 33.345 10.044 33.48 ;
     RECT  9.18 33.885 9.774 34.02 ;
     RECT  8.91 34.02 9.504 34.155 ;
     RECT  7.83 34.425 8.37 34.56 ;
     RECT  9.072 34.425 9.396 34.56 ;
     RECT  7.884 34.56 8.208 34.695 ;
     RECT  8.046 34.965 8.37 35.1 ;
     RECT  14.904 35.1 15.228 35.235 ;
     RECT  49.734 37.125 50.058 37.26 ;
     RECT  43.092 37.8 43.416 37.935 ;
     RECT  8.154 41.58 8.586 41.715 ;
     RECT  8.964 43.065 9.45 43.2 ;
     RECT  9.18 43.2 9.666 43.335 ;
     RECT  9.882 43.605 10.044 43.74 ;
     RECT  9.936 43.74 10.368 43.875 ;
     RECT  10.746 49.68 11.286 49.815 ;
     RECT  14.472 55.62 14.796 55.755 ;
     RECT  45.792 55.62 46.386 55.755 ;
     RECT  46.062 56.025 46.386 56.16 ;
     RECT  45.954 56.16 46.656 56.295 ;
     RECT  14.202 56.565 14.634 56.7 ;
     RECT  14.688 56.565 15.282 56.7 ;
     RECT  14.31 56.7 14.634 56.835 ;
     RECT  15.606 56.7 16.2 56.835 ;
     RECT  6.372 58.725 6.804 58.86 ;
     RECT  5.724 58.86 6.318 58.995 ;
     RECT  14.418 59.805 14.742 59.94 ;
     RECT  6.48 60.48 7.074 60.615 ;
     RECT  6.75 60.885 7.398 61.02 ;
     RECT  3.942 61.02 4.428 61.155 ;
     RECT  7.074 61.02 7.83 61.155 ;
     RECT  3.024 61.965 3.672 62.1 ;
     RECT  5.94 62.1 6.534 62.235 ;
     RECT  2.7 63.72 3.186 63.855 ;
     RECT  3.078 64.26 3.618 64.395 ;
     RECT  3.456 65.745 3.942 65.88 ;
     RECT  3.834 68.985 4.914 69.12 ;
     RECT  4.482 69.12 4.806 69.255 ;
     RECT  42.822 69.525 43.092 69.66 ;
    LAYER LVTP ;
     RECT  29.754 2.97 30.132 3.105 ;
     RECT  29.43 3.51 30.024 3.645 ;
     RECT  29.484 3.915 29.808 4.05 ;
     RECT  30.78 3.915 31.104 4.05 ;
     RECT  30.834 4.59 31.158 4.725 ;
     RECT  6.534 6.075 6.966 6.21 ;
     RECT  15.714 6.075 16.038 6.21 ;
     RECT  9.018 6.21 9.45 6.345 ;
     RECT  16.308 6.21 16.632 6.345 ;
     RECT  19.926 6.21 20.52 6.345 ;
     RECT  26.46 6.615 27.108 6.75 ;
     RECT  27.324 6.615 27.648 6.75 ;
     RECT  30.672 6.615 30.996 6.75 ;
     RECT  21.87 6.75 22.194 6.885 ;
     RECT  14.796 7.155 15.12 7.29 ;
     RECT  14.796 7.695 15.336 7.83 ;
     RECT  69.012 7.695 70.416 7.83 ;
     RECT  25.272 8.235 25.866 8.37 ;
     RECT  69.174 8.235 70.578 8.37 ;
     RECT  22.14 8.37 22.572 8.505 ;
     RECT  30.672 8.37 30.996 8.505 ;
     RECT  69.282 8.37 70.686 8.505 ;
     RECT  22.086 8.91 22.95 9.045 ;
     RECT  68.148 8.91 68.472 9.045 ;
     RECT  22.302 9.315 22.68 9.45 ;
     RECT  69.282 9.315 70.686 9.45 ;
     RECT  21.924 9.45 22.302 9.585 ;
     RECT  69.606 9.45 71.01 9.585 ;
     RECT  68.418 9.855 71.226 9.99 ;
     RECT  68.85 9.99 70.254 10.125 ;
     RECT  20.088 10.395 20.898 10.53 ;
     RECT  30.456 10.395 30.78 10.53 ;
     RECT  69.984 10.395 71.388 10.53 ;
     RECT  68.58 10.53 69.984 10.665 ;
     RECT  70.038 10.53 71.442 10.665 ;
     RECT  70.146 10.935 71.55 11.07 ;
     RECT  58.32 11.07 58.752 11.205 ;
     RECT  60.426 11.07 60.804 11.205 ;
     RECT  70.254 11.07 71.658 11.205 ;
     RECT  70.308 11.475 71.712 11.61 ;
     RECT  70.092 11.61 71.496 11.745 ;
     RECT  70.524 12.15 71.928 12.285 ;
     RECT  15.012 12.69 15.336 12.825 ;
     RECT  19.818 13.77 20.25 13.905 ;
     RECT  20.304 14.175 20.628 14.31 ;
     RECT  21.06 14.175 21.654 14.31 ;
     RECT  19.386 14.31 19.98 14.445 ;
     RECT  19.656 14.715 20.034 14.85 ;
     RECT  31.212 15.255 31.644 15.39 ;
     RECT  31.266 15.39 31.59 15.525 ;
     RECT  30.294 16.335 30.726 16.47 ;
     RECT  31.59 16.875 31.968 17.01 ;
     RECT  50.814 17.55 51.192 17.685 ;
     RECT  42.984 19.035 43.362 19.17 ;
     RECT  44.766 19.035 45.468 19.17 ;
     RECT  43.038 19.17 43.362 19.305 ;
     RECT  45.144 19.17 45.468 19.305 ;
     RECT  43.038 19.575 43.362 19.71 ;
     RECT  43.956 19.575 44.388 19.71 ;
     RECT  45.198 19.575 45.63 19.71 ;
     RECT  42.228 20.115 42.606 20.25 ;
     RECT  45.036 20.115 45.738 20.25 ;
     RECT  42.282 20.25 42.606 20.385 ;
     RECT  45.468 20.25 45.9 20.385 ;
     RECT  42.876 20.655 43.2 20.79 ;
     RECT  43.632 20.655 44.064 20.79 ;
     RECT  45.036 20.655 45.36 20.79 ;
     RECT  43.632 20.79 44.28 20.925 ;
     RECT  43.848 21.195 44.82 21.33 ;
     RECT  44.658 21.735 45.09 21.87 ;
     RECT  44.712 22.95 45.144 23.085 ;
     RECT  44.496 23.355 44.82 23.49 ;
     RECT  45.252 23.355 45.576 23.49 ;
     RECT  45.252 23.49 45.63 23.625 ;
     RECT  51.084 28.755 51.408 28.89 ;
     RECT  53.73 29.295 54.108 29.43 ;
     RECT  54.702 29.295 55.134 29.43 ;
     RECT  55.674 29.295 56.052 29.43 ;
     RECT  53.892 29.43 54.324 29.565 ;
     RECT  53.838 29.835 54.27 29.97 ;
     RECT  54.702 29.835 55.134 29.97 ;
     RECT  54.324 30.375 54.648 30.51 ;
     RECT  53.676 30.51 54.216 30.645 ;
     RECT  55.728 30.51 56.808 30.645 ;
     RECT  56.376 31.05 56.754 31.185 ;
     RECT  8.532 32.13 9.126 32.265 ;
     RECT  8.586 32.535 9.18 32.67 ;
     RECT  7.83 32.67 8.154 32.805 ;
     RECT  8.208 32.67 8.802 32.805 ;
     RECT  9.504 33.075 10.098 33.21 ;
     RECT  9.45 33.21 10.044 33.345 ;
     RECT  9.18 33.75 9.774 33.885 ;
     RECT  8.91 34.155 9.504 34.29 ;
     RECT  7.83 34.29 8.37 34.425 ;
     RECT  9.072 34.29 9.396 34.425 ;
     RECT  7.884 34.695 8.208 34.83 ;
     RECT  8.046 34.83 8.37 34.965 ;
     RECT  14.904 35.235 15.228 35.37 ;
     RECT  49.734 36.99 50.058 37.125 ;
     RECT  43.092 37.935 43.416 38.07 ;
     RECT  8.154 41.715 8.586 41.85 ;
     RECT  8.964 42.93 9.45 43.065 ;
     RECT  9.18 43.335 9.666 43.47 ;
     RECT  9.882 43.47 10.044 43.605 ;
     RECT  9.936 43.875 10.368 44.01 ;
     RECT  10.746 49.815 11.286 49.95 ;
     RECT  14.472 55.755 14.796 55.89 ;
     RECT  45.792 55.755 46.386 55.89 ;
     RECT  46.062 55.89 46.386 56.025 ;
     RECT  45.954 56.295 46.656 56.43 ;
     RECT  14.202 56.43 14.634 56.565 ;
     RECT  14.688 56.43 15.282 56.565 ;
     RECT  14.31 56.835 14.634 56.97 ;
     RECT  15.606 56.835 16.2 56.97 ;
     RECT  6.372 58.59 6.804 58.725 ;
     RECT  5.724 58.995 6.318 59.13 ;
     RECT  14.418 59.67 14.742 59.805 ;
     RECT  6.48 60.615 7.074 60.75 ;
     RECT  6.75 60.75 7.398 60.885 ;
     RECT  3.942 61.155 4.428 61.29 ;
     RECT  7.074 61.155 7.83 61.29 ;
     RECT  3.024 61.83 3.672 61.965 ;
     RECT  5.94 62.235 6.534 62.37 ;
     RECT  2.7 63.855 3.186 63.99 ;
     RECT  3.078 64.395 3.618 64.53 ;
     RECT  3.456 65.61 3.942 65.745 ;
     RECT  3.834 68.85 4.914 68.985 ;
     RECT  4.482 69.255 4.806 69.39 ;
     RECT  42.822 69.39 43.092 69.525 ;
    LAYER RVTN ;
     RECT  2.16 2.16 73.44 2.295 ;
     RECT  2.16 2.565 73.44 2.835 ;
     RECT  2.16 3.105 29.754 3.24 ;
     RECT  30.132 3.105 73.44 3.24 ;
     RECT  2.16 3.24 73.44 3.375 ;
     RECT  2.16 3.645 29.43 3.78 ;
     RECT  30.024 3.645 73.44 3.78 ;
     RECT  2.16 3.78 29.484 3.915 ;
     RECT  29.808 3.78 30.78 3.915 ;
     RECT  31.104 3.78 73.44 3.915 ;
     RECT  2.16 4.185 73.44 4.455 ;
     RECT  2.16 4.725 30.834 4.86 ;
     RECT  31.158 4.725 73.44 4.86 ;
     RECT  2.16 4.86 73.44 4.995 ;
     RECT  2.16 5.265 73.44 5.535 ;
     RECT  2.16 5.805 73.44 5.94 ;
     RECT  2.16 5.94 6.534 6.075 ;
     RECT  6.966 5.94 15.714 6.075 ;
     RECT  16.038 5.94 73.44 6.075 ;
     RECT  2.16 6.345 9.018 6.48 ;
     RECT  9.45 6.345 16.308 6.48 ;
     RECT  16.632 6.345 19.926 6.48 ;
     RECT  20.52 6.345 73.44 6.48 ;
     RECT  2.16 6.48 26.46 6.615 ;
     RECT  27.108 6.48 27.324 6.615 ;
     RECT  27.648 6.48 30.672 6.615 ;
     RECT  30.996 6.48 73.44 6.615 ;
     RECT  2.16 6.885 21.87 7.02 ;
     RECT  22.194 6.885 73.44 7.02 ;
     RECT  2.16 7.02 14.796 7.155 ;
     RECT  15.12 7.02 73.44 7.155 ;
     RECT  2.16 7.425 73.44 7.56 ;
     RECT  2.16 7.56 14.796 7.695 ;
     RECT  15.336 7.56 69.012 7.695 ;
     RECT  70.416 7.56 73.44 7.695 ;
     RECT  2.16 7.965 73.44 8.1 ;
     RECT  2.16 8.1 25.272 8.235 ;
     RECT  25.866 8.1 69.174 8.235 ;
     RECT  70.578 8.1 73.44 8.235 ;
     RECT  2.16 8.505 22.14 8.64 ;
     RECT  22.572 8.505 30.672 8.64 ;
     RECT  30.996 8.505 69.282 8.64 ;
     RECT  70.686 8.505 73.44 8.64 ;
     RECT  2.16 8.64 73.44 8.775 ;
     RECT  2.16 9.045 22.086 9.18 ;
     RECT  22.95 9.045 68.148 9.18 ;
     RECT  68.472 9.045 73.44 9.18 ;
     RECT  2.16 9.18 22.302 9.315 ;
     RECT  22.68 9.18 69.282 9.315 ;
     RECT  70.686 9.18 73.44 9.315 ;
     RECT  2.16 9.585 21.924 9.72 ;
     RECT  22.302 9.585 69.606 9.72 ;
     RECT  71.01 9.585 73.44 9.72 ;
     RECT  2.16 9.72 68.418 9.855 ;
     RECT  71.226 9.72 73.44 9.855 ;
     RECT  2.16 10.125 68.85 10.26 ;
     RECT  70.254 10.125 73.44 10.26 ;
     RECT  2.16 10.26 20.088 10.395 ;
     RECT  20.898 10.26 30.456 10.395 ;
     RECT  30.78 10.26 69.984 10.395 ;
     RECT  71.388 10.26 73.44 10.395 ;
     RECT  2.16 10.665 68.58 10.8 ;
     RECT  69.984 10.665 70.038 10.8 ;
     RECT  71.442 10.665 73.44 10.8 ;
     RECT  2.16 10.8 70.146 10.935 ;
     RECT  71.55 10.8 73.44 10.935 ;
     RECT  2.16 11.205 58.32 11.34 ;
     RECT  58.752 11.205 60.426 11.34 ;
     RECT  60.804 11.205 70.254 11.34 ;
     RECT  71.658 11.205 73.44 11.34 ;
     RECT  2.16 11.34 70.308 11.475 ;
     RECT  71.712 11.34 73.44 11.475 ;
     RECT  2.16 11.745 70.092 11.88 ;
     RECT  71.496 11.745 73.44 11.88 ;
     RECT  2.16 11.88 73.44 12.015 ;
     RECT  2.16 12.285 70.524 12.42 ;
     RECT  71.928 12.285 73.44 12.42 ;
     RECT  2.16 12.42 73.44 12.555 ;
     RECT  2.16 12.825 15.012 12.96 ;
     RECT  15.336 12.825 73.44 12.96 ;
     RECT  2.16 12.96 73.44 13.095 ;
     RECT  2.16 13.365 73.44 13.635 ;
     RECT  2.16 13.905 19.818 14.04 ;
     RECT  20.25 13.905 73.44 14.04 ;
     RECT  2.16 14.04 20.304 14.175 ;
     RECT  20.628 14.04 21.06 14.175 ;
     RECT  21.654 14.04 73.44 14.175 ;
     RECT  2.16 14.445 19.386 14.58 ;
     RECT  19.98 14.445 73.44 14.58 ;
     RECT  2.16 14.58 19.656 14.715 ;
     RECT  20.034 14.58 73.44 14.715 ;
     RECT  2.16 14.985 73.44 15.12 ;
     RECT  2.16 15.12 31.212 15.255 ;
     RECT  31.644 15.12 73.44 15.255 ;
     RECT  2.16 15.525 31.266 15.66 ;
     RECT  31.59 15.525 73.44 15.66 ;
     RECT  2.16 15.66 73.44 15.795 ;
     RECT  2.16 16.065 73.44 16.2 ;
     RECT  2.16 16.2 30.294 16.335 ;
     RECT  30.726 16.2 73.44 16.335 ;
     RECT  2.16 16.605 73.44 16.74 ;
     RECT  2.16 16.74 31.59 16.875 ;
     RECT  31.968 16.74 73.44 16.875 ;
     RECT  2.16 17.145 73.44 17.415 ;
     RECT  2.16 17.685 50.814 17.82 ;
     RECT  51.192 17.685 73.44 17.82 ;
     RECT  2.16 17.82 73.44 17.955 ;
     RECT  2.16 18.225 73.44 18.495 ;
     RECT  2.16 18.765 73.44 18.9 ;
     RECT  2.16 18.9 42.984 19.035 ;
     RECT  43.362 18.9 44.766 19.035 ;
     RECT  45.468 18.9 73.44 19.035 ;
     RECT  43.362 19.305 45.144 19.44 ;
     RECT  45.468 19.305 73.44 19.44 ;
     RECT  2.16 19.305 43.038 19.575 ;
     RECT  43.362 19.44 43.956 19.575 ;
     RECT  44.388 19.44 45.198 19.575 ;
     RECT  45.63 19.44 73.44 19.575 ;
     RECT  2.16 19.845 73.44 19.98 ;
     RECT  2.16 19.98 42.228 20.115 ;
     RECT  42.606 19.98 45.036 20.115 ;
     RECT  45.738 19.98 73.44 20.115 ;
     RECT  2.16 20.385 42.282 20.52 ;
     RECT  42.606 20.385 45.468 20.52 ;
     RECT  45.9 20.385 73.44 20.52 ;
     RECT  2.16 20.52 42.876 20.655 ;
     RECT  43.2 20.52 43.632 20.655 ;
     RECT  44.064 20.52 45.036 20.655 ;
     RECT  45.36 20.52 73.44 20.655 ;
     RECT  2.16 20.925 43.632 21.06 ;
     RECT  44.28 20.925 73.44 21.06 ;
     RECT  2.16 21.06 43.848 21.195 ;
     RECT  44.82 21.06 73.44 21.195 ;
     RECT  2.16 21.465 73.44 21.6 ;
     RECT  2.16 21.6 44.658 21.735 ;
     RECT  45.09 21.6 73.44 21.735 ;
     RECT  2.16 22.005 73.44 22.275 ;
     RECT  2.16 22.545 73.44 22.815 ;
     RECT  2.16 23.085 44.712 23.22 ;
     RECT  45.144 23.085 73.44 23.22 ;
     RECT  2.16 23.22 44.496 23.355 ;
     RECT  44.82 23.22 45.252 23.355 ;
     RECT  45.576 23.22 73.44 23.355 ;
     RECT  2.16 23.625 45.252 23.76 ;
     RECT  45.63 23.625 73.44 23.76 ;
     RECT  2.16 23.76 73.44 23.895 ;
     RECT  2.16 24.165 73.44 24.435 ;
     RECT  2.16 24.705 73.44 24.975 ;
     RECT  2.16 25.245 73.44 25.515 ;
     RECT  2.16 25.785 73.44 26.055 ;
     RECT  2.16 26.325 73.44 26.595 ;
     RECT  2.16 26.865 73.44 27.135 ;
     RECT  2.16 27.405 73.44 27.675 ;
     RECT  2.16 27.945 73.44 28.215 ;
     RECT  2.16 28.485 73.44 28.62 ;
     RECT  2.16 28.62 51.084 28.755 ;
     RECT  51.408 28.62 73.44 28.755 ;
     RECT  2.16 29.025 73.44 29.16 ;
     RECT  2.16 29.16 53.73 29.295 ;
     RECT  54.108 29.16 54.702 29.295 ;
     RECT  55.134 29.16 55.674 29.295 ;
     RECT  56.052 29.16 73.44 29.295 ;
     RECT  2.16 29.565 53.892 29.7 ;
     RECT  54.324 29.565 73.44 29.7 ;
     RECT  2.16 29.7 53.838 29.835 ;
     RECT  54.27 29.7 54.702 29.835 ;
     RECT  55.134 29.7 73.44 29.835 ;
     RECT  2.16 30.105 73.44 30.24 ;
     RECT  2.16 30.24 54.324 30.375 ;
     RECT  54.648 30.24 73.44 30.375 ;
     RECT  2.16 30.645 53.676 30.78 ;
     RECT  54.216 30.645 55.728 30.78 ;
     RECT  56.808 30.645 73.44 30.78 ;
     RECT  2.16 30.78 73.44 30.915 ;
     RECT  2.16 31.185 56.376 31.32 ;
     RECT  56.754 31.185 73.44 31.32 ;
     RECT  2.16 31.32 73.44 31.455 ;
     RECT  2.16 31.725 73.44 31.995 ;
     RECT  2.16 32.265 8.532 32.4 ;
     RECT  9.126 32.265 73.44 32.4 ;
     RECT  2.16 32.4 8.586 32.535 ;
     RECT  9.18 32.4 73.44 32.535 ;
     RECT  2.16 32.805 7.83 32.94 ;
     RECT  8.154 32.805 8.208 32.94 ;
     RECT  8.802 32.805 73.44 32.94 ;
     RECT  2.16 32.94 9.504 33.075 ;
     RECT  10.098 32.94 73.44 33.075 ;
     RECT  2.16 33.345 9.45 33.48 ;
     RECT  10.044 33.345 73.44 33.48 ;
     RECT  2.16 33.48 73.44 33.615 ;
     RECT  2.16 33.885 9.18 34.02 ;
     RECT  9.774 33.885 73.44 34.02 ;
     RECT  2.16 34.02 8.91 34.155 ;
     RECT  9.504 34.02 73.44 34.155 ;
     RECT  2.16 34.425 7.83 34.56 ;
     RECT  8.37 34.425 9.072 34.56 ;
     RECT  9.396 34.425 73.44 34.56 ;
     RECT  2.16 34.56 7.884 34.695 ;
     RECT  8.208 34.56 73.44 34.695 ;
     RECT  2.16 34.965 8.046 35.1 ;
     RECT  8.37 34.965 73.44 35.1 ;
     RECT  2.16 35.1 14.904 35.235 ;
     RECT  15.228 35.1 73.44 35.235 ;
     RECT  2.16 35.505 73.44 35.775 ;
     RECT  2.16 36.045 73.44 36.315 ;
     RECT  2.16 36.585 73.44 36.855 ;
     RECT  2.16 37.125 49.734 37.26 ;
     RECT  50.058 37.125 73.44 37.26 ;
     RECT  2.16 37.26 73.44 37.395 ;
     RECT  2.16 37.665 73.44 37.8 ;
     RECT  2.16 37.8 43.092 37.935 ;
     RECT  43.416 37.8 73.44 37.935 ;
     RECT  2.16 38.205 73.44 38.475 ;
     RECT  2.16 38.745 73.44 39.015 ;
     RECT  2.16 39.285 73.44 39.555 ;
     RECT  2.16 39.825 73.44 40.095 ;
     RECT  2.16 40.365 73.44 40.635 ;
     RECT  2.16 40.905 73.44 41.175 ;
     RECT  2.16 41.445 73.44 41.58 ;
     RECT  2.16 41.58 8.154 41.715 ;
     RECT  8.586 41.58 73.44 41.715 ;
     RECT  2.16 41.985 73.44 42.255 ;
     RECT  2.16 42.525 73.44 42.795 ;
     RECT  2.16 43.065 8.964 43.2 ;
     RECT  9.45 43.065 73.44 43.2 ;
     RECT  2.16 43.2 9.18 43.335 ;
     RECT  9.666 43.2 73.44 43.335 ;
     RECT  2.16 43.605 9.882 43.74 ;
     RECT  10.044 43.605 73.44 43.74 ;
     RECT  2.16 43.74 9.936 43.875 ;
     RECT  10.368 43.74 73.44 43.875 ;
     RECT  2.16 44.145 73.44 44.415 ;
     RECT  2.16 44.685 73.44 44.955 ;
     RECT  2.16 45.225 73.44 45.495 ;
     RECT  2.16 45.765 73.44 46.035 ;
     RECT  2.16 46.305 73.44 46.575 ;
     RECT  2.16 46.845 73.44 47.115 ;
     RECT  2.16 47.385 73.44 47.655 ;
     RECT  2.16 47.925 73.44 48.195 ;
     RECT  2.16 48.465 73.44 48.735 ;
     RECT  2.16 49.005 73.44 49.275 ;
     RECT  2.16 49.545 73.44 49.68 ;
     RECT  2.16 49.68 10.746 49.815 ;
     RECT  11.286 49.68 73.44 49.815 ;
     RECT  2.16 50.085 73.44 50.355 ;
     RECT  2.16 50.625 73.44 50.895 ;
     RECT  2.16 51.165 73.44 51.435 ;
     RECT  2.16 51.705 73.44 51.975 ;
     RECT  2.16 52.245 73.44 52.515 ;
     RECT  2.16 52.785 73.44 53.055 ;
     RECT  2.16 53.325 73.44 53.595 ;
     RECT  2.16 53.865 73.44 54.135 ;
     RECT  2.16 54.405 73.44 54.675 ;
     RECT  2.16 54.945 73.44 55.215 ;
     RECT  2.16 55.485 73.44 55.62 ;
     RECT  2.16 55.62 14.472 55.755 ;
     RECT  14.796 55.62 45.792 55.755 ;
     RECT  46.386 55.62 73.44 55.755 ;
     RECT  2.16 56.025 46.062 56.16 ;
     RECT  46.386 56.025 73.44 56.16 ;
     RECT  2.16 56.16 45.954 56.295 ;
     RECT  46.656 56.16 73.44 56.295 ;
     RECT  2.16 56.565 14.202 56.7 ;
     RECT  14.634 56.565 14.688 56.7 ;
     RECT  15.282 56.565 73.44 56.7 ;
     RECT  2.16 56.7 14.31 56.835 ;
     RECT  14.634 56.7 15.606 56.835 ;
     RECT  16.2 56.7 73.44 56.835 ;
     RECT  2.16 57.105 73.44 57.375 ;
     RECT  2.16 57.645 73.44 57.915 ;
     RECT  2.16 58.185 73.44 58.455 ;
     RECT  2.16 58.725 6.372 58.86 ;
     RECT  6.804 58.725 73.44 58.86 ;
     RECT  2.16 58.86 5.724 58.995 ;
     RECT  6.318 58.86 73.44 58.995 ;
     RECT  2.16 59.265 73.44 59.535 ;
     RECT  2.16 59.805 14.418 59.94 ;
     RECT  14.742 59.805 73.44 59.94 ;
     RECT  2.16 59.94 73.44 60.075 ;
     RECT  2.16 60.345 73.44 60.48 ;
     RECT  2.16 60.48 6.48 60.615 ;
     RECT  7.074 60.48 73.44 60.615 ;
     RECT  2.16 60.885 6.75 61.02 ;
     RECT  7.398 60.885 73.44 61.02 ;
     RECT  2.16 61.02 3.942 61.155 ;
     RECT  4.428 61.02 7.074 61.155 ;
     RECT  7.83 61.02 73.44 61.155 ;
     RECT  2.16 61.425 73.44 61.695 ;
     RECT  2.16 61.965 3.024 62.1 ;
     RECT  3.672 61.965 73.44 62.1 ;
     RECT  2.16 62.1 5.94 62.235 ;
     RECT  6.534 62.1 73.44 62.235 ;
     RECT  2.16 62.505 73.44 62.775 ;
     RECT  2.16 63.045 73.44 63.315 ;
     RECT  2.16 63.585 73.44 63.72 ;
     RECT  2.16 63.72 2.7 63.855 ;
     RECT  3.186 63.72 73.44 63.855 ;
     RECT  2.16 64.125 73.44 64.26 ;
     RECT  2.16 64.26 3.078 64.395 ;
     RECT  3.618 64.26 73.44 64.395 ;
     RECT  2.16 64.665 73.44 64.935 ;
     RECT  2.16 65.205 73.44 65.475 ;
     RECT  2.16 65.745 3.456 65.88 ;
     RECT  3.942 65.745 73.44 65.88 ;
     RECT  2.16 65.88 73.44 66.015 ;
     RECT  2.16 66.285 73.44 66.555 ;
     RECT  2.16 66.825 73.44 67.095 ;
     RECT  2.16 67.365 73.44 67.635 ;
     RECT  2.16 67.905 73.44 68.175 ;
     RECT  2.16 68.445 73.44 68.715 ;
     RECT  2.16 68.985 3.834 69.12 ;
     RECT  4.914 68.985 73.44 69.12 ;
     RECT  2.16 69.12 4.482 69.255 ;
     RECT  4.806 69.12 73.44 69.255 ;
     RECT  2.16 69.525 42.822 69.66 ;
     RECT  43.092 69.525 73.44 69.66 ;
     RECT  2.16 69.66 73.44 69.795 ;
     RECT  2.16 70.065 73.44 70.335 ;
     RECT  2.16 70.605 73.44 70.875 ;
     RECT  2.16 71.145 73.44 71.415 ;
     RECT  2.16 71.685 73.44 71.955 ;
     RECT  2.16 72.225 73.44 72.495 ;
     RECT  2.16 72.765 73.44 73.035 ;
     RECT  2.16 73.305 73.44 73.44 ;
    LAYER RVTP ;
     RECT  2.16 2.295 73.44 2.565 ;
     RECT  2.16 2.835 73.44 2.97 ;
     RECT  2.16 2.97 29.754 3.105 ;
     RECT  30.132 2.97 73.44 3.105 ;
     RECT  2.16 3.375 73.44 3.51 ;
     RECT  2.16 3.51 29.43 3.645 ;
     RECT  30.024 3.51 73.44 3.645 ;
     RECT  2.16 3.915 29.484 4.05 ;
     RECT  29.808 3.915 30.78 4.05 ;
     RECT  31.104 3.915 73.44 4.05 ;
     RECT  2.16 4.05 73.44 4.185 ;
     RECT  2.16 4.455 73.44 4.59 ;
     RECT  2.16 4.59 30.834 4.725 ;
     RECT  31.158 4.59 73.44 4.725 ;
     RECT  2.16 4.995 73.44 5.265 ;
     RECT  2.16 5.535 73.44 5.805 ;
     RECT  2.16 6.075 6.534 6.21 ;
     RECT  6.966 6.075 15.714 6.21 ;
     RECT  16.038 6.075 73.44 6.21 ;
     RECT  2.16 6.21 9.018 6.345 ;
     RECT  9.45 6.21 16.308 6.345 ;
     RECT  16.632 6.21 19.926 6.345 ;
     RECT  20.52 6.21 73.44 6.345 ;
     RECT  2.16 6.615 26.46 6.75 ;
     RECT  27.108 6.615 27.324 6.75 ;
     RECT  27.648 6.615 30.672 6.75 ;
     RECT  30.996 6.615 73.44 6.75 ;
     RECT  2.16 6.75 21.87 6.885 ;
     RECT  22.194 6.75 73.44 6.885 ;
     RECT  2.16 7.155 14.796 7.29 ;
     RECT  15.12 7.155 73.44 7.29 ;
     RECT  2.16 7.29 73.44 7.425 ;
     RECT  2.16 7.695 14.796 7.83 ;
     RECT  15.336 7.695 69.012 7.83 ;
     RECT  70.416 7.695 73.44 7.83 ;
     RECT  2.16 7.83 73.44 7.965 ;
     RECT  2.16 8.235 25.272 8.37 ;
     RECT  25.866 8.235 69.174 8.37 ;
     RECT  70.578 8.235 73.44 8.37 ;
     RECT  2.16 8.37 22.14 8.505 ;
     RECT  22.572 8.37 30.672 8.505 ;
     RECT  30.996 8.37 69.282 8.505 ;
     RECT  70.686 8.37 73.44 8.505 ;
     RECT  2.16 8.775 73.44 8.91 ;
     RECT  2.16 8.91 22.086 9.045 ;
     RECT  22.95 8.91 68.148 9.045 ;
     RECT  68.472 8.91 73.44 9.045 ;
     RECT  2.16 9.315 22.302 9.45 ;
     RECT  22.68 9.315 69.282 9.45 ;
     RECT  70.686 9.315 73.44 9.45 ;
     RECT  2.16 9.45 21.924 9.585 ;
     RECT  22.302 9.45 69.606 9.585 ;
     RECT  71.01 9.45 73.44 9.585 ;
     RECT  2.16 9.855 68.418 9.99 ;
     RECT  71.226 9.855 73.44 9.99 ;
     RECT  2.16 9.99 68.85 10.125 ;
     RECT  70.254 9.99 73.44 10.125 ;
     RECT  2.16 10.395 20.088 10.53 ;
     RECT  20.898 10.395 30.456 10.53 ;
     RECT  30.78 10.395 69.984 10.53 ;
     RECT  71.388 10.395 73.44 10.53 ;
     RECT  2.16 10.53 68.58 10.665 ;
     RECT  69.984 10.53 70.038 10.665 ;
     RECT  71.442 10.53 73.44 10.665 ;
     RECT  2.16 10.935 70.146 11.07 ;
     RECT  71.55 10.935 73.44 11.07 ;
     RECT  2.16 11.07 58.32 11.205 ;
     RECT  58.752 11.07 60.426 11.205 ;
     RECT  60.804 11.07 70.254 11.205 ;
     RECT  71.658 11.07 73.44 11.205 ;
     RECT  2.16 11.475 70.308 11.61 ;
     RECT  71.712 11.475 73.44 11.61 ;
     RECT  2.16 11.61 70.092 11.745 ;
     RECT  71.496 11.61 73.44 11.745 ;
     RECT  2.16 12.015 73.44 12.15 ;
     RECT  2.16 12.15 70.524 12.285 ;
     RECT  71.928 12.15 73.44 12.285 ;
     RECT  2.16 12.555 73.44 12.69 ;
     RECT  2.16 12.69 15.012 12.825 ;
     RECT  15.336 12.69 73.44 12.825 ;
     RECT  2.16 13.095 73.44 13.365 ;
     RECT  2.16 13.635 73.44 13.77 ;
     RECT  2.16 13.77 19.818 13.905 ;
     RECT  20.25 13.77 73.44 13.905 ;
     RECT  2.16 14.175 20.304 14.31 ;
     RECT  20.628 14.175 21.06 14.31 ;
     RECT  21.654 14.175 73.44 14.31 ;
     RECT  2.16 14.31 19.386 14.445 ;
     RECT  19.98 14.31 73.44 14.445 ;
     RECT  2.16 14.715 19.656 14.85 ;
     RECT  20.034 14.715 73.44 14.85 ;
     RECT  2.16 14.85 73.44 14.985 ;
     RECT  2.16 15.255 31.212 15.39 ;
     RECT  31.644 15.255 73.44 15.39 ;
     RECT  2.16 15.39 31.266 15.525 ;
     RECT  31.59 15.39 73.44 15.525 ;
     RECT  2.16 15.795 73.44 16.065 ;
     RECT  2.16 16.335 30.294 16.47 ;
     RECT  30.726 16.335 73.44 16.47 ;
     RECT  2.16 16.47 73.44 16.605 ;
     RECT  2.16 16.875 31.59 17.01 ;
     RECT  31.968 16.875 73.44 17.01 ;
     RECT  2.16 17.01 73.44 17.145 ;
     RECT  2.16 17.415 73.44 17.55 ;
     RECT  2.16 17.55 50.814 17.685 ;
     RECT  51.192 17.55 73.44 17.685 ;
     RECT  2.16 17.955 73.44 18.225 ;
     RECT  2.16 18.495 73.44 18.765 ;
     RECT  2.16 19.035 42.984 19.17 ;
     RECT  43.362 19.035 44.766 19.17 ;
     RECT  2.16 19.17 43.038 19.305 ;
     RECT  43.362 19.17 45.144 19.305 ;
     RECT  45.468 19.035 73.44 19.305 ;
     RECT  2.16 19.575 43.038 19.71 ;
     RECT  43.362 19.575 43.956 19.71 ;
     RECT  44.388 19.575 45.198 19.71 ;
     RECT  45.63 19.575 73.44 19.71 ;
     RECT  2.16 19.71 73.44 19.845 ;
     RECT  2.16 20.115 42.228 20.25 ;
     RECT  42.606 20.115 45.036 20.25 ;
     RECT  45.738 20.115 73.44 20.25 ;
     RECT  2.16 20.25 42.282 20.385 ;
     RECT  42.606 20.25 45.468 20.385 ;
     RECT  45.9 20.25 73.44 20.385 ;
     RECT  2.16 20.655 42.876 20.79 ;
     RECT  43.2 20.655 43.632 20.79 ;
     RECT  44.064 20.655 45.036 20.79 ;
     RECT  45.36 20.655 73.44 20.79 ;
     RECT  2.16 20.79 43.632 20.925 ;
     RECT  44.28 20.79 73.44 20.925 ;
     RECT  2.16 21.195 43.848 21.33 ;
     RECT  44.82 21.195 73.44 21.33 ;
     RECT  2.16 21.33 73.44 21.465 ;
     RECT  2.16 21.735 44.658 21.87 ;
     RECT  45.09 21.735 73.44 21.87 ;
     RECT  2.16 21.87 73.44 22.005 ;
     RECT  2.16 22.275 73.44 22.545 ;
     RECT  2.16 22.815 73.44 22.95 ;
     RECT  2.16 22.95 44.712 23.085 ;
     RECT  45.144 22.95 73.44 23.085 ;
     RECT  2.16 23.355 44.496 23.49 ;
     RECT  44.82 23.355 45.252 23.49 ;
     RECT  45.576 23.355 73.44 23.49 ;
     RECT  2.16 23.49 45.252 23.625 ;
     RECT  45.63 23.49 73.44 23.625 ;
     RECT  2.16 23.895 73.44 24.165 ;
     RECT  2.16 24.435 73.44 24.705 ;
     RECT  2.16 24.975 73.44 25.245 ;
     RECT  2.16 25.515 73.44 25.785 ;
     RECT  2.16 26.055 73.44 26.325 ;
     RECT  2.16 26.595 73.44 26.865 ;
     RECT  2.16 27.135 73.44 27.405 ;
     RECT  2.16 27.675 73.44 27.945 ;
     RECT  2.16 28.215 73.44 28.485 ;
     RECT  2.16 28.755 51.084 28.89 ;
     RECT  51.408 28.755 73.44 28.89 ;
     RECT  2.16 28.89 73.44 29.025 ;
     RECT  2.16 29.295 53.73 29.43 ;
     RECT  54.108 29.295 54.702 29.43 ;
     RECT  55.134 29.295 55.674 29.43 ;
     RECT  56.052 29.295 73.44 29.43 ;
     RECT  2.16 29.43 53.892 29.565 ;
     RECT  54.324 29.43 73.44 29.565 ;
     RECT  2.16 29.835 53.838 29.97 ;
     RECT  54.27 29.835 54.702 29.97 ;
     RECT  55.134 29.835 73.44 29.97 ;
     RECT  2.16 29.97 73.44 30.105 ;
     RECT  2.16 30.375 54.324 30.51 ;
     RECT  54.648 30.375 73.44 30.51 ;
     RECT  2.16 30.51 53.676 30.645 ;
     RECT  54.216 30.51 55.728 30.645 ;
     RECT  56.808 30.51 73.44 30.645 ;
     RECT  2.16 30.915 73.44 31.05 ;
     RECT  2.16 31.05 56.376 31.185 ;
     RECT  56.754 31.05 73.44 31.185 ;
     RECT  2.16 31.455 73.44 31.725 ;
     RECT  2.16 31.995 73.44 32.13 ;
     RECT  2.16 32.13 8.532 32.265 ;
     RECT  9.126 32.13 73.44 32.265 ;
     RECT  2.16 32.535 8.586 32.67 ;
     RECT  9.18 32.535 73.44 32.67 ;
     RECT  2.16 32.67 7.83 32.805 ;
     RECT  8.154 32.67 8.208 32.805 ;
     RECT  8.802 32.67 73.44 32.805 ;
     RECT  2.16 33.075 9.504 33.21 ;
     RECT  10.098 33.075 73.44 33.21 ;
     RECT  2.16 33.21 9.45 33.345 ;
     RECT  10.044 33.21 73.44 33.345 ;
     RECT  2.16 33.615 73.44 33.75 ;
     RECT  2.16 33.75 9.18 33.885 ;
     RECT  9.774 33.75 73.44 33.885 ;
     RECT  2.16 34.155 8.91 34.29 ;
     RECT  9.504 34.155 73.44 34.29 ;
     RECT  2.16 34.29 7.83 34.425 ;
     RECT  8.37 34.29 9.072 34.425 ;
     RECT  9.396 34.29 73.44 34.425 ;
     RECT  2.16 34.695 7.884 34.83 ;
     RECT  8.208 34.695 73.44 34.83 ;
     RECT  2.16 34.83 8.046 34.965 ;
     RECT  8.37 34.83 73.44 34.965 ;
     RECT  2.16 35.235 14.904 35.37 ;
     RECT  15.228 35.235 73.44 35.37 ;
     RECT  2.16 35.37 73.44 35.505 ;
     RECT  2.16 35.775 73.44 36.045 ;
     RECT  2.16 36.315 73.44 36.585 ;
     RECT  2.16 36.855 73.44 36.99 ;
     RECT  2.16 36.99 49.734 37.125 ;
     RECT  50.058 36.99 73.44 37.125 ;
     RECT  2.16 37.395 73.44 37.665 ;
     RECT  2.16 37.935 43.092 38.07 ;
     RECT  43.416 37.935 73.44 38.07 ;
     RECT  2.16 38.07 73.44 38.205 ;
     RECT  2.16 38.475 73.44 38.745 ;
     RECT  2.16 39.015 73.44 39.285 ;
     RECT  2.16 39.555 73.44 39.825 ;
     RECT  2.16 40.095 73.44 40.365 ;
     RECT  2.16 40.635 73.44 40.905 ;
     RECT  2.16 41.175 73.44 41.445 ;
     RECT  2.16 41.715 8.154 41.85 ;
     RECT  8.586 41.715 73.44 41.85 ;
     RECT  2.16 41.85 73.44 41.985 ;
     RECT  2.16 42.255 73.44 42.525 ;
     RECT  2.16 42.795 73.44 42.93 ;
     RECT  2.16 42.93 8.964 43.065 ;
     RECT  9.45 42.93 73.44 43.065 ;
     RECT  2.16 43.335 9.18 43.47 ;
     RECT  9.666 43.335 73.44 43.47 ;
     RECT  2.16 43.47 9.882 43.605 ;
     RECT  10.044 43.47 73.44 43.605 ;
     RECT  2.16 43.875 9.936 44.01 ;
     RECT  10.368 43.875 73.44 44.01 ;
     RECT  2.16 44.01 73.44 44.145 ;
     RECT  2.16 44.415 73.44 44.685 ;
     RECT  2.16 44.955 73.44 45.225 ;
     RECT  2.16 45.495 73.44 45.765 ;
     RECT  2.16 46.035 73.44 46.305 ;
     RECT  2.16 46.575 73.44 46.845 ;
     RECT  2.16 47.115 73.44 47.385 ;
     RECT  2.16 47.655 73.44 47.925 ;
     RECT  2.16 48.195 73.44 48.465 ;
     RECT  2.16 48.735 73.44 49.005 ;
     RECT  2.16 49.275 73.44 49.545 ;
     RECT  2.16 49.815 10.746 49.95 ;
     RECT  11.286 49.815 73.44 49.95 ;
     RECT  2.16 49.95 73.44 50.085 ;
     RECT  2.16 50.355 73.44 50.625 ;
     RECT  2.16 50.895 73.44 51.165 ;
     RECT  2.16 51.435 73.44 51.705 ;
     RECT  2.16 51.975 73.44 52.245 ;
     RECT  2.16 52.515 73.44 52.785 ;
     RECT  2.16 53.055 73.44 53.325 ;
     RECT  2.16 53.595 73.44 53.865 ;
     RECT  2.16 54.135 73.44 54.405 ;
     RECT  2.16 54.675 73.44 54.945 ;
     RECT  2.16 55.215 73.44 55.485 ;
     RECT  2.16 55.755 14.472 55.89 ;
     RECT  14.796 55.755 45.792 55.89 ;
     RECT  2.16 55.89 46.062 56.025 ;
     RECT  46.386 55.755 73.44 56.025 ;
     RECT  2.16 56.295 45.954 56.43 ;
     RECT  46.656 56.295 73.44 56.43 ;
     RECT  2.16 56.43 14.202 56.565 ;
     RECT  14.634 56.43 14.688 56.565 ;
     RECT  15.282 56.43 73.44 56.565 ;
     RECT  2.16 56.835 14.31 56.97 ;
     RECT  14.634 56.835 15.606 56.97 ;
     RECT  16.2 56.835 73.44 56.97 ;
     RECT  2.16 56.97 73.44 57.105 ;
     RECT  2.16 57.375 73.44 57.645 ;
     RECT  2.16 57.915 73.44 58.185 ;
     RECT  2.16 58.455 73.44 58.59 ;
     RECT  2.16 58.59 6.372 58.725 ;
     RECT  6.804 58.59 73.44 58.725 ;
     RECT  2.16 58.995 5.724 59.13 ;
     RECT  6.318 58.995 73.44 59.13 ;
     RECT  2.16 59.13 73.44 59.265 ;
     RECT  2.16 59.535 73.44 59.67 ;
     RECT  2.16 59.67 14.418 59.805 ;
     RECT  14.742 59.67 73.44 59.805 ;
     RECT  2.16 60.075 73.44 60.345 ;
     RECT  2.16 60.615 6.48 60.75 ;
     RECT  7.074 60.615 73.44 60.75 ;
     RECT  2.16 60.75 6.75 60.885 ;
     RECT  7.398 60.75 73.44 60.885 ;
     RECT  2.16 61.155 3.942 61.29 ;
     RECT  4.428 61.155 7.074 61.29 ;
     RECT  7.83 61.155 73.44 61.29 ;
     RECT  2.16 61.29 73.44 61.425 ;
     RECT  2.16 61.695 73.44 61.83 ;
     RECT  2.16 61.83 3.024 61.965 ;
     RECT  3.672 61.83 73.44 61.965 ;
     RECT  2.16 62.235 5.94 62.37 ;
     RECT  6.534 62.235 73.44 62.37 ;
     RECT  2.16 62.37 73.44 62.505 ;
     RECT  2.16 62.775 73.44 63.045 ;
     RECT  2.16 63.315 73.44 63.585 ;
     RECT  2.16 63.855 2.7 63.99 ;
     RECT  3.186 63.855 73.44 63.99 ;
     RECT  2.16 63.99 73.44 64.125 ;
     RECT  2.16 64.395 3.078 64.53 ;
     RECT  3.618 64.395 73.44 64.53 ;
     RECT  2.16 64.53 73.44 64.665 ;
     RECT  2.16 64.935 73.44 65.205 ;
     RECT  2.16 65.475 73.44 65.61 ;
     RECT  2.16 65.61 3.456 65.745 ;
     RECT  3.942 65.61 73.44 65.745 ;
     RECT  2.16 66.015 73.44 66.285 ;
     RECT  2.16 66.555 73.44 66.825 ;
     RECT  2.16 67.095 73.44 67.365 ;
     RECT  2.16 67.635 73.44 67.905 ;
     RECT  2.16 68.175 73.44 68.445 ;
     RECT  2.16 68.715 73.44 68.85 ;
     RECT  2.16 68.85 3.834 68.985 ;
     RECT  4.914 68.85 73.44 68.985 ;
     RECT  2.16 69.255 4.482 69.39 ;
     RECT  4.806 69.255 73.44 69.39 ;
     RECT  2.16 69.39 42.822 69.525 ;
     RECT  43.092 69.39 73.44 69.525 ;
     RECT  2.16 69.795 73.44 70.065 ;
     RECT  2.16 70.335 73.44 70.605 ;
     RECT  2.16 70.875 73.44 71.145 ;
     RECT  2.16 71.415 73.44 71.685 ;
     RECT  2.16 71.955 73.44 72.225 ;
     RECT  2.16 72.495 73.44 72.765 ;
     RECT  2.16 73.035 73.44 73.305 ;
    LAYER M1 ;
     RECT  2.16 2.151 73.44 73.449 ;
    LAYER M2 ;
     RECT  0.103 22.05 0.175 22.77 ;
     RECT  0.139 8.82 0.211 8.838 ;
     RECT  0.211 7.236 0.347 7.254 ;
     RECT  0.103 49.986 0.347 50.148 ;
     RECT  0.139 57.654 0.347 57.672 ;
     RECT  0.211 8.82 0.383 8.919 ;
     RECT  0.383 8.901 0.599 8.919 ;
     RECT  0.319 46.701 0.779 46.719 ;
     RECT  0.103 10.251 0.887 10.269 ;
     RECT  0.823 12.492 0.895 12.51 ;
     RECT  0.895 12.492 1.147 12.546 ;
     RECT  1.147 7.506 1.723 7.524 ;
     RECT  1.723 7.506 1.759 7.758 ;
     RECT  1.723 43.686 1.759 43.704 ;
     RECT  1.147 12.492 1.831 12.78 ;
     RECT  1.759 6.588 2.16 6.606 ;
     RECT  1.759 7.506 2.16 8.262 ;
     RECT  1.723 9.9 2.16 9.918 ;
     RECT  1.723 11.412 2.16 11.43 ;
     RECT  1.831 12.492 2.16 12.852 ;
     RECT  0.859 13.914 2.16 13.932 ;
     RECT  0.175 21.978 2.16 22.77 ;
     RECT  0.103 36.09 2.16 36.108 ;
     RECT  0.103 37.602 2.16 37.62 ;
     RECT  0.535 38.826 2.16 38.844 ;
     RECT  0.103 40.14 2.16 40.158 ;
     RECT  1.759 43.686 2.16 43.974 ;
     RECT  0.535 45.81 2.16 45.828 ;
     RECT  0.347 50.13 2.16 50.148 ;
     RECT  0.103 56.61 2.16 56.628 ;
     RECT  2.16 2.151 3.739 73.449 ;
     RECT  3.739 2.106 4.415 73.449 ;
     RECT  4.415 2.151 9.643 73.449 ;
     RECT  9.643 2.106 9.923 73.449 ;
     RECT  9.923 2.151 38.335 73.449 ;
     RECT  38.335 2.106 39.911 73.449 ;
     RECT  39.911 2.151 40.639 73.449 ;
     RECT  40.171 1.152 40.847 1.17 ;
     RECT  40.639 2.106 41.855 73.449 ;
     RECT  42.871 1.152 43.115 1.17 ;
     RECT  45.103 1.152 45.275 1.17 ;
     RECT  41.855 2.151 46.183 73.449 ;
     RECT  46.183 2.106 47.255 73.449 ;
     RECT  47.255 2.151 48.127 73.449 ;
     RECT  48.127 2.106 48.551 73.449 ;
     RECT  48.523 1.152 48.623 1.17 ;
     RECT  54.427 1.152 54.563 1.17 ;
     RECT  54.715 0.576 55.291 0.594 ;
     RECT  48.551 2.151 56.443 73.449 ;
     RECT  56.443 1.998 57.947 73.449 ;
     RECT  55.291 0.576 58.235 1.17 ;
     RECT  58.235 0.576 58.379 0.594 ;
     RECT  57.947 2.106 59.423 73.449 ;
     RECT  59.423 2.151 66.811 73.449 ;
     RECT  66.811 2.106 67.559 73.449 ;
     RECT  67.559 2.151 71.815 73.449 ;
     RECT  71.815 2.106 72.491 73.449 ;
     RECT  72.491 2.151 73.44 73.449 ;
     RECT  73.44 30.924 73.499 55.404 ;
     RECT  73.44 18.774 73.535 27.432 ;
     RECT  73.499 30.924 73.571 53.892 ;
     RECT  73.571 31.428 73.787 53.892 ;
     RECT  73.499 54.846 74.003 55.404 ;
     RECT  74.003 54.846 74.075 55.134 ;
     RECT  73.535 19.044 74.111 27.432 ;
     RECT  73.44 28.224 74.111 30.096 ;
     RECT  73.787 31.428 74.111 48.024 ;
     RECT  74.075 54.846 74.111 54.972 ;
     RECT  73.44 61.506 74.111 64.08 ;
     RECT  74.111 26.028 74.147 27.432 ;
     RECT  74.111 29.844 74.147 30.096 ;
     RECT  74.111 37.206 74.147 48.024 ;
     RECT  74.147 37.206 74.579 39.924 ;
     RECT  74.147 26.028 74.615 27.234 ;
     RECT  74.111 28.224 74.615 28.944 ;
     RECT  74.111 61.506 74.615 63.81 ;
     RECT  74.615 27.108 74.651 27.126 ;
     RECT  74.615 28.8 74.651 28.944 ;
     RECT  74.579 38.286 74.651 39.924 ;
     RECT  74.147 40.95 74.651 48.024 ;
     RECT  73.787 48.906 74.651 53.892 ;
     RECT  74.615 61.506 74.651 61.794 ;
     RECT  74.615 63.054 74.651 63.81 ;
     RECT  74.111 19.044 74.687 24.768 ;
     RECT  74.579 37.206 74.687 37.224 ;
     RECT  74.651 43.416 74.687 45.324 ;
     RECT  74.651 46.116 74.687 46.404 ;
     RECT  74.651 49.086 74.687 53.388 ;
     RECT  74.111 54.954 74.687 54.972 ;
     RECT  74.651 61.776 74.687 61.794 ;
     RECT  74.651 40.95 74.723 42.588 ;
     RECT  74.687 44.226 74.723 45.324 ;
     RECT  74.687 49.086 74.723 52.344 ;
     RECT  74.687 20.196 74.759 23.85 ;
     RECT  74.111 31.428 74.759 36.144 ;
     RECT  74.723 40.986 74.759 42.588 ;
     RECT  74.687 46.116 74.759 46.134 ;
     RECT  74.687 19.044 74.795 19.224 ;
     RECT  74.723 44.226 74.795 45.252 ;
     RECT  74.759 20.466 74.831 23.85 ;
     RECT  74.795 44.226 74.831 44.982 ;
     RECT  74.651 38.448 75.335 39.924 ;
     RECT  74.831 21.006 75.407 23.85 ;
     RECT  75.335 38.484 75.407 39.924 ;
     RECT  74.831 44.226 75.407 44.244 ;
     RECT  74.723 49.086 75.407 51.534 ;
     RECT  75.407 23.436 75.415 23.85 ;
     RECT  74.687 24.75 75.415 24.768 ;
     RECT  74.615 26.028 75.415 26.046 ;
     RECT  74.651 28.8 75.415 28.854 ;
     RECT  74.147 29.844 75.415 29.862 ;
     RECT  74.759 31.428 75.443 36.108 ;
     RECT  75.407 38.556 75.443 39.924 ;
     RECT  74.687 43.416 75.443 43.434 ;
     RECT  74.651 47.196 75.443 48.024 ;
     RECT  75.407 49.716 75.443 51.534 ;
     RECT  75.407 21.006 75.479 22.5 ;
     RECT  75.415 23.436 75.479 24.768 ;
     RECT  75.443 32.85 75.479 36.108 ;
     RECT  75.307 37.674 75.479 37.692 ;
     RECT  75.443 38.556 75.479 38.574 ;
     RECT  75.443 39.366 75.479 39.924 ;
     RECT  74.759 41.148 75.479 42.588 ;
     RECT  75.443 47.196 75.479 47.484 ;
     RECT  75.443 49.716 75.479 50.652 ;
     RECT  75.443 51.516 75.479 51.534 ;
     RECT  75.415 29.844 75.487 30.132 ;
     RECT  74.687 53.37 75.487 53.388 ;
     RECT  74.795 19.206 75.515 19.224 ;
     RECT  75.479 21.006 75.515 22.23 ;
     RECT  75.479 23.436 75.515 23.454 ;
     RECT  75.479 24.21 75.515 24.768 ;
     RECT  75.415 25.686 75.515 26.856 ;
     RECT  75.415 28.386 75.515 29.052 ;
     RECT  75.487 29.844 75.515 30.438 ;
     RECT  75.443 31.428 75.515 31.824 ;
     RECT  75.479 32.85 75.515 34.254 ;
     RECT  75.479 35.514 75.515 36.108 ;
     RECT  75.479 39.6 75.515 39.924 ;
     RECT  75.479 41.148 75.515 41.706 ;
     RECT  75.479 42.57 75.515 42.588 ;
     RECT  75.479 47.196 75.515 47.214 ;
     RECT  75.479 49.986 75.515 50.652 ;
     RECT  74.723 52.326 75.515 52.344 ;
     RECT  75.487 53.37 75.515 53.856 ;
     RECT  73.44 56.736 75.515 56.934 ;
     RECT  74.651 63.054 75.515 63.072 ;
     RECT  75.515 22.212 75.587 22.23 ;
     RECT  75.515 26.064 75.587 26.082 ;
     RECT  75.515 30.42 75.587 30.438 ;
     RECT  75.515 33.516 75.587 33.534 ;
     RECT  75.515 53.838 75.587 53.856 ;
     RECT  75.515 56.736 75.587 56.754 ;
    LAYER M3 ;
     RECT  54.504 0.043 54.522 0.091 ;
     RECT  58.176 0.043 58.194 0.091 ;
     RECT  70.056 0.043 70.074 0.091 ;
     RECT  57.636 0.091 58.194 0.187 ;
     RECT  44.172 0.091 44.19 0.221 ;
     RECT  45.576 0.091 45.594 0.221 ;
     RECT  47.124 0.091 50.742 0.221 ;
     RECT  51.804 0.091 51.822 0.221 ;
     RECT  52.668 0.091 52.686 0.221 ;
     RECT  54.432 0.091 55.314 0.235 ;
     RECT  57.636 0.187 58.554 0.283 ;
     RECT  45.36 0.427 45.378 0.475 ;
     RECT  45.252 0.475 45.378 0.523 ;
     RECT  50.4 0.221 50.742 0.523 ;
     RECT  51.624 0.235 51.642 0.523 ;
     RECT  54.432 0.235 55.422 0.599 ;
     RECT  44.64 0.523 45.378 0.605 ;
     RECT  39.06 0.091 39.078 1.051 ;
     RECT  39.888 0.571 39.906 1.051 ;
     RECT  53.532 1.003 53.55 1.051 ;
     RECT  54.432 0.599 54.558 1.051 ;
     RECT  39.06 1.051 39.906 1.099 ;
     RECT  40.752 0.091 42.138 1.099 ;
     RECT  67.356 0.091 67.95 1.099 ;
     RECT  42.876 0.523 42.894 1.147 ;
     RECT  42.876 1.147 43.11 1.175 ;
     RECT  55.296 0.599 55.422 1.175 ;
     RECT  47.844 0.221 49.158 1.723 ;
     RECT  50.4 0.523 51.642 1.723 ;
     RECT  52.488 0.523 52.506 1.723 ;
     RECT  66.96 1.099 67.95 1.723 ;
     RECT  68.832 1.147 68.85 1.723 ;
     RECT  69.768 0.091 70.218 1.723 ;
     RECT  72.18 0.043 72.198 1.723 ;
     RECT  53.532 1.051 54.558 1.771 ;
     RECT  66.96 1.723 70.218 1.771 ;
     RECT  70.956 0.523 70.974 1.771 ;
     RECT  50.4 1.723 52.506 2.059 ;
     RECT  57.636 0.283 58.986 2.065 ;
     RECT  39.06 1.099 42.138 2.101 ;
     RECT  46.08 1.963 46.098 2.101 ;
     RECT  47.268 1.723 49.158 2.101 ;
     RECT  56.448 1.723 56.466 2.101 ;
     RECT  57.24 2.065 58.986 2.101 ;
     RECT  66.96 1.771 70.974 2.101 ;
     RECT  71.82 1.723 72.198 2.101 ;
     RECT  44.64 0.605 45.27 2.143 ;
     RECT  46.08 2.101 46.206 2.143 ;
     RECT  56.448 2.101 59.418 2.143 ;
     RECT  71.82 2.101 72.486 2.143 ;
     RECT  2.415 2.143 2.505 2.155 ;
     RECT  3.744 2.101 4.41 2.155 ;
     RECT  9.648 2.101 9.918 2.155 ;
     RECT  44.64 2.143 46.206 2.155 ;
     RECT  2.304 2.155 2.505 2.191 ;
     RECT  3.744 2.155 5.13 2.191 ;
     RECT  7.815 2.143 7.905 2.191 ;
     RECT  13.215 2.143 13.305 2.191 ;
     RECT  38.34 2.101 42.138 2.191 ;
     RECT  42.948 1.175 43.11 2.191 ;
     RECT  44.064 2.155 46.206 2.191 ;
     RECT  50.076 2.059 52.506 2.191 ;
     RECT  53.388 1.771 54.558 2.191 ;
     RECT  55.332 1.175 55.422 2.191 ;
     RECT  56.415 2.143 59.418 2.191 ;
     RECT  10.692 2.191 10.962 2.227 ;
     RECT  12.852 2.191 13.305 2.227 ;
     RECT  16.128 2.191 16.146 2.227 ;
     RECT  47.232 2.101 49.158 2.227 ;
     RECT  2.304 2.191 5.13 2.263 ;
     RECT  5.94 2.191 7.905 2.263 ;
     RECT  10.692 2.227 11.826 2.263 ;
     RECT  16.128 2.227 16.434 2.263 ;
     RECT  18.615 2.143 18.705 2.263 ;
     RECT  34.815 2.143 34.905 2.263 ;
     RECT  38.34 2.191 46.206 2.263 ;
     RECT  47.052 2.227 49.158 2.263 ;
     RECT  50.076 2.191 52.542 2.263 ;
     RECT  53.388 2.191 59.418 2.263 ;
     RECT  66.816 2.101 70.974 2.263 ;
     RECT  71.82 2.143 72.705 2.263 ;
     RECT  20.484 2.191 20.502 2.299 ;
     RECT  9.144 2.155 9.918 2.335 ;
     RECT  15.552 2.263 16.434 2.335 ;
     RECT  26.424 2.191 26.442 2.335 ;
     RECT  29.415 2.143 29.505 2.335 ;
     RECT  9.108 2.335 9.918 2.371 ;
     RECT  10.692 2.263 12.078 2.371 ;
     RECT  12.852 2.227 13.77 2.371 ;
     RECT  17.64 2.263 18.705 2.371 ;
     RECT  20.484 2.299 21.15 2.371 ;
     RECT  23.04 2.299 23.058 2.371 ;
     RECT  26.424 2.335 26.622 2.371 ;
     RECT  28.944 2.335 29.505 2.371 ;
     RECT  33.552 2.299 33.57 2.371 ;
     RECT  34.308 2.263 34.905 2.371 ;
     RECT  38.34 2.263 59.418 2.371 ;
     RECT  2.304 2.263 7.905 2.413 ;
     RECT  17.532 2.371 18.705 2.413 ;
     RECT  24.015 2.143 24.105 2.413 ;
     RECT  61.815 2.143 61.905 2.413 ;
     RECT  66.708 2.263 72.705 2.413 ;
     RECT  9.108 2.371 12.078 2.461 ;
     RECT  12.852 2.371 13.95 2.461 ;
     RECT  19.944 2.371 21.15 2.461 ;
     RECT  28.368 2.371 30.006 2.461 ;
     RECT  66.708 2.413 72.897 2.489 ;
     RECT  32.04 2.461 32.706 2.491 ;
     RECT  33.444 2.371 33.57 2.491 ;
     RECT  34.308 2.371 35.298 2.491 ;
     RECT  2.304 2.413 8.097 2.497 ;
     RECT  15.552 2.335 16.578 2.569 ;
     RECT  28.008 2.461 30.006 2.569 ;
     RECT  36.648 2.533 36.666 2.569 ;
     RECT  2.304 2.497 8.334 2.605 ;
     RECT  9.108 2.461 13.95 2.605 ;
     RECT  15.552 2.569 16.65 2.605 ;
     RECT  19.944 2.461 21.546 2.605 ;
     RECT  22.824 2.371 23.058 2.605 ;
     RECT  32.04 2.491 35.298 2.605 ;
     RECT  36.324 2.569 36.666 2.605 ;
     RECT  2.304 2.605 13.95 2.641 ;
     RECT  15.408 2.605 16.722 2.641 ;
     RECT  17.532 2.413 18.897 2.641 ;
     RECT  19.908 2.605 21.546 2.641 ;
     RECT  22.32 2.605 23.058 2.641 ;
     RECT  24.015 2.413 24.297 2.641 ;
     RECT  25.704 2.371 26.622 2.641 ;
     RECT  27.504 2.569 30.006 2.641 ;
     RECT  0.18 2.587 0.198 2.731 ;
     RECT  15.408 2.641 18.897 2.731 ;
     RECT  19.908 2.641 24.297 2.731 ;
     RECT  31.176 2.641 31.194 2.731 ;
     RECT  38.232 2.371 59.418 2.731 ;
     RECT  25.704 2.641 30.186 2.779 ;
     RECT  31.068 2.731 31.194 2.779 ;
     RECT  25.704 2.779 31.194 2.803 ;
     RECT  32.04 2.605 36.666 2.803 ;
     RECT  0.18 2.731 0.342 2.861 ;
     RECT  2.304 2.641 14.562 2.911 ;
     RECT  25.704 2.803 36.666 3.073 ;
     RECT  15.408 2.731 24.297 3.145 ;
     RECT  25.344 3.073 36.666 3.145 ;
     RECT  25.344 3.145 36.99 3.181 ;
     RECT  38.232 2.731 59.526 3.181 ;
     RECT  66.78 2.489 72.897 3.209 ;
     RECT  0.144 3.067 0.162 3.245 ;
     RECT  15.408 3.145 24.498 3.271 ;
     RECT  25.344 3.181 37.134 3.271 ;
     RECT  2.304 2.911 14.634 3.307 ;
     RECT  15.408 3.271 37.134 3.307 ;
     RECT  2.304 3.307 37.134 3.379 ;
     RECT  37.908 3.181 59.526 3.379 ;
     RECT  2.196 3.379 59.526 3.437 ;
     RECT  66.888 3.209 72.897 4.109 ;
     RECT  2.268 3.437 59.526 4.189 ;
     RECT  2.196 4.189 59.526 4.379 ;
     RECT  59.508 4.379 59.526 4.451 ;
     RECT  0.432 4.555 0.45 4.685 ;
     RECT  2.196 4.379 58.734 4.843 ;
     RECT  1.764 4.843 58.734 5.419 ;
     RECT  1.152 5.419 58.734 5.431 ;
     RECT  60.192 5.737 60.21 5.773 ;
     RECT  67.215 4.109 72.897 5.773 ;
     RECT  1.152 5.431 59.454 5.809 ;
     RECT  60.192 5.773 60.462 5.809 ;
     RECT  1.152 5.809 60.462 5.881 ;
     RECT  1.152 5.881 60.534 5.971 ;
     RECT  67.104 5.773 72.897 6.079 ;
     RECT  61.815 2.413 62.097 6.115 ;
     RECT  1.152 5.971 60.642 6.151 ;
     RECT  61.416 6.115 62.097 6.151 ;
     RECT  65.268 6.091 65.286 6.151 ;
     RECT  66.06 6.079 66.078 6.151 ;
     RECT  1.152 6.151 62.097 6.269 ;
     RECT  45 6.269 62.097 6.341 ;
     RECT  65.268 6.151 66.078 6.349 ;
     RECT  65.088 6.349 66.078 6.421 ;
     RECT  66.816 6.079 72.897 6.421 ;
     RECT  0.324 6.283 0.342 7.003 ;
     RECT  65.088 6.421 72.897 7.133 ;
     RECT  45.072 6.341 62.097 7.231 ;
     RECT  45 7.231 62.097 7.393 ;
     RECT  1.152 6.269 44.262 7.465 ;
     RECT  45 7.393 62.154 7.465 ;
     RECT  1.152 7.465 62.154 7.501 ;
     RECT  1.152 7.501 62.298 7.529 ;
     RECT  1.728 7.529 62.298 7.591 ;
     RECT  1.728 7.591 62.37 7.763 ;
     RECT  0.144 7.003 0.342 7.819 ;
     RECT  65.16 7.133 72.897 7.915 ;
     RECT  65.088 7.915 72.897 7.961 ;
     RECT  0.144 7.819 0.846 8.011 ;
     RECT  1.764 7.763 62.37 8.347 ;
     RECT  1.764 8.347 62.73 8.635 ;
     RECT  1.728 8.635 62.73 9.121 ;
     RECT  1.728 9.121 63.342 9.319 ;
     RECT  65.16 7.961 72.897 9.349 ;
     RECT  1.728 9.319 63.414 9.391 ;
     RECT  65.052 9.349 72.897 9.499 ;
     RECT  64.872 9.499 72.897 9.629 ;
     RECT  0.108 8.011 0.846 9.643 ;
     RECT  1.728 9.391 63.918 9.653 ;
     RECT  0.108 9.643 0.918 9.835 ;
     RECT  1.728 9.653 62.766 9.835 ;
     RECT  65.484 9.629 72.897 9.887 ;
     RECT  65.484 9.887 65.502 10.061 ;
     RECT  66.384 9.887 72.897 10.157 ;
     RECT  0.108 9.835 62.766 10.229 ;
     RECT  66.672 10.157 72.897 10.355 ;
     RECT  67.215 10.355 72.897 11.101 ;
     RECT  0.108 10.229 62.73 11.129 ;
     RECT  0.108 11.129 46.998 11.261 ;
     RECT  47.772 11.129 62.73 11.309 ;
     RECT  66.708 11.101 72.897 11.309 ;
     RECT  47.772 11.309 62.097 11.435 ;
     RECT  47.844 11.435 62.097 11.669 ;
     RECT  47.844 11.669 47.97 11.975 ;
     RECT  67.215 11.309 72.897 12.209 ;
     RECT  48.852 11.669 62.097 12.245 ;
     RECT  0.828 11.261 46.998 12.325 ;
     RECT  47.844 11.975 47.862 12.325 ;
     RECT  49.32 12.245 62.097 12.509 ;
     RECT  0.828 12.325 47.862 12.515 ;
     RECT  0.864 12.515 47.862 12.785 ;
     RECT  1.836 12.785 47.862 12.857 ;
     RECT  67.215 12.209 71.406 12.859 ;
     RECT  66.708 12.859 71.406 13.037 ;
     RECT  67.215 13.037 71.406 13.163 ;
     RECT  67.215 13.163 70.47 13.289 ;
     RECT  71.568 13.171 71.586 13.361 ;
     RECT  67.215 13.289 70.29 13.397 ;
     RECT  67.215 13.397 70.146 13.469 ;
     RECT  67.215 13.469 70.11 13.559 ;
     RECT  49.392 12.509 62.097 13.829 ;
     RECT  2.304 12.857 47.862 13.865 ;
     RECT  0.864 12.785 0.882 13.937 ;
     RECT  67.215 13.559 68.202 14.747 ;
     RECT  63.648 13.945 63.666 15.089 ;
     RECT  49.392 13.829 58.374 15.187 ;
     RECT  59.112 13.829 62.097 15.187 ;
     RECT  2.415 13.865 47.862 15.485 ;
     RECT  2.415 15.485 3.258 15.719 ;
     RECT  2.415 15.719 2.826 15.728 ;
     RECT  4.032 15.485 47.862 15.755 ;
     RECT  4.536 15.755 47.862 15.989 ;
     RECT  49.392 15.187 62.097 15.989 ;
     RECT  49.392 15.989 60.714 16.529 ;
     RECT  4.752 15.989 47.862 16.835 ;
     RECT  49.392 16.529 58.77 16.915 ;
     RECT  4.752 16.835 4.77 17.069 ;
     RECT  5.544 16.835 47.862 17.105 ;
     RECT  20.952 17.105 47.862 17.405 ;
     RECT  42.552 17.405 47.862 17.491 ;
     RECT  48.852 16.915 58.77 17.581 ;
     RECT  59.616 16.529 60.714 17.581 ;
     RECT  42.552 17.491 48.042 17.609 ;
     RECT  48.852 17.581 60.714 17.609 ;
     RECT  48.852 17.609 60.174 17.645 ;
     RECT  48.852 17.645 58.698 17.717 ;
     RECT  5.544 17.105 20.214 17.923 ;
     RECT  20.952 17.405 41.814 17.923 ;
     RECT  5.544 17.923 41.814 18.031 ;
     RECT  59.616 17.645 60.174 18.149 ;
     RECT  48.852 17.717 58.158 18.157 ;
     RECT  5.436 18.031 41.814 18.535 ;
     RECT  42.552 17.609 47.862 18.535 ;
     RECT  5.436 18.535 47.862 18.571 ;
     RECT  48.816 18.157 58.158 18.571 ;
     RECT  72.615 12.209 72.897 18.661 ;
     RECT  5.436 18.571 58.158 18.689 ;
     RECT  72.615 18.661 72.954 18.697 ;
     RECT  72.576 18.697 72.954 18.769 ;
     RECT  5.436 18.689 47.862 18.811 ;
     RECT  5.364 18.811 47.862 18.833 ;
     RECT  5.364 18.833 26.37 18.841 ;
     RECT  48.6 18.689 58.158 18.959 ;
     RECT  48.744 18.959 58.158 18.995 ;
     RECT  27.108 18.833 47.862 19.067 ;
     RECT  72.576 18.769 73.53 19.075 ;
     RECT  39.276 19.067 47.862 19.139 ;
     RECT  69.264 13.559 70.11 19.139 ;
     RECT  72.396 19.075 73.53 19.201 ;
     RECT  74.772 19.039 74.79 19.201 ;
     RECT  72 19.201 73.53 19.273 ;
     RECT  74.772 19.201 75.51 19.273 ;
     RECT  4.968 18.841 26.37 19.337 ;
     RECT  69.516 19.139 70.11 19.345 ;
     RECT  22.176 19.337 26.37 19.373 ;
     RECT  39.384 19.139 47.862 19.421 ;
     RECT  22.248 19.373 26.37 19.615 ;
     RECT  27.108 19.067 38.538 19.615 ;
     RECT  72 19.273 75.51 19.651 ;
     RECT  71.784 19.651 75.51 19.741 ;
     RECT  39.42 19.421 47.862 19.885 ;
     RECT  48.852 18.995 58.158 19.885 ;
     RECT  69.516 19.345 70.434 19.921 ;
     RECT  71.604 19.741 75.51 19.921 ;
     RECT  69.516 19.921 75.51 20.047 ;
     RECT  4.968 19.337 21.33 20.155 ;
     RECT  22.248 19.615 38.538 20.155 ;
     RECT  39.42 19.885 58.158 20.155 ;
     RECT  4.716 20.155 21.33 20.191 ;
     RECT  22.248 20.155 58.158 20.191 ;
     RECT  67.215 14.747 67.497 20.191 ;
     RECT  69.192 20.047 75.51 20.191 ;
     RECT  68.256 20.191 75.51 20.237 ;
     RECT  4.716 20.191 58.158 20.281 ;
     RECT  66.78 20.191 67.497 20.281 ;
     RECT  68.256 20.237 73.89 20.309 ;
     RECT  66.096 20.281 67.497 20.551 ;
     RECT  61.815 15.989 62.097 20.587 ;
     RECT  4.464 20.281 58.158 20.669 ;
     RECT  59.616 18.149 59.634 20.683 ;
     RECT  63.18 20.551 63.198 20.695 ;
     RECT  65.664 20.551 67.497 20.695 ;
     RECT  49.392 20.669 58.158 20.731 ;
     RECT  61.815 20.587 62.334 20.731 ;
     RECT  63.18 20.695 63.342 20.731 ;
     RECT  61.815 20.731 63.342 20.821 ;
     RECT  61.815 20.821 63.594 20.893 ;
     RECT  65.448 20.695 67.497 20.893 ;
     RECT  3.708 20.821 3.726 20.965 ;
     RECT  4.464 20.669 48.546 20.965 ;
     RECT  61.815 20.893 63.882 20.965 ;
     RECT  65.412 20.893 67.497 20.965 ;
     RECT  64.656 20.965 67.497 21.001 ;
     RECT  68.256 20.309 69.606 21.001 ;
     RECT  61.416 20.965 63.882 21.067 ;
     RECT  64.656 21.001 69.606 21.067 ;
     RECT  3.708 20.965 48.546 21.101 ;
     RECT  59.292 20.683 59.634 21.115 ;
     RECT  59.292 21.115 60.354 21.127 ;
     RECT  49.392 20.731 58.194 21.199 ;
     RECT  61.416 21.067 69.606 21.199 ;
     RECT  70.38 20.309 73.89 21.199 ;
     RECT  61.416 21.199 73.89 21.259 ;
     RECT  2.415 15.728 2.697 21.271 ;
     RECT  61.092 21.259 73.89 21.271 ;
     RECT  74.664 20.237 75.51 21.271 ;
     RECT  59.184 21.127 60.354 21.293 ;
     RECT  49.392 21.199 58.374 21.505 ;
     RECT  59.184 21.293 59.634 21.505 ;
     RECT  2.415 21.271 2.862 21.541 ;
     RECT  3.708 21.101 37.314 21.541 ;
     RECT  49.392 21.505 59.634 21.631 ;
     RECT  61.092 21.271 75.51 21.703 ;
     RECT  38.124 21.101 48.546 21.739 ;
     RECT  49.356 21.631 59.634 21.739 ;
     RECT  60.48 21.703 75.51 21.869 ;
     RECT  38.124 21.739 59.634 21.965 ;
     RECT  0.18 21.973 0.198 22.009 ;
     RECT  0.18 22.009 0.234 22.045 ;
     RECT  2.415 21.541 37.314 22.045 ;
     RECT  38.124 21.965 47.862 22.045 ;
     RECT  2.415 22.045 47.862 22.199 ;
     RECT  74.628 21.869 75.51 22.207 ;
     RECT  2.415 22.199 13.497 22.411 ;
     RECT  48.636 21.965 59.634 22.441 ;
     RECT  14.22 22.199 47.862 22.469 ;
     RECT  2.304 22.411 13.497 22.549 ;
     RECT  48.636 22.441 59.742 22.549 ;
     RECT  60.48 21.869 73.89 22.549 ;
     RECT  2.232 22.549 13.497 22.637 ;
     RECT  48.636 22.549 73.89 22.783 ;
     RECT  74.628 22.207 75.582 22.783 ;
     RECT  14.328 22.469 47.862 22.855 ;
     RECT  48.636 22.783 75.582 22.855 ;
     RECT  14.328 22.855 75.582 22.883 ;
     RECT  18.252 22.883 75.582 23.153 ;
     RECT  2.304 22.637 13.497 23.161 ;
     RECT  0.108 22.045 0.234 23.179 ;
     RECT  0.108 23.179 0.342 23.309 ;
     RECT  2.304 23.161 13.59 23.431 ;
     RECT  14.328 22.883 17.19 23.431 ;
     RECT  18.252 23.153 73.89 23.665 ;
     RECT  2.304 23.431 17.19 23.701 ;
     RECT  18 23.665 73.89 23.701 ;
     RECT  2.304 23.701 73.89 23.755 ;
     RECT  0.144 23.309 0.162 23.885 ;
     RECT  2.268 23.755 73.89 24.173 ;
     RECT  2.268 24.173 73.818 24.359 ;
     RECT  74.664 23.153 75.582 24.365 ;
     RECT  2.268 24.359 15.282 24.395 ;
     RECT  16.2 24.359 73.818 24.503 ;
     RECT  2.268 24.395 11.646 24.665 ;
     RECT  12.564 24.395 15.282 24.665 ;
     RECT  14.508 24.665 15.282 24.809 ;
     RECT  16.236 24.503 73.818 24.809 ;
     RECT  2.268 24.665 11.466 24.845 ;
     RECT  2.304 24.845 11.466 24.899 ;
     RECT  12.564 24.665 13.77 24.899 ;
     RECT  14.508 24.809 14.886 24.899 ;
     RECT  9.648 24.899 11.466 24.935 ;
     RECT  12.564 24.899 13.662 24.935 ;
     RECT  18.432 24.809 73.818 24.935 ;
     RECT  16.236 24.809 17.334 24.971 ;
     RECT  18.432 24.935 21.114 25.007 ;
     RECT  75.24 24.365 75.582 25.037 ;
     RECT  21.888 24.935 73.818 25.043 ;
     RECT  20.88 25.007 21.114 25.079 ;
     RECT  2.304 24.899 8.91 25.085 ;
     RECT  10.404 24.935 11.466 25.181 ;
     RECT  22.212 25.043 73.818 25.195 ;
     RECT  10.404 25.181 10.422 25.229 ;
     RECT  0.144 25.099 0.162 25.277 ;
     RECT  18.432 25.007 19.926 25.277 ;
     RECT  12.564 24.935 13.497 25.321 ;
     RECT  16.236 24.971 17.226 25.321 ;
     RECT  22.212 25.195 74.106 25.349 ;
     RECT  12.312 25.321 13.497 25.373 ;
     RECT  11.376 25.181 11.466 25.439 ;
     RECT  18.615 25.277 19.926 25.439 ;
     RECT  14.508 24.899 14.706 25.469 ;
     RECT  22.212 25.349 73.818 25.475 ;
     RECT  11.448 25.439 11.466 25.583 ;
     RECT  22.32 25.475 73.818 25.745 ;
     RECT  75.348 25.037 75.582 25.771 ;
     RECT  0.324 25.675 0.342 25.805 ;
     RECT  21.096 25.079 21.114 25.825 ;
     RECT  2.304 25.085 8.874 25.861 ;
     RECT  9.648 24.935 9.666 25.861 ;
     RECT  12.996 25.373 13.497 25.861 ;
     RECT  15.624 25.321 17.226 25.861 ;
     RECT  21.096 25.825 21.294 25.861 ;
     RECT  15.192 25.861 17.226 25.987 ;
     RECT  75.312 25.771 75.582 26.051 ;
     RECT  75.42 26.051 75.582 26.087 ;
     RECT  12.996 25.861 14.058 26.095 ;
     RECT  20.772 25.861 21.33 26.095 ;
     RECT  15.192 25.987 17.694 26.131 ;
     RECT  22.644 25.745 73.818 26.285 ;
     RECT  12.96 26.095 14.058 26.329 ;
     RECT  15.192 26.131 17.838 26.329 ;
     RECT  74.556 25.963 74.574 26.347 ;
     RECT  2.268 25.861 9.666 26.365 ;
     RECT  2.268 26.365 9.774 26.401 ;
     RECT  10.836 26.251 10.854 26.401 ;
     RECT  12.132 26.251 12.15 26.401 ;
     RECT  12.96 26.329 17.838 26.401 ;
     RECT  18.615 25.439 19.53 26.401 ;
     RECT  12.132 26.401 19.53 26.519 ;
     RECT  22.644 26.285 24.786 26.527 ;
     RECT  20.448 26.095 21.33 26.555 ;
     RECT  74.556 26.347 74.646 26.635 ;
     RECT  20.556 26.555 21.33 26.671 ;
     RECT  22.14 26.527 24.786 26.671 ;
     RECT  20.556 26.671 24.786 26.789 ;
     RECT  25.74 26.285 73.134 26.789 ;
     RECT  18.252 26.519 19.53 26.797 ;
     RECT  74.088 26.635 74.646 26.827 ;
     RECT  75.42 26.087 75.51 26.827 ;
     RECT  74.088 26.827 75.51 26.861 ;
     RECT  12.132 26.519 17.298 26.869 ;
     RECT  74.088 26.861 75.438 26.909 ;
     RECT  2.268 26.401 10.854 27.019 ;
     RECT  2.232 27.019 10.854 27.067 ;
     RECT  11.952 26.869 17.298 27.067 ;
     RECT  18.252 26.797 19.674 27.139 ;
     RECT  2.232 27.067 17.298 27.167 ;
     RECT  22.284 26.789 24.786 27.211 ;
     RECT  74.088 26.909 75.33 27.245 ;
     RECT  2.304 27.167 17.298 27.307 ;
     RECT  25.884 26.789 73.134 27.365 ;
     RECT  74.088 27.245 74.646 27.403 ;
     RECT  18.252 27.139 19.818 27.445 ;
     RECT  20.556 26.789 21.474 27.445 ;
     RECT  2.304 27.307 17.478 27.481 ;
     RECT  18.252 27.445 21.474 27.481 ;
     RECT  2.304 27.481 21.474 27.571 ;
     RECT  22.284 27.211 25.038 27.571 ;
     RECT  2.304 27.571 25.038 27.671 ;
     RECT  71.208 27.365 73.134 27.691 ;
     RECT  74.016 27.403 74.646 27.691 ;
     RECT  14.94 27.671 25.038 27.751 ;
     RECT  25.884 27.365 70.362 27.751 ;
     RECT  14.94 27.751 70.362 27.869 ;
     RECT  2.304 27.671 14.202 27.905 ;
     RECT  71.208 27.691 74.646 28.013 ;
     RECT  18.612 27.869 70.362 28.139 ;
     RECT  22.392 28.139 30.258 28.175 ;
     RECT  31.068 28.139 70.362 28.183 ;
     RECT  71.208 28.013 73.17 28.183 ;
     RECT  31.068 28.183 73.17 28.253 ;
     RECT  31.14 28.253 73.17 28.283 ;
     RECT  75.492 28.363 75.51 28.381 ;
     RECT  2.34 27.905 14.202 28.507 ;
     RECT  14.94 27.869 17.874 28.507 ;
     RECT  2.34 28.507 17.874 28.651 ;
     RECT  18.612 28.139 21.546 28.651 ;
     RECT  73.98 28.013 74.646 28.747 ;
     RECT  75.42 28.381 75.51 28.747 ;
     RECT  22.392 28.175 30.222 28.921 ;
     RECT  73.98 28.747 75.51 28.949 ;
     RECT  2.34 28.651 21.546 29.065 ;
     RECT  22.392 28.921 30.402 29.065 ;
     RECT  2.34 29.065 30.474 29.083 ;
     RECT  31.248 28.283 73.17 29.083 ;
     RECT  2.34 29.083 73.17 29.131 ;
     RECT  73.98 28.949 74.106 29.131 ;
     RECT  2.34 29.131 74.106 29.633 ;
     RECT  74.052 29.633 74.106 29.759 ;
     RECT  74.124 29.899 74.142 30.101 ;
     RECT  75.312 28.949 75.51 30.283 ;
     RECT  75.276 30.283 75.51 30.415 ;
     RECT  75.276 30.415 75.582 30.605 ;
     RECT  75.348 30.605 75.582 30.653 ;
     RECT  2.34 29.633 73.17 30.685 ;
     RECT  2.304 30.685 73.17 30.749 ;
     RECT  2.415 30.749 73.17 30.839 ;
     RECT  25.416 30.839 73.17 30.919 ;
     RECT  25.416 30.919 73.566 31.085 ;
     RECT  75.492 30.653 75.582 31.435 ;
     RECT  25.416 31.085 73.494 31.765 ;
     RECT  75.456 31.435 75.582 31.771 ;
     RECT  2.415 30.839 24.606 32.071 ;
     RECT  25.344 31.765 73.494 32.071 ;
     RECT  74.628 31.999 74.646 32.099 ;
     RECT  75.42 31.771 75.582 32.107 ;
     RECT  2.415 32.071 73.494 32.155 ;
     RECT  2.34 32.155 73.494 32.203 ;
     RECT  2.34 32.203 74.178 32.261 ;
     RECT  75.312 32.107 75.582 32.333 ;
     RECT  74.124 32.261 74.178 32.875 ;
     RECT  74.124 32.875 74.61 33.115 ;
     RECT  75.42 32.333 75.582 33.115 ;
     RECT  74.124 33.115 75.582 33.293 ;
     RECT  75.456 33.293 75.582 33.539 ;
     RECT  2.34 32.261 73.062 33.739 ;
     RECT  74.124 33.293 74.682 33.739 ;
     RECT  2.34 33.739 74.682 33.965 ;
     RECT  2.34 33.965 74.646 34.115 ;
     RECT  75.456 33.539 75.51 34.259 ;
     RECT  23.868 34.115 74.646 34.349 ;
     RECT  23.868 34.349 27.414 34.655 ;
     RECT  75.456 34.259 75.474 34.795 ;
     RECT  2.34 34.115 23.022 34.925 ;
     RECT  23.868 34.655 24.822 34.969 ;
     RECT  28.152 34.349 74.646 34.987 ;
     RECT  75.42 34.795 75.474 34.987 ;
     RECT  25.704 34.655 27.414 35.275 ;
     RECT  28.152 34.987 75.474 35.275 ;
     RECT  25.704 35.275 75.474 35.309 ;
     RECT  2.415 34.925 23.022 35.323 ;
     RECT  23.796 34.969 24.822 35.323 ;
     RECT  75.42 35.309 75.474 35.467 ;
     RECT  2.415 35.323 24.822 35.545 ;
     RECT  2.415 35.545 24.966 35.581 ;
     RECT  25.704 35.309 74.646 35.581 ;
     RECT  75.42 35.467 75.51 36.113 ;
     RECT  2.415 35.581 74.646 36.121 ;
     RECT  75.42 36.113 75.438 36.121 ;
     RECT  2.376 36.121 75.438 36.365 ;
     RECT  2.376 36.365 74.646 36.461 ;
     RECT  2.376 36.461 74.106 37.201 ;
     RECT  2.376 37.201 74.682 37.387 ;
     RECT  2.304 37.387 74.682 37.483 ;
     RECT  75.42 36.365 75.438 37.483 ;
     RECT  2.304 37.483 75.438 37.579 ;
     RECT  2.304 37.579 75.474 37.597 ;
     RECT  2.232 37.597 75.474 37.697 ;
     RECT  0.108 36.085 0.126 37.997 ;
     RECT  2.304 37.697 75.474 38.129 ;
     RECT  74.124 38.129 75.474 38.201 ;
     RECT  0.144 38.107 0.162 38.285 ;
     RECT  2.304 38.129 73.386 38.827 ;
     RECT  2.268 38.827 73.386 38.923 ;
     RECT  74.628 38.201 75.474 39.083 ;
     RECT  75.456 39.083 75.474 39.211 ;
     RECT  2.232 38.923 73.386 39.281 ;
     RECT  75.456 39.211 75.51 39.389 ;
     RECT  74.628 39.083 74.718 39.499 ;
     RECT  74.124 39.499 74.718 39.581 ;
     RECT  2.268 39.281 36.918 39.623 ;
     RECT  37.8 39.281 73.386 39.821 ;
     RECT  37.8 39.821 58.806 39.893 ;
     RECT  0.54 38.821 0.558 39.917 ;
     RECT  75.492 39.389 75.51 39.929 ;
     RECT  60.048 39.821 73.386 39.979 ;
     RECT  74.124 39.581 74.646 39.979 ;
     RECT  2.304 39.623 36.918 40.055 ;
     RECT  37.8 39.893 58.662 40.091 ;
     RECT  25.884 40.055 36.918 40.219 ;
     RECT  25.884 40.219 37.062 40.441 ;
     RECT  37.8 40.091 58.554 40.441 ;
     RECT  60.048 39.979 74.646 40.459 ;
     RECT  60.048 40.459 75.33 40.651 ;
     RECT  2.304 40.055 25.074 40.873 ;
     RECT  25.884 40.441 58.554 40.873 ;
     RECT  0.108 40.135 0.126 40.877 ;
     RECT  2.304 40.873 58.554 40.981 ;
     RECT  2.304 40.981 58.698 41.107 ;
     RECT  2.304 41.107 58.734 41.207 ;
     RECT  60.048 40.651 75.51 41.251 ;
     RECT  60.012 41.251 75.51 41.513 ;
     RECT  0.144 41.371 0.162 41.549 ;
     RECT  0.324 41.803 0.342 41.933 ;
     RECT  2.304 41.207 58.554 42.025 ;
     RECT  2.268 42.025 58.554 42.475 ;
     RECT  60.048 41.513 75.51 42.485 ;
     RECT  70.308 42.485 75.51 42.593 ;
     RECT  1.728 42.475 58.554 42.719 ;
     RECT  60.048 42.485 69.57 42.863 ;
     RECT  70.308 42.593 75.438 43.025 ;
     RECT  21.456 42.719 58.554 43.231 ;
     RECT  21.456 43.231 58.878 43.259 ;
     RECT  70.38 43.025 75.438 43.259 ;
     RECT  0.144 42.523 0.162 43.325 ;
     RECT  70.38 43.259 70.542 43.331 ;
     RECT  71.388 43.259 75.438 43.439 ;
     RECT  1.728 42.719 20.61 43.501 ;
     RECT  21.456 43.259 43.47 43.501 ;
     RECT  64.944 42.863 69.57 43.529 ;
     RECT  70.38 43.331 70.398 43.529 ;
     RECT  71.388 43.439 75.402 43.529 ;
     RECT  44.208 43.259 58.878 43.537 ;
     RECT  60.048 42.863 64.134 43.537 ;
     RECT  74.376 43.529 75.402 43.637 ;
     RECT  1.728 43.501 43.47 43.709 ;
     RECT  74.376 43.637 74.394 43.709 ;
     RECT  71.856 43.529 73.422 43.835 ;
     RECT  1.764 43.709 43.47 43.979 ;
     RECT  72.18 43.835 73.422 44.069 ;
     RECT  2.304 43.979 43.47 44.221 ;
     RECT  44.208 43.537 64.134 44.221 ;
     RECT  75.384 43.637 75.402 44.249 ;
     RECT  2.304 44.221 64.134 44.581 ;
     RECT  64.944 43.529 69.39 44.581 ;
     RECT  72.18 44.069 73.314 44.617 ;
     RECT  72.144 44.617 73.314 44.725 ;
     RECT  74.088 44.419 74.142 44.761 ;
     RECT  2.304 44.581 69.39 44.765 ;
     RECT  72.072 44.725 73.314 44.851 ;
     RECT  72.036 44.851 73.314 45.121 ;
     RECT  2.34 44.765 69.39 45.149 ;
     RECT  70.812 44.851 70.83 45.157 ;
     RECT  71.64 45.121 73.314 45.157 ;
     RECT  2.34 45.149 25.686 45.329 ;
     RECT  70.812 45.157 73.314 45.451 ;
     RECT  74.088 44.761 74.826 45.451 ;
     RECT  70.812 45.451 74.826 45.677 ;
     RECT  70.812 45.677 73.53 45.769 ;
     RECT  26.46 45.149 69.39 45.841 ;
     RECT  26.46 45.841 69.462 45.931 ;
     RECT  70.704 45.769 73.53 46.003 ;
     RECT  2.34 45.329 25.506 46.075 ;
     RECT  26.46 45.931 69.57 46.111 ;
     RECT  26.388 46.111 69.57 46.229 ;
     RECT  53.64 46.229 69.57 46.309 ;
     RECT  70.596 46.003 73.53 46.309 ;
     RECT  2.304 46.075 25.506 46.381 ;
     RECT  26.388 46.229 52.902 46.381 ;
     RECT  0.54 45.805 0.558 46.507 ;
     RECT  0.54 46.507 0.666 46.603 ;
     RECT  0.54 46.603 0.774 46.696 ;
     RECT  74.628 45.677 74.826 46.699 ;
     RECT  0.324 46.696 0.774 46.724 ;
     RECT  74.628 46.699 75.51 46.829 ;
     RECT  0.324 46.724 0.342 46.973 ;
     RECT  53.64 46.309 73.53 47.083 ;
     RECT  2.304 46.381 52.902 47.191 ;
     RECT  53.64 47.083 73.818 47.191 ;
     RECT  2.304 47.191 73.818 47.389 ;
     RECT  74.628 46.829 74.646 47.389 ;
     RECT  2.304 47.389 74.646 47.615 ;
     RECT  75.456 46.829 75.51 47.659 ;
     RECT  0.144 47.419 0.162 47.693 ;
     RECT  70.38 47.615 74.646 47.789 ;
     RECT  2.304 47.615 69.534 47.849 ;
     RECT  2.304 47.849 69.39 47.885 ;
     RECT  70.38 47.789 73.818 47.891 ;
     RECT  75.42 47.659 75.51 48.028 ;
     RECT  2.304 47.885 69.318 48.119 ;
     RECT  2.304 48.119 49.698 48.425 ;
     RECT  70.38 47.891 70.506 48.425 ;
     RECT  0.216 48.139 0.342 48.461 ;
     RECT  2.304 48.425 21.618 48.461 ;
     RECT  2.304 48.461 21.438 48.497 ;
     RECT  50.58 48.119 69.318 48.659 ;
     RECT  70.488 48.425 70.506 48.659 ;
     RECT  71.28 47.891 73.818 48.703 ;
     RECT  22.5 48.425 49.698 48.839 ;
     RECT  47.124 48.839 49.698 48.901 ;
     RECT  50.58 48.659 68.634 48.901 ;
     RECT  22.5 48.839 46.386 48.929 ;
     RECT  70.596 48.703 73.818 48.929 ;
     RECT  74.628 47.789 74.646 48.929 ;
     RECT  0.144 48.811 0.162 48.989 ;
     RECT  22.5 48.929 46.35 49.001 ;
     RECT  2.304 48.497 21.366 49.099 ;
     RECT  75.384 48.028 75.51 49.109 ;
     RECT  22.5 49.001 37.026 49.171 ;
     RECT  70.704 48.929 73.818 49.199 ;
     RECT  70.704 49.199 71.298 49.235 ;
     RECT  2.268 49.099 21.366 49.279 ;
     RECT  22.248 49.171 37.026 49.279 ;
     RECT  2.268 49.279 37.026 49.343 ;
     RECT  70.704 49.235 71.262 49.469 ;
     RECT  71.244 49.469 71.262 49.541 ;
     RECT  69.552 48.775 69.57 49.739 ;
     RECT  75.456 49.109 75.51 49.739 ;
     RECT  72.108 49.199 73.818 49.775 ;
     RECT  0.324 49.675 0.342 49.819 ;
     RECT  2.304 49.343 37.026 49.855 ;
     RECT  37.8 49.001 46.35 49.855 ;
     RECT  47.124 48.901 68.634 49.855 ;
     RECT  73.8 49.775 73.818 49.919 ;
     RECT  0.144 49.819 0.342 49.963 ;
     RECT  72.36 49.775 72.897 50.045 ;
     RECT  0.108 49.963 0.342 50.093 ;
     RECT  0.108 50.093 0.162 50.333 ;
     RECT  2.304 49.855 68.634 50.585 ;
     RECT  2.304 50.585 52.542 50.621 ;
     RECT  72.432 50.045 72.897 50.665 ;
     RECT  74.124 50.431 74.142 50.701 ;
     RECT  72.432 50.665 73.17 50.935 ;
     RECT  72.432 50.935 73.242 50.971 ;
     RECT  75.492 49.739 75.51 50.971 ;
     RECT  0.108 50.333 0.126 51.053 ;
     RECT  71.892 50.971 73.242 51.097 ;
     RECT  2.304 50.621 52.218 51.125 ;
     RECT  71.46 51.097 73.242 51.241 ;
     RECT  53.316 50.585 68.634 51.331 ;
     RECT  37.692 51.125 52.218 51.475 ;
     RECT  53.172 51.331 68.634 51.475 ;
     RECT  71.46 51.241 73.314 51.533 ;
     RECT  37.692 51.475 68.634 51.601 ;
     RECT  2.304 51.125 36.774 51.665 ;
     RECT  2.304 51.665 36.126 51.701 ;
     RECT  74.124 50.701 74.178 51.709 ;
     RECT  71.46 51.533 73.242 51.745 ;
     RECT  26.604 51.701 36.126 51.899 ;
     RECT  37.692 51.601 68.994 51.943 ;
     RECT  71.352 51.745 73.242 52.015 ;
     RECT  37.008 51.943 68.994 52.051 ;
     RECT  69.912 51.781 69.93 52.051 ;
     RECT  74.124 51.709 74.682 52.051 ;
     RECT  75.42 50.971 75.51 52.051 ;
     RECT  70.92 52.015 73.242 52.177 ;
     RECT  74.124 52.051 75.51 52.205 ;
     RECT  75.492 52.205 75.51 52.349 ;
     RECT  70.812 52.177 73.242 52.411 ;
     RECT  26.748 51.899 36.126 52.447 ;
     RECT  37.008 52.051 69.93 52.483 ;
     RECT  74.124 52.205 74.718 52.493 ;
     RECT  36.972 52.483 69.93 52.519 ;
     RECT  70.74 52.411 73.242 52.519 ;
     RECT  0.324 52.459 0.342 52.555 ;
     RECT  26.748 52.447 36.234 52.591 ;
     RECT  36.972 52.519 73.242 52.591 ;
     RECT  0.252 52.555 0.342 52.636 ;
     RECT  0.18 52.636 0.342 52.637 ;
     RECT  26.748 52.591 73.242 52.681 ;
     RECT  0.18 52.637 0.27 52.733 ;
     RECT  2.304 51.701 25.686 52.789 ;
     RECT  26.496 52.681 73.242 52.789 ;
     RECT  0.18 52.733 0.198 52.829 ;
     RECT  2.304 52.789 73.242 52.939 ;
     RECT  2.268 52.939 73.242 52.979 ;
     RECT  28.44 52.979 73.242 53.015 ;
     RECT  74.124 52.493 74.682 53.035 ;
     RECT  74.088 53.035 74.682 53.227 ;
     RECT  28.44 53.015 47.07 53.249 ;
     RECT  0.144 53.131 0.162 53.309 ;
     RECT  1.26 53.227 1.278 53.323 ;
     RECT  1.152 53.323 1.278 53.357 ;
     RECT  2.268 52.979 27.63 53.419 ;
     RECT  47.844 53.015 73.242 53.419 ;
     RECT  74.052 53.227 74.682 53.419 ;
     RECT  41.76 53.249 47.07 53.519 ;
     RECT  47.844 53.419 74.682 53.519 ;
     RECT  2.232 53.419 27.63 53.627 ;
     RECT  28.44 53.249 41.022 53.797 ;
     RECT  41.796 53.519 47.07 53.797 ;
     RECT  47.844 53.519 49.77 53.797 ;
     RECT  75.492 53.131 75.51 53.833 ;
     RECT  0.18 53.851 0.198 53.995 ;
     RECT  1.152 53.357 1.17 54.029 ;
     RECT  41.796 53.797 49.77 54.095 ;
     RECT  50.652 53.519 74.682 54.131 ;
     RECT  50.652 54.131 69.246 54.173 ;
     RECT  2.304 53.627 27.63 54.175 ;
     RECT  28.368 53.797 41.022 54.175 ;
     RECT  2.304 54.175 41.022 54.239 ;
     RECT  0.18 53.995 0.342 54.331 ;
     RECT  0.144 54.331 0.342 54.475 ;
     RECT  2.304 54.239 33.714 54.481 ;
     RECT  34.452 54.239 41.022 54.481 ;
     RECT  0.144 54.475 0.45 54.653 ;
     RECT  41.904 54.095 49.77 54.671 ;
     RECT  0.144 54.653 0.378 54.701 ;
     RECT  50.652 54.173 58.77 54.751 ;
     RECT  70.056 54.131 74.682 54.977 ;
     RECT  2.232 54.481 33.714 54.985 ;
     RECT  34.452 54.481 41.13 54.985 ;
     RECT  50.58 54.751 58.77 54.985 ;
     RECT  59.508 54.173 69.246 54.985 ;
     RECT  2.232 54.985 41.13 55.021 ;
     RECT  41.904 54.671 46.566 55.021 ;
     RECT  47.52 54.671 49.77 55.021 ;
     RECT  50.58 54.985 69.246 55.021 ;
     RECT  70.056 54.977 74.07 55.139 ;
     RECT  2.232 55.021 46.566 55.175 ;
     RECT  47.52 55.021 69.246 55.175 ;
     RECT  47.52 55.175 68.346 55.247 ;
     RECT  70.056 55.139 73.998 55.247 ;
     RECT  73.98 55.247 73.998 55.409 ;
     RECT  42.264 55.175 46.566 55.417 ;
     RECT  47.52 55.247 68.13 55.417 ;
     RECT  2.232 55.175 41.346 55.445 ;
     RECT  2.232 55.445 23.238 55.517 ;
     RECT  70.056 55.247 73.242 55.517 ;
     RECT  2.232 55.517 22.878 55.565 ;
     RECT  70.056 55.517 70.146 55.679 ;
     RECT  0.108 55.627 0.126 55.757 ;
     RECT  70.956 55.517 73.242 56.021 ;
     RECT  24.015 55.445 41.346 56.029 ;
     RECT  42.264 55.417 68.13 56.029 ;
     RECT  70.956 56.021 73.134 56.219 ;
     RECT  70.056 55.679 70.074 56.227 ;
     RECT  2.304 55.565 22.878 56.251 ;
     RECT  2.304 56.251 23.202 56.525 ;
     RECT  24.015 56.029 68.13 56.525 ;
     RECT  70.02 56.227 70.074 56.641 ;
     RECT  70.956 56.219 71.766 56.641 ;
     RECT  2.304 56.525 21.834 56.683 ;
     RECT  75.492 53.833 75.582 56.759 ;
     RECT  22.572 56.525 23.202 56.767 ;
     RECT  24.015 56.525 52.218 56.767 ;
     RECT  72.615 56.219 73.134 56.795 ;
     RECT  2.268 56.683 21.834 56.867 ;
     RECT  75.492 56.759 75.51 56.939 ;
     RECT  0.108 56.605 0.126 57.101 ;
     RECT  22.572 56.767 52.218 57.271 ;
     RECT  52.956 56.525 68.13 57.271 ;
     RECT  70.02 56.641 71.766 57.271 ;
     RECT  72.615 56.795 72.897 57.271 ;
     RECT  2.304 56.867 21.834 57.299 ;
     RECT  69.228 55.175 69.246 57.577 ;
     RECT  22.572 57.271 68.13 57.605 ;
     RECT  0.144 57.64 0.162 57.649 ;
     RECT  0.144 57.649 0.342 57.739 ;
     RECT  22.572 57.605 67.842 57.811 ;
     RECT  70.02 57.271 72.897 57.847 ;
     RECT  2.304 57.299 21.762 57.883 ;
     RECT  0.144 57.739 0.378 57.965 ;
     RECT  0.144 57.965 0.306 58.061 ;
     RECT  22.5 57.811 67.842 58.109 ;
     RECT  2.232 57.883 21.762 58.145 ;
     RECT  58.932 58.109 67.842 58.145 ;
     RECT  2.304 58.145 21.762 58.153 ;
     RECT  22.5 58.109 58.194 58.153 ;
     RECT  0.288 58.061 0.306 58.253 ;
     RECT  2.304 58.153 58.194 58.649 ;
     RECT  58.968 58.145 67.842 58.729 ;
     RECT  58.968 58.729 67.986 58.891 ;
     RECT  41.832 58.649 58.194 58.919 ;
     RECT  58.932 58.891 67.986 58.919 ;
     RECT  41.868 58.919 58.194 58.987 ;
     RECT  58.932 58.919 61.002 58.987 ;
     RECT  61.776 58.919 67.986 59.063 ;
     RECT  41.868 58.987 61.002 59.189 ;
     RECT  2.304 58.649 41.094 59.225 ;
     RECT  41.868 59.189 60.93 59.225 ;
     RECT  61.812 59.063 67.986 59.309 ;
     RECT  41.868 59.225 59.886 59.333 ;
     RECT  39.6 59.225 41.094 59.369 ;
     RECT  0.324 59.371 0.342 59.467 ;
     RECT  39.636 59.369 41.094 59.495 ;
     RECT  0.108 59.467 0.342 59.501 ;
     RECT  0.108 59.501 0.126 59.597 ;
     RECT  39.672 59.495 41.094 59.729 ;
     RECT  2.304 59.225 38.862 59.999 ;
     RECT  2.304 59.999 21.798 60.071 ;
     RECT  41.868 59.333 59.778 60.079 ;
     RECT  60.624 59.225 60.93 60.079 ;
     RECT  22.536 59.999 38.862 60.269 ;
     RECT  41.868 60.079 60.93 60.277 ;
     RECT  39.672 59.729 41.058 60.305 ;
     RECT  41.796 60.277 60.93 60.385 ;
     RECT  39.672 60.305 40.497 60.539 ;
     RECT  2.304 60.071 21.294 60.575 ;
     RECT  61.815 59.309 67.986 60.575 ;
     RECT  41.796 60.385 61.038 60.619 ;
     RECT  2.376 60.575 21.294 60.817 ;
     RECT  22.536 60.269 38.646 60.817 ;
     RECT  39.78 60.539 40.497 60.845 ;
     RECT  69.228 57.577 69.282 60.845 ;
     RECT  41.796 60.619 61.074 60.925 ;
     RECT  61.815 60.575 63.99 60.925 ;
     RECT  2.376 60.817 38.646 61.079 ;
     RECT  2.415 61.079 38.646 61.115 ;
     RECT  2.415 61.115 38.538 61.187 ;
     RECT  2.415 61.187 38.466 61.259 ;
     RECT  64.728 60.575 67.986 61.501 ;
     RECT  41.796 60.925 63.99 61.619 ;
     RECT  64.728 61.501 68.238 61.735 ;
     RECT  70.02 57.847 73.026 61.735 ;
     RECT  74.628 61.501 74.646 61.771 ;
     RECT  40.215 60.845 40.497 61.867 ;
     RECT  41.796 61.619 43.758 61.889 ;
     RECT  41.796 61.889 43.542 62.005 ;
     RECT  70.02 61.735 73.134 62.005 ;
     RECT  39.996 61.867 40.497 62.041 ;
     RECT  41.328 62.005 43.542 62.041 ;
     RECT  44.676 61.619 63.99 62.041 ;
     RECT  64.728 61.735 68.454 62.041 ;
     RECT  74.628 61.771 74.682 62.041 ;
     RECT  44.676 62.041 68.454 62.069 ;
     RECT  39.996 62.041 43.542 62.155 ;
     RECT  69.228 60.845 69.246 62.195 ;
     RECT  2.415 61.259 37.566 62.275 ;
     RECT  38.448 61.259 38.466 62.275 ;
     RECT  44.712 62.069 68.454 62.311 ;
     RECT  2.415 62.275 38.466 62.401 ;
     RECT  44.712 62.311 68.49 62.437 ;
     RECT  44.712 62.437 68.634 62.465 ;
     RECT  74.124 62.041 74.682 62.477 ;
     RECT  74.124 62.477 74.61 62.573 ;
     RECT  2.415 62.401 38.79 62.581 ;
     RECT  74.592 62.573 74.61 62.669 ;
     RECT  70.02 62.005 73.314 62.671 ;
     RECT  2.415 62.581 38.934 62.699 ;
     RECT  39.852 62.155 43.542 62.699 ;
     RECT  64.764 62.465 68.634 62.699 ;
     RECT  39.852 62.699 40.95 62.851 ;
     RECT  41.688 62.699 43.542 62.851 ;
     RECT  41.688 62.851 43.614 62.941 ;
     RECT  44.712 62.465 63.99 62.941 ;
     RECT  2.415 62.699 38.826 62.969 ;
     RECT  39.78 62.851 40.95 62.969 ;
     RECT  41.688 62.941 63.99 62.969 ;
     RECT  41.688 62.969 63.774 63.005 ;
     RECT  69.516 62.671 73.314 63.013 ;
     RECT  75.492 63.019 75.51 63.077 ;
     RECT  41.688 63.005 62.874 63.149 ;
     RECT  41.688 63.149 57.978 63.239 ;
     RECT  58.716 63.149 62.874 63.239 ;
     RECT  2.415 62.969 37.71 63.311 ;
     RECT  69.516 63.013 73.566 63.389 ;
     RECT  42.084 63.239 57.978 63.419 ;
     RECT  69.804 63.389 73.566 63.437 ;
     RECT  74.628 63.211 74.646 63.499 ;
     RECT  65.016 62.699 68.634 63.553 ;
     RECT  69.804 63.437 73.026 63.581 ;
     RECT  38.736 62.969 38.826 63.661 ;
     RECT  39.78 62.969 40.914 63.661 ;
     RECT  37.512 63.311 37.71 63.739 ;
     RECT  59.004 63.239 62.874 63.779 ;
     RECT  74.088 63.499 74.646 63.815 ;
     RECT  59.004 63.779 59.238 63.821 ;
     RECT  42.192 63.419 57.978 63.887 ;
     RECT  65.016 63.553 69.066 63.923 ;
     RECT  37.512 63.739 37.782 63.931 ;
     RECT  38.736 63.661 40.914 63.931 ;
     RECT  52.74 63.887 57.978 63.931 ;
     RECT  65.016 63.923 68.886 63.959 ;
     RECT  37.512 63.931 37.962 64.049 ;
     RECT  52.74 63.931 58.266 64.049 ;
     RECT  65.016 63.959 68.814 64.049 ;
     RECT  59.004 63.821 59.202 64.085 ;
     RECT  60.192 63.779 62.097 64.085 ;
     RECT  74.088 63.815 74.106 64.085 ;
     RECT  69.912 63.581 73.026 64.121 ;
     RECT  2.415 63.311 36.702 64.157 ;
     RECT  65.016 64.049 65.214 64.193 ;
     RECT  69.948 64.121 73.026 64.291 ;
     RECT  59.112 64.085 59.202 64.319 ;
     RECT  59.112 64.319 59.13 64.355 ;
     RECT  60.192 64.085 60.858 64.355 ;
     RECT  20.556 64.157 36.702 64.391 ;
     RECT  65.988 64.049 68.814 64.427 ;
     RECT  69.948 64.291 73.134 64.435 ;
     RECT  2.415 64.157 19.53 64.463 ;
     RECT  23.724 64.391 36.702 64.471 ;
     RECT  37.512 64.049 37.89 64.471 ;
     RECT  38.7 63.931 41.058 64.471 ;
     RECT  69.948 64.435 73.206 64.471 ;
     RECT  65.988 64.427 67.734 64.499 ;
     RECT  52.74 64.049 58.158 64.589 ;
     RECT  2.415 64.463 17.082 64.625 ;
     RECT  38.7 64.471 41.418 64.633 ;
     RECT  42.192 63.887 52.002 64.633 ;
     RECT  52.74 64.589 55.602 64.633 ;
     RECT  38.7 64.633 55.602 64.741 ;
     RECT  60.84 64.355 60.858 64.769 ;
     RECT  68.796 64.427 68.814 64.769 ;
     RECT  69.948 64.471 73.314 64.859 ;
     RECT  69.948 64.859 73.134 64.931 ;
     RECT  69.948 64.931 70.182 64.967 ;
     RECT  71.208 64.931 73.134 64.973 ;
     RECT  23.724 64.471 37.89 64.975 ;
     RECT  38.664 64.741 55.602 64.975 ;
     RECT  65.988 64.499 67.497 65.003 ;
     RECT  66.708 65.003 67.497 65.129 ;
     RECT  23.724 64.975 55.602 65.165 ;
     RECT  72.18 64.973 73.134 65.165 ;
     RECT  18.216 64.463 19.53 65.173 ;
     RECT  20.556 64.391 22.806 65.173 ;
     RECT  23.724 65.165 37.458 65.173 ;
     RECT  65.196 64.193 65.214 65.201 ;
     RECT  71.208 64.973 71.406 65.201 ;
     RECT  72.18 65.165 72.897 65.201 ;
     RECT  23.58 65.173 37.458 65.237 ;
     RECT  20.448 65.173 22.806 65.245 ;
     RECT  23.58 65.237 36.054 65.245 ;
     RECT  18.216 65.173 19.566 65.281 ;
     RECT  20.448 65.245 36.054 65.281 ;
     RECT  36.792 65.237 37.458 65.309 ;
     RECT  71.208 65.201 71.226 65.309 ;
     RECT  72.396 65.201 72.897 65.309 ;
     RECT  2.415 64.625 16.974 65.515 ;
     RECT  18.216 65.281 36.054 65.669 ;
     RECT  38.232 65.165 55.602 65.705 ;
     RECT  2.415 65.515 17.01 65.749 ;
     RECT  2.415 65.749 17.082 65.821 ;
     RECT  37.368 65.309 37.458 66.055 ;
     RECT  38.232 65.705 38.43 66.055 ;
     RECT  2.415 65.821 17.694 66.083 ;
     RECT  18.615 65.669 36.054 66.091 ;
     RECT  18.615 66.091 36.27 66.139 ;
     RECT  37.368 66.055 38.43 66.139 ;
     RECT  3.42 66.083 17.694 66.245 ;
     RECT  3.42 66.245 17.55 66.479 ;
     RECT  39.168 65.705 55.602 66.479 ;
     RECT  18.615 66.139 38.43 66.523 ;
     RECT  39.168 66.479 54.81 66.523 ;
     RECT  18.615 66.523 54.81 66.631 ;
     RECT  18.36 66.631 54.81 66.785 ;
     RECT  2.415 66.083 2.697 66.865 ;
     RECT  3.42 66.479 17.406 66.865 ;
     RECT  18.36 66.785 37.458 66.929 ;
     RECT  19.728 66.929 37.458 67.019 ;
     RECT  19.728 67.019 37.314 67.181 ;
     RECT  38.268 66.785 54.81 67.325 ;
     RECT  18.36 66.929 18.897 67.333 ;
     RECT  2.415 66.865 17.406 67.397 ;
     RECT  19.728 67.181 36.81 67.397 ;
     RECT  16.272 67.397 17.406 67.441 ;
     RECT  18.324 67.333 18.897 67.441 ;
     RECT  38.268 67.325 53.37 67.675 ;
     RECT  38.052 67.675 53.37 67.709 ;
     RECT  18.288 67.441 18.897 67.711 ;
     RECT  18.252 67.711 18.897 67.801 ;
     RECT  16.272 67.441 17.478 67.829 ;
     RECT  19.836 67.397 36.81 67.829 ;
     RECT  38.052 67.709 53.01 67.909 ;
     RECT  16.272 67.829 17.37 67.973 ;
     RECT  37.728 67.909 53.01 67.981 ;
     RECT  16.488 67.973 17.37 68.099 ;
     RECT  16.488 68.099 17.334 68.207 ;
     RECT  2.415 67.397 15.534 68.243 ;
     RECT  57.456 64.589 57.474 68.279 ;
     RECT  18.216 67.801 18.897 68.341 ;
     RECT  19.836 67.829 36.666 68.341 ;
     RECT  37.62 67.981 53.01 68.369 ;
     RECT  6.264 68.243 15.534 68.405 ;
     RECT  37.62 68.369 38.322 68.405 ;
     RECT  18.216 68.341 36.666 68.441 ;
     RECT  2.415 68.243 5.382 68.513 ;
     RECT  7.2 68.405 15.534 68.521 ;
     RECT  6.264 68.405 6.462 68.639 ;
     RECT  26.064 68.441 36.666 68.647 ;
     RECT  6.264 68.639 6.318 68.675 ;
     RECT  54.504 67.325 54.81 68.783 ;
     RECT  7.2 68.521 15.75 68.791 ;
     RECT  18.216 68.441 25.218 68.881 ;
     RECT  7.2 68.791 16.254 68.909 ;
     RECT  7.488 68.909 16.254 68.953 ;
     RECT  17.064 68.207 17.334 68.953 ;
     RECT  7.488 68.953 17.334 68.981 ;
     RECT  11.916 68.981 17.334 69.025 ;
     RECT  18.18 68.881 25.218 69.025 ;
     RECT  3.42 68.513 5.382 69.053 ;
     RECT  4.068 69.053 5.382 69.061 ;
     RECT  6.264 68.675 6.282 69.061 ;
     RECT  26.064 68.647 37.206 69.089 ;
     RECT  6.228 69.061 6.282 69.179 ;
     RECT  38.052 68.405 38.322 69.211 ;
     RECT  39.06 68.369 53.01 69.211 ;
     RECT  26.064 69.089 37.17 69.215 ;
     RECT  11.916 69.025 25.218 69.259 ;
     RECT  26.064 69.215 31.338 69.259 ;
     RECT  4.068 69.061 5.49 69.287 ;
     RECT  38.052 69.211 53.01 69.295 ;
     RECT  4.068 69.287 4.266 69.323 ;
     RECT  11.916 69.259 31.338 69.323 ;
     RECT  5.148 69.287 5.49 69.359 ;
     RECT  55.584 66.479 55.602 69.359 ;
     RECT  5.328 69.359 5.49 69.449 ;
     RECT  6.264 69.179 6.282 69.449 ;
     RECT  7.488 68.981 10.998 69.449 ;
     RECT  37.98 69.295 53.01 69.449 ;
     RECT  5.328 69.449 5.346 69.485 ;
     RECT  20.592 69.323 31.338 69.485 ;
     RECT  7.56 69.449 10.998 69.521 ;
     RECT  11.916 69.323 19.422 69.521 ;
     RECT  39.312 69.449 53.01 69.629 ;
     RECT  32.112 69.215 37.17 69.719 ;
     RECT  20.7 69.485 31.338 69.755 ;
     RECT  7.815 69.521 10.998 69.835 ;
     RECT  11.916 69.521 13.734 69.835 ;
     RECT  32.112 69.719 36.774 69.863 ;
     RECT  20.88 69.755 31.338 69.961 ;
     RECT  32.112 69.863 36.522 69.961 ;
     RECT  7.815 69.835 13.734 69.989 ;
     RECT  20.88 69.961 36.522 69.989 ;
     RECT  39.42 69.629 53.01 69.989 ;
     RECT  39.42 69.989 52.794 70.259 ;
     RECT  7.815 69.989 13.698 70.367 ;
     RECT  7.815 70.367 11.97 70.403 ;
     RECT  37.98 69.449 38.466 70.411 ;
     RECT  39.42 70.259 52.65 70.411 ;
     RECT  14.544 69.521 19.422 70.529 ;
     RECT  20.88 69.989 22.842 70.529 ;
     RECT  37.872 70.411 52.65 70.529 ;
     RECT  7.815 70.403 10.53 70.565 ;
     RECT  37.872 70.529 51.93 70.565 ;
     RECT  14.544 70.529 19.314 70.637 ;
     RECT  23.616 69.989 36.522 70.645 ;
     RECT  37.872 70.565 38.394 70.645 ;
     RECT  20.916 70.529 22.842 70.673 ;
     RECT  14.544 70.637 19.062 70.799 ;
     RECT  21.024 70.673 22.842 70.799 ;
     RECT  23.616 70.645 38.394 70.799 ;
     RECT  39.132 70.565 51.93 70.907 ;
     RECT  21.528 70.799 22.842 70.915 ;
     RECT  23.616 70.799 38.322 70.915 ;
     RECT  9.144 70.565 10.53 70.979 ;
     RECT  12.852 70.367 13.698 71.069 ;
     RECT  14.544 70.799 18.99 71.069 ;
     RECT  21.528 70.915 38.322 71.105 ;
     RECT  12.924 71.069 13.698 71.117 ;
     RECT  39.132 70.907 51.858 71.141 ;
     RECT  9.468 70.979 10.53 71.177 ;
     RECT  14.76 71.069 18.99 71.213 ;
     RECT  11.448 70.403 11.97 71.221 ;
     RECT  9.756 71.177 10.53 71.249 ;
     RECT  22.212 71.105 22.842 71.249 ;
     RECT  11.412 71.221 12.078 71.339 ;
     RECT  17.892 71.213 18.99 71.339 ;
     RECT  39.132 71.141 49.338 71.339 ;
     RECT  62.856 63.779 62.874 71.339 ;
     RECT  9.756 71.249 10.242 71.375 ;
     RECT  23.688 71.105 38.322 71.375 ;
     RECT  49.32 71.339 49.338 71.375 ;
     RECT  22.824 71.249 22.842 71.411 ;
     RECT  13.068 71.117 13.698 71.491 ;
     RECT  23.688 71.375 33.642 71.519 ;
     RECT  9.864 71.375 10.242 71.609 ;
     RECT  18.18 71.339 18.897 71.609 ;
     RECT  39.132 71.339 48.51 71.609 ;
     RECT  34.488 71.375 38.322 71.681 ;
     RECT  9.864 71.609 10.206 71.753 ;
     RECT  11.412 71.339 12.006 71.761 ;
     RECT  23.976 71.519 33.642 71.789 ;
     RECT  36.756 71.681 38.322 71.789 ;
     RECT  9.864 71.753 10.026 71.879 ;
     RECT  14.76 71.213 16.974 71.879 ;
     RECT  23.976 71.789 27.666 71.879 ;
     RECT  28.476 71.789 33.642 71.879 ;
     RECT  50.292 71.141 51.858 71.879 ;
     RECT  9.864 71.879 9.882 71.915 ;
     RECT  14.76 71.879 16.866 71.915 ;
     RECT  37.548 71.789 38.322 71.915 ;
     RECT  14.76 71.915 15.57 71.951 ;
     RECT  50.292 71.879 51.297 71.951 ;
     RECT  23.976 71.879 27.594 71.987 ;
     RECT  11.088 71.761 12.006 72.031 ;
     RECT  13.068 71.491 13.914 72.031 ;
     RECT  14.76 71.951 15.21 72.031 ;
     RECT  23.976 71.987 26.118 72.059 ;
     RECT  26.856 71.987 27.342 72.059 ;
     RECT  29.016 71.879 33.642 72.121 ;
     RECT  16.524 71.915 16.83 72.149 ;
     RECT  24.015 72.059 26.118 72.149 ;
     RECT  29.016 72.121 33.75 72.149 ;
     RECT  39.132 71.609 48.402 72.149 ;
     RECT  54.792 68.783 54.81 72.149 ;
     RECT  29.124 72.149 33.75 72.185 ;
     RECT  13.068 72.031 15.21 72.221 ;
     RECT  25.056 72.149 25.758 72.221 ;
     RECT  32.544 72.185 33.75 72.221 ;
     RECT  11.052 72.031 12.006 72.265 ;
     RECT  39.132 72.149 48.294 72.269 ;
     RECT  13.068 72.221 14.598 72.293 ;
     RECT  25.74 72.221 25.758 72.293 ;
     RECT  30.96 72.185 31.806 72.293 ;
     RECT  39.132 72.269 48.114 72.293 ;
     RECT  37.62 71.915 38.322 72.301 ;
     RECT  39.132 72.293 47.466 72.301 ;
     RECT  34.488 71.681 35.622 72.329 ;
     RECT  50.472 71.951 51.297 72.329 ;
     RECT  10.98 72.265 12.006 72.413 ;
     RECT  36.756 71.789 36.774 72.413 ;
     RECT  10.98 72.413 11.97 72.419 ;
     RECT  14.544 72.293 14.598 72.419 ;
     RECT  16.56 72.149 16.83 72.419 ;
     RECT  37.62 72.301 47.466 72.419 ;
     RECT  16.56 72.419 16.722 72.455 ;
     RECT  37.62 72.419 38.106 72.455 ;
     RECT  39.168 72.419 39.366 72.455 ;
     RECT  13.068 72.293 13.626 72.463 ;
     RECT  39.348 72.455 39.366 72.491 ;
     RECT  10.98 72.419 11.934 72.527 ;
     RECT  12.924 72.463 13.626 72.535 ;
     RECT  33.084 72.221 33.75 72.563 ;
     RECT  34.488 72.329 35.442 72.571 ;
     RECT  29.124 72.185 30.15 72.599 ;
     RECT  11.052 72.527 11.934 72.725 ;
     RECT  29.34 72.599 30.15 72.797 ;
     RECT  40.215 72.419 47.466 72.797 ;
     RECT  40.215 72.797 47.034 72.869 ;
     RECT  11.304 72.725 11.934 72.959 ;
     RECT  14.544 72.419 14.562 72.959 ;
     RECT  36.612 72.805 36.702 72.959 ;
     RECT  12.888 72.535 13.626 72.995 ;
     RECT  34.164 72.571 35.442 72.995 ;
     RECT  13.068 72.995 13.626 73.067 ;
     RECT  40.215 72.869 46.602 73.103 ;
     RECT  13.104 73.067 13.626 73.111 ;
     RECT  34.815 72.995 35.442 73.111 ;
     RECT  36.612 72.959 36.63 73.111 ;
     RECT  2.415 68.513 2.697 73.187 ;
     RECT  7.815 70.565 8.097 73.187 ;
     RECT  18.615 71.609 18.897 73.187 ;
     RECT  24.015 72.149 24.297 73.187 ;
     RECT  29.415 72.797 29.697 73.187 ;
     RECT  40.215 73.103 40.497 73.187 ;
     RECT  51.015 72.329 51.297 73.187 ;
     RECT  56.415 64.589 56.697 73.187 ;
     RECT  61.815 64.085 62.097 73.187 ;
     RECT  67.215 65.129 67.497 73.187 ;
     RECT  72.615 65.309 72.897 73.187 ;
     RECT  11.304 72.959 11.646 73.229 ;
     RECT  13.104 73.111 13.77 73.229 ;
     RECT  34.815 73.111 35.586 73.229 ;
     RECT  36.468 73.111 36.63 73.229 ;
     RECT  41.508 73.103 46.602 73.229 ;
     RECT  11.304 73.229 11.322 73.265 ;
     RECT  34.815 73.229 35.37 73.265 ;
     RECT  36.468 73.229 36.486 73.265 ;
     RECT  42.444 73.229 46.494 73.265 ;
     RECT  42.444 73.265 45.774 73.301 ;
     RECT  13.104 73.229 13.305 73.373 ;
     RECT  42.444 73.301 44.514 73.373 ;
     RECT  45.615 73.301 45.774 73.373 ;
     RECT  42.444 73.373 43.866 73.421 ;
     RECT  2.415 73.187 2.505 73.457 ;
     RECT  7.815 73.187 7.905 73.457 ;
     RECT  13.215 73.373 13.305 73.457 ;
     RECT  18.615 73.187 18.705 73.457 ;
     RECT  24.015 73.187 24.105 73.457 ;
     RECT  29.415 73.187 29.505 73.457 ;
     RECT  34.815 73.265 34.905 73.457 ;
     RECT  40.215 73.187 40.305 73.457 ;
     RECT  45.615 73.373 45.705 73.457 ;
     RECT  51.015 73.187 51.105 73.457 ;
     RECT  56.415 73.187 56.505 73.457 ;
     RECT  61.815 73.187 61.905 73.457 ;
     RECT  67.215 73.187 67.305 73.457 ;
     RECT  72.615 73.187 72.705 73.457 ;
     RECT  53.856 72.265 53.874 74.381 ;
     RECT  41.58 73.229 41.598 74.717 ;
     RECT  42.444 73.421 43.398 74.717 ;
     RECT  42.588 74.717 43.002 74.765 ;
     RECT  42.588 74.765 42.894 75.341 ;
     RECT  42.624 75.341 42.894 75.485 ;
    LAYER M4 ;
     RECT  0.06 1.968 0.097 11.112 ;
     RECT  0.06 46.512 0.097 59.496 ;
     RECT  0.097 1.968 0.133 11.256 ;
     RECT  0.097 46.512 0.133 59.592 ;
     RECT  0.06 22.224 0.137 27.24 ;
     RECT  0.06 37.296 0.137 43.368 ;
     RECT  0.137 22.32 0.173 27.24 ;
     RECT  0.133 1.968 0.179 11.448 ;
     RECT  0.179 2.064 0.181 11.448 ;
     RECT  0.133 45.168 0.181 45.192 ;
     RECT  0.133 46.512 0.181 60.456 ;
     RECT  0.181 2.064 0.227 12.264 ;
     RECT  0.227 2.16 0.229 12.264 ;
     RECT  0.229 2.16 0.325 12.552 ;
     RECT  0.137 37.392 2.293 43.368 ;
     RECT  0.181 45.168 2.293 61.128 ;
     RECT  2.293 34.704 2.365 34.728 ;
     RECT  0.325 2.16 2.408 13.08 ;
     RECT  0.173 22.416 2.408 27.24 ;
     RECT  2.252 30.72 2.408 30.744 ;
     RECT  2.293 32.16 2.408 32.184 ;
     RECT  2.365 34.656 2.408 34.728 ;
     RECT  2.293 37.392 2.408 43.464 ;
     RECT  2.293 44.448 2.408 61.128 ;
     RECT  2.293 62.16 2.408 62.184 ;
     RECT  2.408 2.148 2.512 73.452 ;
     RECT  2.512 2.208 2.704 73.182 ;
     RECT  2.704 23.376 2.765 26.568 ;
     RECT  2.765 25.008 2.873 26.568 ;
     RECT  2.765 23.616 3.017 23.976 ;
     RECT  2.873 25.2 3.017 26.568 ;
     RECT  2.704 2.208 3.059 15.72 ;
     RECT  3.017 25.2 3.413 25.224 ;
     RECT  2.704 64.32 3.449 64.344 ;
     RECT  2.704 29.616 3.491 30.84 ;
     RECT  3.491 29.616 3.587 29.64 ;
     RECT  3.017 26.208 3.697 26.568 ;
     RECT  3.697 26.208 3.781 26.76 ;
     RECT  2.704 27.792 3.781 28.536 ;
     RECT  2.704 32.304 3.805 36.264 ;
     RECT  2.704 37.248 3.805 62.856 ;
     RECT  3.877 22.512 4.129 22.536 ;
     RECT  3.017 23.664 4.129 23.976 ;
     RECT  3.781 26.208 4.165 28.536 ;
     RECT  3.805 32.304 4.205 62.856 ;
     RECT  3.059 2.256 4.268 15.72 ;
     RECT  3.491 30.72 4.417 30.84 ;
     RECT  4.129 22.512 4.501 23.976 ;
     RECT  4.417 30.72 4.501 31.848 ;
     RECT  4.165 25.68 4.525 28.536 ;
     RECT  4.525 25.68 4.547 28.824 ;
     RECT  4.547 26.16 4.561 28.824 ;
     RECT  4.561 26.16 4.777 29.064 ;
     RECT  4.501 30.672 4.777 31.848 ;
     RECT  4.268 2.208 4.837 15.72 ;
     RECT  4.501 22.512 4.885 24.456 ;
     RECT  4.837 2.208 5.057 16.68 ;
     RECT  5.057 2.16 5.141 16.68 ;
     RECT  4.205 32.976 5.353 62.856 ;
     RECT  5.245 20.496 5.497 20.52 ;
     RECT  4.885 21.648 5.497 25.032 ;
     RECT  2.704 65.328 5.557 65.352 ;
     RECT  5.353 32.976 5.603 63.24 ;
     RECT  5.141 2.208 5.653 16.68 ;
     RECT  5.353 18.816 5.699 18.84 ;
     RECT  4.777 26.16 5.713 31.848 ;
     RECT  5.603 32.976 5.713 62.232 ;
     RECT  5.557 64.464 5.756 65.352 ;
     RECT  5.713 26.16 5.825 62.232 ;
     RECT  5.756 64.464 5.845 65.928 ;
     RECT  5.677 67.248 5.845 67.272 ;
     RECT  5.845 64.464 5.932 67.272 ;
     RECT  5.825 28.8 5.933 62.232 ;
     RECT  5.497 20.496 6.005 25.032 ;
     RECT  5.932 65.472 6.037 67.272 ;
     RECT  5.653 2.208 6.073 17.112 ;
     RECT  6.005 23.376 6.109 25.032 ;
     RECT  5.825 26.16 6.109 27.336 ;
     RECT  6.037 65.472 6.289 67.416 ;
     RECT  5.317 68.976 6.289 69 ;
     RECT  6.289 65.472 6.293 69 ;
     RECT  5.933 28.944 6.323 62.232 ;
     RECT  6.073 2.208 6.329 17.16 ;
     RECT  6.293 65.472 6.365 68.376 ;
     RECT  6.005 20.496 6.517 22.248 ;
     RECT  6.517 20.448 6.545 22.248 ;
     RECT  6.109 23.376 6.556 27.336 ;
     RECT  6.365 68.352 6.563 68.376 ;
     RECT  6.545 20.448 6.604 21.672 ;
     RECT  6.329 2.448 6.649 17.16 ;
     RECT  6.556 24.528 6.829 27.336 ;
     RECT  6.649 2.448 6.853 17.352 ;
     RECT  5.857 18.432 6.853 18.456 ;
     RECT  6.323 29.616 6.901 62.232 ;
     RECT  5.603 63.216 6.901 63.24 ;
     RECT  5.932 64.464 6.901 64.488 ;
     RECT  6.853 2.448 6.937 18.456 ;
     RECT  6.901 29.616 7.153 64.488 ;
     RECT  6.365 65.472 7.153 67.176 ;
     RECT  6.556 23.376 7.292 23.4 ;
     RECT  6.937 2.448 7.34 18.792 ;
     RECT  7.292 23.328 7.585 23.4 ;
     RECT  6.829 24.528 7.585 27.912 ;
     RECT  7.34 2.208 7.669 18.792 ;
     RECT  7.669 2.208 7.808 18.84 ;
     RECT  6.604 20.544 7.808 21.672 ;
     RECT  7.585 22.8 7.808 27.912 ;
     RECT  7.153 29.616 7.808 67.176 ;
     RECT  5.797 70.512 7.808 70.536 ;
     RECT  7.808 2.148 7.912 73.452 ;
     RECT  7.912 2.16 8.104 73.182 ;
     RECT  8.104 29.328 8.243 31.704 ;
     RECT  8.104 22.752 8.273 26.568 ;
     RECT  8.104 33.024 8.273 63.336 ;
     RECT  8.273 34.128 8.284 63.336 ;
     RECT  8.284 35.088 8.291 63.336 ;
     RECT  8.104 2.16 8.339 21.672 ;
     RECT  8.104 27.792 8.339 27.912 ;
     RECT  8.243 29.808 8.381 31.704 ;
     RECT  8.291 55.776 8.381 63.336 ;
     RECT  8.291 35.088 8.435 54.696 ;
     RECT  8.381 56.112 8.476 63.336 ;
     RECT  8.435 35.088 8.489 54.648 ;
     RECT  8.476 56.112 8.489 61.992 ;
     RECT  8.339 27.888 8.525 27.912 ;
     RECT  8.489 56.208 8.525 61.992 ;
     RECT  8.104 64.992 8.705 67.08 ;
     RECT  8.273 22.752 8.741 25.512 ;
     RECT  8.273 26.544 8.813 26.568 ;
     RECT  8.339 2.16 8.819 15.432 ;
     RECT  8.741 24.624 8.849 25.512 ;
     RECT  8.489 35.232 8.915 54.648 ;
     RECT  8.849 24.624 8.921 25.08 ;
     RECT  8.476 63.024 9.029 63.336 ;
     RECT  8.104 70.512 9.097 70.536 ;
     RECT  8.273 33.024 9.209 33.048 ;
     RECT  9.029 63.12 9.308 63.336 ;
     RECT  9.308 63.12 9.349 63.624 ;
     RECT  8.705 64.992 9.349 66.84 ;
     RECT  8.819 2.16 9.395 3.528 ;
     RECT  8.339 16.512 9.421 21.672 ;
     RECT  8.741 22.752 9.421 23.448 ;
     RECT  8.819 5.088 9.457 15.432 ;
     RECT  9.421 16.512 9.457 23.448 ;
     RECT  9.457 5.088 9.461 23.448 ;
     RECT  9.461 19.536 9.491 23.448 ;
     RECT  8.915 35.232 9.493 54.504 ;
     RECT  8.525 56.256 9.497 61.992 ;
     RECT  9.497 59.232 9.749 61.992 ;
     RECT  9.349 63.12 9.781 66.84 ;
     RECT  9.097 69.552 9.781 70.536 ;
     RECT  9.781 63.12 9.827 67.704 ;
     RECT  9.781 68.784 9.827 70.536 ;
     RECT  9.827 68.784 9.868 68.808 ;
     RECT  8.921 24.624 10.069 24.648 ;
     RECT  9.395 2.208 10.172 3.528 ;
     RECT  9.491 20.4 10.181 23.448 ;
     RECT  10.172 2.208 10.213 3.576 ;
     RECT  9.461 5.088 10.213 18.312 ;
     RECT  9.827 63.12 10.217 65.448 ;
     RECT  8.381 29.808 10.249 31.656 ;
     RECT  10.181 20.4 10.259 20.712 ;
     RECT  9.497 56.256 10.261 58.152 ;
     RECT  10.217 63.264 10.361 65.448 ;
     RECT  10.069 24.528 10.393 24.648 ;
     RECT  10.364 27.312 10.451 27.336 ;
     RECT  10.259 20.4 10.465 20.664 ;
     RECT  10.261 56.256 10.499 58.104 ;
     RECT  10.181 22.272 10.501 23.448 ;
     RECT  10.393 24.528 10.501 25.224 ;
     RECT  9.827 70.512 10.501 70.536 ;
     RECT  9.493 34.752 10.541 54.504 ;
     RECT  10.465 20.112 10.573 20.664 ;
     RECT  10.499 56.256 10.577 58.008 ;
     RECT  10.541 34.752 10.595 50.76 ;
     RECT  10.595 34.8 10.685 50.76 ;
     RECT  9.827 66.528 10.685 67.704 ;
     RECT  10.213 2.208 10.693 18.312 ;
     RECT  10.573 19.344 10.693 20.664 ;
     RECT  10.249 29.808 10.717 31.992 ;
     RECT  10.405 26.256 10.825 26.28 ;
     RECT  10.717 29.664 10.825 31.992 ;
     RECT  10.825 26.256 10.865 26.376 ;
     RECT  10.825 28.752 10.865 31.992 ;
     RECT  10.577 56.256 10.885 57.864 ;
     RECT  10.685 66.528 10.892 66.744 ;
     RECT  10.693 2.208 10.901 20.664 ;
     RECT  10.361 64.944 10.933 65.448 ;
     RECT  10.865 28.752 10.937 31.656 ;
     RECT  10.901 2.208 10.973 18.84 ;
     RECT  10.892 66.48 10.979 66.744 ;
     RECT  10.979 66.528 11.009 66.744 ;
     RECT  10.933 64.944 11.027 65.496 ;
     RECT  11.009 66.72 11.261 66.744 ;
     RECT  10.901 20.112 11.276 20.664 ;
     RECT  10.501 22.272 11.276 25.224 ;
     RECT  9.749 59.232 11.329 61.608 ;
     RECT  11.276 20.112 11.363 25.224 ;
     RECT  10.685 35.232 11.405 50.76 ;
     RECT  10.361 63.264 11.545 63.672 ;
     RECT  10.541 52.176 11.653 54.504 ;
     RECT  11.405 35.232 11.692 50.088 ;
     RECT  11.363 20.112 11.693 23.736 ;
     RECT  10.885 55.536 11.693 57.864 ;
     RECT  10.973 2.64 11.729 18.84 ;
     RECT  11.729 11.952 11.765 18.84 ;
     RECT  11.653 51.792 11.797 54.504 ;
     RECT  11.693 55.536 11.797 56.856 ;
     RECT  11.545 63.264 11.869 64.056 ;
     RECT  11.765 14.688 11.905 18.84 ;
     RECT  11.693 20.112 11.905 20.808 ;
     RECT  11.729 2.64 11.941 10.872 ;
     RECT  10.937 29.664 11.977 29.688 ;
     RECT  10.937 30.672 11.977 31.656 ;
     RECT  11.941 2.592 11.987 10.872 ;
     RECT  11.905 14.688 11.987 20.808 ;
     RECT  11.869 63.024 12.017 64.056 ;
     RECT  11.761 72.384 12.017 72.408 ;
     RECT  11.329 59.232 12.044 61.848 ;
     RECT  11.797 51.792 12.083 56.856 ;
     RECT  10.865 26.352 12.092 26.376 ;
     RECT  11.765 11.952 12.097 13.704 ;
     RECT  11.977 29.664 12.121 31.656 ;
     RECT  12.083 52.464 12.125 56.856 ;
     RECT  11.363 25.152 12.133 25.224 ;
     RECT  12.092 26.256 12.133 26.376 ;
     RECT  12.017 63.024 12.161 63.672 ;
     RECT  11.761 67.152 12.161 67.176 ;
     RECT  11.693 57.84 12.193 57.864 ;
     RECT  12.044 59.136 12.193 61.848 ;
     RECT  12.193 57.84 12.409 61.848 ;
     RECT  11.692 35.232 12.553 49.032 ;
     RECT  11.027 65.472 12.769 65.496 ;
     RECT  12.097 13.104 12.805 13.704 ;
     RECT  11.987 14.688 12.805 20.664 ;
     RECT  11.941 69.504 12.985 69.528 ;
     RECT  12.805 13.104 13.068 20.664 ;
     RECT  13.068 13.056 13.093 20.664 ;
     RECT  12.125 53.088 13.093 56.856 ;
     RECT  12.409 57.84 13.093 62.184 ;
     RECT  11.987 2.592 13.208 7.464 ;
     RECT  11.987 8.448 13.208 10.872 ;
     RECT  12.097 11.952 13.208 12.024 ;
     RECT  13.093 13.056 13.208 20.952 ;
     RECT  11.693 22.176 13.208 23.736 ;
     RECT  12.133 25.152 13.208 26.376 ;
     RECT  10.501 27.696 13.208 27.72 ;
     RECT  12.121 29.568 13.208 31.656 ;
     RECT  12.553 34.944 13.208 49.032 ;
     RECT  11.692 50.064 13.208 50.088 ;
     RECT  12.769 51.408 13.208 51.432 ;
     RECT  13.093 53.088 13.208 62.184 ;
     RECT  12.161 63.552 13.208 63.672 ;
     RECT  12.769 64.992 13.208 65.496 ;
     RECT  12.985 69.216 13.208 69.528 ;
     RECT  10.501 70.512 13.208 71.112 ;
     RECT  13.208 2.148 13.312 73.452 ;
     RECT  13.312 2.418 13.504 73.182 ;
     RECT  13.504 14.688 13.601 20.952 ;
     RECT  13.504 11.952 13.629 13.32 ;
     RECT  13.504 3.984 13.667 10.728 ;
     RECT  13.504 71.232 13.673 72.216 ;
     RECT  13.504 63.216 13.709 63.576 ;
     RECT  13.504 25.44 13.745 28.968 ;
     RECT  13.504 55.68 13.996 62.184 ;
     RECT  13.996 56.256 14.147 62.184 ;
     RECT  14.147 56.496 14.285 62.184 ;
     RECT  13.709 63.216 14.291 63.24 ;
     RECT  13.504 64.992 14.291 65.496 ;
     RECT  13.504 52.512 14.357 54.696 ;
     RECT  14.285 56.496 14.357 56.808 ;
     RECT  13.745 27.696 14.393 28.968 ;
     RECT  14.291 64.992 14.393 65.016 ;
     RECT  13.504 49.776 14.573 50.28 ;
     RECT  13.601 15.456 14.605 20.952 ;
     RECT  14.605 14.736 14.609 20.952 ;
     RECT  13.745 25.44 14.636 26.376 ;
     RECT  14.636 25.104 14.677 26.376 ;
     RECT  14.677 24.48 14.723 26.376 ;
     RECT  13.629 12.768 14.749 13.32 ;
     RECT  13.667 10.704 14.821 10.728 ;
     RECT  13.504 32.832 14.821 48.408 ;
     RECT  13.667 3.984 14.825 9.528 ;
     RECT  14.357 52.512 14.825 53.928 ;
     RECT  13.504 22.272 14.857 23.448 ;
     RECT  14.723 24.48 14.857 24.504 ;
     RECT  14.357 56.496 14.861 56.568 ;
     RECT  14.573 50.256 14.893 50.28 ;
     RECT  14.821 32.784 14.897 48.408 ;
     RECT  14.857 22.272 15.005 24.504 ;
     RECT  14.897 34.128 15.005 48.408 ;
     RECT  14.924 55.104 15.011 55.128 ;
     RECT  14.893 50.256 15.02 50.712 ;
     RECT  14.897 32.784 15.041 32.856 ;
     RECT  15.02 50.256 15.061 51.48 ;
     RECT  14.723 25.872 15.113 26.376 ;
     RECT  15.041 32.832 15.113 32.856 ;
     RECT  14.393 27.696 15.145 27.72 ;
     RECT  14.609 19.344 15.181 20.952 ;
     RECT  15.005 22.272 15.181 23.592 ;
     RECT  13.673 72.192 15.181 72.216 ;
     RECT  15.181 71.808 15.221 72.216 ;
     RECT  13.504 69.312 15.253 69.336 ;
     RECT  15.005 36.48 15.257 48.408 ;
     RECT  15.061 50.256 15.257 52.008 ;
     RECT  14.821 10.704 15.325 11.544 ;
     RECT  14.609 14.736 15.361 18.312 ;
     RECT  15.325 10.32 15.365 11.544 ;
     RECT  14.825 3.984 15.401 9 ;
     RECT  14.861 56.544 15.469 56.568 ;
     RECT  14.285 57.84 15.469 62.184 ;
     RECT  15.113 25.872 15.473 26.232 ;
     RECT  14.825 53.088 15.473 53.928 ;
     RECT  13.504 2.784 15.545 2.808 ;
     RECT  15.257 50.496 15.545 52.008 ;
     RECT  15.361 14.352 15.649 18.312 ;
     RECT  15.253 69.312 15.649 69.576 ;
     RECT  15.649 14.304 15.685 18.312 ;
     RECT  15.181 19.344 15.685 23.592 ;
     RECT  14.749 12.528 15.733 13.32 ;
     RECT  15.365 10.32 15.829 10.92 ;
     RECT  13.504 30.672 15.833 31.512 ;
     RECT  14.393 28.944 15.836 28.968 ;
     RECT  15.733 12 15.841 13.32 ;
     RECT  15.145 27.312 15.877 27.72 ;
     RECT  15.836 28.944 15.877 29.64 ;
     RECT  15.877 27.312 15.923 30.504 ;
     RECT  15.401 4.464 15.932 9 ;
     RECT  15.829 10.272 15.932 10.92 ;
     RECT  15.923 27.312 15.964 28.296 ;
     RECT  15.841 12.24 15.973 13.32 ;
     RECT  15.685 14.304 15.973 23.592 ;
     RECT  15.005 34.128 15.98 35.496 ;
     RECT  15.469 56.544 16.013 62.184 ;
     RECT  15.932 4.464 16.019 10.92 ;
     RECT  15.257 36.528 16.019 48.408 ;
     RECT  15.221 71.808 16.028 71.832 ;
     RECT  15.98 33.6 16.067 35.496 ;
     RECT  15.973 12.24 16.121 23.592 ;
     RECT  15.829 54.72 16.153 54.744 ;
     RECT  15.923 30.48 16.211 30.504 ;
     RECT  16.067 33.792 16.333 35.496 ;
     RECT  15.649 69.168 16.364 69.576 ;
     RECT  16.028 70.944 16.364 71.832 ;
     RECT  16.153 54.72 16.369 54.888 ;
     RECT  16.364 69.168 16.409 71.832 ;
     RECT  16.333 33.792 16.417 35.88 ;
     RECT  16.409 69.168 16.451 70.248 ;
     RECT  16.417 33.792 16.553 35.352 ;
     RECT  16.409 71.808 16.553 71.832 ;
     RECT  16.019 4.464 16.625 9 ;
     RECT  16.019 10.08 16.697 10.92 ;
     RECT  16.553 33.888 16.733 35.352 ;
     RECT  16.451 69.168 16.765 69.576 ;
     RECT  16.019 36.864 16.801 48.408 ;
     RECT  16.369 54.72 16.801 55.512 ;
     RECT  16.121 12.24 16.805 18.984 ;
     RECT  16.733 34.704 16.841 35.352 ;
     RECT  16.625 8.544 16.877 9 ;
     RECT  15.473 25.872 16.913 25.896 ;
     RECT  16.801 36.864 16.913 48.936 ;
     RECT  16.873 3.408 16.933 3.432 ;
     RECT  16.625 4.464 16.933 7.224 ;
     RECT  15.545 50.688 16.945 52.008 ;
     RECT  16.013 56.976 16.945 62.184 ;
     RECT  16.121 20.112 16.981 23.592 ;
     RECT  15.473 53.088 16.981 53.592 ;
     RECT  16.801 54.72 16.981 55.896 ;
     RECT  16.981 54.72 16.988 55.992 ;
     RECT  16.988 54.672 17.017 55.992 ;
     RECT  16.945 56.976 17.017 62.232 ;
     RECT  16.933 3.408 17.021 7.224 ;
     RECT  16.981 25.152 17.068 25.176 ;
     RECT  16.877 8.784 17.129 9 ;
     RECT  15.833 31.488 17.197 31.512 ;
     RECT  16.913 36.864 17.201 48.552 ;
     RECT  16.805 12.528 17.269 18.984 ;
     RECT  16.981 20.112 17.269 23.928 ;
     RECT  16.333 32.784 17.273 32.808 ;
     RECT  16.945 66.72 17.276 66.744 ;
     RECT  17.276 66.72 17.317 67.32 ;
     RECT  16.697 10.08 17.345 10.728 ;
     RECT  17.197 31.488 17.345 31.704 ;
     RECT  16.765 68.976 17.345 69.576 ;
     RECT  17.317 66.624 17.363 67.32 ;
     RECT  17.269 12.528 17.377 23.928 ;
     RECT  17.363 66.624 17.404 66.648 ;
     RECT  15.964 27.312 17.449 27.72 ;
     RECT  17.345 69.168 17.449 69.576 ;
     RECT  17.449 27.312 17.489 27.912 ;
     RECT  16.945 50.304 17.773 52.008 ;
     RECT  17.773 49.536 17.804 52.008 ;
     RECT  16.981 53.04 17.804 53.592 ;
     RECT  17.804 49.536 17.881 53.592 ;
     RECT  17.017 54.672 17.881 62.232 ;
     RECT  17.021 3.408 17.917 3.432 ;
     RECT  17.345 10.704 18.205 10.728 ;
     RECT  17.201 36.864 18.385 48.264 ;
     RECT  17.881 49.536 18.385 62.232 ;
     RECT  17.489 27.696 18.457 27.912 ;
     RECT  17.605 28.944 18.457 28.968 ;
     RECT  17.917 2.832 18.608 3.432 ;
     RECT  17.021 4.656 18.608 7.224 ;
     RECT  17.129 8.976 18.608 9 ;
     RECT  18.205 10.704 18.608 11.256 ;
     RECT  17.377 12.528 18.608 24.168 ;
     RECT  16.981 26.256 18.608 26.28 ;
     RECT  18.457 27.696 18.608 28.968 ;
     RECT  17.345 31.488 18.608 31.512 ;
     RECT  16.841 34.704 18.608 34.728 ;
     RECT  18.385 36.864 18.608 62.232 ;
     RECT  18.313 67.968 18.608 67.992 ;
     RECT  17.449 69.168 18.608 70.008 ;
     RECT  18.608 2.148 18.712 73.452 ;
     RECT  18.712 2.418 18.904 73.182 ;
     RECT  18.904 45.696 19.073 62.616 ;
     RECT  19.073 46.08 19.109 62.616 ;
     RECT  18.904 27.696 19.132 28.968 ;
     RECT  18.904 4.128 19.139 7.224 ;
     RECT  19.139 6.816 19.181 7.224 ;
     RECT  19.109 49.488 19.217 62.616 ;
     RECT  18.904 26.256 19.325 26.28 ;
     RECT  19.217 49.776 19.397 62.616 ;
     RECT  18.904 65.568 19.405 65.784 ;
     RECT  19.397 49.824 19.427 62.616 ;
     RECT  19.405 65.76 19.433 65.784 ;
     RECT  19.427 56.496 19.469 62.616 ;
     RECT  19.427 49.824 19.632 55.32 ;
     RECT  19.632 49.824 19.649 51.768 ;
     RECT  19.632 52.752 19.721 55.32 ;
     RECT  19.469 60.048 19.793 62.616 ;
     RECT  19.469 56.496 19.829 59.016 ;
     RECT  18.904 12.768 19.897 24.984 ;
     RECT  19.132 28.704 19.937 28.968 ;
     RECT  19.649 51.456 19.937 51.768 ;
     RECT  19.829 58.944 19.937 59.016 ;
     RECT  19.937 51.744 19.973 51.768 ;
     RECT  19.721 54.336 19.973 55.32 ;
     RECT  19.649 49.824 20.045 50.472 ;
     RECT  19.132 27.696 20.108 27.72 ;
     RECT  19.937 28.704 20.108 28.728 ;
     RECT  19.829 56.496 20.153 57.96 ;
     RECT  20.077 66.72 20.189 66.744 ;
     RECT  20.108 27.696 20.195 28.728 ;
     RECT  18.904 36.864 20.225 43.944 ;
     RECT  19.973 55.296 20.243 55.32 ;
     RECT  20.153 56.496 20.243 57.912 ;
     RECT  19.937 58.944 20.243 58.968 ;
     RECT  19.109 46.08 20.297 48.456 ;
     RECT  19.181 7.2 20.339 7.224 ;
     RECT  20.195 28.464 20.369 28.728 ;
     RECT  18.904 8.976 20.401 11.784 ;
     RECT  20.401 8.832 20.473 11.784 ;
     RECT  19.897 12.768 20.473 25.08 ;
     RECT  20.297 46.08 20.473 48.264 ;
     RECT  18.904 31.488 20.533 31.512 ;
     RECT  20.533 31.488 20.545 32.232 ;
     RECT  20.545 31.488 20.579 32.808 ;
     RECT  20.225 36.864 20.693 41.496 ;
     RECT  18.904 34.416 20.873 34.44 ;
     RECT  20.045 50.448 20.873 50.472 ;
     RECT  19.139 4.128 20.905 5.832 ;
     RECT  20.797 68.688 20.905 68.712 ;
     RECT  20.473 45.312 20.977 48.264 ;
     RECT  20.579 32.208 21.017 32.808 ;
     RECT  19.793 60.048 21.049 62.184 ;
     RECT  20.693 40.848 21.053 41.496 ;
     RECT  21.017 32.208 21.089 32.712 ;
     RECT  20.905 4.128 21.121 6.936 ;
     RECT  20.905 68.592 21.157 68.712 ;
     RECT  21.121 3.936 21.193 6.936 ;
     RECT  21.049 60.048 21.233 63 ;
     RECT  21.233 60.048 21.269 62.568 ;
     RECT  20.617 2.784 21.337 2.808 ;
     RECT  21.193 3.888 21.337 6.936 ;
     RECT  20.473 8.832 21.341 25.08 ;
     RECT  20.369 28.464 21.341 28.488 ;
     RECT  21.337 2.784 21.377 6.936 ;
     RECT  21.269 60.048 21.449 62.184 ;
     RECT  20.689 65.664 21.517 65.688 ;
     RECT  20.225 42.528 21.589 43.944 ;
     RECT  20.977 45.024 21.589 48.264 ;
     RECT  21.589 42.528 21.593 48.264 ;
     RECT  20.653 30.624 21.625 30.648 ;
     RECT  20.693 36.864 21.625 39.528 ;
     RECT  21.377 2.784 21.629 6.456 ;
     RECT  21.548 7.728 21.635 7.752 ;
     RECT  21.341 20.352 21.637 25.08 ;
     RECT  21.625 30.624 21.665 30.792 ;
     RECT  21.625 36.528 21.665 39.528 ;
     RECT  21.341 8.832 21.697 19.368 ;
     RECT  19.721 52.752 21.701 52.776 ;
     RECT  21.157 68.592 21.701 68.952 ;
     RECT  21.697 8.784 21.737 19.368 ;
     RECT  21.053 40.992 21.949 41.496 ;
     RECT  21.593 42.528 21.949 47.448 ;
     RECT  21.517 65.568 22.021 65.688 ;
     RECT  22.021 65.424 22.025 65.688 ;
     RECT  21.089 32.208 22.057 32.568 ;
     RECT  21.085 33.84 22.057 33.864 ;
     RECT  21.737 8.784 22.165 17.736 ;
     RECT  21.637 20.352 22.165 25.176 ;
     RECT  21.697 49.584 22.165 49.608 ;
     RECT  21.949 40.992 22.201 47.448 ;
     RECT  22.165 48.816 22.211 50.328 ;
     RECT  22.201 40.56 22.237 47.448 ;
     RECT  22.057 32.208 22.241 33.864 ;
     RECT  21.629 2.832 22.277 6.456 ;
     RECT  21.665 30.768 22.313 30.792 ;
     RECT  21.665 36.528 22.385 38.856 ;
     RECT  22.237 40.416 22.421 47.448 ;
     RECT  22.165 20.352 22.457 25.464 ;
     RECT  22.385 36.576 22.457 38.856 ;
     RECT  20.689 27.072 22.489 27.096 ;
     RECT  22.417 64.032 22.489 64.056 ;
     RECT  22.165 7.968 22.565 17.736 ;
     RECT  21.449 61.68 22.597 62.184 ;
     RECT  22.489 63.984 22.597 64.056 ;
     RECT  22.025 65.424 22.597 65.592 ;
     RECT  22.457 36.864 22.633 38.856 ;
     RECT  22.421 40.416 22.633 43.128 ;
     RECT  22.597 63.984 22.637 65.592 ;
     RECT  21.449 60.048 22.669 60.408 ;
     RECT  21.737 18.72 22.673 19.368 ;
     RECT  22.277 3.024 22.741 6.456 ;
     RECT  22.565 7.968 22.741 9.672 ;
     RECT  22.457 20.352 22.741 25.272 ;
     RECT  22.673 18.72 22.745 18.84 ;
     RECT  22.241 33.84 22.745 33.864 ;
     RECT  22.637 64.032 22.781 65.592 ;
     RECT  22.633 36.864 22.817 43.128 ;
     RECT  21.701 68.592 22.817 68.712 ;
     RECT  22.669 59.328 22.849 60.408 ;
     RECT  22.421 44.256 22.889 47.448 ;
     RECT  22.565 10.656 22.925 17.736 ;
     RECT  22.489 26.736 23.029 27.096 ;
     RECT  20.243 56.496 23.173 57.864 ;
     RECT  22.849 58.944 23.173 60.408 ;
     RECT  22.597 61.68 23.173 62.472 ;
     RECT  22.741 30.24 23.353 30.264 ;
     RECT  22.889 44.448 23.389 47.448 ;
     RECT  22.211 48.816 23.389 48.84 ;
     RECT  23.084 66.624 23.389 66.648 ;
     RECT  22.925 16.272 23.461 17.736 ;
     RECT  23.353 30.24 23.461 31.128 ;
     RECT  22.241 32.208 23.461 32.28 ;
     RECT  22.741 20.112 23.509 25.272 ;
     RECT  23.173 58.944 23.605 62.472 ;
     RECT  22.781 64.032 23.605 64.104 ;
     RECT  23.461 16.272 23.749 18.168 ;
     RECT  22.817 36.864 23.749 39.288 ;
     RECT  23.533 35.328 23.929 35.352 ;
     RECT  22.741 3.024 24.008 9.672 ;
     RECT  22.925 10.656 24.008 15.288 ;
     RECT  23.749 16.272 24.008 18.504 ;
     RECT  23.509 20.112 24.008 25.56 ;
     RECT  23.029 26.736 24.008 27.864 ;
     RECT  23.461 30.24 24.008 32.28 ;
     RECT  23.929 35.232 24.008 35.352 ;
     RECT  23.749 36.528 24.008 39.288 ;
     RECT  22.817 40.416 24.008 43.128 ;
     RECT  23.389 44.448 24.008 48.84 ;
     RECT  22.211 50.112 24.008 50.328 ;
     RECT  23.029 52.704 24.008 52.728 ;
     RECT  23.173 56.256 24.008 57.864 ;
     RECT  23.605 58.944 24.008 64.104 ;
     RECT  23.389 65.664 24.008 66.648 ;
     RECT  22.817 68.688 24.008 68.712 ;
     RECT  18.904 69.984 24.008 70.008 ;
     RECT  24.008 2.148 24.112 73.452 ;
     RECT  24.112 2.418 24.304 73.182 ;
     RECT  24.304 55.44 24.419 57.624 ;
     RECT  24.304 12.768 24.473 27.336 ;
     RECT  24.304 58.656 24.509 60.408 ;
     RECT  24.304 61.68 24.545 64.104 ;
     RECT  24.304 39.456 24.617 42.6 ;
     RECT  24.419 55.44 24.725 55.464 ;
     RECT  24.304 54.048 24.755 54.072 ;
     RECT  24.304 4.128 24.761 9.528 ;
     RECT  24.304 43.632 24.761 48.504 ;
     RECT  24.473 13.392 24.947 27.336 ;
     RECT  24.617 39.456 24.977 41.496 ;
     RECT  24.304 34.896 25.013 38.232 ;
     RECT  24.304 65.28 25.369 65.784 ;
     RECT  24.304 51.36 25.409 53.016 ;
     RECT  24.545 61.68 25.409 62.664 ;
     RECT  24.761 45.744 25.445 48.504 ;
     RECT  25.369 65.28 25.475 66.216 ;
     RECT  25.445 45.744 25.517 47.448 ;
     RECT  24.947 13.392 25.549 27.096 ;
     RECT  24.304 68.4 25.657 69.096 ;
     RECT  24.617 42.528 25.693 42.6 ;
     RECT  25.445 48.48 25.697 48.504 ;
     RECT  24.761 43.632 25.729 44.52 ;
     RECT  25.517 45.744 25.729 47.352 ;
     RECT  24.419 56.496 25.729 57.624 ;
     RECT  25.475 65.52 25.733 66.216 ;
     RECT  24.761 4.128 25.801 7.464 ;
     RECT  24.761 8.448 25.801 9.528 ;
     RECT  25.549 13.296 25.801 27.096 ;
     RECT  25.409 61.68 25.801 62.136 ;
     RECT  24.509 59.76 25.813 60.408 ;
     RECT  25.801 61.584 25.813 62.136 ;
     RECT  25.801 4.128 25.837 9.528 ;
     RECT  24.304 28.416 25.877 28.44 ;
     RECT  24.545 63.648 25.909 64.104 ;
     RECT  25.657 68.352 25.909 69.096 ;
     RECT  25.813 59.76 25.955 62.136 ;
     RECT  25.801 12.576 25.985 27.096 ;
     RECT  25.013 34.896 25.985 38.136 ;
     RECT  24.977 39.744 26.012 41.496 ;
     RECT  25.729 43.632 26.021 47.352 ;
     RECT  25.985 36.288 26.053 38.136 ;
     RECT  26.012 39.264 26.053 41.496 ;
     RECT  25.837 4.128 26.057 9.768 ;
     RECT  25.909 68.352 26.089 69.192 ;
     RECT  24.304 30.624 26.197 32.28 ;
     RECT  26.197 30.624 26.284 32.376 ;
     RECT  26.021 43.968 26.309 47.352 ;
     RECT  25.693 42.528 26.333 42.648 ;
     RECT  26.053 36.288 26.341 41.496 ;
     RECT  26.333 42.528 26.341 42.792 ;
     RECT  26.341 3.12 26.377 3.144 ;
     RECT  26.341 36.288 26.428 42.792 ;
     RECT  25.985 14.64 26.444 27.096 ;
     RECT  25.409 51.36 26.449 51.384 ;
     RECT  26.428 42.528 26.45 42.792 ;
     RECT  26.057 7.44 26.453 9.768 ;
     RECT  24.304 50.064 26.453 50.088 ;
     RECT  26.377 2.928 26.485 3.144 ;
     RECT  26.444 14.64 26.521 27.336 ;
     RECT  26.453 7.44 26.525 9.528 ;
     RECT  26.485 2.88 26.597 3.144 ;
     RECT  25.733 65.52 26.627 65.928 ;
     RECT  26.309 45.024 26.633 47.352 ;
     RECT  25.909 63.648 26.633 64.44 ;
     RECT  26.597 2.928 26.669 3.144 ;
     RECT  25.985 12.576 26.669 13.464 ;
     RECT  25.729 56.4 26.701 57.624 ;
     RECT  24.509 58.656 26.701 58.68 ;
     RECT  26.627 65.52 26.705 65.544 ;
     RECT  26.089 68.256 26.705 69.192 ;
     RECT  26.057 4.128 26.741 6.024 ;
     RECT  26.284 30.624 26.741 31.656 ;
     RECT  26.701 56.4 26.773 58.68 ;
     RECT  26.45 42.528 26.777 42.744 ;
     RECT  26.741 30.72 26.813 31.656 ;
     RECT  26.773 56.4 26.876 58.728 ;
     RECT  25.409 52.992 26.917 53.016 ;
     RECT  26.876 54.48 26.917 54.504 ;
     RECT  26.449 51.12 26.945 51.384 ;
     RECT  26.917 52.992 26.963 54.504 ;
     RECT  26.876 55.92 26.963 58.728 ;
     RECT  25.955 59.856 27.029 62.136 ;
     RECT  26.669 13.44 27.173 13.464 ;
     RECT  26.428 36.288 27.173 41.496 ;
     RECT  26.125 33.84 27.277 33.864 ;
     RECT  25.985 34.896 27.277 34.92 ;
     RECT  27.277 33.84 27.308 34.92 ;
     RECT  27.308 33.84 27.313 35.112 ;
     RECT  26.945 51.12 27.313 51.912 ;
     RECT  27.173 36.384 27.353 41.496 ;
     RECT  26.705 68.352 27.353 69.192 ;
     RECT  26.633 63.648 27.389 63.672 ;
     RECT  27.313 33.072 27.395 35.112 ;
     RECT  26.741 4.128 27.421 5.832 ;
     RECT  26.963 53.328 27.425 53.592 ;
     RECT  26.963 56.496 27.425 58.728 ;
     RECT  26.813 31.632 27.457 31.656 ;
     RECT  26.309 43.968 27.457 43.992 ;
     RECT  27.353 39.552 27.497 41.496 ;
     RECT  27.425 56.736 27.497 58.728 ;
     RECT  27.029 59.856 27.589 60.84 ;
     RECT  27.497 56.736 27.635 58.68 ;
     RECT  25.369 29.616 27.673 29.64 ;
     RECT  26.633 45.744 27.677 47.352 ;
     RECT  27.029 62.112 27.745 62.136 ;
     RECT  27.497 39.552 27.749 39.912 ;
     RECT  27.421 3.456 27.785 5.832 ;
     RECT  27.785 4.128 27.817 5.832 ;
     RECT  26.777 42.528 27.817 42.6 ;
     RECT  27.589 59.76 27.821 60.84 ;
     RECT  27.817 4.128 27.853 6.312 ;
     RECT  27.457 43.968 27.853 44.28 ;
     RECT  27.673 28.848 27.916 29.64 ;
     RECT  27.421 12.432 27.961 12.456 ;
     RECT  26.521 14.64 28.001 27.624 ;
     RECT  27.853 4.128 28.033 6.648 ;
     RECT  27.677 45.744 28.037 46.92 ;
     RECT  28.001 14.64 28.069 26.808 ;
     RECT  27.421 55.248 28.141 55.272 ;
     RECT  27.916 29.616 28.145 29.64 ;
     RECT  27.395 33.072 28.145 35.064 ;
     RECT  27.853 43.968 28.145 44.472 ;
     RECT  27.635 58.656 28.145 58.68 ;
     RECT  27.457 31.632 28.177 31.896 ;
     RECT  28.177 30.816 28.181 31.896 ;
     RECT  27.385 64.992 28.213 65.016 ;
     RECT  28.145 33.072 28.249 33.096 ;
     RECT  27.497 41.04 28.253 41.496 ;
     RECT  28.069 13.872 28.325 26.808 ;
     RECT  28.249 33.024 28.361 33.096 ;
     RECT  27.313 51.12 28.361 51.96 ;
     RECT  27.961 11.952 28.393 12.456 ;
     RECT  27.817 42.48 28.393 42.6 ;
     RECT  28.033 4.128 28.429 6.792 ;
     RECT  28.393 11.952 28.473 12.792 ;
     RECT  28.325 13.872 28.473 25.56 ;
     RECT  28.473 11.952 28.645 25.56 ;
     RECT  27.745 62.112 28.717 63.624 ;
     RECT  28.213 64.992 28.717 65.208 ;
     RECT  27.353 36.384 28.753 38.136 ;
     RECT  28.645 11.472 28.825 25.56 ;
     RECT  27.635 56.736 28.861 57.432 ;
     RECT  28.253 41.472 28.897 41.496 ;
     RECT  28.393 42.48 28.897 42.792 ;
     RECT  27.821 59.76 28.969 59.784 ;
     RECT  28.145 34.128 28.997 35.064 ;
     RECT  28.753 36.384 28.997 38.568 ;
     RECT  28.429 4.128 29.077 6.84 ;
     RECT  26.525 8.256 29.077 9.528 ;
     RECT  28.825 10.704 29.077 25.56 ;
     RECT  28.717 62.112 29.113 65.208 ;
     RECT  28.325 26.544 29.149 26.808 ;
     RECT  27.061 48.432 29.149 48.456 ;
     RECT  29.077 70.656 29.149 70.68 ;
     RECT  28.997 34.128 29.257 38.568 ;
     RECT  27.749 39.552 29.257 39.576 ;
     RECT  28.969 59.76 29.269 59.832 ;
     RECT  27.821 60.816 29.269 60.84 ;
     RECT  29.113 62.064 29.269 65.208 ;
     RECT  27.353 69.168 29.293 69.192 ;
     RECT  29.077 4.128 29.329 25.56 ;
     RECT  29.149 26.544 29.329 27.384 ;
     RECT  28.753 3.024 29.408 3.048 ;
     RECT  29.329 4.128 29.408 27.384 ;
     RECT  28.181 30.816 29.408 31.656 ;
     RECT  28.361 33.024 29.408 33.048 ;
     RECT  29.257 34.128 29.408 39.576 ;
     RECT  28.897 41.472 29.408 42.792 ;
     RECT  28.145 43.968 29.408 43.992 ;
     RECT  28.037 46.512 29.408 46.92 ;
     RECT  29.149 48.288 29.408 48.456 ;
     RECT  28.753 49.584 29.408 49.608 ;
     RECT  28.465 50.64 29.408 50.664 ;
     RECT  28.361 51.936 29.408 51.96 ;
     RECT  27.425 53.328 29.408 53.352 ;
     RECT  28.141 54.912 29.408 55.32 ;
     RECT  28.861 56.736 29.408 57.72 ;
     RECT  29.221 58.704 29.408 58.728 ;
     RECT  29.269 59.76 29.408 65.208 ;
     RECT  29.293 69.024 29.408 69.192 ;
     RECT  29.149 70.608 29.408 70.68 ;
     RECT  29.408 2.148 29.512 73.452 ;
     RECT  29.512 2.418 29.704 73.182 ;
     RECT  29.704 30.912 29.801 33.624 ;
     RECT  29.704 40.896 29.801 42.792 ;
     RECT  29.704 46.224 29.801 48.456 ;
     RECT  29.704 2.784 29.843 12.552 ;
     RECT  29.704 59.184 29.884 64.104 ;
     RECT  29.884 59.184 29.981 60.984 ;
     RECT  29.884 62.16 29.981 64.104 ;
     RECT  29.704 14.64 29.987 27.336 ;
     RECT  29.704 13.584 30.233 13.608 ;
     RECT  29.704 65.952 30.316 69.048 ;
     RECT  29.987 14.64 30.341 25.656 ;
     RECT  30.316 65.952 30.341 67.944 ;
     RECT  29.704 57.6 30.593 58.152 ;
     RECT  29.704 36.864 30.733 39.576 ;
     RECT  30.733 36.576 30.737 39.576 ;
     RECT  30.737 36.576 30.769 39.48 ;
     RECT  29.843 2.784 30.773 9.528 ;
     RECT  29.801 31.584 30.773 33.624 ;
     RECT  29.987 26.784 30.805 27.336 ;
     RECT  29.981 62.448 30.809 64.104 ;
     RECT  30.773 4.512 30.908 9.528 ;
     RECT  29.843 10.608 30.908 12.552 ;
     RECT  30.908 4.512 30.949 12.552 ;
     RECT  30.769 36.336 30.989 39.48 ;
     RECT  30.341 67.776 30.989 67.944 ;
     RECT  30.341 65.952 31.021 65.976 ;
     RECT  30.805 26.784 31.057 28.104 ;
     RECT  29.704 29.088 31.057 29.4 ;
     RECT  30.773 33.024 31.061 33.624 ;
     RECT  30.841 54.72 31.061 54.744 ;
     RECT  30.809 62.448 31.061 63.096 ;
     RECT  30.341 14.736 31.097 25.656 ;
     RECT  29.704 51.648 31.097 53.352 ;
     RECT  30.949 58.704 31.097 58.728 ;
     RECT  30.989 67.824 31.133 67.944 ;
     RECT  30.316 68.976 31.133 69.048 ;
     RECT  29.801 40.896 31.165 42.6 ;
     RECT  31.097 51.936 31.165 53.352 ;
     RECT  31.057 26.784 31.237 29.4 ;
     RECT  29.801 46.224 31.241 46.92 ;
     RECT  29.704 45.168 31.273 45.192 ;
     RECT  30.773 31.584 31.333 31.848 ;
     RECT  31.237 26.784 31.379 30.072 ;
     RECT  30.593 57.6 31.381 57.72 ;
     RECT  30.733 35.328 31.421 35.352 ;
     RECT  31.165 51.936 31.457 54.12 ;
     RECT  31.273 44.448 31.493 45.192 ;
     RECT  31.165 40.896 31.523 43.32 ;
     RECT  31.493 45.024 31.529 45.192 ;
     RECT  31.241 46.512 31.597 46.92 ;
     RECT  31.379 26.784 31.669 29.688 ;
     RECT  29.704 50.256 31.669 50.664 ;
     RECT  31.021 65.904 31.673 65.976 ;
     RECT  30.949 4.512 31.741 12.6 ;
     RECT  31.061 33.6 31.741 33.624 ;
     RECT  31.669 26.208 31.753 29.688 ;
     RECT  31.523 40.896 31.781 42.6 ;
     RECT  31.333 31.344 31.817 31.848 ;
     RECT  31.741 33.6 31.817 34.248 ;
     RECT  31.669 50.256 31.817 50.856 ;
     RECT  31.061 62.976 31.849 63.096 ;
     RECT  30.809 64.08 31.849 64.104 ;
     RECT  30.989 36.48 31.885 39.48 ;
     RECT  29.981 60.144 31.909 60.984 ;
     RECT  30.773 2.784 31.921 3.432 ;
     RECT  31.741 4.512 31.921 12.648 ;
     RECT  31.909 60.144 31.955 61.896 ;
     RECT  31.849 62.976 31.955 64.104 ;
     RECT  31.921 2.784 31.957 12.648 ;
     RECT  31.817 50.832 31.961 50.856 ;
     RECT  31.957 2.784 32.029 12.984 ;
     RECT  32.029 2.496 32.065 12.984 ;
     RECT  32.065 2.496 32.092 13.128 ;
     RECT  31.597 46.512 32.101 47.304 ;
     RECT  31.529 45.168 32.147 45.192 ;
     RECT  32.101 46.512 32.185 47.352 ;
     RECT  31.885 36.48 32.209 39.96 ;
     RECT  31.457 51.936 32.245 53.496 ;
     RECT  31.955 63.072 32.249 64.104 ;
     RECT  31.909 65.52 32.339 65.544 ;
     RECT  31.133 67.92 32.339 67.944 ;
     RECT  32.092 3.84 32.4 13.128 ;
     RECT  32.4 5.04 32.425 13.128 ;
     RECT  31.133 69.024 32.461 69.048 ;
     RECT  31.817 31.632 32.485 31.848 ;
     RECT  32.281 54.72 32.501 54.744 ;
     RECT  32.461 69.024 32.501 69.24 ;
     RECT  32.485 31.632 32.531 31.896 ;
     RECT  32.425 5.04 32.609 13.608 ;
     RECT  32.609 7.392 32.641 13.608 ;
     RECT  31.097 14.736 32.641 25.032 ;
     RECT  31.381 57.264 32.645 57.72 ;
     RECT  32.531 31.824 32.753 31.896 ;
     RECT  32.209 35.952 32.821 39.96 ;
     RECT  31.165 48.96 32.821 48.984 ;
     RECT  32.821 35.952 32.828 40.056 ;
     RECT  31.753 26.784 32.857 29.688 ;
     RECT  32.185 46.512 32.897 47.304 ;
     RECT  32.753 31.872 32.915 31.896 ;
     RECT  32.137 55.728 32.929 55.752 ;
     RECT  32.641 7.392 32.969 25.032 ;
     RECT  32.897 46.512 32.969 46.68 ;
     RECT  32.245 51.84 33.001 53.496 ;
     RECT  31.781 41.472 33.037 42.6 ;
     RECT  32.749 43.584 33.037 43.608 ;
     RECT  32.857 44.928 33.037 44.952 ;
     RECT  32.821 48.96 33.037 49.608 ;
     RECT  33.037 48.96 33.059 50.28 ;
     RECT  33.001 51.744 33.061 53.496 ;
     RECT  31.955 60.816 33.061 61.896 ;
     RECT  32.249 63.072 33.061 63.72 ;
     RECT  32.645 57.552 33.107 57.72 ;
     RECT  32.828 35.616 33.113 40.056 ;
     RECT  31.817 34.224 33.145 34.248 ;
     RECT  33.113 35.616 33.145 36.936 ;
     RECT  32.092 2.496 33.181 2.856 ;
     RECT  32.4 3.84 33.181 3.96 ;
     RECT  32.969 7.392 33.221 15.288 ;
     RECT  32.857 26.256 33.253 29.688 ;
     RECT  33.107 57.552 33.257 57.576 ;
     RECT  33.061 60.816 33.257 63.72 ;
     RECT  33.221 12.144 33.293 15.288 ;
     RECT  33.257 60.816 33.293 62.952 ;
     RECT  33.221 7.392 33.329 11.16 ;
     RECT  33.253 26.256 33.337 30.264 ;
     RECT  33.337 26.256 33.34 29.544 ;
     RECT  33.293 13.632 33.347 15.288 ;
     RECT  33.037 41.472 33.361 44.952 ;
     RECT  33.059 48.96 33.365 48.984 ;
     RECT  32.929 55.008 33.469 55.752 ;
     RECT  33.181 2.496 33.541 3.96 ;
     RECT  33.361 41.136 33.541 44.952 ;
     RECT  33.433 48.48 33.541 48.84 ;
     RECT  33.145 34.224 33.545 36.936 ;
     RECT  33.329 7.728 33.581 11.16 ;
     RECT  33.061 51.744 33.617 53.592 ;
     RECT  33.469 55.008 33.617 56.424 ;
     RECT  33.34 26.256 33.676 28.92 ;
     RECT  33.617 55.008 33.689 55.752 ;
     RECT  33.059 50.256 33.721 50.28 ;
     RECT  33.541 41.088 33.725 44.952 ;
     RECT  32.501 69.216 33.733 69.24 ;
     RECT  33.541 2.304 33.761 3.96 ;
     RECT  33.721 50.256 33.761 50.664 ;
     RECT  33.293 60.816 33.797 62.184 ;
     RECT  32.609 5.04 33.833 6.36 ;
     RECT  33.725 41.088 33.833 44.472 ;
     RECT  33.061 59.04 33.877 59.352 ;
     RECT  33.733 68.928 33.925 69.24 ;
     RECT  32.857 33.072 33.973 33.096 ;
     RECT  33.925 68.352 33.973 69.24 ;
     RECT  33.347 13.68 34.117 15.288 ;
     RECT  32.969 16.32 34.117 25.032 ;
     RECT  33.113 37.968 34.153 40.056 ;
     RECT  33.833 41.088 34.153 43.656 ;
     RECT  33.061 64.848 34.153 64.872 ;
     RECT  34.153 64.704 34.189 64.872 ;
     RECT  34.189 64.704 34.261 65.016 ;
     RECT  33.581 7.728 34.309 9.768 ;
     RECT  33.761 3.696 34.333 3.96 ;
     RECT  33.833 5.04 34.333 6.168 ;
     RECT  34.261 64.176 34.441 65.016 ;
     RECT  32.969 46.512 34.513 46.536 ;
     RECT  33.293 12.144 34.549 12.504 ;
     RECT  34.117 13.68 34.549 25.032 ;
     RECT  32.293 66.768 34.577 66.792 ;
     RECT  34.549 12.144 34.652 25.032 ;
     RECT  33.676 26.256 34.652 28.44 ;
     RECT  34.405 71.328 34.693 71.352 ;
     RECT  33.545 35.712 34.729 36.936 ;
     RECT  33.689 55.008 34.729 55.032 ;
     RECT  33.761 50.64 34.765 50.664 ;
     RECT  33.877 59.04 34.765 59.592 ;
     RECT  33.797 60.816 34.765 61.464 ;
     RECT  33.761 2.304 34.808 2.52 ;
     RECT  34.333 3.696 34.808 6.168 ;
     RECT  34.309 7.152 34.808 9.768 ;
     RECT  33.581 11.136 34.808 11.16 ;
     RECT  34.652 12.144 34.808 28.44 ;
     RECT  33.973 32.304 34.808 33.096 ;
     RECT  33.545 34.224 34.808 34.248 ;
     RECT  34.729 35.472 34.808 36.936 ;
     RECT  34.153 37.968 34.808 43.656 ;
     RECT  34.513 45.552 34.808 46.536 ;
     RECT  33.541 47.856 34.808 48.84 ;
     RECT  34.765 49.872 34.808 50.664 ;
     RECT  33.617 51.888 34.808 53.592 ;
     RECT  34.729 54.96 34.808 55.56 ;
     RECT  34.765 58.128 34.808 59.592 ;
     RECT  34.765 60.672 34.808 61.464 ;
     RECT  34.441 64.08 34.808 65.016 ;
     RECT  34.577 66.096 34.808 66.792 ;
     RECT  33.973 67.872 34.808 69.24 ;
     RECT  34.693 71.136 34.808 71.352 ;
     RECT  34.153 72.816 34.808 72.84 ;
     RECT  34.808 2.148 34.912 73.452 ;
     RECT  34.912 2.304 35.104 73.182 ;
     RECT  35.104 40.32 35.165 43.896 ;
     RECT  35.104 60.672 35.165 62.232 ;
     RECT  35.104 64.08 35.165 68.952 ;
     RECT  35.104 59.424 35.201 59.592 ;
     RECT  35.104 11.712 35.219 30.888 ;
     RECT  35.104 54.624 35.219 57.912 ;
     RECT  35.201 59.424 35.219 59.448 ;
     RECT  35.104 2.304 35.267 4.2 ;
     RECT  35.219 26.784 35.309 30.888 ;
     RECT  35.165 64.08 35.309 67.032 ;
     RECT  35.267 2.64 35.315 4.2 ;
     RECT  35.104 46.512 35.315 46.536 ;
     RECT  35.104 52.272 35.315 53.112 ;
     RECT  35.165 60.672 35.381 61.464 ;
     RECT  35.309 64.368 35.381 67.032 ;
     RECT  35.104 5.184 35.411 10.296 ;
     RECT  35.411 6.816 35.453 10.296 ;
     RECT  35.104 72.384 35.453 72.84 ;
     RECT  35.104 47.904 35.489 50.712 ;
     RECT  35.315 2.64 35.525 2.664 ;
     RECT  35.381 65.328 35.555 67.032 ;
     RECT  35.165 68.112 35.555 68.952 ;
     RECT  35.104 34.032 35.561 39.24 ;
     RECT  35.219 54.624 35.561 57.72 ;
     RECT  35.489 48.672 35.603 50.712 ;
     RECT  35.561 34.032 35.633 36.792 ;
     RECT  35.633 34.224 35.705 36.792 ;
     RECT  35.561 54.72 35.741 57.72 ;
     RECT  35.453 7.968 35.885 10.296 ;
     RECT  35.219 11.712 35.885 25.704 ;
     RECT  35.315 3.984 35.957 4.2 ;
     RECT  35.885 11.712 35.957 11.736 ;
     RECT  35.885 12.864 35.957 25.704 ;
     RECT  35.957 13.872 35.987 25.704 ;
     RECT  35.381 60.672 36.029 61.224 ;
     RECT  35.705 34.224 36.073 36.696 ;
     RECT  35.957 12.864 36.101 12.888 ;
     RECT  35.309 26.832 36.101 30.888 ;
     RECT  35.741 54.72 36.101 54.984 ;
     RECT  35.987 13.872 36.137 25.176 ;
     RECT  36.101 28.848 36.137 30.888 ;
     RECT  35.165 40.944 36.137 43.896 ;
     RECT  36.137 30.528 36.241 30.888 ;
     RECT  35.104 31.872 36.241 32.328 ;
     RECT  36.073 34.656 36.245 36.696 ;
     RECT  36.284 2.88 36.285 2.904 ;
     RECT  35.957 3.984 36.285 4.104 ;
     RECT  36.285 2.88 36.371 4.104 ;
     RECT  36.137 40.944 36.421 43.56 ;
     RECT  36.137 28.848 36.461 29.256 ;
     RECT  36.241 30.528 36.461 32.328 ;
     RECT  35.555 68.928 36.469 68.952 ;
     RECT  35.104 70.656 36.469 70.68 ;
     RECT  36.469 70.656 36.515 70.92 ;
     RECT  35.603 50.688 36.565 50.712 ;
     RECT  36.461 28.896 36.569 29.256 ;
     RECT  36.169 45.12 36.569 45.144 ;
     RECT  36.469 68.928 36.569 69.528 ;
     RECT  35.411 5.184 36.637 5.208 ;
     RECT  35.453 6.816 36.637 6.984 ;
     RECT  35.885 7.968 36.637 8.472 ;
     RECT  36.245 34.8 36.673 36.696 ;
     RECT  35.561 37.968 36.673 39.24 ;
     RECT  35.741 56.208 36.709 57.72 ;
     RECT  36.029 60.672 36.755 60.696 ;
     RECT  36.673 34.8 36.785 39.24 ;
     RECT  35.453 72.384 36.785 72.408 ;
     RECT  36.637 5.184 36.889 8.472 ;
     RECT  35.885 9.504 36.889 10.296 ;
     RECT  36.371 3.408 36.997 4.104 ;
     RECT  36.889 5.184 36.997 10.296 ;
     RECT  36.515 70.896 36.997 70.92 ;
     RECT  35.315 52.704 37.001 52.824 ;
     RECT  36.421 40.8 37.033 43.56 ;
     RECT  37.033 40.224 37.037 43.56 ;
     RECT  36.997 3.408 37.045 10.296 ;
     RECT  36.637 67.824 37.045 67.848 ;
     RECT  36.997 47.616 37.069 47.64 ;
     RECT  35.603 48.672 37.069 48.696 ;
     RECT  36.101 54.72 37.069 54.744 ;
     RECT  37.045 4.08 37.073 10.296 ;
     RECT  37.037 40.224 37.073 42.552 ;
     RECT  37.045 67.152 37.091 67.848 ;
     RECT  37.073 4.656 37.093 10.296 ;
     RECT  37.073 41.376 37.109 42.552 ;
     RECT  36.997 70.896 37.109 71.256 ;
     RECT  37.073 40.224 37.117 40.248 ;
     RECT  36.569 69.504 37.145 69.528 ;
     RECT  36.137 13.872 37.213 25.032 ;
     RECT  37.001 52.8 37.217 52.824 ;
     RECT  36.853 66.144 37.244 66.168 ;
     RECT  37.091 67.152 37.244 67.8 ;
     RECT  37.213 13.536 37.249 25.032 ;
     RECT  36.461 30.528 37.285 31.896 ;
     RECT  36.785 35.136 37.325 39.24 ;
     RECT  37.244 66.144 37.325 67.8 ;
     RECT  37.325 66.144 37.331 66.696 ;
     RECT  36.709 56.208 37.379 58.68 ;
     RECT  37.069 47.616 37.397 48.696 ;
     RECT  37.331 66.144 37.397 66.168 ;
     RECT  37.379 57.84 37.429 58.68 ;
     RECT  37.379 56.208 37.433 56.232 ;
     RECT  37.249 13.536 37.501 25.464 ;
     RECT  36.101 26.832 37.501 27.624 ;
     RECT  37.285 30.144 37.501 31.896 ;
     RECT  37.093 4.656 37.532 10.344 ;
     RECT  37.321 11.424 37.532 11.448 ;
     RECT  36.569 28.896 37.573 28.92 ;
     RECT  37.501 30.144 37.573 32.472 ;
     RECT  37.069 54.672 37.577 54.744 ;
     RECT  37.429 57.84 37.577 58.728 ;
     RECT  37.532 4.656 37.619 11.448 ;
     RECT  37.501 13.536 37.619 27.624 ;
     RECT  37.619 13.536 37.645 25.848 ;
     RECT  37.577 57.84 37.685 58.152 ;
     RECT  37.645 45.168 37.709 45.384 ;
     RECT  37.037 43.536 37.717 43.56 ;
     RECT  36.565 50.64 37.717 50.712 ;
     RECT  37.619 8.112 37.753 11.448 ;
     RECT  37.619 26.832 37.756 27.624 ;
     RECT  37.717 43.536 37.757 43.944 ;
     RECT  36.925 64.752 37.757 64.776 ;
     RECT  37.709 45.168 37.793 45.576 ;
     RECT  36.485 63.744 37.793 63.768 ;
     RECT  37.717 50.64 37.82 50.76 ;
     RECT  37.573 28.896 37.825 32.472 ;
     RECT  37.82 50.64 37.861 51 ;
     RECT  37.757 43.92 37.901 43.944 ;
     RECT  37.861 54.144 37.945 54.168 ;
     RECT  37.756 26.832 37.955 27.672 ;
     RECT  37.645 13.488 38.045 25.848 ;
     RECT  37.955 26.88 38.149 27.672 ;
     RECT  37.753 8.112 38.185 12.36 ;
     RECT  38.045 13.488 38.185 14.808 ;
     RECT  38.113 70.224 38.197 70.248 ;
     RECT  37.861 50.64 38.221 51.816 ;
     RECT  37.325 35.136 38.225 38.136 ;
     RECT  37.825 28.896 38.243 33.144 ;
     RECT  38.041 68.928 38.243 68.952 ;
     RECT  38.197 69.936 38.243 70.248 ;
     RECT  38.243 69.936 38.284 69.96 ;
     RECT  38.221 50.64 38.3 52.2 ;
     RECT  38.149 26.88 38.405 27.912 ;
     RECT  38.045 15.84 38.428 25.848 ;
     RECT  38.225 35.136 38.441 36.312 ;
     RECT  37.109 41.376 38.473 42.312 ;
     RECT  37.397 47.616 38.585 48.456 ;
     RECT  37.619 4.656 38.617 6.84 ;
     RECT  38.185 8.112 38.617 14.808 ;
     RECT  37.685 58.128 38.629 58.152 ;
     RECT  38.585 47.856 38.653 48.456 ;
     RECT  38.3 50.016 38.653 52.2 ;
     RECT  37.325 67.776 38.653 67.8 ;
     RECT  38.243 28.896 38.657 29.64 ;
     RECT  38.629 58.128 38.716 58.872 ;
     RECT  38.243 30.864 38.833 33.144 ;
     RECT  37.793 45.168 38.869 45.384 ;
     RECT  38.149 46.56 38.869 46.584 ;
     RECT  38.428 15.888 38.873 25.848 ;
     RECT  38.653 47.856 38.873 52.2 ;
     RECT  38.833 30.864 38.905 33.864 ;
     RECT  38.441 35.136 38.905 35.16 ;
     RECT  38.617 4.656 38.909 14.808 ;
     RECT  38.873 49.584 38.981 52.2 ;
     RECT  38.909 10.848 39.049 14.808 ;
     RECT  39.049 10.848 39.053 14.904 ;
     RECT  38.905 30.864 39.053 35.16 ;
     RECT  38.657 29.616 39.089 29.64 ;
     RECT  39.077 2.88 39.161 2.904 ;
     RECT  38.225 37.872 39.193 38.136 ;
     RECT  37.325 39.168 39.193 39.24 ;
     RECT  38.869 45.168 39.205 46.584 ;
     RECT  39.049 0.096 39.251 0.12 ;
     RECT  38.441 36.288 39.301 36.312 ;
     RECT  39.193 37.632 39.329 39.24 ;
     RECT  39.301 1.728 39.337 1.752 ;
     RECT  39.337 1.104 39.517 1.752 ;
     RECT  39.053 30.864 39.553 30.984 ;
     RECT  38.653 67.248 39.553 67.8 ;
     RECT  39.553 66.672 39.625 67.8 ;
     RECT  38.761 59.808 39.637 59.832 ;
     RECT  39.517 0.144 39.661 1.752 ;
     RECT  38.221 53.52 39.661 53.592 ;
     RECT  39.205 45.168 39.769 46.68 ;
     RECT  38.873 47.856 39.769 48.264 ;
     RECT  39.637 61.872 39.841 61.896 ;
     RECT  38.909 4.656 39.925 9.576 ;
     RECT  39.925 4.032 40.069 9.576 ;
     RECT  39.053 11.232 40.069 14.904 ;
     RECT  39.553 30.048 40.069 30.984 ;
     RECT  39.329 37.632 40.069 39.384 ;
     RECT  38.581 56.064 40.093 56.088 ;
     RECT  39.661 0.144 40.208 2.808 ;
     RECT  40.069 3.984 40.208 9.576 ;
     RECT  40.069 11.232 40.208 14.952 ;
     RECT  38.873 16.032 40.208 25.848 ;
     RECT  38.405 27.168 40.208 27.912 ;
     RECT  40.069 29.568 40.208 30.984 ;
     RECT  39.053 32.448 40.208 35.16 ;
     RECT  39.301 36.288 40.208 36.504 ;
     RECT  40.069 37.584 40.208 39.384 ;
     RECT  38.473 41.376 40.208 42.648 ;
     RECT  39.553 43.68 40.208 43.704 ;
     RECT  39.769 45.168 40.208 48.264 ;
     RECT  38.981 49.824 40.208 52.2 ;
     RECT  39.661 53.52 40.208 54.12 ;
     RECT  40.093 55.152 40.208 57.048 ;
     RECT  38.716 58.128 40.208 58.152 ;
     RECT  39.637 59.808 40.208 60.504 ;
     RECT  39.841 61.872 40.208 62.184 ;
     RECT  38.869 63.84 40.208 63.864 ;
     RECT  39.229 64.992 40.208 65.544 ;
     RECT  39.625 66.672 40.208 68.136 ;
     RECT  39.013 69.216 40.208 69.24 ;
     RECT  40.208 0.144 40.312 73.452 ;
     RECT  40.312 0.144 40.403 73.182 ;
     RECT  40.403 1.104 40.499 73.182 ;
     RECT  40.499 1.152 40.504 73.182 ;
     RECT  40.504 37.872 40.601 38.28 ;
     RECT  40.504 1.152 40.643 4.584 ;
     RECT  40.504 26.64 40.643 31.128 ;
     RECT  40.504 32.784 40.673 34.824 ;
     RECT  40.643 26.88 40.745 31.128 ;
     RECT  40.504 57.024 40.745 57.048 ;
     RECT  40.504 62.16 40.787 62.712 ;
     RECT  40.504 55.152 40.853 55.656 ;
     RECT  40.504 59.808 40.925 60.12 ;
     RECT  40.504 68.112 40.925 68.136 ;
     RECT  40.504 44.448 40.933 46.104 ;
     RECT  40.504 9.696 41.027 18.744 ;
     RECT  41.027 9.696 41.069 10.68 ;
     RECT  40.504 41.616 41.069 42.312 ;
     RECT  40.504 47.088 41.075 50.568 ;
     RECT  40.504 64.992 41.105 65.016 ;
     RECT  41.027 12 41.171 18.744 ;
     RECT  40.504 39.744 41.213 39.912 ;
     RECT  41.069 41.76 41.213 42.312 ;
     RECT  41.075 47.088 41.285 49.752 ;
     RECT  41.171 12 41.315 17.688 ;
     RECT  41.315 12 41.321 17.64 ;
     RECT  40.745 26.88 41.357 28.584 ;
     RECT  40.673 34.8 41.357 34.824 ;
     RECT  40.643 1.152 41.363 2.328 ;
     RECT  40.504 19.776 41.429 24.984 ;
     RECT  41.429 19.776 41.501 24.696 ;
     RECT  40.745 30.048 41.507 31.128 ;
     RECT  40.549 0.096 41.509 0.12 ;
     RECT  40.643 3.36 41.537 4.584 ;
     RECT  40.504 6.576 41.605 8.52 ;
     RECT  41.213 39.888 41.605 39.912 ;
     RECT  40.504 51.696 41.605 52.2 ;
     RECT  41.363 1.728 41.641 2.328 ;
     RECT  41.537 3.36 41.641 3.432 ;
     RECT  40.933 45.024 41.645 46.104 ;
     RECT  41.509 0.096 41.701 0.168 ;
     RECT  41.285 47.088 41.753 49.368 ;
     RECT  40.673 32.784 41.785 33.72 ;
     RECT  41.537 4.56 41.797 4.584 ;
     RECT  41.797 4.56 41.845 5.112 ;
     RECT  41.605 6.576 41.845 9.144 ;
     RECT  41.321 12.528 41.861 17.64 ;
     RECT  41.605 39.888 41.897 40.68 ;
     RECT  41.753 47.088 41.933 48.936 ;
     RECT  41.933 47.232 41.969 48.936 ;
     RECT  40.925 60.096 41.989 60.12 ;
     RECT  40.853 55.632 42.035 55.656 ;
     RECT  41.645 45.024 42.037 45.432 ;
     RECT  41.701 0.096 42.041 0.6 ;
     RECT  41.641 1.728 42.113 3.432 ;
     RECT  41.897 39.888 42.113 40.056 ;
     RECT  41.845 4.56 42.133 9.144 ;
     RECT  41.069 10.656 42.133 10.68 ;
     RECT  40.504 54.096 42.14 54.12 ;
     RECT  42.041 0.096 42.149 0.552 ;
     RECT  40.504 69.216 42.149 71.352 ;
     RECT  41.507 30.864 42.181 31.128 ;
     RECT  41.785 32.448 42.181 33.72 ;
     RECT  41.605 50.832 42.181 52.728 ;
     RECT  42.14 53.76 42.181 54.12 ;
     RECT  41.861 12.528 42.185 13.944 ;
     RECT  42.181 50.832 42.185 54.12 ;
     RECT  40.504 36.048 42.221 36.072 ;
     RECT  42.185 50.832 42.227 53.784 ;
     RECT  42.133 4.56 42.257 10.68 ;
     RECT  42.185 12.528 42.293 13.896 ;
     RECT  41.171 18.72 42.325 18.744 ;
     RECT  42.181 30.864 42.365 33.72 ;
     RECT  42.277 64.224 42.397 64.248 ;
     RECT  42.325 18.72 42.421 18.792 ;
     RECT  41.501 19.776 42.421 24.36 ;
     RECT  41.357 27.216 42.433 28.584 ;
     RECT  42.109 66.72 42.433 66.744 ;
     RECT  42.433 27.216 42.476 28.968 ;
     RECT  42.227 50.832 42.509 53.016 ;
     RECT  42.476 27.216 42.517 29.448 ;
     RECT  42.365 30.864 42.517 31.944 ;
     RECT  42.517 27.216 42.563 31.944 ;
     RECT  42.257 8.448 42.565 10.68 ;
     RECT  42.397 64.224 42.577 64.728 ;
     RECT  41.569 74.688 42.577 74.712 ;
     RECT  42.073 26.208 42.613 26.232 ;
     RECT  42.563 27.216 42.613 28.968 ;
     RECT  42.577 74.688 42.613 75.336 ;
     RECT  42.149 69.216 42.661 71.256 ;
     RECT  41.948 57.552 42.685 57.576 ;
     RECT  42.565 8.448 42.689 10.872 ;
     RECT  42.037 44.352 42.689 45.432 ;
     RECT  42.113 1.776 42.707 3.432 ;
     RECT  42.689 10.656 42.707 10.872 ;
     RECT  42.469 73.536 42.707 73.608 ;
     RECT  42.433 66.72 42.709 66.792 ;
     RECT  42.709 66.72 42.725 67.704 ;
     RECT  42.689 8.448 42.748 9.384 ;
     RECT  42.563 30.048 42.755 31.944 ;
     RECT  41.989 60.096 42.757 60.264 ;
     RECT  41.861 14.976 42.793 17.64 ;
     RECT  42.421 18.72 42.793 24.36 ;
     RECT  42.707 10.848 42.805 10.872 ;
     RECT  42.707 3.312 42.851 3.432 ;
     RECT  42.793 14.976 42.851 17.688 ;
     RECT  42.757 59.28 42.853 60.264 ;
     RECT  42.361 62.16 42.853 62.184 ;
     RECT  42.793 18.72 42.865 25.176 ;
     RECT  42.613 26.208 42.865 28.968 ;
     RECT  40.601 37.968 42.865 38.28 ;
     RECT  42.865 37.968 42.901 38.76 ;
     RECT  42.577 63.36 42.901 64.728 ;
     RECT  42.613 74.688 42.94 75.48 ;
     RECT  42.509 52.128 42.941 53.016 ;
     RECT  42.853 59.28 42.941 62.184 ;
     RECT  42.865 18.72 42.947 28.968 ;
     RECT  42.707 1.776 42.977 2.328 ;
     RECT  42.805 10.848 42.985 11.448 ;
     RECT  42.257 4.56 43.013 7.08 ;
     RECT  42.901 37.008 43.045 38.76 ;
     RECT  42.509 50.832 43.049 51 ;
     RECT  42.985 10.992 43.121 11.448 ;
     RECT  42.689 44.352 43.157 44.472 ;
     RECT  42.941 59.568 43.189 62.184 ;
     RECT  42.901 63.36 43.189 65.496 ;
     RECT  42.365 33.024 43.225 33.72 ;
     RECT  42.94 74.688 43.225 75.432 ;
     RECT  42.851 3.408 43.237 3.432 ;
     RECT  43.013 4.56 43.237 5.256 ;
     RECT  42.853 72.384 43.237 72.408 ;
     RECT  43.045 73.392 43.237 73.416 ;
     RECT  42.851 15.984 43.292 17.688 ;
     RECT  42.947 18.72 43.292 28.488 ;
     RECT  41.969 47.28 43.297 48.936 ;
     RECT  42.725 67.68 43.297 67.704 ;
     RECT  42.661 68.832 43.297 71.256 ;
     RECT  42.685 57.024 43.333 57.576 ;
     RECT  43.297 67.68 43.333 71.256 ;
     RECT  43.237 72.384 43.333 73.416 ;
     RECT  43.297 47.28 43.337 49.752 ;
     RECT  43.292 15.984 43.379 28.488 ;
     RECT  43.013 6.816 43.381 7.08 ;
     RECT  42.748 8.448 43.409 9.096 ;
     RECT  43.379 15.984 43.409 17.688 ;
     RECT  43.409 8.448 43.427 8.664 ;
     RECT  43.225 33.024 43.477 34.2 ;
     RECT  42.293 13.872 43.481 13.896 ;
     RECT  43.157 44.448 43.517 44.472 ;
     RECT  43.225 74.64 43.571 75.432 ;
     RECT  43.189 59.568 43.589 65.496 ;
     RECT  42.149 0.528 43.621 0.552 ;
     RECT  43.477 33.024 43.621 34.872 ;
     RECT  43.427 8.544 43.669 8.568 ;
     RECT  43.297 45.552 43.733 45.576 ;
     RECT  43.571 75.408 43.763 75.432 ;
     RECT  43.621 33.024 43.765 35.112 ;
     RECT  43.045 37.008 43.772 39 ;
     RECT  42.113 40.032 43.772 40.056 ;
     RECT  43.237 3.408 43.805 5.256 ;
     RECT  42.755 30.048 43.813 31.704 ;
     RECT  43.765 33.024 43.813 35.592 ;
     RECT  43.813 30.048 43.859 35.592 ;
     RECT  43.333 57.024 43.861 57.624 ;
     RECT  43.441 66.48 43.873 66.696 ;
     RECT  43.333 67.68 43.873 73.416 ;
     RECT  43.873 66.48 43.9 73.416 ;
     RECT  43.589 59.568 43.907 64.776 ;
     RECT  43.049 50.976 43.913 51 ;
     RECT  42.851 14.976 43.955 15 ;
     RECT  43.409 16.512 43.955 17.688 ;
     RECT  43.621 0.528 43.957 0.6 ;
     RECT  42.977 2.256 43.957 2.328 ;
     RECT  43.9 66.48 43.977 73.32 ;
     RECT  42.941 52.128 44.012 52.152 ;
     RECT  42.757 55.536 44.012 55.56 ;
     RECT  43.861 57.024 44.012 57.672 ;
     RECT  43.585 54.096 44.017 54.12 ;
     RECT  44.012 55.536 44.017 57.672 ;
     RECT  43.859 30.048 44.021 31.176 ;
     RECT  43.772 37.008 44.089 40.056 ;
     RECT  44.017 54.096 44.089 57.672 ;
     RECT  44.089 54.096 44.098 58.152 ;
     RECT  44.012 51.264 44.099 52.152 ;
     RECT  43.957 2.16 44.101 2.328 ;
     RECT  43.859 32.304 44.125 35.592 ;
     RECT  44.021 30.576 44.129 31.176 ;
     RECT  43.907 59.616 44.129 64.776 ;
     RECT  43.957 0.144 44.146 0.6 ;
     RECT  41.213 41.76 44.149 41.784 ;
     RECT  43.117 42.768 44.149 42.792 ;
     RECT  44.005 66.24 44.236 66.264 ;
     RECT  43.805 3.408 44.245 5.16 ;
     RECT  43.381 6.816 44.245 7.416 ;
     RECT  44.245 6.768 44.273 7.416 ;
     RECT  44.273 6.768 44.293 6.84 ;
     RECT  43.121 10.992 44.293 11.016 ;
     RECT  43.337 47.856 44.309 49.752 ;
     RECT  44.098 54.048 44.309 58.152 ;
     RECT  44.129 59.616 44.339 63.528 ;
     RECT  44.129 64.56 44.345 64.776 ;
     RECT  43.729 9.648 44.389 9.672 ;
     RECT  44.146 0.096 44.435 0.6 ;
     RECT  44.293 6.672 44.435 6.84 ;
     RECT  44.101 2.16 44.444 2.376 ;
     RECT  44.245 3.36 44.444 5.16 ;
     RECT  42.293 12.528 44.449 12.552 ;
     RECT  43.977 67.296 44.453 73.32 ;
     RECT  44.453 67.296 44.483 72.984 ;
     RECT  44.444 2.16 44.485 5.16 ;
     RECT  44.449 12.288 44.489 12.552 ;
     RECT  44.389 9.648 44.513 9.816 ;
     RECT  44.483 67.296 44.531 72.84 ;
     RECT  44.531 67.296 44.569 68.376 ;
     RECT  44.485 7.968 44.597 7.992 ;
     RECT  44.293 10.848 44.629 11.016 ;
     RECT  44.309 47.856 44.701 49.032 ;
     RECT  44.435 0.432 44.725 0.6 ;
     RECT  43.379 19.104 44.732 28.488 ;
     RECT  44.629 10.8 44.765 11.016 ;
     RECT  44.489 12.288 44.765 12.504 ;
     RECT  44.701 46.464 44.773 46.488 ;
     RECT  44.701 47.664 44.773 49.032 ;
     RECT  44.485 1.728 44.813 5.16 ;
     RECT  44.339 59.616 44.917 61.608 ;
     RECT  44.917 45.168 44.924 45.192 ;
     RECT  44.149 41.76 44.953 42.792 ;
     RECT  44.125 32.304 44.965 35.928 ;
     RECT  44.089 37.008 44.965 40.104 ;
     RECT  44.773 46.464 44.989 49.032 ;
     RECT  44.732 19.104 45.013 28.872 ;
     RECT  44.989 46.224 45.013 49.032 ;
     RECT  44.099 51.984 45.061 52.008 ;
     RECT  44.309 54.048 45.061 56.184 ;
     RECT  44.129 30.576 45.133 31.128 ;
     RECT  44.965 32.304 45.133 40.104 ;
     RECT  44.953 41.136 45.133 42.792 ;
     RECT  44.569 67.296 45.205 68.136 ;
     RECT  45.133 41.136 45.241 43.176 ;
     RECT  44.924 44.592 45.241 45.192 ;
     RECT  44.917 59.28 45.241 61.608 ;
     RECT  44.725 0.432 45.292 0.648 ;
     RECT  45.013 19.104 45.349 28.968 ;
     RECT  45.292 0.432 45.389 0.6 ;
     RECT  44.513 9.12 45.397 9.816 ;
     RECT  44.765 10.8 45.397 12.504 ;
     RECT  45.389 0.432 45.433 0.456 ;
     RECT  45.493 0.192 45.521 0.312 ;
     RECT  44.813 2.016 45.608 5.16 ;
     RECT  44.435 6.816 45.608 6.84 ;
     RECT  45.397 9.12 45.608 12.504 ;
     RECT  43.955 16.944 45.608 17.688 ;
     RECT  45.349 18.72 45.608 28.968 ;
     RECT  45.133 30.576 45.608 40.104 ;
     RECT  45.241 41.136 45.608 45.192 ;
     RECT  45.013 46.176 45.608 49.032 ;
     RECT  45.061 51.216 45.608 52.008 ;
     RECT  45.061 53.568 45.608 56.184 ;
     RECT  44.309 57.36 45.608 58.152 ;
     RECT  45.241 59.232 45.608 61.608 ;
     RECT  44.339 62.736 45.608 63.528 ;
     RECT  44.345 64.752 45.608 64.776 ;
     RECT  45.445 65.952 45.608 65.976 ;
     RECT  45.205 67.248 45.608 68.136 ;
     RECT  44.531 69.504 45.608 72.84 ;
     RECT  44.101 74.352 45.608 74.376 ;
     RECT  45.521 0.096 45.638 0.312 ;
     RECT  45.608 2.016 45.712 74.376 ;
     RECT  45.712 2.016 45.829 73.182 ;
     RECT  45.829 1.968 45.904 73.182 ;
     RECT  45.904 1.968 45.925 5.736 ;
     RECT  45.904 28.944 45.929 48.984 ;
     RECT  45.904 25.488 46.067 25.752 ;
     RECT  45.904 26.88 46.115 27.912 ;
     RECT  45.929 29.232 46.156 48.984 ;
     RECT  45.925 1.728 46.181 5.736 ;
     RECT  45.904 18.72 46.217 18.744 ;
     RECT  46.067 25.536 46.217 25.752 ;
     RECT  46.156 29.52 46.217 48.984 ;
     RECT  46.217 32.4 46.259 48.984 ;
     RECT  45.904 10.8 46.261 10.872 ;
     RECT  45.904 7.44 46.289 8.184 ;
     RECT  46.181 1.728 46.309 5.256 ;
     RECT  45.904 55.536 46.325 58.008 ;
     RECT  45.904 67.296 46.325 72.264 ;
     RECT  46.217 25.536 46.361 25.704 ;
     RECT  45.904 20.112 46.397 24.216 ;
     RECT  46.325 55.536 46.397 56.28 ;
     RECT  45.638 0.192 46.405 0.312 ;
     RECT  46.309 1.44 46.405 5.256 ;
     RECT  46.259 32.544 46.469 48.984 ;
     RECT  46.469 45.552 46.505 48.984 ;
     RECT  46.397 23.616 46.595 24.216 ;
     RECT  46.325 71.664 46.613 72.264 ;
     RECT  45.904 65.52 46.643 66.024 ;
     RECT  46.325 67.296 46.643 68.616 ;
     RECT  46.643 67.776 46.684 68.376 ;
     RECT  46.261 10.8 46.685 10.824 ;
     RECT  46.405 0.192 46.693 5.256 ;
     RECT  46.505 47.328 46.739 48.984 ;
     RECT  46.505 45.552 46.78 45.576 ;
     RECT  45.904 51.216 46.829 54.36 ;
     RECT  46.325 69.792 46.829 70.632 ;
     RECT  46.613 71.904 46.901 72.264 ;
     RECT  46.693 0.144 46.937 5.256 ;
     RECT  46.901 71.952 46.969 72.264 ;
     RECT  46.397 20.112 46.973 22.488 ;
     RECT  46.937 0.144 47.074 5.208 ;
     RECT  46.739 47.328 47.153 47.88 ;
     RECT  45.904 60.288 47.153 63.72 ;
     RECT  46.469 32.544 47.225 43.944 ;
     RECT  47.225 41.664 47.261 43.944 ;
     RECT  46.217 29.52 47.315 31.416 ;
     RECT  47.261 41.664 47.333 42.552 ;
     RECT  45.904 50.16 47.333 50.184 ;
     RECT  47.153 62.64 47.333 63.72 ;
     RECT  47.074 0.096 47.341 5.208 ;
     RECT  46.289 8.16 47.365 8.184 ;
     RECT  46.397 55.968 47.365 56.28 ;
     RECT  46.739 48.912 47.369 48.984 ;
     RECT  46.969 71.952 47.369 72.408 ;
     RECT  46.325 57.984 47.372 58.008 ;
     RECT  47.372 57.984 47.413 58.056 ;
     RECT  47.365 7.44 47.449 8.184 ;
     RECT  47.449 8.16 47.461 8.184 ;
     RECT  47.261 43.536 47.461 43.944 ;
     RECT  47.369 48.96 47.477 48.984 ;
     RECT  47.341 2.256 47.555 5.208 ;
     RECT  47.365 55.488 47.581 56.28 ;
     RECT  47.413 57.984 47.581 58.488 ;
     RECT  47.315 29.52 47.585 30.84 ;
     RECT  46.595 23.616 47.653 23.784 ;
     RECT  47.333 62.976 47.689 63.72 ;
     RECT  47.401 64.704 47.689 64.728 ;
     RECT  46.361 25.68 47.725 25.704 ;
     RECT  46.115 26.88 47.725 26.904 ;
     RECT  47.225 32.544 47.729 40.296 ;
     RECT  47.585 30.72 47.765 30.84 ;
     RECT  47.725 25.68 47.797 26.904 ;
     RECT  46.643 65.904 47.833 66.024 ;
     RECT  47.761 6.816 47.845 6.936 ;
     RECT  47.461 8.16 47.861 8.664 ;
     RECT  47.729 36.48 47.909 40.296 ;
     RECT  45.904 12.288 47.941 12.504 ;
     RECT  46.973 20.592 47.977 22.488 ;
     RECT  47.653 23.616 47.977 23.832 ;
     RECT  47.797 25.296 47.977 26.904 ;
     RECT  47.861 8.16 48.013 9.336 ;
     RECT  47.473 10.416 48.013 10.44 ;
     RECT  47.729 32.544 48.013 35.352 ;
     RECT  47.333 41.664 48.035 42.456 ;
     RECT  47.977 20.592 48.061 26.904 ;
     RECT  47.555 2.832 48.085 5.208 ;
     RECT  47.833 45.6 48.085 45.624 ;
     RECT  47.581 55.488 48.085 58.488 ;
     RECT  47.461 43.536 48.157 44.472 ;
     RECT  48.085 45.6 48.157 46.488 ;
     RECT  48.061 25.056 48.172 26.904 ;
     RECT  47.341 0.096 48.179 1.176 ;
     RECT  46.829 69.792 48.233 70.584 ;
     RECT  48.233 69.792 48.301 69.816 ;
     RECT  48.013 8.16 48.305 10.44 ;
     RECT  47.369 71.952 48.305 72.264 ;
     RECT  48.035 41.664 48.323 41.784 ;
     RECT  48.085 55.488 48.332 59.304 ;
     RECT  47.153 60.288 48.332 61.608 ;
     RECT  47.765 30.816 48.371 30.84 ;
     RECT  48.157 43.536 48.373 46.632 ;
     RECT  48.085 2.832 48.377 5.736 ;
     RECT  48.013 31.824 48.412 35.352 ;
     RECT  48.172 25.152 48.413 26.904 ;
     RECT  48.332 55.488 48.419 61.608 ;
     RECT  46.829 51.216 48.445 52.776 ;
     RECT  46.829 54.144 48.445 54.36 ;
     RECT  47.909 36.48 48.449 40.056 ;
     RECT  48.419 60.288 48.449 61.608 ;
     RECT  47.833 65.808 48.449 66.024 ;
     RECT  48.445 51.216 48.469 54.36 ;
     RECT  48.419 55.488 48.469 59.304 ;
     RECT  47.845 6.912 48.485 6.936 ;
     RECT  48.412 31.824 48.485 33.48 ;
     RECT  48.469 51.216 48.529 59.304 ;
     RECT  48.179 0.096 48.563 0.552 ;
     RECT  48.529 51.216 48.593 52.776 ;
     RECT  48.529 54.144 48.593 59.304 ;
     RECT  48.593 54.384 48.611 59.304 ;
     RECT  48.449 36.864 48.629 40.056 ;
     RECT  48.305 8.544 48.661 10.44 ;
     RECT  47.941 11.808 48.661 12.504 ;
     RECT  48.517 67.056 48.661 67.08 ;
     RECT  46.684 68.352 48.661 68.376 ;
     RECT  48.413 25.296 48.665 26.904 ;
     RECT  48.377 2.832 48.689 5.16 ;
     RECT  48.689 2.352 48.772 5.16 ;
     RECT  47.653 18.96 48.773 18.984 ;
     RECT  48.412 34.464 48.851 35.352 ;
     RECT  46.115 27.888 48.901 27.912 ;
     RECT  47.905 29.472 48.901 29.496 ;
     RECT  48.665 26.016 48.917 26.904 ;
     RECT  48.373 43.536 48.917 46.68 ;
     RECT  48.841 41.04 48.953 41.064 ;
     RECT  47.689 62.976 48.977 64.728 ;
     RECT  48.611 54.72 48.989 59.304 ;
     RECT  48.901 27.888 49.043 29.496 ;
     RECT  48.061 20.592 49.057 23.928 ;
     RECT  48.989 54.912 49.097 59.304 ;
     RECT  47.153 47.664 49.129 47.88 ;
     RECT  48.661 67.056 49.165 68.376 ;
     RECT  48.301 69.504 49.165 69.816 ;
     RECT  48.661 8.544 49.177 12.504 ;
     RECT  48.977 62.976 49.201 64.776 ;
     RECT  48.449 65.808 49.201 65.928 ;
     RECT  48.661 7.44 49.273 7.464 ;
     RECT  49.165 67.056 49.283 69.816 ;
     RECT  48.772 2.304 49.381 5.16 ;
     RECT  49.057 20.592 49.445 24.168 ;
     RECT  49.381 1.728 49.477 5.736 ;
     RECT  49.201 62.976 49.477 65.928 ;
     RECT  49.283 67.776 49.525 69.816 ;
     RECT  48.373 70.992 49.525 71.304 ;
     RECT  49.477 1.728 49.571 5.88 ;
     RECT  48.563 0.096 49.573 0.12 ;
     RECT  49.571 3.36 49.573 5.88 ;
     RECT  49.273 7.44 49.573 7.8 ;
     RECT  49.525 67.776 49.573 71.304 ;
     RECT  49.573 67.776 49.619 71.832 ;
     RECT  49.571 1.728 49.667 2.28 ;
     RECT  49.477 62.976 49.669 66.744 ;
     RECT  49.445 20.592 49.705 25.032 ;
     RECT  48.625 50.112 49.705 50.136 ;
     RECT  49.097 57.456 49.765 59.304 ;
     RECT  48.449 60.288 49.765 61.176 ;
     RECT  49.573 0.096 49.813 0.168 ;
     RECT  48.629 36.864 49.817 39.576 ;
     RECT  49.669 62.784 49.817 66.744 ;
     RECT  49.177 9.072 49.849 12.504 ;
     RECT  49.765 57.456 49.849 61.176 ;
     RECT  49.817 62.784 49.849 66.072 ;
     RECT  49.705 49.248 49.853 50.136 ;
     RECT  48.485 32.544 49.877 33.48 ;
     RECT  49.705 20.592 49.921 25.608 ;
     RECT  49.817 36.864 49.925 36.888 ;
     RECT  49.849 57.456 49.925 66.072 ;
     RECT  48.917 26.784 50.029 26.904 ;
     RECT  49.043 27.888 50.029 28.488 ;
     RECT  49.925 57.456 50.044 59.016 ;
     RECT  50.029 26.784 50.137 28.488 ;
     RECT  49.921 29.52 50.137 29.784 ;
     RECT  50.029 41.616 50.137 41.64 ;
     RECT  49.849 9.072 50.149 12.552 ;
     RECT  49.619 71.808 50.149 71.832 ;
     RECT  49.817 38.112 50.173 39.576 ;
     RECT  50.137 41.424 50.173 41.688 ;
     RECT  48.917 43.536 50.173 45.624 ;
     RECT  50.173 43.536 50.245 45.72 ;
     RECT  49.129 46.752 50.245 47.88 ;
     RECT  48.593 51.408 50.252 52.776 ;
     RECT  49.097 54.912 50.252 56.328 ;
     RECT  49.573 3.36 50.273 7.8 ;
     RECT  50.149 9.072 50.273 12.792 ;
     RECT  50.137 26.784 50.348 29.784 ;
     RECT  48.851 35.328 50.389 35.352 ;
     RECT  50.348 26.592 50.437 29.784 ;
     RECT  50.293 30.768 50.437 30.792 ;
     RECT  49.667 2.064 50.54 2.28 ;
     RECT  50.273 3.36 50.54 12.792 ;
     RECT  50.245 43.536 50.569 47.88 ;
     RECT  49.853 49.248 50.569 49.272 ;
     RECT  49.619 67.776 50.616 70.152 ;
     RECT  50.252 51.408 50.636 53.496 ;
     RECT  50.54 2.064 50.641 12.792 ;
     RECT  50.641 2.064 50.677 13.08 ;
     RECT  45.904 16.944 50.677 17.208 ;
     RECT  48.805 18.768 50.677 18.792 ;
     RECT  49.921 19.776 50.677 25.608 ;
     RECT  50.437 26.592 50.684 30.792 ;
     RECT  49.813 0.096 50.713 0.216 ;
     RECT  50.677 1.728 50.713 13.08 ;
     RECT  50.677 16.944 50.749 17.4 ;
     RECT  49.877 32.544 50.78 33.624 ;
     RECT  50.389 35.328 50.78 36.264 ;
     RECT  50.749 16.848 50.821 17.4 ;
     RECT  50.78 32.544 50.821 36.264 ;
     RECT  50.569 43.536 50.821 49.272 ;
     RECT  50.636 51.408 50.829 53.544 ;
     RECT  50.677 18.768 50.849 25.608 ;
     RECT  50.684 26.592 50.849 31.128 ;
     RECT  50.713 0.096 50.869 13.08 ;
     RECT  50.849 18.768 50.869 31.128 ;
     RECT  50.821 32.208 50.869 36.264 ;
     RECT  50.829 51.408 50.869 53.592 ;
     RECT  50.252 54.912 50.869 56.52 ;
     RECT  50.821 43.536 50.965 49.608 ;
     RECT  50.869 50.832 50.965 53.592 ;
     RECT  50.869 0.096 51.008 13.272 ;
     RECT  50.869 15.84 51.008 15.864 ;
     RECT  50.821 16.848 51.008 17.64 ;
     RECT  50.869 18.768 51.008 36.264 ;
     RECT  50.173 38.112 51.008 39.816 ;
     RECT  50.173 41.28 51.008 41.688 ;
     RECT  50.965 43.536 51.008 53.592 ;
     RECT  50.869 54.72 51.008 56.52 ;
     RECT  50.044 57.504 51.008 59.016 ;
     RECT  49.925 60.096 51.008 66.072 ;
     RECT  50.616 67.584 51.008 70.152 ;
     RECT  50.149 71.808 51.008 71.88 ;
     RECT  45.712 74.352 51.008 74.376 ;
     RECT  51.008 0.096 51.059 74.376 ;
     RECT  51.059 1.92 51.112 74.376 ;
     RECT  51.112 1.92 51.251 73.182 ;
     RECT  51.251 2.064 51.304 73.182 ;
     RECT  51.304 63.792 51.437 65.256 ;
     RECT  51.304 54.72 51.443 62.184 ;
     RECT  51.443 55.008 51.491 62.184 ;
     RECT  51.437 64.944 51.491 65.256 ;
     RECT  51.491 55.2 51.539 62.184 ;
     RECT  51.304 49.248 51.833 49.272 ;
     RECT  51.304 68.976 51.869 69.24 ;
     RECT  51.304 20.16 51.905 36.264 ;
     RECT  51.905 20.16 51.971 34.968 ;
     RECT  51.304 50.304 52.085 52.488 ;
     RECT  51.905 36 52.157 36.264 ;
     RECT  51.539 56.976 52.163 57.624 ;
     RECT  51.437 63.792 52.163 63.864 ;
     RECT  51.304 43.536 52.193 46.872 ;
     RECT  51.304 2.064 52.253 13.08 ;
     RECT  51.304 40.944 52.3 42.456 ;
     RECT  51.304 53.568 52.301 53.592 ;
     RECT  52.163 63.792 52.301 63.816 ;
     RECT  51.539 58.704 52.307 62.184 ;
     RECT  51.304 14.064 52.333 15.864 ;
     RECT  51.304 16.848 52.333 17.64 ;
     RECT  51.539 55.2 52.373 55.8 ;
     RECT  52.085 50.304 52.405 50.328 ;
     RECT  52.253 1.728 52.412 13.08 ;
     RECT  52.333 14.064 52.412 17.64 ;
     RECT  51.971 20.16 52.451 25.752 ;
     RECT  52.193 45.696 52.477 46.872 ;
     RECT  51.304 47.856 52.477 48.264 ;
     RECT  52.412 1.728 52.501 17.64 ;
     RECT  51.304 18.912 52.501 18.984 ;
     RECT  52.451 20.16 52.501 21.192 ;
     RECT  51.304 67.632 52.513 67.704 ;
     RECT  52.405 49.584 52.553 50.328 ;
     RECT  51.971 26.784 52.589 34.968 ;
     RECT  51.491 65.232 52.589 65.256 ;
     RECT  51.304 38.112 52.693 38.136 ;
     RECT  51.304 39.264 52.693 39.816 ;
     RECT  52.513 66.768 52.697 67.704 ;
     RECT  52.477 45.696 52.787 48.264 ;
     RECT  52.589 26.784 52.877 34.92 ;
     RECT  51.059 0.096 52.933 0.552 ;
     RECT  52.501 1.728 52.933 21.192 ;
     RECT  52.373 55.44 52.945 55.8 ;
     RECT  52.787 47.376 52.949 48.264 ;
     RECT  52.3 41.568 52.953 42.456 ;
     RECT  52.193 43.536 52.953 44.472 ;
     RECT  52.953 41.568 52.985 44.472 ;
     RECT  52.985 41.568 53.027 43.896 ;
     RECT  52.451 22.224 53.029 25.752 ;
     RECT  52.877 26.784 53.029 34.824 ;
     RECT  52.163 57.456 53.029 57.624 ;
     RECT  52.307 58.704 53.029 59.736 ;
     RECT  53.027 43.008 53.068 43.896 ;
     RECT  53.029 57.456 53.075 59.736 ;
     RECT  53.029 22.224 53.116 34.824 ;
     RECT  52.693 38.112 53.129 40.2 ;
     RECT  52.085 51.504 53.237 52.488 ;
     RECT  52.933 0.096 53.267 21.192 ;
     RECT  52.949 47.376 53.273 47.88 ;
     RECT  53.267 3.36 53.345 21.192 ;
     RECT  53.273 47.856 53.345 47.88 ;
     RECT  52.787 45.696 53.363 46.344 ;
     RECT  52.945 63.264 53.377 63.288 ;
     RECT  52.157 36 53.381 36.024 ;
     RECT  52.697 67.68 53.381 67.704 ;
     RECT  53.345 3.36 53.417 17.208 ;
     RECT  53.345 18.24 53.557 21.192 ;
     RECT  53.116 22.224 53.557 24.456 ;
     RECT  53.027 41.616 53.561 41.64 ;
     RECT  53.116 25.728 53.597 34.824 ;
     RECT  53.597 25.728 53.633 33.048 ;
     RECT  53.597 34.08 53.692 34.824 ;
     RECT  53.557 18.24 53.777 24.456 ;
     RECT  53.692 34.176 53.881 34.824 ;
     RECT  53.075 57.936 53.881 59.736 ;
     RECT  52.307 60.864 53.881 62.184 ;
     RECT  52.553 49.584 53.885 50.088 ;
     RECT  51.112 74.352 53.885 74.376 ;
     RECT  53.777 18.96 53.891 24.456 ;
     RECT  53.068 43.824 53.993 43.896 ;
     RECT  53.129 38.112 54.035 39.288 ;
     RECT  53.881 57.936 54.085 62.184 ;
     RECT  53.377 63.264 54.085 63.96 ;
     RECT  54.035 38.688 54.131 39.288 ;
     RECT  53.885 50.016 54.133 50.088 ;
     RECT  53.267 0.096 54.229 2.28 ;
     RECT  53.417 3.36 54.229 16.872 ;
     RECT  54.085 57.936 54.281 63.96 ;
     RECT  54.133 50.016 54.284 50.424 ;
     RECT  53.237 51.6 54.332 52.488 ;
     RECT  54.097 53.52 54.332 53.544 ;
     RECT  54.284 50.016 54.371 50.568 ;
     RECT  53.993 43.872 54.373 43.896 ;
     RECT  54.332 51.6 54.373 53.544 ;
     RECT  54.325 48.96 54.412 48.984 ;
     RECT  54.373 43.872 54.419 44.664 ;
     RECT  54.373 51.6 54.419 54.12 ;
     RECT  53.881 34.176 54.421 34.92 ;
     RECT  54.229 0.096 54.46 16.872 ;
     RECT  54.419 44.64 54.493 44.664 ;
     RECT  53.363 45.696 54.493 46.152 ;
     RECT  54.131 38.688 54.497 38.712 ;
     RECT  54.371 50.4 54.497 50.424 ;
     RECT  54.421 34.176 54.569 35.352 ;
     RECT  53.633 31.2 54.62 33.048 ;
     RECT  53.633 25.728 54.637 29.832 ;
     RECT  54.281 57.936 54.673 63.288 ;
     RECT  54.637 25.632 54.749 29.832 ;
     RECT  54.673 57.072 54.817 63.288 ;
     RECT  53.891 19.008 54.853 24.456 ;
     RECT  54.853 18.192 54.899 24.456 ;
     RECT  54.493 44.64 54.961 46.152 ;
     RECT  54.899 18.192 54.965 19.224 ;
     RECT  53.665 36.912 54.965 36.936 ;
     RECT  52.945 55.44 54.965 55.944 ;
     RECT  54.965 55.44 54.995 55.8 ;
     RECT  54.46 0.048 55.073 16.872 ;
     RECT  55.073 6.24 55.093 16.872 ;
     RECT  54.961 44.64 55.105 46.248 ;
     RECT  54.749 27.744 55.177 29.832 ;
     RECT  54.62 30.864 55.177 33.048 ;
     RECT  55.177 27.744 55.181 33.048 ;
     RECT  54.817 56.976 55.283 63.288 ;
     RECT  54.965 18.192 55.289 19.032 ;
     RECT  55.105 44.64 55.325 46.584 ;
     RECT  55.283 62.448 55.325 63.288 ;
     RECT  55.181 27.744 55.379 30.936 ;
     RECT  55.285 49.296 55.429 49.32 ;
     RECT  54.419 51.6 55.429 51.624 ;
     RECT  54.899 20.544 55.573 24.456 ;
     RECT  55.325 45.216 55.573 46.584 ;
     RECT  54.569 34.176 55.645 34.2 ;
     RECT  54.569 35.328 55.645 35.352 ;
     RECT  54.085 40.656 55.645 40.68 ;
     RECT  55.724 43.344 55.753 43.368 ;
     RECT  55.645 40.656 55.765 41.016 ;
     RECT  55.645 34.176 55.772 35.352 ;
     RECT  55.181 31.92 55.813 33.048 ;
     RECT  55.772 34.08 55.813 35.352 ;
     RECT  55.093 6.24 55.82 17.112 ;
     RECT  55.289 18.192 55.82 18.792 ;
     RECT  55.429 48.336 55.861 49.32 ;
     RECT  55.813 31.92 56.005 35.352 ;
     RECT  55.964 36.576 56.005 36.6 ;
     RECT  55.073 0.048 56.053 5.256 ;
     RECT  55.82 6.24 56.053 18.792 ;
     RECT  55.429 51.168 56.113 51.624 ;
     RECT  55.283 56.976 56.329 61.416 ;
     RECT  55.325 62.448 56.329 63.096 ;
     RECT  56.053 0.048 56.408 18.792 ;
     RECT  55.573 20.544 56.408 24.648 ;
     RECT  54.749 25.632 56.408 26.616 ;
     RECT  55.379 27.744 56.408 30.888 ;
     RECT  56.005 31.92 56.408 36.6 ;
     RECT  55.765 40.656 56.408 41.4 ;
     RECT  55.753 43.344 56.408 43.896 ;
     RECT  55.573 45.216 56.408 46.776 ;
     RECT  55.861 48.336 56.408 49.56 ;
     RECT  56.113 51.168 56.408 52.536 ;
     RECT  54.419 53.52 56.408 54.12 ;
     RECT  54.995 55.776 56.408 55.8 ;
     RECT  56.329 56.976 56.408 63.096 ;
     RECT  51.869 69.216 56.408 69.24 ;
     RECT  56.408 0.048 56.512 73.452 ;
     RECT  56.512 0.048 56.704 73.182 ;
     RECT  56.704 0.048 56.819 14.04 ;
     RECT  56.704 25.728 56.819 33.048 ;
     RECT  56.704 44.88 56.819 46.728 ;
     RECT  56.704 47.856 56.867 48.168 ;
     RECT  56.704 49.536 56.867 51.384 ;
     RECT  56.819 25.728 56.873 32.472 ;
     RECT  56.704 15.408 56.981 18.216 ;
     RECT  56.704 52.704 57.017 53.592 ;
     RECT  56.704 34.08 57.203 37.32 ;
     RECT  56.704 54.96 57.233 64.44 ;
     RECT  56.873 25.728 57.269 30.84 ;
     RECT  56.867 49.536 57.269 51.288 ;
     RECT  56.873 32.016 57.305 32.472 ;
     RECT  57.017 53.232 57.305 53.592 ;
     RECT  56.819 0.048 57.341 4.008 ;
     RECT  56.704 43.344 57.413 43.896 ;
     RECT  57.269 50.688 57.485 51.288 ;
     RECT  57.203 34.752 57.521 37.32 ;
     RECT  56.819 45.696 57.565 46.728 ;
     RECT  57.233 62.928 57.587 64.44 ;
     RECT  56.981 16.848 57.629 18.216 ;
     RECT  56.819 5.136 57.635 14.04 ;
     RECT  57.233 54.96 57.635 61.608 ;
     RECT  57.565 45.696 57.665 46.536 ;
     RECT  57.635 54.96 57.683 54.984 ;
     RECT  56.704 69.216 57.683 69.24 ;
     RECT  57.521 35.28 57.697 37.32 ;
     RECT  57.413 43.344 57.701 43.608 ;
     RECT  57.629 17.088 57.745 18.216 ;
     RECT  57.635 5.136 57.773 13.176 ;
     RECT  57.269 25.728 57.845 29.064 ;
     RECT  57.745 17.088 57.881 17.64 ;
     RECT  57.635 56.352 57.953 61.608 ;
     RECT  57.697 35.28 57.985 37.368 ;
     RECT  57.269 49.536 57.989 49.56 ;
     RECT  57.697 33.552 58.025 33.576 ;
     RECT  57.953 58.992 58.025 61.608 ;
     RECT  57.953 56.352 58.061 57.864 ;
     RECT  57.845 27.408 58.097 29.064 ;
     RECT  58.061 56.496 58.115 57.864 ;
     RECT  57.985 35.28 58.129 37.656 ;
     RECT  57.341 0.048 58.205 3.048 ;
     RECT  56.981 15.408 58.205 15.432 ;
     RECT  58.205 0.192 58.277 3.048 ;
     RECT  57.269 30.384 58.309 30.84 ;
     RECT  57.305 32.448 58.309 32.472 ;
     RECT  58.129 35.28 58.309 37.896 ;
     RECT  58.277 0.192 58.313 1.272 ;
     RECT  56.867 48.144 58.381 48.168 ;
     RECT  57.587 62.928 58.385 63.816 ;
     RECT  56.704 20.688 58.453 24.648 ;
     RECT  57.845 25.728 58.453 26.376 ;
     RECT  58.309 30.384 58.525 32.472 ;
     RECT  57.305 53.568 58.525 53.592 ;
     RECT  58.025 58.992 58.529 60.168 ;
     RECT  58.313 0.192 58.565 0.84 ;
     RECT  58.453 20.688 58.565 26.376 ;
     RECT  58.565 22.176 58.601 26.376 ;
     RECT  57.665 45.696 58.601 46.248 ;
     RECT  58.381 47.856 58.669 48.168 ;
     RECT  57.485 51.12 58.669 51.288 ;
     RECT  58.309 35.28 58.741 38.136 ;
     RECT  58.565 0.288 58.745 0.84 ;
     RECT  58.525 30.288 58.777 32.472 ;
     RECT  58.277 2.304 58.781 3.048 ;
     RECT  57.773 6.048 58.921 13.176 ;
     RECT  58.745 0.288 58.997 0.312 ;
     RECT  58.601 22.176 59.033 26.328 ;
     RECT  58.025 61.584 59.101 61.608 ;
     RECT  58.781 3.024 59.105 3.048 ;
     RECT  58.921 6.048 59.141 13.656 ;
     RECT  58.741 35.28 59.209 38.568 ;
     RECT  59.209 35.28 59.245 38.712 ;
     RECT  58.669 47.856 59.245 48.456 ;
     RECT  58.669 51.072 59.281 51.288 ;
     RECT  58.525 53.568 59.317 54.168 ;
     RECT  57.881 17.616 59.321 17.64 ;
     RECT  58.565 20.688 59.321 21.144 ;
     RECT  58.529 59.232 59.357 60.168 ;
     RECT  59.033 22.176 59.363 23.448 ;
     RECT  58.115 56.496 59.381 57.192 ;
     RECT  59.381 56.4 59.42 57.192 ;
     RECT  59.317 53.52 59.425 54.168 ;
     RECT  58.601 45.696 59.509 46.152 ;
     RECT  59.321 20.784 59.555 21.144 ;
     RECT  59.141 6.288 59.573 13.656 ;
     RECT  59.509 45.168 59.596 46.152 ;
     RECT  59.425 53.28 59.605 54.168 ;
     RECT  59.281 51.072 59.641 51.528 ;
     RECT  59.605 53.088 59.641 54.168 ;
     RECT  57.701 43.584 59.713 43.608 ;
     RECT  59.641 50.736 59.713 51.528 ;
     RECT  59.641 52.8 59.713 54.168 ;
     RECT  59.101 61.584 59.713 61.656 ;
     RECT  58.097 27.408 59.749 28.968 ;
     RECT  58.777 30.288 59.749 33.336 ;
     RECT  59.357 59.232 59.797 59.256 ;
     RECT  59.713 50.736 59.825 54.168 ;
     RECT  59.713 60.24 59.843 61.656 ;
     RECT  59.42 55.92 59.845 57.192 ;
     RECT  59.843 60.96 59.845 61.656 ;
     RECT  59.245 47.328 59.891 48.456 ;
     RECT  59.845 60.96 59.893 62.808 ;
     RECT  58.385 63.792 59.893 63.816 ;
     RECT  59.813 14.832 59.897 14.856 ;
     RECT  59.893 60.96 59.939 63.816 ;
     RECT  59.596 45.552 59.969 46.152 ;
     RECT  56.704 41.376 60.001 41.4 ;
     RECT  59.033 24.624 60.037 26.328 ;
     RECT  59.825 50.736 60.041 53.976 ;
     RECT  59.845 55.824 60.041 57.24 ;
     RECT  59.797 59.184 60.073 59.256 ;
     RECT  59.363 23.424 60.109 23.448 ;
     RECT  60.037 24.432 60.109 26.328 ;
     RECT  59.891 47.328 60.14 48.408 ;
     RECT  59.573 6.288 60.149 7.944 ;
     RECT  59.713 43.584 60.149 43.944 ;
     RECT  60.14 46.8 60.227 48.408 ;
     RECT  59.749 27.408 60.253 33.336 ;
     RECT  59.245 34.656 60.253 38.712 ;
     RECT  59.939 62.16 60.257 63.816 ;
     RECT  59.555 21.12 60.325 21.144 ;
     RECT  59.363 22.176 60.325 22.2 ;
     RECT  60.001 41.376 60.325 41.496 ;
     RECT  60.149 6.384 60.329 7.944 ;
     RECT  60.325 21.12 60.365 22.2 ;
     RECT  60.109 23.424 60.397 26.328 ;
     RECT  60.253 27.408 60.397 38.712 ;
     RECT  60.257 62.16 60.419 63.288 ;
     RECT  60.041 56.064 60.505 57.24 ;
     RECT  60.073 58.704 60.505 59.256 ;
     RECT  59.573 8.976 60.545 13.656 ;
     RECT  60.325 41.184 60.577 41.496 ;
     RECT  60.227 47.328 60.617 48.408 ;
     RECT  60.577 40.944 60.709 41.496 ;
     RECT  60.149 43.872 60.721 43.944 ;
     RECT  60.041 50.736 60.757 51.192 ;
     RECT  60.721 43.872 60.761 43.992 ;
     RECT  60.041 52.416 60.865 53.976 ;
     RECT  60.365 21.264 60.901 22.2 ;
     RECT  60.397 23.424 60.901 38.76 ;
     RECT  60.709 40.848 60.973 41.496 ;
     RECT  60.545 8.976 61.081 13.416 ;
     RECT  60.901 21.264 61.141 38.76 ;
     RECT  60.973 39.936 61.141 41.496 ;
     RECT  60.329 6.384 61.405 7.656 ;
     RECT  61.141 21.264 61.405 41.496 ;
     RECT  60.757 50.688 61.436 51.192 ;
     RECT  61.405 6.384 61.477 7.944 ;
     RECT  61.081 8.928 61.477 13.416 ;
     RECT  61.405 21.12 61.765 41.496 ;
     RECT  60.505 56.064 61.801 59.256 ;
     RECT  61.477 6.384 61.808 13.416 ;
     RECT  60.181 16.032 61.808 16.056 ;
     RECT  61.765 21.12 61.808 41.784 ;
     RECT  60.761 43.92 61.808 43.992 ;
     RECT  59.969 45.552 61.808 45.816 ;
     RECT  60.617 47.76 61.808 48.408 ;
     RECT  61.436 49.92 61.808 51.192 ;
     RECT  60.865 52.416 61.808 54.696 ;
     RECT  61.801 56.064 61.808 59.304 ;
     RECT  59.939 60.96 61.808 60.984 ;
     RECT  60.419 62.16 61.808 63.096 ;
     RECT  61.808 2.148 61.912 73.452 ;
     RECT  61.912 2.418 62.104 73.182 ;
     RECT  62.104 56.064 62.165 56.616 ;
     RECT  62.104 61.872 62.273 63.096 ;
     RECT  62.104 21.12 62.345 39.816 ;
     RECT  62.104 45.552 62.435 46.776 ;
     RECT  62.165 56.592 62.741 56.616 ;
     RECT  62.104 47.856 62.777 49.08 ;
     RECT  62.435 45.696 62.963 46.776 ;
     RECT  62.104 59.232 63.097 59.304 ;
     RECT  62.963 45.696 63.101 45.72 ;
     RECT  62.104 50.64 63.133 54.696 ;
     RECT  63.133 50.4 63.169 54.696 ;
     RECT  62.963 46.704 63.173 46.776 ;
     RECT  63.169 50.4 63.173 55.032 ;
     RECT  63.173 46.704 63.245 46.728 ;
     RECT  62.345 21.504 63.251 39.816 ;
     RECT  63.251 21.648 63.313 39.816 ;
     RECT  62.104 40.896 63.313 41.928 ;
     RECT  63.241 56.976 63.493 57 ;
     RECT  63.097 59.232 63.493 59.88 ;
     RECT  63.493 56.976 63.539 59.88 ;
     RECT  63.539 57.84 63.58 59.88 ;
     RECT  62.777 47.856 63.637 48.84 ;
     RECT  63.58 58.656 63.677 59.88 ;
     RECT  63.637 47.712 63.713 48.84 ;
     RECT  62.273 61.872 63.733 62.184 ;
     RECT  63.677 59.856 63.779 59.88 ;
     RECT  63.733 61.344 63.781 62.184 ;
     RECT  63.781 61.344 63.821 62.664 ;
     RECT  63.173 52.032 63.923 55.032 ;
     RECT  63.313 21.648 64.321 41.928 ;
     RECT  64.321 21.072 64.537 41.928 ;
     RECT  63.173 50.4 64.573 50.664 ;
     RECT  63.923 52.464 64.577 55.032 ;
     RECT  63.713 47.712 64.685 47.928 ;
     RECT  64.573 50.4 64.717 51.336 ;
     RECT  64.717 50.16 64.897 51.336 ;
     RECT  64.577 52.464 64.897 54.648 ;
     RECT  63.677 58.656 64.901 58.68 ;
     RECT  64.069 44.976 64.931 45 ;
     RECT  63.821 62.16 64.937 62.664 ;
     RECT  64.897 50.16 65.045 54.648 ;
     RECT  62.104 6.576 65.257 10.392 ;
     RECT  65.045 50.16 65.413 50.76 ;
     RECT  65.413 50.112 65.485 50.76 ;
     RECT  65.485 50.112 65.513 50.184 ;
     RECT  64.537 21.072 65.555 42.072 ;
     RECT  64.717 48.432 65.621 48.456 ;
     RECT  65.257 6.096 65.653 10.392 ;
     RECT  62.104 11.952 65.653 13.416 ;
     RECT  65.653 6.096 65.699 13.416 ;
     RECT  65.045 51.744 65.945 54.648 ;
     RECT  65.555 21.072 66.053 40.056 ;
     RECT  65.905 45.168 66.188 45.192 ;
     RECT  65.869 46.512 66.188 46.536 ;
     RECT  66.053 30.576 66.233 40.056 ;
     RECT  65.945 52.464 66.233 54.648 ;
     RECT  64.937 62.16 66.337 62.184 ;
     RECT  66.188 45.168 66.445 46.536 ;
     RECT  66.337 62.16 67.021 62.76 ;
     RECT  65.699 6.096 67.208 11.256 ;
     RECT  65.699 12.48 67.208 13.416 ;
     RECT  62.104 16.032 67.208 16.056 ;
     RECT  66.053 21.072 67.208 29.592 ;
     RECT  66.233 30.576 67.208 32.568 ;
     RECT  66.233 33.648 67.208 40.056 ;
     RECT  65.555 41.136 67.208 42.072 ;
     RECT  66.445 45.168 67.208 47.304 ;
     RECT  65.513 50.112 67.208 50.136 ;
     RECT  66.233 52.464 67.208 54.168 ;
     RECT  67.021 62.16 67.208 63.528 ;
     RECT  67.208 2.148 67.312 73.452 ;
     RECT  67.312 2.418 67.504 73.182 ;
     RECT  67.345 0.096 67.525 0.12 ;
     RECT  66.949 1.104 67.525 1.128 ;
     RECT  67.504 61.536 67.619 64.344 ;
     RECT  67.525 0.096 67.763 1.128 ;
     RECT  67.504 50.016 67.781 50.136 ;
     RECT  67.504 20.352 67.811 35.256 ;
     RECT  67.811 20.352 67.853 24.696 ;
     RECT  67.763 0.096 67.859 0.552 ;
     RECT  67.504 45.12 67.859 47.88 ;
     RECT  67.859 45.168 67.925 47.88 ;
     RECT  67.859 0.096 67.961 0.168 ;
     RECT  67.925 45.888 68.003 47.88 ;
     RECT  67.781 50.016 68.003 50.04 ;
     RECT  68.003 45.888 68.092 47.352 ;
     RECT  67.811 26.256 68.14 35.256 ;
     RECT  67.504 51.6 68.141 54.168 ;
     RECT  67.504 36.528 68.213 42.168 ;
     RECT  67.619 62.16 68.213 64.344 ;
     RECT  67.504 16.032 68.243 16.056 ;
     RECT  68.141 51.888 68.285 54.168 ;
     RECT  67.504 2.832 68.339 3.528 ;
     RECT  68.213 62.16 68.393 63.528 ;
     RECT  67.504 6.096 68.483 13.416 ;
     RECT  68.285 51.888 68.537 51.912 ;
     RECT  68.285 53.328 68.537 54.168 ;
     RECT  68.381 1.728 68.677 1.8 ;
     RECT  68.537 53.328 68.717 53.352 ;
     RECT  68.677 1.728 68.821 1.848 ;
     RECT  68.14 26.256 68.857 29.304 ;
     RECT  68.213 40.992 68.861 41.16 ;
     RECT  68.092 46.368 68.861 47.352 ;
     RECT  68.821 1.152 68.915 1.848 ;
     RECT  68.861 41.136 68.933 41.16 ;
     RECT  68.213 38.688 68.969 39.576 ;
     RECT  68.749 3.888 69.001 3.912 ;
     RECT  67.853 20.352 69.001 24.216 ;
     RECT  68.483 6.24 69.005 13.416 ;
     RECT  68.213 42.144 69.005 42.168 ;
     RECT  68.861 46.464 69.005 47.352 ;
     RECT  68.915 1.728 69.029 1.848 ;
     RECT  68.339 2.832 69.029 2.904 ;
     RECT  69.001 20.352 69.037 24.888 ;
     RECT  68.857 25.92 69.037 29.304 ;
     RECT  69.001 3.888 69.085 4.584 ;
     RECT  69.005 12.48 69.221 13.416 ;
     RECT  69.037 20.352 69.253 29.304 ;
     RECT  68.14 30.288 69.253 35.256 ;
     RECT  68.213 36.528 69.253 37.32 ;
     RECT  69.005 6.24 69.257 11.352 ;
     RECT  69.253 36.528 69.325 37.656 ;
     RECT  68.969 38.688 69.325 39.48 ;
     RECT  69.253 20.352 69.329 35.256 ;
     RECT  69.005 46.944 69.401 47.352 ;
     RECT  69.085 3.888 69.473 4.536 ;
     RECT  69.029 1.728 69.493 2.904 ;
     RECT  69.329 21.12 69.505 35.256 ;
     RECT  68.393 62.16 69.505 62.952 ;
     RECT  69.473 4.512 69.539 4.536 ;
     RECT  67.961 0.144 69.541 0.168 ;
     RECT  69.541 0.096 69.637 0.168 ;
     RECT  69.401 46.944 69.653 46.968 ;
     RECT  69.257 6.336 69.725 11.352 ;
     RECT  69.725 6.912 69.733 11.352 ;
     RECT  69.505 21.12 69.757 35.448 ;
     RECT  69.325 36.528 69.757 39.48 ;
     RECT  69.493 1.728 69.772 3.432 ;
     RECT  69.505 62.16 69.793 63.384 ;
     RECT  69.733 7.872 69.905 11.352 ;
     RECT  69.637 0.096 70.045 0.552 ;
     RECT  69.793 62.16 70.117 63.576 ;
     RECT  70.009 64.848 70.117 64.872 ;
     RECT  69.905 7.968 70.193 11.352 ;
     RECT  69.221 12.48 70.229 13.128 ;
     RECT  69.772 1.728 70.355 1.848 ;
     RECT  70.225 41.952 70.405 41.976 ;
     RECT  70.189 53.712 70.405 53.736 ;
     RECT  70.117 62.16 70.409 64.872 ;
     RECT  70.193 9.504 70.453 11.352 ;
     RECT  70.297 40.848 70.477 40.872 ;
     RECT  70.405 41.904 70.477 41.976 ;
     RECT  70.229 12.48 70.499 12.984 ;
     RECT  70.453 9.504 70.513 11.4 ;
     RECT  70.499 12.48 70.513 12.792 ;
     RECT  69.772 2.832 70.553 3.432 ;
     RECT  70.355 1.728 70.589 1.8 ;
     RECT  70.409 62.688 70.589 64.872 ;
     RECT  69.757 21.12 70.693 39.48 ;
     RECT  70.261 5.712 70.733 5.736 ;
     RECT  70.693 21.12 70.765 39.576 ;
     RECT  70.477 40.848 70.765 41.976 ;
     RECT  70.553 2.832 70.777 2.904 ;
     RECT  70.193 7.968 70.841 7.992 ;
     RECT  70.765 4.56 70.849 4.584 ;
     RECT  70.729 52.416 70.873 52.44 ;
     RECT  70.405 53.712 70.873 54.12 ;
     RECT  70.589 62.688 70.877 64.632 ;
     RECT  70.765 21.12 70.981 41.976 ;
     RECT  70.045 0.048 70.985 0.552 ;
     RECT  70.513 9.504 71.165 12.792 ;
     RECT  70.981 20.832 71.197 41.976 ;
     RECT  71.197 20.832 71.269 42.504 ;
     RECT  71.165 11.232 71.273 12.792 ;
     RECT  70.873 52.416 71.273 54.12 ;
     RECT  71.165 9.6 71.345 9.672 ;
     RECT  71.269 20.832 71.413 42.648 ;
     RECT  70.777 2.88 71.453 2.904 ;
     RECT  70.873 47.856 71.485 47.88 ;
     RECT  70.877 62.976 71.557 64.632 ;
     RECT  71.413 20.832 71.593 42.744 ;
     RECT  70.589 1.728 71.849 1.752 ;
     RECT  71.593 20.592 72.133 42.744 ;
     RECT  70.985 0.048 72.209 0.072 ;
     RECT  71.273 52.416 72.421 54.072 ;
     RECT  72.133 20.112 72.469 42.744 ;
     RECT  72.421 51.648 72.469 54.072 ;
     RECT  71.917 2.736 72.608 2.76 ;
     RECT  71.345 9.6 72.608 9.624 ;
     RECT  71.273 11.232 72.608 11.256 ;
     RECT  72.469 19.632 72.608 42.744 ;
     RECT  71.485 47.28 72.608 47.88 ;
     RECT  72.469 50.976 72.608 54.072 ;
     RECT  71.557 62.976 72.608 64.968 ;
     RECT  72.608 2.148 72.712 73.452 ;
     RECT  72.712 2.418 72.904 73.182 ;
     RECT  72.904 39.552 72.965 42.552 ;
     RECT  72.904 21.984 73.001 37.896 ;
     RECT  72.965 39.552 73.037 42.504 ;
     RECT  72.904 62.736 74.077 63.432 ;
     RECT  72.904 19.92 74.113 21 ;
     RECT  73.001 21.984 74.113 37.656 ;
     RECT  73.037 39.552 74.113 42.12 ;
     RECT  72.904 45.456 74.113 48.168 ;
     RECT  72.904 51.504 74.113 54.408 ;
     RECT  74.077 62.736 74.113 63.528 ;
     RECT  74.113 39.504 74.617 42.12 ;
     RECT  74.113 45.264 74.617 48.168 ;
     RECT  74.113 62.544 74.617 63.528 ;
     RECT  74.113 19.92 74.689 37.896 ;
     RECT  74.617 39.12 74.689 42.12 ;
     RECT  74.689 19.92 75.564 42.12 ;
     RECT  74.617 45.264 75.564 48.264 ;
     RECT  74.113 51.408 75.564 54.408 ;
     RECT  74.617 62.352 75.564 63.624 ;
    LAYER M5 ;
     RECT  67.536 0.016 70.536 0.085 ;
     RECT  67.536 0.085 70.632 0.133 ;
     RECT  39.12 0.016 56.712 0.229 ;
     RECT  39.12 0.229 56.808 0.325 ;
     RECT  67.536 0.133 70.824 0.611 ;
     RECT  39.12 0.325 56.856 0.853 ;
     RECT  67.728 0.611 70.824 1.139 ;
     RECT  39.12 0.853 57.048 1.141 ;
     RECT  39.12 1.141 57.096 1.189 ;
     RECT  0.144 1.957 0.168 2.053 ;
     RECT  68.016 1.139 70.824 2.137 ;
     RECT  7.8 2.137 7.92 2.149 ;
     RECT  2.4 2.137 2.52 2.151 ;
     RECT  13.2 2.137 13.32 2.151 ;
     RECT  18.6 2.137 18.72 2.151 ;
     RECT  24 2.137 24.12 2.151 ;
     RECT  29.4 2.137 29.52 2.151 ;
     RECT  34.8 2.137 34.92 2.151 ;
     RECT  61.8 2.137 61.92 2.151 ;
     RECT  72.6 2.137 72.72 2.151 ;
     RECT  2.4 2.151 2.712 2.197 ;
     RECT  5.088 2.149 5.112 2.197 ;
     RECT  7.8 2.149 8.28 2.197 ;
     RECT  9.36 2.149 9.384 2.197 ;
     RECT  2.4 2.197 3.048 2.245 ;
     RECT  4.32 2.197 5.112 2.245 ;
     RECT  34.8 2.151 35.112 2.293 ;
     RECT  0.144 2.053 0.216 2.437 ;
     RECT  0.144 2.437 0.264 2.629 ;
     RECT  2.4 2.245 5.496 2.725 ;
     RECT  12 2.629 12.024 2.725 ;
     RECT  13.2 2.151 13.512 2.773 ;
     RECT  2.4 2.725 5.64 2.821 ;
     RECT  0.144 2.629 0.312 2.869 ;
     RECT  39.12 1.189 57.192 2.915 ;
     RECT  2.4 2.821 6.168 3.109 ;
     RECT  29.4 2.151 29.712 3.109 ;
     RECT  2.304 3.109 6.168 3.157 ;
     RECT  7.392 2.197 10.824 3.157 ;
     RECT  34.8 2.293 35.256 3.157 ;
     RECT  11.952 2.725 12.024 3.205 ;
     RECT  13.008 2.773 13.512 3.205 ;
     RECT  29.4 3.109 29.832 3.349 ;
     RECT  36.336 2.869 36.36 3.397 ;
     RECT  36.336 3.397 37.032 3.443 ;
     RECT  2.304 3.157 10.824 3.491 ;
     RECT  67.2 2.137 70.824 3.539 ;
     RECT  9.888 3.491 10.824 3.685 ;
     RECT  11.952 3.205 13.512 3.685 ;
     RECT  32.304 2.821 32.328 3.685 ;
     RECT  33.312 2.485 33.336 3.685 ;
     RECT  34.8 3.157 35.304 3.685 ;
     RECT  32.016 3.685 32.328 3.829 ;
     RECT  33.312 3.685 35.304 3.829 ;
     RECT  0.144 2.869 0.408 3.925 ;
     RECT  32.016 3.829 35.304 3.925 ;
     RECT  39.936 2.915 57.192 4.019 ;
     RECT  39.936 4.019 56.808 4.067 ;
     RECT  31.968 3.925 35.304 4.115 ;
     RECT  40.032 4.067 56.808 4.115 ;
     RECT  0.144 3.925 0.504 4.165 ;
     RECT  33.024 4.115 35.304 4.165 ;
     RECT  9.888 3.685 13.512 4.261 ;
     RECT  31.968 4.115 32.04 4.501 ;
     RECT  29.4 3.349 30.072 4.547 ;
     RECT  69.024 3.539 70.824 4.595 ;
     RECT  37.008 3.443 37.032 4.691 ;
     RECT  40.2 4.115 56.808 4.691 ;
     RECT  2.304 3.491 8.856 5.077 ;
     RECT  9.888 4.261 13.608 5.077 ;
     RECT  31.872 4.501 32.04 5.125 ;
     RECT  33.024 4.165 35.352 5.219 ;
     RECT  16.944 4.261 16.968 5.267 ;
     RECT  40.2 4.691 56.712 5.267 ;
     RECT  29.4 4.547 29.928 5.461 ;
     RECT  15.696 5.029 15.72 5.605 ;
     RECT  28.416 5.461 29.928 5.701 ;
     RECT  30.96 5.125 32.04 5.701 ;
     RECT  2.304 5.077 13.608 5.747 ;
     RECT  69.696 4.595 70.728 5.747 ;
     RECT  38.832 5.605 38.856 5.797 ;
     RECT  40.2 5.267 46.248 5.797 ;
     RECT  15.648 5.605 15.72 5.845 ;
     RECT  67.2 3.539 67.512 6.085 ;
     RECT  34.8 5.219 35.352 6.133 ;
     RECT  65.376 6.085 65.4 6.181 ;
     RECT  33.024 5.219 33.048 6.323 ;
     RECT  28.416 5.701 32.04 6.419 ;
     RECT  47.376 5.267 56.712 6.421 ;
     RECT  14.832 5.845 15.72 6.563 ;
     RECT  38.832 5.797 46.248 6.565 ;
     RECT  18.6 2.151 18.912 6.613 ;
     RECT  28.464 6.419 32.04 6.613 ;
     RECT  61.8 2.151 62.112 6.613 ;
     RECT  61.8 6.613 62.664 6.661 ;
     RECT  47.376 6.421 57.336 6.709 ;
     RECT  0.144 4.165 0.552 6.757 ;
     RECT  47.376 6.709 57.384 6.853 ;
     RECT  37.584 6.565 46.248 6.899 ;
     RECT  67.2 6.085 68.472 6.899 ;
     RECT  69.696 5.747 69.72 6.947 ;
     RECT  65.376 6.181 65.688 7.043 ;
     RECT  0.144 6.757 0.6 7.139 ;
     RECT  67.2 6.899 67.752 7.139 ;
     RECT  34.8 6.133 35.4 7.141 ;
     RECT  2.304 5.747 13.512 7.381 ;
     RECT  14.832 6.563 15.672 7.381 ;
     RECT  59.808 6.805 59.832 7.381 ;
     RECT  37.584 6.899 40.632 7.427 ;
     RECT  28.464 6.613 32.424 7.475 ;
     RECT  47.376 6.853 58.008 7.475 ;
     RECT  47.472 7.475 58.008 7.619 ;
     RECT  34.32 7.141 35.4 7.909 ;
     RECT  61.488 6.661 62.664 7.909 ;
     RECT  2.304 7.381 15.672 7.957 ;
     RECT  33.888 7.909 35.4 8.003 ;
     RECT  38.496 7.427 40.632 8.003 ;
     RECT  70.704 5.747 70.728 8.003 ;
     RECT  32.016 7.475 32.424 8.195 ;
     RECT  21.6 7.717 21.624 8.437 ;
     RECT  59.472 7.381 59.832 8.437 ;
     RECT  65.664 7.043 65.688 8.437 ;
     RECT  21.6 8.437 22.248 8.485 ;
     RECT  24 2.151 24.312 8.485 ;
     RECT  38.496 8.003 40.512 8.485 ;
     RECT  67.2 7.139 67.704 8.485 ;
     RECT  47.472 7.619 57.48 8.675 ;
     RECT  47.904 8.675 57.48 8.773 ;
     RECT  59.04 8.437 59.832 8.965 ;
     RECT  36.432 7.957 36.456 9.013 ;
     RECT  67.2 8.485 68.376 9.013 ;
     RECT  47.904 8.773 57.96 9.061 ;
     RECT  59.04 8.965 59.976 9.061 ;
     RECT  66.96 9.013 68.376 9.061 ;
     RECT  65.568 8.437 65.688 9.109 ;
     RECT  66.96 9.061 69.576 9.109 ;
     RECT  38.448 8.485 40.512 9.155 ;
     RECT  41.664 6.899 46.248 9.155 ;
     RECT  61.44 7.909 62.664 9.155 ;
     RECT  47.904 9.061 59.976 9.157 ;
     RECT  61.44 9.155 62.472 9.157 ;
     RECT  65.568 9.109 69.576 9.203 ;
     RECT  0.144 7.139 0.552 9.299 ;
     RECT  2.304 7.957 15.816 9.347 ;
     RECT  47.904 9.157 62.472 9.347 ;
     RECT  13.008 9.347 15.816 9.395 ;
     RECT  18.6 6.613 19.128 9.493 ;
     RECT  28.464 7.475 31.032 9.539 ;
     RECT  14.88 9.395 15.816 9.589 ;
     RECT  68.832 9.203 69.576 9.637 ;
     RECT  65.568 9.203 67.512 9.779 ;
     RECT  2.304 9.347 11.928 9.827 ;
     RECT  65.664 9.779 67.512 9.827 ;
     RECT  36.432 9.013 37.128 9.877 ;
     RECT  32.16 8.195 32.424 10.069 ;
     RECT  0.144 9.299 0.504 10.115 ;
     RECT  29.4 9.539 31.032 10.115 ;
     RECT  2.304 9.827 11.448 10.307 ;
     RECT  14.88 9.589 16.008 10.307 ;
     RECT  36.432 9.877 37.608 10.307 ;
     RECT  48 9.347 62.112 10.307 ;
     RECT  21.6 8.485 24.312 10.355 ;
     RECT  37.104 10.307 37.608 10.355 ;
     RECT  66.96 9.827 67.512 10.405 ;
     RECT  68.832 9.637 70.44 10.405 ;
     RECT  20.304 7.189 20.328 10.453 ;
     RECT  13.008 9.395 13.656 10.643 ;
     RECT  37.584 10.355 37.608 10.645 ;
     RECT  38.592 9.155 40.512 10.645 ;
     RECT  37.584 10.645 40.512 10.835 ;
     RECT  42.096 9.155 46.248 10.883 ;
     RECT  18.6 9.493 19.224 10.885 ;
     RECT  20.208 10.453 20.328 10.885 ;
     RECT  59.664 10.307 62.112 11.171 ;
     RECT  66.96 10.405 70.44 11.363 ;
     RECT  2.304 10.307 11.4 11.365 ;
     RECT  38.448 10.835 40.512 11.365 ;
     RECT  0.144 10.115 0.456 11.459 ;
     RECT  22.224 10.355 24.312 11.459 ;
     RECT  42.096 10.883 43.368 11.459 ;
     RECT  44.784 10.883 45.912 11.459 ;
     RECT  48 10.307 58.68 11.459 ;
     RECT  38.448 11.365 40.68 11.461 ;
     RECT  18.6 10.885 20.328 11.509 ;
     RECT  29.4 10.115 30.984 11.509 ;
     RECT  32.16 10.069 32.52 11.509 ;
     RECT  61.584 11.171 62.112 11.555 ;
     RECT  49.536 11.459 58.68 11.893 ;
     RECT  59.664 11.171 60.504 11.893 ;
     RECT  29.4 11.509 32.52 11.941 ;
     RECT  13.008 10.643 13.608 11.987 ;
     RECT  65.664 9.827 65.688 11.987 ;
     RECT  2.304 11.365 11.688 12.035 ;
     RECT  14.88 10.307 15.816 12.035 ;
     RECT  66.96 11.363 68.856 12.035 ;
     RECT  49.536 11.893 60.504 12.131 ;
     RECT  28.512 11.941 32.52 12.179 ;
     RECT  38.448 11.461 41.016 12.179 ;
     RECT  0.192 11.459 0.456 12.275 ;
     RECT  38.448 12.179 40.776 12.371 ;
     RECT  33.888 8.003 35.208 12.515 ;
     RECT  48 11.459 48.024 12.515 ;
     RECT  13.008 11.987 13.512 12.517 ;
     RECT  42.096 11.459 42.12 12.517 ;
     RECT  43.344 11.459 43.368 12.517 ;
     RECT  0.24 12.275 0.456 12.563 ;
     RECT  23.136 11.459 24.312 12.563 ;
     RECT  42.096 12.517 43.368 12.563 ;
     RECT  66.96 12.035 68.232 12.563 ;
     RECT  0.336 12.563 0.456 12.611 ;
     RECT  28.512 12.179 30.984 12.611 ;
     RECT  31.968 12.179 32.52 12.659 ;
     RECT  2.304 12.035 11.064 12.803 ;
     RECT  49.536 12.131 59.544 12.803 ;
     RECT  14.88 12.035 15.768 12.851 ;
     RECT  18.6 11.509 20.568 12.901 ;
     RECT  15.744 12.851 15.768 12.947 ;
     RECT  28.512 12.611 30.552 12.947 ;
     RECT  31.968 12.659 32.424 12.995 ;
     RECT  70.464 11.365 70.488 12.995 ;
     RECT  0.336 12.611 0.36 13.091 ;
     RECT  34.32 12.515 35.208 13.139 ;
     RECT  50.88 12.803 59.544 13.283 ;
     RECT  40.08 12.371 40.776 13.285 ;
     RECT  38.448 12.371 39 13.523 ;
     RECT  54.912 13.283 59.544 13.621 ;
     RECT  12.048 12.517 13.512 13.715 ;
     RECT  18.144 12.901 20.568 13.715 ;
     RECT  16.848 12.901 16.872 13.909 ;
     RECT  51 13.283 53.88 14.099 ;
     RECT  40.08 13.285 40.968 14.101 ;
     RECT  42.096 12.563 42.84 14.101 ;
     RECT  2.4 12.803 11.064 14.197 ;
     RECT  15.984 13.909 16.872 14.197 ;
     RECT  18.144 13.715 20.328 14.197 ;
     RECT  31.968 12.995 32.184 14.341 ;
     RECT  33.312 13.621 33.336 14.341 ;
     RECT  54.912 13.621 59.88 14.579 ;
     RECT  52.368 14.099 53.88 14.581 ;
     RECT  55.728 14.579 59.88 14.627 ;
     RECT  38.784 13.523 39 14.629 ;
     RECT  38.352 14.629 39 14.677 ;
     RECT  40.08 14.101 42.84 14.677 ;
     RECT  38.352 14.677 42.84 14.773 ;
     RECT  31.968 14.341 33.336 14.819 ;
     RECT  2.4 14.197 11.352 14.867 ;
     RECT  15.984 14.197 20.328 14.867 ;
     RECT  37.92 14.773 42.84 14.867 ;
     RECT  52.368 14.581 53.928 14.867 ;
     RECT  55.92 14.627 59.88 14.867 ;
     RECT  52.416 14.867 53.928 14.915 ;
     RECT  34.32 13.139 35.112 14.917 ;
     RECT  28.944 12.947 30.552 15.061 ;
     RECT  2.4 14.867 11.112 15.443 ;
     RECT  2.4 15.443 2.808 15.491 ;
     RECT  28.896 15.061 30.552 15.493 ;
     RECT  12.624 13.715 13.512 15.637 ;
     RECT  37.92 14.867 39.048 15.637 ;
     RECT  37.344 15.637 39.048 15.683 ;
     RECT  52.416 14.915 53.88 15.683 ;
     RECT  4.32 15.443 11.112 15.731 ;
     RECT  16.848 14.867 16.872 15.829 ;
     RECT  37.344 15.683 37.368 15.829 ;
     RECT  51 14.099 51.312 15.829 ;
     RECT  40.08 14.867 42.84 15.973 ;
     RECT  43.92 14.965 43.944 15.973 ;
     RECT  4.848 15.731 11.112 16.019 ;
     RECT  18.48 14.867 20.328 16.019 ;
     RECT  67.2 12.563 68.232 16.067 ;
     RECT  4.848 16.019 10.728 16.115 ;
     RECT  55.92 14.867 59.544 16.213 ;
     RECT  38.352 15.683 39.048 16.405 ;
     RECT  40.08 15.973 43.944 16.405 ;
     RECT  38.352 16.405 43.944 16.451 ;
     RECT  12.24 15.637 13.512 16.453 ;
     RECT  28.224 15.493 30.552 16.499 ;
     RECT  28.224 16.499 29.712 16.595 ;
     RECT  31.968 14.819 32.28 16.595 ;
     RECT  4.848 16.115 4.92 16.691 ;
     RECT  28.944 16.595 29.712 16.787 ;
     RECT  55.872 16.213 59.544 16.837 ;
     RECT  33.312 14.819 33.336 17.029 ;
     RECT  34.32 14.917 35.352 17.029 ;
     RECT  5.952 16.115 10.728 17.077 ;
     RECT  11.712 16.453 13.512 17.077 ;
     RECT  55.584 16.837 59.544 17.077 ;
     RECT  16.272 15.829 16.872 17.123 ;
     RECT  50.88 15.829 51.312 17.123 ;
     RECT  5.664 17.077 13.512 17.171 ;
     RECT  38.352 16.451 38.376 17.171 ;
     RECT  31.968 16.595 32.04 17.557 ;
     RECT  6.864 17.171 13.512 17.603 ;
     RECT  24 12.563 24.312 17.605 ;
     RECT  25.92 13.621 25.944 17.605 ;
     RECT  30.816 16.501 30.84 17.605 ;
     RECT  31.968 17.557 32.184 17.605 ;
     RECT  45.6 11.459 45.912 17.653 ;
     RECT  33.312 17.029 35.352 17.699 ;
     RECT  36.768 15.829 37.368 17.699 ;
     RECT  37.344 17.699 37.368 17.843 ;
     RECT  29.184 16.787 29.712 18.133 ;
     RECT  52.752 15.683 53.88 18.133 ;
     RECT  30.816 17.605 32.184 18.179 ;
     RECT  18.6 16.019 20.328 18.181 ;
     RECT  55.104 17.077 59.544 18.181 ;
     RECT  7.2 17.603 13.512 18.275 ;
     RECT  39.36 16.451 43.944 18.323 ;
     RECT  33.312 17.699 33.432 18.707 ;
     RECT  24 17.605 25.944 18.757 ;
     RECT  5.664 17.171 5.688 18.851 ;
     RECT  7.344 18.275 13.512 18.851 ;
     RECT  24 18.757 26.76 18.851 ;
     RECT  33.408 18.707 33.432 18.851 ;
     RECT  18.6 18.181 21 18.949 ;
     RECT  16.272 17.123 16.296 18.995 ;
     RECT  39.36 18.323 42.552 18.995 ;
     RECT  52.512 18.133 53.88 18.995 ;
     RECT  45.36 17.653 45.912 19.285 ;
     RECT  29.184 18.133 29.832 19.427 ;
     RECT  52.512 18.995 53.064 19.475 ;
     RECT  45.264 19.285 45.912 19.573 ;
     RECT  18.48 18.949 21 19.621 ;
     RECT  72.6 2.151 72.912 19.621 ;
     RECT  43.92 18.323 43.944 19.715 ;
     RECT  38.064 18.565 38.088 19.811 ;
     RECT  54.864 18.181 59.544 19.861 ;
     RECT  26.736 18.851 26.76 20.051 ;
     RECT  18.48 19.621 21.048 20.099 ;
     RECT  29.28 19.427 29.832 20.245 ;
     RECT  31.008 18.179 32.184 20.245 ;
     RECT  29.28 20.245 32.184 20.339 ;
     RECT  29.4 20.339 32.184 20.387 ;
     RECT  34.8 17.699 35.352 20.389 ;
     RECT  7.344 18.851 10.2 20.437 ;
     RECT  6.528 20.437 10.2 20.485 ;
     RECT  39.888 18.995 42.552 20.533 ;
     RECT  31.008 20.387 32.184 20.579 ;
     RECT  49.536 12.803 49.56 20.581 ;
     RECT  5.712 20.485 10.2 20.677 ;
     RECT  51 17.123 51.312 20.677 ;
     RECT  52.752 19.475 53.064 20.723 ;
     RECT  16.944 20.629 16.968 20.771 ;
     RECT  54.72 19.861 59.544 20.819 ;
     RECT  24 18.851 25.272 20.917 ;
     RECT  53.04 20.723 53.064 20.963 ;
     RECT  34.8 20.389 35.64 21.013 ;
     RECT  37.632 20.533 37.656 21.061 ;
     RECT  44.976 19.573 45.912 21.109 ;
     RECT  50.832 20.677 51.312 21.109 ;
     RECT  5.712 20.677 10.248 21.155 ;
     RECT  37.296 21.061 37.656 21.155 ;
     RECT  49.056 20.581 49.56 21.157 ;
     RECT  50.832 21.109 51.432 21.157 ;
     RECT  39.792 20.533 42.552 21.301 ;
     RECT  43.728 20.677 43.752 21.301 ;
     RECT  33.216 20.149 33.24 21.347 ;
     RECT  18.6 20.099 21.048 21.395 ;
     RECT  67.2 16.067 67.512 21.397 ;
     RECT  49.056 21.157 51.432 21.445 ;
     RECT  11.952 18.851 13.512 21.541 ;
     RECT  39.792 21.301 43.752 21.541 ;
     RECT  44.976 21.109 46.056 21.541 ;
     RECT  7.392 21.155 10.248 21.683 ;
     RECT  20.304 21.395 21.048 21.683 ;
     RECT  39.792 21.541 46.056 21.779 ;
     RECT  54.72 20.819 59.352 21.779 ;
     RECT  23.232 20.917 25.272 21.971 ;
     RECT  38.784 21.685 38.808 21.971 ;
     RECT  49.056 21.445 51.48 21.971 ;
     RECT  49.536 21.971 51.48 22.021 ;
     RECT  5.712 21.155 5.736 22.213 ;
     RECT  34.8 21.013 36.168 22.259 ;
     RECT  7.8 21.683 10.248 22.307 ;
     RECT  23.232 21.971 25.176 22.451 ;
     RECT  29.4 20.387 29.712 22.453 ;
     RECT  31.008 20.579 31.992 22.453 ;
     RECT  42.528 21.779 46.056 22.453 ;
     RECT  23.232 22.451 24.936 22.499 ;
     RECT  49.536 22.021 52.44 22.547 ;
     RECT  39.792 21.779 41.4 22.549 ;
     RECT  72.48 19.621 72.912 22.549 ;
     RECT  10.08 22.307 10.248 22.597 ;
     RECT  11.328 21.541 13.512 22.597 ;
     RECT  66.96 21.397 67.512 22.597 ;
     RECT  37.296 21.155 37.32 22.645 ;
     RECT  54.768 21.779 59.352 22.739 ;
     RECT  39.024 22.549 41.4 22.741 ;
     RECT  53.568 21.541 53.592 22.741 ;
     RECT  26.736 22.165 26.76 22.787 ;
     RECT  54.768 22.739 59.064 22.787 ;
     RECT  27.744 20.293 27.768 22.835 ;
     RECT  54.864 22.787 59.064 22.835 ;
     RECT  42.528 22.453 46.584 23.123 ;
     RECT  52.416 22.547 52.44 23.125 ;
     RECT  53.568 22.741 53.64 23.125 ;
     RECT  29.4 22.453 31.992 23.269 ;
     RECT  29.4 23.269 32.184 23.315 ;
     RECT  7.8 22.307 8.904 23.317 ;
     RECT  37.248 22.645 37.32 23.363 ;
     RECT  5.712 22.213 5.928 23.365 ;
     RECT  7.344 23.317 8.904 23.365 ;
     RECT  39.024 22.741 41.496 23.411 ;
     RECT  71.808 22.549 72.912 23.411 ;
     RECT  5.712 23.365 8.904 23.459 ;
     RECT  37.248 23.363 37.272 23.459 ;
     RECT  18.6 21.395 19.08 23.509 ;
     RECT  20.304 21.683 20.952 23.509 ;
     RECT  52.416 23.125 53.64 23.555 ;
     RECT  61.8 11.555 62.112 23.605 ;
     RECT  54.864 22.835 59.016 23.651 ;
     RECT  66.672 22.597 67.512 23.653 ;
     RECT  68.976 22.645 69 23.699 ;
     RECT  66.672 23.653 67.8 23.795 ;
     RECT  39.024 23.411 41.4 23.843 ;
     RECT  49.536 22.547 51.432 23.845 ;
     RECT  52.416 23.555 53.064 23.845 ;
     RECT  10.08 22.597 13.512 24.083 ;
     RECT  34.8 22.259 35.928 24.085 ;
     RECT  55.056 23.651 59.016 24.179 ;
     RECT  42.528 23.123 44.136 24.181 ;
     RECT  45.264 23.123 46.584 24.181 ;
     RECT  42.528 24.181 46.584 24.227 ;
     RECT  26.976 23.317 27.384 24.323 ;
     RECT  34.704 24.085 35.928 24.373 ;
     RECT  48.096 23.125 48.12 24.469 ;
     RECT  49.536 23.845 53.064 24.469 ;
     RECT  5.712 23.459 8.112 24.563 ;
     RECT  10.08 24.083 10.248 24.563 ;
     RECT  11.328 24.083 13.512 24.563 ;
     RECT  18.6 23.509 20.952 24.565 ;
     RECT  22.176 24.133 22.2 24.565 ;
     RECT  5.712 24.563 6.504 24.611 ;
     RECT  18.6 24.565 22.2 24.611 ;
     RECT  61.344 23.605 62.112 24.613 ;
     RECT  37.2 23.701 37.224 24.707 ;
     RECT  40.2 23.843 41.4 24.707 ;
     RECT  5.712 24.611 6.264 24.803 ;
     RECT  20.784 24.611 22.2 24.947 ;
     RECT  7.584 24.563 8.112 25.045 ;
     RECT  24 22.499 24.936 25.045 ;
     RECT  14.688 24.469 14.712 25.139 ;
     RECT  39.024 23.843 39.048 25.139 ;
     RECT  61.296 24.613 62.112 25.141 ;
     RECT  12.144 24.563 13.512 25.187 ;
     RECT  21.648 24.947 22.2 25.187 ;
     RECT  61.056 25.141 62.112 25.237 ;
     RECT  29.4 23.315 31.032 25.283 ;
     RECT  72.432 23.411 72.912 25.331 ;
     RECT  22.176 25.187 22.2 25.475 ;
     RECT  34.704 24.373 35.976 25.475 ;
     RECT  67.2 23.795 67.8 25.475 ;
     RECT  2.4 15.491 2.712 25.525 ;
     RECT  23.52 25.045 24.936 25.571 ;
     RECT  4.512 24.421 4.536 25.715 ;
     RECT  48 24.469 48.12 25.715 ;
     RECT  49.488 24.469 53.064 25.717 ;
     RECT  55.584 24.179 59.016 25.763 ;
     RECT  0.24 25.621 0.264 25.765 ;
     RECT  0.144 25.765 0.264 26.003 ;
     RECT  0.144 26.003 0.168 26.051 ;
     RECT  63.216 21.493 63.24 26.147 ;
     RECT  7.584 25.045 8.712 26.149 ;
     RECT  26.496 24.325 26.52 26.149 ;
     RECT  65.04 23.701 65.064 26.149 ;
     RECT  7.536 26.149 8.712 26.197 ;
     RECT  31.008 25.283 31.032 26.197 ;
     RECT  32.16 23.315 32.184 26.197 ;
     RECT  2.4 25.525 2.856 26.243 ;
     RECT  49.488 25.717 53.16 26.243 ;
     RECT  10.224 24.563 10.248 26.245 ;
     RECT  12.144 25.187 12.168 26.291 ;
     RECT  16.992 23.893 17.016 26.291 ;
     RECT  55.584 25.763 58.584 26.339 ;
     RECT  37.92 24.997 37.944 26.341 ;
     RECT  65.04 26.149 65.4 26.389 ;
     RECT  7.344 26.197 8.712 26.579 ;
     RECT  64.848 26.389 65.4 26.579 ;
     RECT  40.2 24.707 40.512 26.629 ;
     RECT  3.744 26.629 3.768 26.771 ;
     RECT  26.496 26.149 27.336 26.819 ;
     RECT  29.4 25.283 29.976 26.819 ;
     RECT  49.488 26.243 53.064 26.819 ;
     RECT  31.008 26.197 32.184 26.867 ;
     RECT  40.2 26.629 40.632 26.869 ;
     RECT  65.04 26.579 65.4 26.915 ;
     RECT  24 25.571 24.936 27.347 ;
     RECT  37.584 26.341 37.944 27.395 ;
     RECT  61.056 25.237 62.232 27.395 ;
     RECT  42.528 24.227 46.056 27.397 ;
     RECT  31.296 26.867 32.184 27.587 ;
     RECT  10.224 26.245 10.44 27.685 ;
     RECT  40.2 26.869 41.208 27.685 ;
     RECT  40.08 27.685 41.208 27.731 ;
     RECT  61.056 27.395 62.112 27.733 ;
     RECT  7.344 26.579 8.112 27.781 ;
     RECT  55.584 26.339 58.488 27.875 ;
     RECT  18.6 24.611 19.368 27.877 ;
     RECT  3.792 27.205 3.816 27.923 ;
     RECT  49.488 26.819 52.392 27.923 ;
     RECT  48 25.715 48.024 28.453 ;
     RECT  50.352 27.923 52.392 28.453 ;
     RECT  17.616 27.877 20.184 28.499 ;
     RECT  50.352 28.453 53.256 28.643 ;
     RECT  50.352 28.643 52.104 28.885 ;
     RECT  33.6 27.205 33.624 28.931 ;
     RECT  5.712 24.803 5.736 28.933 ;
     RECT  32.16 27.587 32.184 28.933 ;
     RECT  17.616 28.499 19.368 28.979 ;
     RECT  50.208 28.885 52.104 29.027 ;
     RECT  5.712 28.933 6.312 29.029 ;
     RECT  48 28.453 48.936 29.029 ;
     RECT  53.232 28.643 53.256 29.029 ;
     RECT  48 29.029 49.032 29.075 ;
     RECT  60.336 27.733 62.112 29.221 ;
     RECT  50.448 29.027 52.104 29.411 ;
     RECT  49.008 29.075 49.032 29.507 ;
     RECT  32.16 28.933 32.52 29.509 ;
     RECT  48 29.075 48.024 29.509 ;
     RECT  2.4 26.243 2.712 29.605 ;
     RECT  38.208 27.637 38.232 29.605 ;
     RECT  27.84 28.837 27.864 29.651 ;
     RECT  65.04 26.915 65.064 29.653 ;
     RECT  42.528 27.397 46.104 29.749 ;
     RECT  47.28 29.509 48.024 29.749 ;
     RECT  32.16 29.509 33.288 30.037 ;
     RECT  40.08 27.731 40.632 30.037 ;
     RECT  67.2 25.475 67.512 30.037 ;
     RECT  38.208 29.605 38.952 30.083 ;
     RECT  42.528 29.749 48.024 30.083 ;
     RECT  5.184 29.029 6.312 30.179 ;
     RECT  31.344 30.037 33.288 30.275 ;
     RECT  64.944 29.653 65.064 30.323 ;
     RECT  50.448 29.411 51.96 30.421 ;
     RECT  53.232 29.029 53.4 30.421 ;
     RECT  15.888 28.261 15.912 30.469 ;
     RECT  15.888 30.469 16.2 30.515 ;
     RECT  34.8 25.475 35.976 30.517 ;
     RECT  34.8 30.517 36.456 30.563 ;
     RECT  75.408 30.421 75.432 30.611 ;
     RECT  2.4 29.605 3.576 30.661 ;
     RECT  5.184 30.179 5.784 30.661 ;
     RECT  13.2 25.187 13.512 30.661 ;
     RECT  40.08 30.037 41.496 30.707 ;
     RECT  2.4 30.661 5.784 30.709 ;
     RECT  50.448 30.421 53.4 30.757 ;
     RECT  55.584 27.875 58.344 30.757 ;
     RECT  70.704 30.085 70.728 30.757 ;
     RECT  13.2 30.661 14.376 30.805 ;
     RECT  42.72 30.083 48.024 30.805 ;
     RECT  60.336 29.221 62.76 30.805 ;
     RECT  65.04 30.323 65.064 30.805 ;
     RECT  55.344 30.757 58.344 30.853 ;
     RECT  34.8 30.563 35.304 30.899 ;
     RECT  70.704 30.757 70.824 30.899 ;
     RECT  59.952 30.805 62.856 30.947 ;
     RECT  74.64 30.757 74.664 30.947 ;
     RECT  70.704 30.899 70.728 30.995 ;
     RECT  40.2 30.707 41.496 31.139 ;
     RECT  42.72 30.805 48.36 31.283 ;
     RECT  50.304 30.757 53.4 31.333 ;
     RECT  2.304 30.709 5.784 31.379 ;
     RECT  13.104 30.805 14.376 31.379 ;
     RECT  31.344 30.275 32.52 31.379 ;
     RECT  67.2 30.037 68.088 31.379 ;
     RECT  37.776 30.229 37.8 31.381 ;
     RECT  38.928 30.083 38.952 31.381 ;
     RECT  37.776 31.381 38.952 31.427 ;
     RECT  18.6 28.979 19.368 31.523 ;
     RECT  29.4 26.819 29.712 31.573 ;
     RECT  54.672 30.853 58.344 31.619 ;
     RECT  59.952 30.947 62.52 31.619 ;
     RECT  26.496 26.819 26.52 31.621 ;
     RECT  13.104 31.379 13.512 31.667 ;
     RECT  26.208 31.621 26.52 31.667 ;
     RECT  65.04 30.805 65.544 31.765 ;
     RECT  5.184 31.379 5.784 31.861 ;
     RECT  32.16 31.379 32.52 31.861 ;
     RECT  34.8 30.899 35.112 31.861 ;
     RECT  36.432 30.563 36.456 31.861 ;
     RECT  34.8 31.861 36.456 31.907 ;
     RECT  42.72 31.283 46.824 31.955 ;
     RECT  65.04 31.765 66.168 31.955 ;
     RECT  2.304 31.379 3.576 32.195 ;
     RECT  29.4 31.573 30.648 32.195 ;
     RECT  20.544 31.477 20.568 32.243 ;
     RECT  38.736 31.427 38.952 32.531 ;
     RECT  54.672 31.619 58.104 32.531 ;
     RECT  50.304 31.333 53.64 32.579 ;
     RECT  2.4 32.195 3.576 32.773 ;
     RECT  40.2 31.139 40.968 32.867 ;
     RECT  5.184 31.861 6.264 32.869 ;
     RECT  7.344 27.781 8.328 32.869 ;
     RECT  65.04 31.955 65.256 32.963 ;
     RECT  13.2 31.667 13.512 33.013 ;
     RECT  43.296 31.955 46.824 33.013 ;
     RECT  48 31.283 48.36 33.013 ;
     RECT  43.296 33.013 48.36 33.061 ;
     RECT  65.04 32.963 65.064 33.107 ;
     RECT  38.928 32.531 38.952 33.251 ;
     RECT  75.408 33.109 75.432 33.299 ;
     RECT  5.184 32.869 8.328 33.541 ;
     RECT  50.304 32.579 51.912 33.587 ;
     RECT  16.176 30.515 16.2 33.589 ;
     RECT  50.304 33.587 51.864 33.589 ;
     RECT  2.4 32.773 3.96 33.925 ;
     RECT  4.944 33.541 8.328 33.925 ;
     RECT  67.2 31.379 67.992 34.069 ;
     RECT  53.04 32.579 53.64 34.115 ;
     RECT  29.4 32.195 29.712 34.165 ;
     RECT  55.296 32.531 58.104 34.211 ;
     RECT  34.8 31.907 36.024 34.259 ;
     RECT  53.04 34.115 53.064 34.259 ;
     RECT  66.816 34.069 67.992 34.259 ;
     RECT  43.296 33.061 48.84 34.499 ;
     RECT  2.4 33.925 8.328 34.693 ;
     RECT  13.2 33.013 13.896 34.693 ;
     RECT  16.032 33.589 16.2 34.693 ;
     RECT  15.984 34.693 16.2 34.739 ;
     RECT  10.224 27.685 10.536 34.741 ;
     RECT  60.336 31.619 62.52 34.741 ;
     RECT  60.336 34.741 62.712 34.835 ;
     RECT  26.208 31.667 26.232 34.931 ;
     RECT  49.92 33.589 51.864 34.931 ;
     RECT  55.824 34.211 58.104 34.979 ;
     RECT  29.184 34.165 29.712 35.029 ;
     RECT  75.408 35.125 75.432 35.315 ;
     RECT  49.92 34.931 51.432 35.363 ;
     RECT  54.432 34.741 54.456 35.363 ;
     RECT  60.576 34.835 62.712 35.363 ;
     RECT  66.816 34.259 67.512 35.363 ;
     RECT  64.512 34.021 64.536 35.459 ;
     RECT  70.704 35.269 70.728 35.459 ;
     RECT  34.8 34.259 35.112 35.797 ;
     RECT  15.984 34.739 16.056 35.845 ;
     RECT  29.04 35.029 29.712 35.939 ;
     RECT  25.824 35.557 25.848 36.467 ;
     RECT  27.36 35.077 27.384 36.515 ;
     RECT  43.296 34.499 48.6 36.515 ;
     RECT  15.984 35.845 16.392 36.563 ;
     RECT  37.2 35.845 37.224 36.755 ;
     RECT  10.224 34.741 10.584 36.805 ;
     RECT  9.312 36.805 10.584 36.901 ;
     RECT  65.232 36.805 65.256 37.093 ;
     RECT  64.416 37.093 65.256 37.139 ;
     RECT  50.304 35.363 51.432 37.237 ;
     RECT  64.416 37.139 64.632 37.283 ;
     RECT  16.032 36.563 16.392 37.333 ;
     RECT  13.2 34.693 14.28 37.427 ;
     RECT  2.304 34.693 8.328 37.573 ;
     RECT  9.312 36.901 10.68 37.573 ;
     RECT  40.2 32.867 40.512 37.573 ;
     RECT  43.296 36.515 46.68 37.573 ;
     RECT  34.8 35.797 35.544 37.619 ;
     RECT  2.304 37.573 10.68 37.621 ;
     RECT  16.032 37.333 16.584 37.621 ;
     RECT  24 27.347 24.792 37.621 ;
     RECT  64.608 37.283 64.632 37.715 ;
     RECT  43.296 37.573 46.824 37.859 ;
     RECT  60.576 35.363 62.52 37.907 ;
     RECT  37.056 37.861 37.08 38.003 ;
     RECT  48 36.515 48.6 38.005 ;
     RECT  49.584 37.237 51.432 38.005 ;
     RECT  60.576 37.907 62.328 38.005 ;
     RECT  60.48 38.005 62.328 38.147 ;
     RECT  2.304 37.621 10.968 38.149 ;
     RECT  48 38.005 51.432 38.195 ;
     RECT  29.4 35.939 29.712 38.197 ;
     RECT  60.576 38.147 62.328 38.675 ;
     RECT  2.304 38.149 11.112 38.677 ;
     RECT  12.144 35.941 12.168 38.677 ;
     RECT  40.08 37.573 40.512 38.677 ;
     RECT  18.6 31.523 18.912 38.725 ;
     RECT  0.144 37.429 0.168 38.965 ;
     RECT  34.8 37.619 35.352 39.205 ;
     RECT  18.48 38.725 18.912 39.253 ;
     RECT  54 38.101 54.024 39.253 ;
     RECT  29.28 38.197 29.712 39.395 ;
     RECT  39.36 38.677 40.512 39.395 ;
     RECT  0.144 38.965 0.216 39.541 ;
     RECT  48.048 38.195 51.432 39.587 ;
     RECT  0.144 39.541 0.312 39.637 ;
     RECT  13.2 37.427 14.232 39.637 ;
     RECT  16.032 37.621 16.632 39.637 ;
     RECT  32.16 31.861 32.904 39.731 ;
     RECT  48.048 39.587 48.6 39.779 ;
     RECT  50.304 39.587 51.432 39.781 ;
     RECT  52.704 38.677 52.728 39.781 ;
     RECT  18.24 39.253 18.912 39.875 ;
     RECT  48.048 39.779 48.408 39.877 ;
     RECT  26.064 39.253 26.088 39.971 ;
     RECT  0.144 39.637 0.552 40.115 ;
     RECT  50.304 39.781 52.728 40.165 ;
     RECT  37.056 39.157 37.08 40.259 ;
     RECT  18.48 39.875 18.912 40.261 ;
     RECT  19.92 40.213 19.944 40.261 ;
     RECT  0.144 40.115 0.312 40.307 ;
     RECT  0.144 40.307 0.264 40.499 ;
     RECT  54 39.253 54.12 40.691 ;
     RECT  13.2 39.637 16.632 40.787 ;
     RECT  65.52 38.101 65.544 40.835 ;
     RECT  60.72 38.675 62.328 40.883 ;
     RECT  61.632 40.883 62.328 40.931 ;
     RECT  56.016 34.979 58.104 40.981 ;
     RECT  16.032 40.787 16.632 41.077 ;
     RECT  18.48 40.261 19.944 41.171 ;
     RECT  16.032 41.077 16.824 41.267 ;
     RECT  2.304 38.677 12.168 41.365 ;
     RECT  13.2 40.787 14.232 41.365 ;
     RECT  18.6 41.171 19.944 41.651 ;
     RECT  19.92 41.651 19.944 41.699 ;
     RECT  32.16 39.731 32.184 41.747 ;
     RECT  43.824 37.859 46.824 41.797 ;
     RECT  48 39.877 48.408 41.797 ;
     RECT  61.8 40.931 62.328 41.893 ;
     RECT  0.144 40.499 0.216 41.939 ;
     RECT  0.192 41.939 0.216 41.941 ;
     RECT  67.2 35.363 67.512 42.133 ;
     RECT  0.192 41.941 0.264 42.323 ;
     RECT  2.304 41.365 14.232 42.325 ;
     RECT  43.824 41.797 48.408 42.515 ;
     RECT  26.352 40.405 26.376 42.803 ;
     RECT  43.824 42.515 43.848 42.803 ;
     RECT  55.776 40.981 58.104 43.379 ;
     RECT  34.8 39.205 35.592 43.763 ;
     RECT  54 40.691 54.024 43.861 ;
     RECT  50.304 40.165 53.016 43.907 ;
     RECT  24 37.621 24.936 44.437 ;
     RECT  40.2 39.395 40.512 44.437 ;
     RECT  2.304 42.325 14.856 44.483 ;
     RECT  44.976 42.515 48.408 44.483 ;
     RECT  16.032 41.267 16.392 44.677 ;
     RECT  33.792 43.669 33.816 44.821 ;
     RECT  33.072 44.821 33.816 44.963 ;
     RECT  64.896 41.605 64.92 45.011 ;
     RECT  23.376 44.437 24.936 45.059 ;
     RECT  31.488 43.285 31.512 45.059 ;
     RECT  67.2 42.133 67.848 45.157 ;
     RECT  0.144 42.949 0.168 45.203 ;
     RECT  2.4 44.483 14.856 45.203 ;
     RECT  48.144 44.483 48.408 45.203 ;
     RECT  16.032 44.677 17.016 45.541 ;
     RECT  61.8 41.893 62.424 45.541 ;
     RECT  61.584 45.541 62.424 45.685 ;
     RECT  66.24 45.157 67.848 45.731 ;
     RECT  67.2 45.731 67.848 45.877 ;
     RECT  2.4 45.203 12.168 45.971 ;
     RECT  13.2 45.203 14.856 45.973 ;
     RECT  2.4 45.971 11.256 46.021 ;
     RECT  13.2 45.973 15 46.115 ;
     RECT  54 43.861 54.408 46.163 ;
     RECT  59.52 45.157 59.544 46.163 ;
     RECT  27.408 45.733 27.432 46.211 ;
     RECT  56.016 43.379 58.104 46.211 ;
     RECT  14.976 46.115 15 46.261 ;
     RECT  16.032 45.541 17.352 46.261 ;
     RECT  24 45.059 24.936 46.309 ;
     RECT  50.304 43.907 52.776 46.309 ;
     RECT  54 46.163 54.024 46.309 ;
     RECT  23.136 46.309 24.936 46.547 ;
     RECT  61.584 45.685 62.952 46.547 ;
     RECT  67.2 45.877 68.04 46.547 ;
     RECT  18.6 41.651 18.912 46.549 ;
     RECT  0.192 45.781 0.552 46.597 ;
     RECT  14.976 46.261 17.352 46.597 ;
     RECT  18.6 46.549 19.56 46.597 ;
     RECT  38.88 45.733 38.904 46.645 ;
     RECT  40.2 44.437 40.92 46.645 ;
     RECT  2.304 46.021 11.256 47.363 ;
     RECT  32.112 45.157 32.136 47.363 ;
     RECT  44.976 44.483 46.728 47.699 ;
     RECT  60.192 46.789 60.216 47.749 ;
     RECT  61.584 46.547 62.112 47.749 ;
     RECT  14.976 46.597 19.56 47.795 ;
     RECT  48.144 45.203 48.312 47.845 ;
     RECT  60.192 47.749 62.112 47.845 ;
     RECT  67.2 46.547 67.512 47.845 ;
     RECT  38.88 46.645 40.92 47.891 ;
     RECT  48.048 47.845 48.312 47.891 ;
     RECT  50.304 46.309 54.024 47.891 ;
     RECT  59.856 47.845 62.112 47.891 ;
     RECT  40.2 47.891 40.92 48.131 ;
     RECT  14.976 47.795 17.064 48.419 ;
     RECT  60.96 47.891 62.112 48.419 ;
     RECT  59.856 47.891 59.88 48.467 ;
     RECT  0.144 46.597 0.552 48.563 ;
     RECT  33.792 44.963 33.816 48.805 ;
     RECT  34.8 43.763 35.304 48.805 ;
     RECT  2.304 47.363 10.248 48.853 ;
     RECT  33.792 48.805 35.304 48.949 ;
     RECT  53.328 47.891 54.024 48.949 ;
     RECT  45.6 47.699 46.728 48.995 ;
     RECT  2.304 48.853 10.392 49.043 ;
     RECT  11.616 47.797 11.64 49.235 ;
     RECT  2.304 49.043 10.248 49.283 ;
     RECT  33.024 48.949 35.304 49.333 ;
     RECT  40.2 48.131 40.68 49.333 ;
     RECT  22.176 48.805 22.2 49.619 ;
     RECT  33.024 49.333 35.592 49.619 ;
     RECT  61.68 48.419 62.112 49.909 ;
     RECT  0.144 48.563 0.408 50.005 ;
     RECT  37.728 45.541 37.752 50.005 ;
     RECT  38.88 47.891 38.904 50.005 ;
     RECT  37.728 50.005 38.904 50.101 ;
     RECT  40.2 49.333 41.064 50.101 ;
     RECT  2.4 49.283 10.248 50.389 ;
     RECT  18.24 47.795 19.56 50.435 ;
     RECT  18.48 50.435 19.56 50.437 ;
     RECT  0.144 50.005 0.552 50.579 ;
     RECT  37.728 50.101 41.064 50.579 ;
     RECT  53.328 48.949 54.36 50.579 ;
     RECT  33.888 49.619 35.592 50.723 ;
     RECT  37.728 50.579 40.512 50.771 ;
     RECT  65.424 50.101 65.448 50.771 ;
     RECT  72.6 25.331 72.912 50.965 ;
     RECT  61.488 49.909 62.112 51.203 ;
     RECT  14.976 48.419 17.016 51.347 ;
     RECT  37.872 50.771 40.512 51.347 ;
     RECT  38.928 51.347 40.512 51.395 ;
     RECT  18.48 50.437 19.848 51.491 ;
     RECT  0.192 50.579 0.552 51.731 ;
     RECT  42.384 37.957 42.408 51.829 ;
     RECT  0.192 51.731 0.456 51.877 ;
     RECT  26.976 51.109 27 51.923 ;
     RECT  33.888 50.723 35.304 51.923 ;
     RECT  18.48 51.491 19.56 51.925 ;
     RECT  18 51.925 19.56 51.971 ;
     RECT  14.976 51.347 15.096 52.019 ;
     RECT  42.144 51.829 42.408 52.117 ;
     RECT  44.064 51.253 44.088 52.163 ;
     RECT  53.328 50.579 54.168 52.213 ;
     RECT  72.48 50.965 72.912 52.259 ;
     RECT  2.4 50.389 11.016 52.307 ;
     RECT  30.816 50.629 30.84 52.307 ;
     RECT  16.368 51.347 17.016 52.357 ;
     RECT  18 51.971 19.416 52.357 ;
     RECT  59.808 51.493 59.832 52.451 ;
     RECT  67.2 47.845 67.992 52.451 ;
     RECT  0.144 51.877 0.456 52.499 ;
     RECT  23.328 46.547 24.936 52.547 ;
     RECT  0.144 52.499 0.408 52.595 ;
     RECT  61.8 51.203 62.112 52.645 ;
     RECT  23.328 52.547 24.744 52.693 ;
     RECT  45.6 48.995 46.632 52.787 ;
     RECT  10.992 52.307 11.016 52.789 ;
     RECT  12.048 51.781 12.072 52.789 ;
     RECT  63.888 52.021 63.912 53.075 ;
     RECT  34.8 51.923 35.304 53.123 ;
     RECT  61.8 52.645 62.52 53.125 ;
     RECT  59.856 52.981 60.072 53.315 ;
     RECT  2.4 52.307 9.96 53.365 ;
     RECT  10.992 52.789 12.072 53.365 ;
     RECT  48.048 47.891 48.264 53.557 ;
     RECT  67.2 52.451 67.512 53.557 ;
     RECT  16.368 52.357 19.416 53.603 ;
     RECT  33.072 52.405 33.096 53.603 ;
     RECT  38.928 51.395 38.952 53.603 ;
     RECT  0.144 52.595 0.216 53.797 ;
     RECT  59.856 53.315 59.88 53.941 ;
     RECT  23.04 52.693 24.744 54.083 ;
     RECT  53.328 52.213 54.408 54.131 ;
     RECT  2.4 53.365 12.072 54.179 ;
     RECT  37.872 51.347 37.896 54.179 ;
     RECT  66.144 52.981 66.168 54.179 ;
     RECT  67.2 53.557 68.424 54.179 ;
     RECT  61.8 53.125 63.048 54.227 ;
     RECT  45.6 52.787 46.104 54.371 ;
     RECT  48.048 53.557 48.504 54.373 ;
     RECT  2.4 54.179 9.96 54.421 ;
     RECT  16.368 53.603 16.968 54.661 ;
     RECT  18 53.603 19.416 54.661 ;
     RECT  16.368 54.661 19.416 54.755 ;
     RECT  16.368 54.755 17.064 54.899 ;
     RECT  14.976 52.019 15 55.139 ;
     RECT  10.992 54.179 12.072 55.141 ;
     RECT  18.6 54.755 19.416 55.285 ;
     RECT  0.144 53.797 0.312 55.333 ;
     RECT  2.304 54.421 9.96 55.379 ;
     RECT  23.04 54.083 24.312 55.429 ;
     RECT  53.328 54.131 54.024 55.429 ;
     RECT  48.048 54.373 48.6 55.477 ;
     RECT  16.944 54.899 17.064 55.523 ;
     RECT  2.4 55.379 9.96 55.525 ;
     RECT  10.992 55.141 12.12 55.525 ;
     RECT  42 52.117 42.408 55.525 ;
     RECT  45.6 54.371 45.912 55.525 ;
     RECT  50.304 47.891 52.296 55.765 ;
     RECT  53.328 55.429 54.984 55.765 ;
     RECT  16.944 55.523 16.968 55.907 ;
     RECT  50.304 55.765 54.984 55.957 ;
     RECT  44.064 54.085 44.088 56.149 ;
     RECT  45.6 55.525 46.008 56.149 ;
     RECT  44.064 56.149 46.008 56.195 ;
     RECT  37.104 54.661 37.128 56.197 ;
     RECT  37.104 56.197 37.368 56.243 ;
     RECT  47.808 55.477 48.6 56.243 ;
     RECT  13.2 46.115 13.944 56.245 ;
     RECT  59.472 53.941 59.88 56.389 ;
     RECT  56.4 46.211 58.104 56.485 ;
     RECT  49.968 55.957 54.984 56.531 ;
     RECT  29.4 39.395 29.712 56.725 ;
     RECT  44.928 56.195 46.008 56.773 ;
     RECT  23.04 55.429 24.408 57.059 ;
     RECT  56.4 56.485 58.152 57.059 ;
     RECT  0.144 55.333 0.36 57.157 ;
     RECT  61.8 54.227 62.112 57.205 ;
     RECT  59.424 56.389 59.88 57.251 ;
     RECT  44.928 56.773 46.056 57.443 ;
     RECT  42 55.525 42.792 57.445 ;
     RECT  49.968 56.531 49.992 57.541 ;
     RECT  42 57.445 42.888 57.589 ;
     RECT  51 56.531 54.984 57.589 ;
     RECT  56.4 57.059 58.104 57.589 ;
     RECT  44.928 57.443 46.008 57.635 ;
     RECT  51 57.589 58.104 57.635 ;
     RECT  42 57.589 43.368 57.637 ;
     RECT  55.536 57.635 58.104 57.875 ;
     RECT  26.928 52.981 26.952 57.877 ;
     RECT  34.8 53.123 35.112 57.877 ;
     RECT  51 57.635 54.024 57.971 ;
     RECT  47.904 56.243 48.6 58.021 ;
     RECT  2.4 55.525 12.12 58.069 ;
     RECT  0.144 57.157 0.408 58.163 ;
     RECT  0.144 58.163 0.36 58.355 ;
     RECT  49.824 57.541 49.992 58.453 ;
     RECT  51 57.971 52.296 58.453 ;
     RECT  47.424 58.021 48.6 58.499 ;
     RECT  2.304 58.069 12.12 58.643 ;
     RECT  37.344 56.243 37.368 58.645 ;
     RECT  26.928 57.877 27.624 58.691 ;
     RECT  36.72 58.645 37.368 58.691 ;
     RECT  49.824 58.453 52.296 58.693 ;
     RECT  0.144 58.355 0.312 58.739 ;
     RECT  38.64 58.117 38.664 58.883 ;
     RECT  18.6 55.285 20.232 58.979 ;
     RECT  59.424 57.251 59.448 59.173 ;
     RECT  61.104 57.205 62.112 59.219 ;
     RECT  54 57.971 54.024 59.221 ;
     RECT  55.536 57.875 57.672 59.221 ;
     RECT  59.424 59.173 59.832 59.267 ;
     RECT  23.04 57.059 24.312 59.315 ;
     RECT  44.928 57.635 45.912 59.315 ;
     RECT  63.504 56.965 63.528 59.315 ;
     RECT  54 59.221 57.672 59.363 ;
     RECT  34.8 57.877 35.208 59.459 ;
     RECT  33.072 57.541 33.096 59.557 ;
     RECT  34.8 59.459 35.112 59.557 ;
     RECT  40.2 51.395 40.512 59.797 ;
     RECT  25.92 56.389 25.944 59.845 ;
     RECT  2.4 58.643 12.12 59.891 ;
     RECT  11.376 59.891 12.12 59.987 ;
     RECT  49.776 58.693 52.296 59.987 ;
     RECT  27.6 58.691 27.624 60.037 ;
     RECT  2.4 59.891 10.248 60.085 ;
     RECT  48.576 58.499 48.6 60.133 ;
     RECT  42 57.637 43.896 60.275 ;
     RECT  49.968 59.987 52.296 60.323 ;
     RECT  42.288 60.275 43.896 60.373 ;
     RECT  44.976 59.315 45.912 60.373 ;
     RECT  54.432 59.363 57.672 60.419 ;
     RECT  0.144 58.739 0.264 60.467 ;
     RECT  0.192 60.467 0.264 60.611 ;
     RECT  36.72 58.691 36.744 60.661 ;
     RECT  36.528 60.661 36.744 60.707 ;
     RECT  27.6 60.037 27.672 60.851 ;
     RECT  25.92 59.845 26.328 60.853 ;
     RECT  33.072 59.557 35.112 60.901 ;
     RECT  29.28 56.725 29.712 60.949 ;
     RECT  44.976 60.373 46.824 60.949 ;
     RECT  59.808 59.267 59.832 60.949 ;
     RECT  48.384 60.133 48.6 60.995 ;
     RECT  2.304 60.085 10.248 61.043 ;
     RECT  33.024 60.901 35.112 61.043 ;
     RECT  11.376 59.987 11.448 61.091 ;
     RECT  0.192 60.611 0.216 61.139 ;
     RECT  29.28 60.949 29.832 61.139 ;
     RECT  48.576 60.995 48.6 61.187 ;
     RECT  13.2 56.245 14.136 61.189 ;
     RECT  54.432 60.419 55.128 61.189 ;
     RECT  54.096 61.189 55.128 61.235 ;
     RECT  63.744 59.845 63.768 61.379 ;
     RECT  67.2 54.179 67.512 61.525 ;
     RECT  59.808 60.949 59.928 61.619 ;
     RECT  11.376 61.091 11.4 61.715 ;
     RECT  33.024 61.043 33.768 61.907 ;
     RECT  39.648 59.797 40.512 61.907 ;
     RECT  25.824 60.853 26.328 62.101 ;
     RECT  55.104 61.235 55.128 62.101 ;
     RECT  27.6 60.851 27.624 62.147 ;
     RECT  40.2 61.907 40.512 62.149 ;
     RECT  42.288 60.373 43.992 62.149 ;
     RECT  44.976 60.949 47.064 62.149 ;
     RECT  59.856 61.619 59.928 62.149 ;
     RECT  2.304 61.043 9.384 62.195 ;
     RECT  2.4 62.195 6.024 62.243 ;
     RECT  42.288 62.149 47.064 62.243 ;
     RECT  23.376 59.315 24.312 62.435 ;
     RECT  54.096 61.235 54.12 62.483 ;
     RECT  25.824 62.101 26.616 62.629 ;
     RECT  2.4 62.243 5.832 62.675 ;
     RECT  40.2 62.149 40.776 62.723 ;
     RECT  2.4 62.675 4.536 62.771 ;
     RECT  42.288 62.243 46.728 62.771 ;
     RECT  2.4 62.771 4.296 62.819 ;
     RECT  59.856 62.149 60.408 62.819 ;
     RECT  2.4 62.819 3.336 62.867 ;
     RECT  67.2 61.525 67.608 62.867 ;
     RECT  49.968 60.323 52.152 62.965 ;
     RECT  55.104 62.101 55.272 63.011 ;
     RECT  42.288 62.771 44.328 63.155 ;
     RECT  7.488 62.195 9.384 63.157 ;
     RECT  5.568 62.675 5.832 63.205 ;
     RECT  49.536 62.965 52.152 63.205 ;
     RECT  49.008 63.205 52.152 63.251 ;
     RECT  44.16 63.155 44.328 63.299 ;
     RECT  55.248 63.011 55.272 63.299 ;
     RECT  60.384 62.819 60.408 63.299 ;
     RECT  7.44 63.157 9.384 63.347 ;
     RECT  45.6 62.771 46.728 63.347 ;
     RECT  9.36 63.347 9.384 63.635 ;
     RECT  25.344 62.629 26.616 63.683 ;
     RECT  45.6 63.347 46.68 63.731 ;
     RECT  36.528 60.707 36.552 63.779 ;
     RECT  50.88 63.251 52.152 63.875 ;
     RECT  23.616 62.435 24.312 64.115 ;
     RECT  25.632 63.683 26.616 64.115 ;
     RECT  29.4 61.139 29.832 64.115 ;
     RECT  42.288 63.155 42.888 64.259 ;
     RECT  44.16 63.299 44.184 64.357 ;
     RECT  5.568 63.205 5.88 64.499 ;
     RECT  49.008 63.251 49.56 64.787 ;
     RECT  49.488 64.787 49.56 64.837 ;
     RECT  50.88 63.875 51.48 64.837 ;
     RECT  33.072 61.907 33.768 64.883 ;
     RECT  49.488 64.837 51.48 64.979 ;
     RECT  25.92 64.115 26.616 65.269 ;
     RECT  34.8 61.043 35.112 65.317 ;
     RECT  7.44 63.347 8.232 65.461 ;
     RECT  10.992 63.253 11.016 65.461 ;
     RECT  13.2 61.189 14.28 65.507 ;
     RECT  5.808 64.499 5.88 65.509 ;
     RECT  31.92 60.133 31.944 65.509 ;
     RECT  45.6 63.731 45.912 65.509 ;
     RECT  7.344 65.461 8.232 65.555 ;
     RECT  31.92 65.509 32.328 65.555 ;
     RECT  18.6 58.979 19.368 65.603 ;
     RECT  49.488 64.979 51.312 65.699 ;
     RECT  5.808 65.509 6.264 65.797 ;
     RECT  7.344 65.555 8.112 65.797 ;
     RECT  49.488 65.699 49.56 65.797 ;
     RECT  25.44 65.269 26.616 65.939 ;
     RECT  49.008 65.797 49.56 65.939 ;
     RECT  45.6 65.509 46.632 65.941 ;
     RECT  33.744 64.883 33.768 66.085 ;
     RECT  34.8 65.317 35.544 66.085 ;
     RECT  43.92 64.357 44.184 66.275 ;
     RECT  10.944 65.461 11.016 66.515 ;
     RECT  43.92 66.275 44.04 66.515 ;
     RECT  23.808 64.115 24.312 66.613 ;
     RECT  40.2 62.723 40.512 66.661 ;
     RECT  33.744 66.085 35.544 66.707 ;
     RECT  37.296 66.133 37.32 66.707 ;
     RECT  10.992 66.515 11.016 66.755 ;
     RECT  49.248 65.939 49.512 66.755 ;
     RECT  39.84 66.661 40.512 66.899 ;
     RECT  5.808 65.797 8.112 67.187 ;
     RECT  45.456 65.941 46.632 67.283 ;
     RECT  17.328 66.613 17.352 67.331 ;
     RECT  44.016 66.515 44.04 67.717 ;
     RECT  44.016 67.717 44.136 67.765 ;
     RECT  37.056 67.141 37.08 67.859 ;
     RECT  49.248 66.755 49.272 67.909 ;
     RECT  50.64 65.699 51.312 67.909 ;
     RECT  32.304 65.555 32.328 67.955 ;
     RECT  29.4 64.115 29.712 68.005 ;
     RECT  34.8 66.707 35.544 68.147 ;
     RECT  33.744 66.707 33.768 68.341 ;
     RECT  34.8 68.147 35.112 68.341 ;
     RECT  44.016 67.765 44.232 68.341 ;
     RECT  49.248 67.909 51.312 68.341 ;
     RECT  5.808 67.187 6.552 68.387 ;
     RECT  25.44 65.939 26.232 68.531 ;
     RECT  25.92 68.531 26.232 68.675 ;
     RECT  23.136 66.613 24.312 68.723 ;
     RECT  42.384 64.259 42.888 68.917 ;
     RECT  44.016 68.341 44.52 68.917 ;
     RECT  33.744 68.341 35.112 68.963 ;
     RECT  29.4 68.005 30.264 69.059 ;
     RECT  25.92 68.675 25.944 69.203 ;
     RECT  33.936 68.963 35.112 69.251 ;
     RECT  56.4 60.419 57.672 69.251 ;
     RECT  48.384 68.341 51.312 69.347 ;
     RECT  42.384 68.917 44.52 69.349 ;
     RECT  9.792 65.605 9.816 69.587 ;
     RECT  42.144 69.349 44.52 69.971 ;
     RECT  45.6 67.283 46.632 69.971 ;
     RECT  23.808 68.723 24.312 70.019 ;
     RECT  16.416 69.541 16.44 70.259 ;
     RECT  38.208 68.917 38.232 70.259 ;
     RECT  5.808 68.387 5.832 70.547 ;
     RECT  42.144 69.971 44.472 70.739 ;
     RECT  36.48 69.493 36.504 70.931 ;
     RECT  49.488 69.347 51.312 71.027 ;
     RECT  13.2 65.507 13.512 71.221 ;
     RECT  48.384 69.347 48.408 71.315 ;
     RECT  16.08 70.933 16.104 71.843 ;
     RECT  49.584 71.027 51.312 71.843 ;
     RECT  50.16 71.843 51.312 71.891 ;
     RECT  13.2 71.221 13.608 72.179 ;
     RECT  42.384 70.739 44.472 72.995 ;
     RECT  2.4 62.867 2.712 73.449 ;
     RECT  7.8 67.187 8.112 73.449 ;
     RECT  13.2 72.179 13.512 73.449 ;
     RECT  18.6 65.603 18.912 73.449 ;
     RECT  24 70.019 24.312 73.449 ;
     RECT  29.4 69.059 29.712 73.449 ;
     RECT  34.8 69.251 35.112 73.449 ;
     RECT  40.2 66.899 40.512 73.449 ;
     RECT  45.6 69.971 45.912 73.449 ;
     RECT  51 71.891 51.312 73.449 ;
     RECT  56.4 69.251 56.712 73.449 ;
     RECT  61.8 59.219 62.112 73.449 ;
     RECT  67.2 62.867 67.512 73.449 ;
     RECT  72.6 52.259 72.912 73.449 ;
     RECT  2.4 73.449 2.52 73.463 ;
     RECT  7.8 73.449 7.92 73.463 ;
     RECT  13.2 73.449 13.32 73.463 ;
     RECT  18.6 73.449 18.72 73.463 ;
     RECT  24 73.449 24.12 73.463 ;
     RECT  29.4 73.449 29.52 73.463 ;
     RECT  34.8 73.449 34.92 73.463 ;
     RECT  40.2 73.449 40.32 73.463 ;
     RECT  45.6 73.449 45.72 73.463 ;
     RECT  51 73.449 51.12 73.463 ;
     RECT  56.4 73.449 56.52 73.463 ;
     RECT  61.8 73.449 61.92 73.463 ;
     RECT  67.2 73.449 67.32 73.463 ;
     RECT  72.6 73.449 72.72 73.463 ;
     RECT  42.384 72.995 44.04 74.341 ;
     RECT  42.384 74.341 44.136 74.677 ;
     RECT  42.288 74.677 44.136 75.536 ;
     RECT  67.536 0.611 67.728 1.139 ;
     RECT  67.536 1.139 68.016 2.137 ;
     RECT  8.28 2.149 9.36 2.197 ;
     RECT  3.048 2.197 4.32 2.245 ;
     RECT  33.336 2.485 34.8 3.685 ;
     RECT  10.824 2.629 12 2.725 ;
     RECT  12.024 2.629 13.2 2.773 ;
     RECT  10.824 2.725 11.952 3.685 ;
     RECT  12.024 2.773 13.008 3.205 ;
     RECT  6.168 2.821 7.392 3.157 ;
     RECT  32.328 2.821 33.312 3.829 ;
     RECT  35.256 2.869 36.336 3.157 ;
     RECT  35.304 3.157 36.336 3.443 ;
     RECT  35.304 3.443 35.352 4.165 ;
     RECT  8.856 3.491 9.888 5.077 ;
     RECT  67.512 3.539 69.024 4.595 ;
     RECT  32.04 4.115 33.024 6.323 ;
     RECT  40.032 4.115 40.2 5.605 ;
     RECT  29.928 4.547 30.072 5.125 ;
     RECT  67.512 4.595 69.696 6.085 ;
     RECT  15.72 5.029 16.944 5.267 ;
     RECT  29.928 5.125 30.96 5.701 ;
     RECT  46.248 5.267 47.376 7.475 ;
     RECT  38.856 5.605 40.2 5.797 ;
     RECT  13.512 5.747 13.608 5.845 ;
     RECT  69.72 5.747 70.704 6.947 ;
     RECT  13.512 5.845 14.832 7.381 ;
     RECT  68.472 6.085 69.696 6.899 ;
     RECT  65.688 6.181 67.2 9.013 ;
     RECT  32.04 6.323 32.424 6.613 ;
     RECT  15.672 6.563 15.72 7.957 ;
     RECT  40.632 6.899 41.664 8.003 ;
     RECT  65.568 7.043 65.664 8.437 ;
     RECT  67.704 7.139 67.752 8.485 ;
     RECT  19.128 7.189 20.304 9.493 ;
     RECT  58.008 7.381 59.472 7.619 ;
     RECT  38.448 7.427 38.496 8.485 ;
     RECT  31.032 7.475 32.016 8.195 ;
     RECT  46.248 7.475 47.472 8.675 ;
     RECT  57.48 7.619 59.472 8.437 ;
     RECT  20.328 7.717 21.6 10.355 ;
     RECT  32.424 7.909 33.888 10.069 ;
     RECT  35.4 7.957 36.432 8.003 ;
     RECT  35.208 8.003 36.432 10.307 ;
     RECT  40.512 8.003 41.664 9.155 ;
     RECT  31.032 8.195 32.16 10.115 ;
     RECT  57.48 8.437 59.04 8.773 ;
     RECT  57.96 8.773 59.04 9.061 ;
     RECT  59.976 8.965 61.44 9.157 ;
     RECT  37.128 9.013 38.448 9.155 ;
     RECT  65.688 9.013 66.96 9.109 ;
     RECT  37.128 9.155 38.592 9.877 ;
     RECT  67.512 9.203 68.832 10.405 ;
     RECT  11.928 9.347 13.008 9.827 ;
     RECT  13.656 9.395 14.88 10.643 ;
     RECT  19.224 9.493 20.304 10.453 ;
     RECT  65.688 9.827 66.96 11.987 ;
     RECT  37.608 9.877 38.592 10.645 ;
     RECT  32.52 10.069 33.888 12.515 ;
     RECT  30.984 10.115 32.16 11.509 ;
     RECT  11.4 10.307 11.448 11.365 ;
     RECT  58.68 10.307 59.664 11.893 ;
     RECT  20.328 10.355 20.568 11.509 ;
     RECT  19.224 10.453 20.208 10.885 ;
     RECT  13.608 10.643 14.88 11.987 ;
     RECT  43.368 10.883 44.784 11.459 ;
     RECT  60.504 11.171 61.584 11.555 ;
     RECT  11.688 11.365 13.008 12.035 ;
     RECT  40.68 11.365 42.096 11.461 ;
     RECT  42.12 11.459 43.344 12.517 ;
     RECT  48.024 11.459 49.536 12.515 ;
     RECT  41.016 11.461 42.096 12.179 ;
     RECT  60.504 11.555 61.8 12.131 ;
     RECT  13.512 11.987 14.88 12.851 ;
     RECT  11.064 12.035 13.008 12.517 ;
     RECT  15.768 12.035 15.816 12.901 ;
     RECT  59.544 12.131 59.88 13.621 ;
     RECT  30.984 12.179 31.968 12.611 ;
     RECT  40.776 12.179 42.096 13.285 ;
     RECT  39 12.371 40.08 14.677 ;
     RECT  32.52 12.515 34.32 12.659 ;
     RECT  11.064 12.517 12.048 13.715 ;
     RECT  30.552 12.611 31.968 16.499 ;
     RECT  32.424 12.659 34.32 12.995 ;
     RECT  49.56 12.803 50.88 13.283 ;
     RECT  15.768 12.901 16.848 12.947 ;
     RECT  16.872 12.901 18.144 14.197 ;
     RECT  15.984 12.947 16.848 13.909 ;
     RECT  32.184 12.995 34.32 13.621 ;
     RECT  49.56 13.283 51 15.829 ;
     RECT  53.88 13.283 54.912 14.579 ;
     RECT  40.968 13.285 42.096 14.101 ;
     RECT  38.448 13.523 38.784 14.629 ;
     RECT  32.184 13.621 33.312 14.341 ;
     RECT  33.336 13.621 34.32 17.029 ;
     RECT  11.064 13.715 12.624 14.197 ;
     RECT  51.312 14.099 52.368 14.867 ;
     RECT  11.352 14.197 12.624 14.867 ;
     RECT  53.88 14.579 53.928 14.581 ;
     RECT  32.28 14.819 33.312 16.595 ;
     RECT  11.112 14.867 12.624 15.637 ;
     RECT  16.272 14.867 16.848 15.829 ;
     RECT  39.048 14.867 40.08 16.405 ;
     RECT  51.312 14.867 52.416 15.683 ;
     RECT  42.84 14.965 43.92 15.973 ;
     RECT  2.808 15.443 4.32 15.491 ;
     RECT  11.112 15.637 12.24 16.019 ;
     RECT  37.368 15.683 38.352 17.171 ;
     RECT  51.312 15.683 52.752 18.133 ;
     RECT  35.352 15.829 36.768 17.699 ;
     RECT  49.56 15.829 50.88 17.123 ;
     RECT  10.728 16.019 12.24 16.453 ;
     RECT  4.92 16.115 5.952 16.691 ;
     RECT  38.376 16.451 39.36 17.171 ;
     RECT  10.728 16.453 11.712 17.077 ;
     RECT  29.712 16.499 31.968 16.501 ;
     RECT  29.712 16.501 30.816 18.133 ;
     RECT  30.84 16.501 31.968 17.605 ;
     RECT  32.04 16.595 33.312 17.557 ;
     RECT  5.664 16.691 5.952 17.077 ;
     RECT  53.88 17.077 55.104 18.181 ;
     RECT  49.56 17.123 51 20.677 ;
     RECT  5.688 17.171 6.864 17.603 ;
     RECT  37.368 17.171 39.36 17.843 ;
     RECT  32.184 17.557 33.312 18.707 ;
     RECT  5.688 17.603 7.2 18.275 ;
     RECT  43.944 17.653 45.36 19.285 ;
     RECT  33.432 17.699 34.8 18.851 ;
     RECT  38.064 17.843 39.36 18.565 ;
     RECT  29.832 18.133 30.816 18.179 ;
     RECT  51.312 18.133 52.512 19.475 ;
     RECT  29.832 18.179 31.008 20.245 ;
     RECT  53.88 18.181 54.864 18.995 ;
     RECT  42.552 18.323 43.92 19.715 ;
     RECT  38.088 18.565 39.36 18.995 ;
     RECT  32.184 18.707 33.408 18.851 ;
     RECT  25.272 18.851 26.736 20.051 ;
     RECT  32.184 18.851 33.24 20.149 ;
     RECT  54.72 18.995 54.864 19.861 ;
     RECT  43.944 19.285 45.264 19.573 ;
     RECT  29.184 19.427 29.28 20.293 ;
     RECT  51.312 19.475 52.752 20.723 ;
     RECT  43.944 19.573 44.976 19.715 ;
     RECT  42.552 19.715 44.976 20.677 ;
     RECT  32.184 20.149 33.216 20.579 ;
     RECT  27.768 20.293 29.28 20.339 ;
     RECT  29.712 20.387 31.008 22.453 ;
     RECT  31.992 20.579 33.216 21.347 ;
     RECT  42.552 20.677 43.728 21.301 ;
     RECT  43.752 20.677 44.976 21.541 ;
     RECT  49.56 20.677 50.832 21.157 ;
     RECT  51.312 20.723 53.04 20.963 ;
     RECT  51.312 20.963 53.064 21.109 ;
     RECT  36.168 21.013 37.632 21.061 ;
     RECT  36.168 21.061 37.296 22.259 ;
     RECT  51.432 21.109 53.064 21.445 ;
     RECT  5.736 21.155 7.392 21.683 ;
     RECT  37.32 21.155 37.656 21.685 ;
     RECT  19.08 21.395 20.304 23.509 ;
     RECT  51.48 21.445 53.064 21.541 ;
     RECT  62.112 21.493 63.216 25.237 ;
     RECT  10.248 21.541 11.328 22.597 ;
     RECT  51.48 21.541 53.568 22.021 ;
     RECT  53.592 21.541 54.72 21.779 ;
     RECT  5.736 21.683 5.928 22.213 ;
     RECT  37.32 21.685 38.784 21.971 ;
     RECT  38.808 21.685 39.792 21.971 ;
     RECT  41.4 21.779 42.528 22.741 ;
     RECT  53.592 21.779 54.768 22.741 ;
     RECT  39.024 21.971 39.792 22.549 ;
     RECT  49.056 21.971 49.536 23.125 ;
     RECT  52.44 22.021 53.568 23.125 ;
     RECT  26.76 22.165 27.744 22.787 ;
     RECT  35.928 22.259 37.296 22.645 ;
     RECT  8.904 22.307 10.08 23.459 ;
     RECT  51.432 22.547 52.416 23.845 ;
     RECT  35.928 22.645 37.248 23.459 ;
     RECT  67.512 22.645 68.976 23.653 ;
     RECT  41.496 22.741 42.528 23.411 ;
     RECT  53.64 22.741 54.768 22.787 ;
     RECT  26.976 22.787 27.744 22.835 ;
     RECT  53.64 22.787 54.864 23.555 ;
     RECT  26.976 22.835 27.384 23.317 ;
     RECT  44.136 23.123 45.264 24.181 ;
     RECT  46.584 23.125 48.096 24.227 ;
     RECT  48.12 23.125 49.536 24.469 ;
     RECT  31.032 23.315 32.16 26.197 ;
     RECT  5.928 23.317 7.344 23.365 ;
     RECT  41.4 23.411 42.528 24.707 ;
     RECT  35.928 23.459 37.224 23.701 ;
     RECT  67.8 23.653 68.976 23.699 ;
     RECT  35.928 23.701 37.2 24.373 ;
     RECT  39.048 23.843 40.2 25.139 ;
     RECT  10.248 24.083 11.328 24.563 ;
     RECT  20.952 24.133 22.176 24.565 ;
     RECT  48 24.227 48.096 24.469 ;
     RECT  35.976 24.373 37.2 24.707 ;
     RECT  4.536 24.421 5.712 25.715 ;
     RECT  13.512 24.469 14.688 25.139 ;
     RECT  48.12 24.469 49.488 25.715 ;
     RECT  6.504 24.563 7.584 24.611 ;
     RECT  10.08 24.563 10.224 25.045 ;
     RECT  6.264 24.611 7.584 24.803 ;
     RECT  19.368 24.611 20.784 24.947 ;
     RECT  7.344 24.803 7.584 26.149 ;
     RECT  37.944 24.997 39.024 25.139 ;
     RECT  8.712 25.045 10.224 26.579 ;
     RECT  22.2 25.045 23.52 25.475 ;
     RECT  12.168 25.187 13.2 26.291 ;
     RECT  62.232 25.237 63.216 26.147 ;
     RECT  29.976 25.283 31.008 26.819 ;
     RECT  48.024 25.715 49.488 27.923 ;
     RECT  7.344 26.149 7.536 26.197 ;
     RECT  2.712 26.243 2.856 26.629 ;
     RECT  8.112 26.579 8.328 27.781 ;
     RECT  2.712 26.629 3.744 26.771 ;
     RECT  2.712 26.771 3.768 27.205 ;
     RECT  29.712 26.819 31.008 26.867 ;
     RECT  41.208 26.869 42.528 27.731 ;
     RECT  2.712 27.205 3.792 27.923 ;
     RECT  32.184 27.205 33.6 28.931 ;
     RECT  33.624 27.205 34.8 28.931 ;
     RECT  48.024 27.923 50.352 28.453 ;
     RECT  48.936 28.453 50.352 28.885 ;
     RECT  52.104 28.643 53.232 29.411 ;
     RECT  26.52 28.837 27.84 29.651 ;
     RECT  48.936 28.885 50.208 29.027 ;
     RECT  32.184 28.931 34.8 28.933 ;
     RECT  6.312 28.933 7.344 30.179 ;
     RECT  32.52 28.933 34.8 29.509 ;
     RECT  48.936 29.027 50.448 29.029 ;
     RECT  49.032 29.029 50.448 29.507 ;
     RECT  48.024 29.075 49.008 29.507 ;
     RECT  51.96 29.411 53.232 30.421 ;
     RECT  48.024 29.507 48.36 30.805 ;
     RECT  50.304 29.507 50.448 30.757 ;
     RECT  33.288 29.509 34.8 30.275 ;
     RECT  46.104 29.509 47.28 29.749 ;
     RECT  38.952 29.605 40.08 30.707 ;
     RECT  41.496 30.037 42.528 30.083 ;
     RECT  38.208 30.083 38.928 30.229 ;
     RECT  41.496 30.083 42.72 31.139 ;
     RECT  37.8 30.229 38.928 31.381 ;
     RECT  36.456 30.517 37.776 31.427 ;
     RECT  35.304 30.563 36.432 30.899 ;
     RECT  38.952 30.707 40.2 33.251 ;
     RECT  53.4 30.853 54.672 31.333 ;
     RECT  35.112 30.899 36.432 31.861 ;
     RECT  46.824 31.283 48 33.013 ;
     RECT  53.64 31.333 54.672 32.531 ;
     RECT  3.576 31.379 5.184 32.773 ;
     RECT  31.344 31.379 32.16 31.573 ;
     RECT  19.368 31.477 20.544 31.523 ;
     RECT  30.648 31.573 32.16 32.195 ;
     RECT  24.792 31.621 26.208 34.931 ;
     RECT  66.168 31.765 67.2 31.955 ;
     RECT  6.264 31.861 7.344 32.869 ;
     RECT  51.912 32.579 53.04 33.587 ;
     RECT  3.96 32.773 5.184 33.541 ;
     RECT  48.84 33.061 50.304 33.589 ;
     RECT  3.96 33.541 4.944 33.925 ;
     RECT  51.864 33.587 53.04 34.259 ;
     RECT  48.84 33.589 49.92 34.499 ;
     RECT  55.296 34.211 55.824 34.741 ;
     RECT  48.6 34.499 49.92 35.363 ;
     RECT  16.056 34.739 16.2 35.845 ;
     RECT  54.456 34.741 55.824 34.979 ;
     RECT  24.792 34.931 26.232 35.077 ;
     RECT  24.792 35.077 27.36 35.557 ;
     RECT  24.792 35.557 25.824 36.467 ;
     RECT  25.848 35.557 27.36 36.467 ;
     RECT  12.168 35.941 13.2 41.365 ;
     RECT  24.792 36.467 24.936 37.621 ;
     RECT  46.68 36.515 48 37.573 ;
     RECT  8.328 36.805 9.312 37.573 ;
     RECT  10.68 36.901 12.144 37.621 ;
     RECT  48.6 37.237 49.584 38.005 ;
     RECT  46.824 37.573 48 38.195 ;
     RECT  10.968 37.621 12.144 38.149 ;
     RECT  43.296 37.859 43.824 37.957 ;
     RECT  42.408 37.957 43.824 42.803 ;
     RECT  37.056 38.003 37.08 39.157 ;
     RECT  11.112 38.149 12.144 38.677 ;
     RECT  46.824 38.195 48.048 39.877 ;
     RECT  51.432 38.677 52.704 39.781 ;
     RECT  52.728 38.677 54 40.165 ;
     RECT  35.592 39.205 37.056 40.259 ;
     RECT  24.936 39.253 26.064 39.971 ;
     RECT  46.824 39.877 48 41.797 ;
     RECT  24.936 39.971 26.088 40.405 ;
     RECT  53.016 40.165 54 43.907 ;
     RECT  18.912 40.213 19.92 40.261 ;
     RECT  24.936 40.405 26.352 42.803 ;
     RECT  0.216 40.499 0.264 41.941 ;
     RECT  18.912 41.651 19.92 41.699 ;
     RECT  0.144 41.939 0.192 42.323 ;
     RECT  0.144 42.323 0.168 42.949 ;
     RECT  14.856 42.325 16.032 45.973 ;
     RECT  43.848 42.515 44.976 42.803 ;
     RECT  33.816 43.669 34.8 48.805 ;
     RECT  52.776 43.907 54 46.309 ;
     RECT  40.92 44.437 42.384 48.131 ;
     RECT  46.728 44.483 48.144 47.845 ;
     RECT  23.376 45.059 24 46.309 ;
     RECT  58.104 45.157 59.52 46.163 ;
     RECT  0.144 45.203 0.168 45.781 ;
     RECT  12.168 45.203 13.2 45.971 ;
     RECT  17.352 45.541 18.6 46.597 ;
     RECT  37.752 45.733 38.88 50.005 ;
     RECT  38.904 45.733 40.2 46.645 ;
     RECT  0.144 45.781 0.192 46.597 ;
     RECT  15 45.973 16.032 46.261 ;
     RECT  13.944 46.115 14.976 55.139 ;
     RECT  67.512 46.547 67.992 47.845 ;
     RECT  60.216 46.789 61.584 47.749 ;
     RECT  10.248 47.363 11.256 47.797 ;
     RECT  17.064 47.795 18.24 48.419 ;
     RECT  10.248 47.797 11.616 48.853 ;
     RECT  46.728 47.845 48.048 48.995 ;
     RECT  38.904 47.891 40.2 50.101 ;
     RECT  52.296 47.891 53.328 55.765 ;
     RECT  59.88 47.891 60.96 48.419 ;
     RECT  40.68 48.131 42.384 49.333 ;
     RECT  17.016 48.419 18.24 50.435 ;
     RECT  61.488 48.419 61.68 49.909 ;
     RECT  0.408 48.563 0.552 50.005 ;
     RECT  22.2 48.805 23.328 49.619 ;
     RECT  10.392 48.853 11.616 49.043 ;
     RECT  46.632 48.995 48.048 52.787 ;
     RECT  10.248 49.043 11.616 49.235 ;
     RECT  10.248 49.235 11.016 50.389 ;
     RECT  41.064 49.333 42.384 50.579 ;
     RECT  17.016 50.435 18.48 51.925 ;
     RECT  0.144 50.579 0.192 51.877 ;
     RECT  42.144 50.579 42.384 51.829 ;
     RECT  29.712 50.629 30.816 52.307 ;
     RECT  44.088 51.253 45.6 52.163 ;
     RECT  15.096 51.347 16.368 52.019 ;
     RECT  37.896 51.347 38.928 53.603 ;
     RECT  38.952 51.395 40.2 53.603 ;
     RECT  11.016 51.781 12.048 52.789 ;
     RECT  12.072 51.781 13.2 55.141 ;
     RECT  17.016 51.925 18 52.357 ;
     RECT  15 52.019 16.368 54.899 ;
     RECT  40.512 52.117 42 60.275 ;
     RECT  9.96 52.307 10.992 53.365 ;
     RECT  59.808 52.451 59.832 52.981 ;
     RECT  67.512 52.451 67.992 53.557 ;
     RECT  0.216 52.595 0.312 53.797 ;
     RECT  62.52 52.645 63.888 53.075 ;
     RECT  59.808 52.981 59.856 53.941 ;
     RECT  66.168 52.981 67.2 54.179 ;
     RECT  62.52 53.075 63.048 53.125 ;
     RECT  16.968 53.603 18 54.661 ;
     RECT  58.104 53.941 59.472 56.389 ;
     RECT  24.312 54.083 24.408 55.429 ;
     RECT  44.088 54.085 45.6 56.149 ;
     RECT  54.024 54.131 54.408 55.429 ;
     RECT  9.96 54.179 10.992 55.525 ;
     RECT  45.912 54.371 46.008 55.525 ;
     RECT  13.944 55.139 14.136 56.245 ;
     RECT  12.12 55.141 13.2 59.987 ;
     RECT  54.984 55.429 56.4 57.589 ;
     RECT  42.792 55.525 44.064 56.195 ;
     RECT  48.6 55.957 49.968 57.541 ;
     RECT  42.792 56.195 44.928 57.445 ;
     RECT  24.408 56.389 25.92 57.059 ;
     RECT  25.944 56.389 26.928 58.691 ;
     RECT  58.104 56.389 59.424 56.485 ;
     RECT  58.152 56.485 59.424 57.059 ;
     RECT  49.992 56.531 51 58.453 ;
     RECT  62.112 56.965 63.504 59.315 ;
     RECT  58.104 57.059 59.424 57.875 ;
     RECT  59.88 57.205 61.104 57.251 ;
     RECT  46.008 57.443 46.056 57.635 ;
     RECT  42.888 57.445 44.928 57.589 ;
     RECT  48.6 57.541 49.824 58.693 ;
     RECT  43.368 57.589 44.928 57.637 ;
     RECT  45.912 57.635 46.056 58.021 ;
     RECT  54.024 57.635 55.536 59.221 ;
     RECT  43.896 57.637 44.928 59.315 ;
     RECT  45.912 58.021 47.424 58.499 ;
     RECT  37.368 58.117 38.64 58.691 ;
     RECT  2.304 58.643 2.4 60.085 ;
     RECT  35.208 58.645 36.72 59.459 ;
     RECT  25.944 58.691 27.6 59.845 ;
     RECT  48.6 58.693 49.776 59.987 ;
     RECT  59.832 59.173 61.104 59.219 ;
     RECT  43.896 59.315 44.976 60.373 ;
     RECT  35.112 59.459 36.72 60.661 ;
     RECT  26.328 59.845 27.6 62.101 ;
     RECT  10.248 59.891 11.376 61.043 ;
     RECT  48.6 59.987 49.968 61.187 ;
     RECT  31.944 60.133 33.072 60.901 ;
     RECT  43.992 60.373 44.976 62.149 ;
     RECT  55.128 60.419 56.4 62.101 ;
     RECT  35.112 60.661 36.528 63.779 ;
     RECT  24.312 60.853 25.824 62.629 ;
     RECT  31.944 60.901 33.024 61.907 ;
     RECT  47.064 60.949 48.384 60.995 ;
     RECT  47.064 60.995 48.576 61.187 ;
     RECT  33.768 61.043 34.8 66.085 ;
     RECT  54.12 61.235 55.104 62.483 ;
     RECT  31.944 61.907 33.072 64.883 ;
     RECT  26.616 62.101 27.6 62.147 ;
     RECT  55.272 62.101 56.4 63.299 ;
     RECT  40.776 62.149 42.288 62.723 ;
     RECT  60.408 62.149 61.8 63.299 ;
     RECT  6.024 62.195 7.488 62.243 ;
     RECT  5.832 62.243 5.88 63.205 ;
     RECT  7.44 62.243 7.488 63.157 ;
     RECT  24.312 62.629 25.344 63.683 ;
     RECT  4.536 62.675 5.568 62.771 ;
     RECT  4.296 62.771 5.568 62.819 ;
     RECT  44.328 62.771 45.6 63.299 ;
     RECT  42.888 63.155 44.16 64.357 ;
     RECT  49.56 63.251 50.88 64.837 ;
     RECT  44.184 63.299 45.6 65.941 ;
     RECT  8.232 63.347 9.36 63.635 ;
     RECT  24.312 63.683 25.632 64.115 ;
     RECT  24.312 64.115 25.92 65.269 ;
     RECT  42.888 64.357 43.92 66.515 ;
     RECT  49.008 64.787 49.488 65.797 ;
     RECT  31.944 64.883 33.744 65.509 ;
     RECT  24.312 65.269 25.44 68.531 ;
     RECT  5.88 65.461 7.344 65.509 ;
     RECT  6.264 65.509 7.344 65.797 ;
     RECT  32.328 65.509 33.744 67.955 ;
     RECT  9.816 65.605 10.944 66.515 ;
     RECT  49.56 65.699 50.64 65.939 ;
     RECT  49.512 65.939 50.64 66.755 ;
     RECT  44.184 65.941 45.456 66.275 ;
     RECT  44.04 66.275 45.456 67.283 ;
     RECT  9.816 66.515 10.992 66.755 ;
     RECT  42.888 66.515 44.016 68.917 ;
     RECT  17.352 66.613 18.6 67.331 ;
     RECT  33.768 66.707 34.8 68.341 ;
     RECT  49.272 66.755 50.64 67.909 ;
     RECT  35.544 67.141 37.056 67.859 ;
     RECT  6.552 67.187 7.8 68.387 ;
     RECT  44.04 67.283 45.6 67.717 ;
     RECT  44.136 67.717 45.6 67.765 ;
     RECT  44.232 67.765 45.6 68.341 ;
     RECT  35.112 68.147 35.544 69.493 ;
     RECT  44.52 68.341 45.6 69.971 ;
     RECT  48.408 69.347 49.488 71.027 ;
     RECT  35.112 69.493 36.48 70.931 ;
     RECT  44.472 69.971 45.6 72.995 ;
     RECT  48.408 71.027 49.584 71.315 ;
     RECT  44.04 72.995 45.6 73.463 ;
     RECT  44.04 73.463 44.136 74.341 ;
  END
END ot_hgi_dma_back_static_vp4_controller
END LIBRARY
